VERSION 5.8 ;
BUSBITCHARS "[]" ;
DIVIDERCHAR "/" ;
UNITS
    DATABASE MICRONS 1000 ;
END UNITS

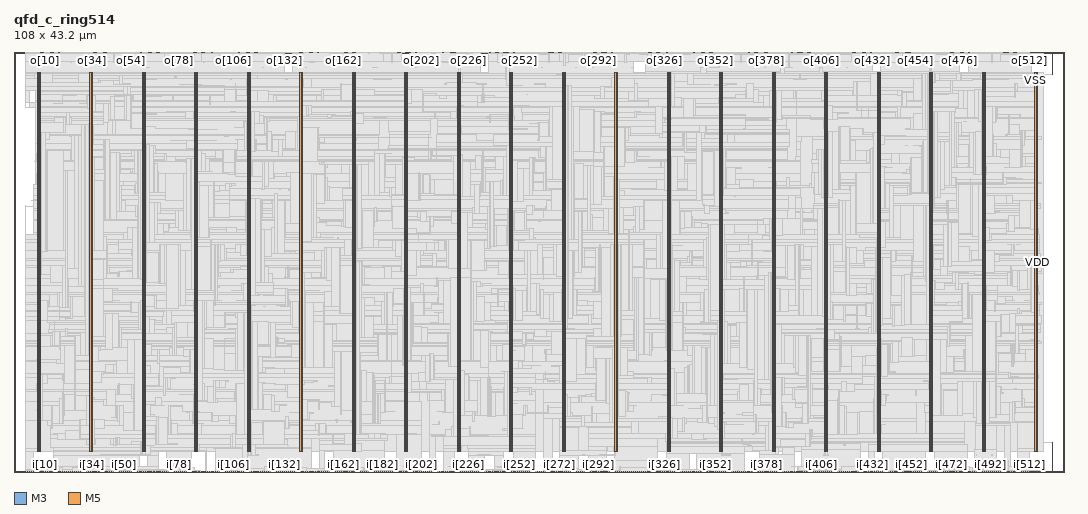
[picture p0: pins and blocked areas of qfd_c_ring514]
MACRO qfd_c_ring514
  FOREIGN qfd_c_ring514 0 0 ;
  CLASS BLOCK ;
  SIZE 108 BY 43.2 ;
  PIN ck_r
    DIRECTION INPUT ;
    USE SIGNAL ;
    PORT
      LAYER M3 ;
        RECT  105.984 43.162 106.002 43.2 ;
    END
    PORT
      LAYER M3 ;
        RECT  105.984 43.051 106.002 43.181 ;
    END
  END ck_r
  PIN ck_w
    DIRECTION INPUT ;
    USE SIGNAL ;
    PORT
      LAYER M3 ;
        RECT  105.984 0 106.002 0.038 ;
    END
    PORT
      LAYER M3 ;
        RECT  105.984 0.012 106.002 0.173 ;
    END
  END ck_w
  PIN i[0]
    DIRECTION INPUT ;
    USE SIGNAL ;
    PORT
      LAYER M3 ;
        RECT  1.188 0 1.206 0.038 ;
    END
  END i[0]
  PIN i[100]
    DIRECTION INPUT ;
    USE SIGNAL ;
    PORT
      LAYER M3 ;
        RECT  21.348 0 21.366 0.038 ;
    END
  END i[100]
  PIN i[101]
    DIRECTION INPUT ;
    USE SIGNAL ;
    PORT
      LAYER M5 ;
        RECT  21.552 0 21.576 0.084 ;
    END
  END i[101]
  PIN i[102]
    DIRECTION INPUT ;
    USE SIGNAL ;
    PORT
      LAYER M3 ;
        RECT  21.744 0 21.762 0.038 ;
    END
  END i[102]
  PIN i[103]
    DIRECTION INPUT ;
    USE SIGNAL ;
    PORT
      LAYER M5 ;
        RECT  21.936 0 21.96 0.084 ;
    END
  END i[103]
  PIN i[104]
    DIRECTION INPUT ;
    USE SIGNAL ;
    PORT
      LAYER M3 ;
        RECT  22.14 0 22.158 0.038 ;
    END
  END i[104]
  PIN i[105]
    DIRECTION INPUT ;
    USE SIGNAL ;
    PORT
      LAYER M5 ;
        RECT  22.368 0 22.392 0.084 ;
    END
  END i[105]
  PIN i[106]
    DIRECTION INPUT ;
    USE SIGNAL ;
    PORT
      LAYER M3 ;
        RECT  22.536 0 22.554 0.038 ;
    END
  END i[106]
  PIN i[107]
    DIRECTION INPUT ;
    USE SIGNAL ;
    PORT
      LAYER M5 ;
        RECT  22.752 0 22.776 0.084 ;
    END
  END i[107]
  PIN i[108]
    DIRECTION INPUT ;
    USE SIGNAL ;
    PORT
      LAYER M3 ;
        RECT  22.968 0 22.986 0.038 ;
    END
  END i[108]
  PIN i[109]
    DIRECTION INPUT ;
    USE SIGNAL ;
    PORT
      LAYER M5 ;
        RECT  23.136 0 23.16 0.084 ;
    END
  END i[109]
  PIN i[10]
    DIRECTION INPUT ;
    USE SIGNAL ;
    PORT
      LAYER M3 ;
        RECT  3.204 0 3.222 0.038 ;
    END
  END i[10]
  PIN i[110]
    DIRECTION INPUT ;
    USE SIGNAL ;
    PORT
      LAYER M3 ;
        RECT  23.364 0 23.382 0.038 ;
    END
  END i[110]
  PIN i[111]
    DIRECTION INPUT ;
    USE SIGNAL ;
    PORT
      LAYER M5 ;
        RECT  23.568 0 23.592 0.084 ;
    END
  END i[111]
  PIN i[112]
    DIRECTION INPUT ;
    USE SIGNAL ;
    PORT
      LAYER M3 ;
        RECT  23.76 0 23.778 0.038 ;
    END
  END i[112]
  PIN i[113]
    DIRECTION INPUT ;
    USE SIGNAL ;
    PORT
      LAYER M5 ;
        RECT  23.952 0 23.976 0.084 ;
    END
  END i[113]
  PIN i[114]
    DIRECTION INPUT ;
    USE SIGNAL ;
    PORT
      LAYER M3 ;
        RECT  24.156 0 24.174 0.038 ;
    END
  END i[114]
  PIN i[115]
    DIRECTION INPUT ;
    USE SIGNAL ;
    PORT
      LAYER M5 ;
        RECT  24.384 0 24.408 0.084 ;
    END
  END i[115]
  PIN i[116]
    DIRECTION INPUT ;
    USE SIGNAL ;
    PORT
      LAYER M3 ;
        RECT  24.588 0 24.606 0.038 ;
    END
  END i[116]
  PIN i[117]
    DIRECTION INPUT ;
    USE SIGNAL ;
    PORT
      LAYER M5 ;
        RECT  24.768 0 24.792 0.084 ;
    END
  END i[117]
  PIN i[118]
    DIRECTION INPUT ;
    USE SIGNAL ;
    PORT
      LAYER M3 ;
        RECT  24.984 0 25.002 0.038 ;
    END
  END i[118]
  PIN i[119]
    DIRECTION INPUT ;
    USE SIGNAL ;
    PORT
      LAYER M5 ;
        RECT  25.152 0 25.176 0.084 ;
    END
  END i[119]
  PIN i[11]
    DIRECTION INPUT ;
    USE SIGNAL ;
    PORT
      LAYER M5 ;
        RECT  3.408 0 3.432 0.084 ;
    END
  END i[11]
  PIN i[120]
    DIRECTION INPUT ;
    USE SIGNAL ;
    PORT
      LAYER M3 ;
        RECT  25.38 0 25.398 0.038 ;
    END
  END i[120]
  PIN i[121]
    DIRECTION INPUT ;
    USE SIGNAL ;
    PORT
      LAYER M5 ;
        RECT  25.584 0 25.608 0.084 ;
    END
  END i[121]
  PIN i[122]
    DIRECTION INPUT ;
    USE SIGNAL ;
    PORT
      LAYER M3 ;
        RECT  25.776 0 25.794 0.038 ;
    END
  END i[122]
  PIN i[123]
    DIRECTION INPUT ;
    USE SIGNAL ;
    PORT
      LAYER M5 ;
        RECT  25.968 0 25.992 0.084 ;
    END
  END i[123]
  PIN i[124]
    DIRECTION INPUT ;
    USE SIGNAL ;
    PORT
      LAYER M3 ;
        RECT  26.172 0 26.19 0.038 ;
    END
  END i[124]
  PIN i[125]
    DIRECTION INPUT ;
    USE SIGNAL ;
    PORT
      LAYER M5 ;
        RECT  26.4 0 26.424 0.084 ;
    END
  END i[125]
  PIN i[126]
    DIRECTION INPUT ;
    USE SIGNAL ;
    PORT
      LAYER M3 ;
        RECT  26.604 0 26.622 0.038 ;
    END
  END i[126]
  PIN i[127]
    DIRECTION INPUT ;
    USE SIGNAL ;
    PORT
      LAYER M5 ;
        RECT  26.784 0 26.808 0.084 ;
    END
  END i[127]
  PIN i[128]
    DIRECTION INPUT ;
    USE SIGNAL ;
    PORT
      LAYER M3 ;
        RECT  27 0 27.018 0.038 ;
    END
  END i[128]
  PIN i[129]
    DIRECTION INPUT ;
    USE SIGNAL ;
    PORT
      LAYER M5 ;
        RECT  27.168 0 27.192 0.084 ;
    END
  END i[129]
  PIN i[12]
    DIRECTION INPUT ;
    USE SIGNAL ;
    PORT
      LAYER M3 ;
        RECT  3.6 0 3.618 0.038 ;
    END
  END i[12]
  PIN i[130]
    DIRECTION INPUT ;
    USE SIGNAL ;
    PORT
      LAYER M3 ;
        RECT  27.396 0 27.414 0.038 ;
    END
  END i[130]
  PIN i[131]
    DIRECTION INPUT ;
    USE SIGNAL ;
    PORT
      LAYER M5 ;
        RECT  27.6 0 27.624 0.084 ;
    END
  END i[131]
  PIN i[132]
    DIRECTION INPUT ;
    USE SIGNAL ;
    PORT
      LAYER M3 ;
        RECT  27.792 0 27.81 0.038 ;
    END
  END i[132]
  PIN i[133]
    DIRECTION INPUT ;
    USE SIGNAL ;
    PORT
      LAYER M5 ;
        RECT  27.984 0 28.008 0.084 ;
    END
  END i[133]
  PIN i[134]
    DIRECTION INPUT ;
    USE SIGNAL ;
    PORT
      LAYER M3 ;
        RECT  28.188 0 28.206 0.038 ;
    END
  END i[134]
  PIN i[135]
    DIRECTION INPUT ;
    USE SIGNAL ;
    PORT
      LAYER M5 ;
        RECT  28.416 0 28.44 0.084 ;
    END
  END i[135]
  PIN i[136]
    DIRECTION INPUT ;
    USE SIGNAL ;
    PORT
      LAYER M3 ;
        RECT  28.62 0 28.638 0.038 ;
    END
  END i[136]
  PIN i[137]
    DIRECTION INPUT ;
    USE SIGNAL ;
    PORT
      LAYER M5 ;
        RECT  28.8 0 28.824 0.084 ;
    END
  END i[137]
  PIN i[138]
    DIRECTION INPUT ;
    USE SIGNAL ;
    PORT
      LAYER M3 ;
        RECT  29.016 0 29.034 0.038 ;
    END
  END i[138]
  PIN i[139]
    DIRECTION INPUT ;
    USE SIGNAL ;
    PORT
      LAYER M5 ;
        RECT  29.184 0 29.208 0.084 ;
    END
  END i[139]
  PIN i[13]
    DIRECTION INPUT ;
    USE SIGNAL ;
    PORT
      LAYER M5 ;
        RECT  3.792 0 3.816 0.084 ;
    END
  END i[13]
  PIN i[140]
    DIRECTION INPUT ;
    USE SIGNAL ;
    PORT
      LAYER M3 ;
        RECT  29.412 0 29.43 0.038 ;
    END
  END i[140]
  PIN i[141]
    DIRECTION INPUT ;
    USE SIGNAL ;
    PORT
      LAYER M5 ;
        RECT  29.616 0 29.64 0.084 ;
    END
  END i[141]
  PIN i[142]
    DIRECTION INPUT ;
    USE SIGNAL ;
    PORT
      LAYER M3 ;
        RECT  29.808 0 29.826 0.038 ;
    END
  END i[142]
  PIN i[143]
    DIRECTION INPUT ;
    USE SIGNAL ;
    PORT
      LAYER M5 ;
        RECT  30 0 30.024 0.084 ;
    END
  END i[143]
  PIN i[144]
    DIRECTION INPUT ;
    USE SIGNAL ;
    PORT
      LAYER M3 ;
        RECT  30.204 0 30.222 0.038 ;
    END
  END i[144]
  PIN i[145]
    DIRECTION INPUT ;
    USE SIGNAL ;
    PORT
      LAYER M5 ;
        RECT  30.432 0 30.456 0.084 ;
    END
  END i[145]
  PIN i[146]
    DIRECTION INPUT ;
    USE SIGNAL ;
    PORT
      LAYER M3 ;
        RECT  30.636 0 30.654 0.038 ;
    END
  END i[146]
  PIN i[147]
    DIRECTION INPUT ;
    USE SIGNAL ;
    PORT
      LAYER M5 ;
        RECT  30.816 0 30.84 0.084 ;
    END
  END i[147]
  PIN i[148]
    DIRECTION INPUT ;
    USE SIGNAL ;
    PORT
      LAYER M3 ;
        RECT  31.032 0 31.05 0.038 ;
    END
  END i[148]
  PIN i[149]
    DIRECTION INPUT ;
    USE SIGNAL ;
    PORT
      LAYER M5 ;
        RECT  31.248 0 31.272 0.084 ;
    END
  END i[149]
  PIN i[14]
    DIRECTION INPUT ;
    USE SIGNAL ;
    PORT
      LAYER M3 ;
        RECT  3.996 0 4.014 0.038 ;
    END
  END i[14]
  PIN i[150]
    DIRECTION INPUT ;
    USE SIGNAL ;
    PORT
      LAYER M3 ;
        RECT  31.428 0 31.446 0.038 ;
    END
  END i[150]
  PIN i[151]
    DIRECTION INPUT ;
    USE SIGNAL ;
    PORT
      LAYER M5 ;
        RECT  31.632 0 31.656 0.084 ;
    END
  END i[151]
  PIN i[152]
    DIRECTION INPUT ;
    USE SIGNAL ;
    PORT
      LAYER M3 ;
        RECT  31.824 0 31.842 0.038 ;
    END
  END i[152]
  PIN i[153]
    DIRECTION INPUT ;
    USE SIGNAL ;
    PORT
      LAYER M5 ;
        RECT  32.016 0 32.04 0.084 ;
    END
  END i[153]
  PIN i[154]
    DIRECTION INPUT ;
    USE SIGNAL ;
    PORT
      LAYER M3 ;
        RECT  32.22 0 32.238 0.038 ;
    END
  END i[154]
  PIN i[155]
    DIRECTION INPUT ;
    USE SIGNAL ;
    PORT
      LAYER M5 ;
        RECT  32.448 0 32.472 0.084 ;
    END
  END i[155]
  PIN i[156]
    DIRECTION INPUT ;
    USE SIGNAL ;
    PORT
      LAYER M3 ;
        RECT  32.652 0 32.67 0.038 ;
    END
  END i[156]
  PIN i[157]
    DIRECTION INPUT ;
    USE SIGNAL ;
    PORT
      LAYER M5 ;
        RECT  32.832 0 32.856 0.084 ;
    END
  END i[157]
  PIN i[158]
    DIRECTION INPUT ;
    USE SIGNAL ;
    PORT
      LAYER M3 ;
        RECT  33.048 0 33.066 0.038 ;
    END
  END i[158]
  PIN i[159]
    DIRECTION INPUT ;
    USE SIGNAL ;
    PORT
      LAYER M5 ;
        RECT  33.264 0 33.288 0.084 ;
    END
  END i[159]
  PIN i[15]
    DIRECTION INPUT ;
    USE SIGNAL ;
    PORT
      LAYER M5 ;
        RECT  4.176 0 4.2 0.084 ;
    END
  END i[15]
  PIN i[160]
    DIRECTION INPUT ;
    USE SIGNAL ;
    PORT
      LAYER M3 ;
        RECT  33.444 0 33.462 0.038 ;
    END
  END i[160]
  PIN i[161]
    DIRECTION INPUT ;
    USE SIGNAL ;
    PORT
      LAYER M5 ;
        RECT  33.648 0 33.672 0.084 ;
    END
  END i[161]
  PIN i[162]
    DIRECTION INPUT ;
    USE SIGNAL ;
    PORT
      LAYER M3 ;
        RECT  33.84 0 33.858 0.038 ;
    END
  END i[162]
  PIN i[163]
    DIRECTION INPUT ;
    USE SIGNAL ;
    PORT
      LAYER M5 ;
        RECT  34.032 0 34.056 0.084 ;
    END
  END i[163]
  PIN i[164]
    DIRECTION INPUT ;
    USE SIGNAL ;
    PORT
      LAYER M3 ;
        RECT  34.236 0 34.254 0.038 ;
    END
  END i[164]
  PIN i[165]
    DIRECTION INPUT ;
    USE SIGNAL ;
    PORT
      LAYER M5 ;
        RECT  34.464 0 34.488 0.084 ;
    END
  END i[165]
  PIN i[166]
    DIRECTION INPUT ;
    USE SIGNAL ;
    PORT
      LAYER M3 ;
        RECT  34.668 0 34.686 0.038 ;
    END
  END i[166]
  PIN i[167]
    DIRECTION INPUT ;
    USE SIGNAL ;
    PORT
      LAYER M5 ;
        RECT  34.848 0 34.872 0.084 ;
    END
  END i[167]
  PIN i[168]
    DIRECTION INPUT ;
    USE SIGNAL ;
    PORT
      LAYER M3 ;
        RECT  35.064 0 35.082 0.038 ;
    END
  END i[168]
  PIN i[169]
    DIRECTION INPUT ;
    USE SIGNAL ;
    PORT
      LAYER M5 ;
        RECT  35.28 0 35.304 0.084 ;
    END
  END i[169]
  PIN i[16]
    DIRECTION INPUT ;
    USE SIGNAL ;
    PORT
      LAYER M3 ;
        RECT  4.392 0 4.41 0.038 ;
    END
  END i[16]
  PIN i[170]
    DIRECTION INPUT ;
    USE SIGNAL ;
    PORT
      LAYER M3 ;
        RECT  35.46 0 35.478 0.038 ;
    END
  END i[170]
  PIN i[171]
    DIRECTION INPUT ;
    USE SIGNAL ;
    PORT
      LAYER M5 ;
        RECT  35.664 0 35.688 0.084 ;
    END
  END i[171]
  PIN i[172]
    DIRECTION INPUT ;
    USE SIGNAL ;
    PORT
      LAYER M3 ;
        RECT  35.856 0 35.874 0.038 ;
    END
  END i[172]
  PIN i[173]
    DIRECTION INPUT ;
    USE SIGNAL ;
    PORT
      LAYER M5 ;
        RECT  36.048 0 36.072 0.084 ;
    END
  END i[173]
  PIN i[174]
    DIRECTION INPUT ;
    USE SIGNAL ;
    PORT
      LAYER M3 ;
        RECT  36.288 0 36.306 0.038 ;
    END
  END i[174]
  PIN i[175]
    DIRECTION INPUT ;
    USE SIGNAL ;
    PORT
      LAYER M5 ;
        RECT  36.48 0 36.504 0.084 ;
    END
  END i[175]
  PIN i[176]
    DIRECTION INPUT ;
    USE SIGNAL ;
    PORT
      LAYER M3 ;
        RECT  36.684 0 36.702 0.038 ;
    END
  END i[176]
  PIN i[177]
    DIRECTION INPUT ;
    USE SIGNAL ;
    PORT
      LAYER M5 ;
        RECT  36.864 0 36.888 0.084 ;
    END
  END i[177]
  PIN i[178]
    DIRECTION INPUT ;
    USE SIGNAL ;
    PORT
      LAYER M3 ;
        RECT  37.08 0 37.098 0.038 ;
    END
  END i[178]
  PIN i[179]
    DIRECTION INPUT ;
    USE SIGNAL ;
    PORT
      LAYER M5 ;
        RECT  37.296 0 37.32 0.084 ;
    END
  END i[179]
  PIN i[17]
    DIRECTION INPUT ;
    USE SIGNAL ;
    PORT
      LAYER M5 ;
        RECT  4.608 0 4.632 0.084 ;
    END
  END i[17]
  PIN i[180]
    DIRECTION INPUT ;
    USE SIGNAL ;
    PORT
      LAYER M3 ;
        RECT  37.476 0 37.494 0.038 ;
    END
  END i[180]
  PIN i[181]
    DIRECTION INPUT ;
    USE SIGNAL ;
    PORT
      LAYER M5 ;
        RECT  37.68 0 37.704 0.084 ;
    END
  END i[181]
  PIN i[182]
    DIRECTION INPUT ;
    USE SIGNAL ;
    PORT
      LAYER M3 ;
        RECT  37.872 0 37.89 0.038 ;
    END
  END i[182]
  PIN i[183]
    DIRECTION INPUT ;
    USE SIGNAL ;
    PORT
      LAYER M5 ;
        RECT  38.064 0 38.088 0.084 ;
    END
  END i[183]
  PIN i[184]
    DIRECTION INPUT ;
    USE SIGNAL ;
    PORT
      LAYER M3 ;
        RECT  38.304 0 38.322 0.038 ;
    END
  END i[184]
  PIN i[185]
    DIRECTION INPUT ;
    USE SIGNAL ;
    PORT
      LAYER M5 ;
        RECT  38.496 0 38.52 0.084 ;
    END
  END i[185]
  PIN i[186]
    DIRECTION INPUT ;
    USE SIGNAL ;
    PORT
      LAYER M3 ;
        RECT  38.7 0 38.718 0.038 ;
    END
  END i[186]
  PIN i[187]
    DIRECTION INPUT ;
    USE SIGNAL ;
    PORT
      LAYER M5 ;
        RECT  38.88 0 38.904 0.084 ;
    END
  END i[187]
  PIN i[188]
    DIRECTION INPUT ;
    USE SIGNAL ;
    PORT
      LAYER M3 ;
        RECT  39.096 0 39.114 0.038 ;
    END
  END i[188]
  PIN i[189]
    DIRECTION INPUT ;
    USE SIGNAL ;
    PORT
      LAYER M5 ;
        RECT  39.312 0 39.336 0.084 ;
    END
  END i[189]
  PIN i[18]
    DIRECTION INPUT ;
    USE SIGNAL ;
    PORT
      LAYER M3 ;
        RECT  4.788 0 4.806 0.038 ;
    END
  END i[18]
  PIN i[190]
    DIRECTION INPUT ;
    USE SIGNAL ;
    PORT
      LAYER M3 ;
        RECT  39.492 0 39.51 0.038 ;
    END
  END i[190]
  PIN i[191]
    DIRECTION INPUT ;
    USE SIGNAL ;
    PORT
      LAYER M5 ;
        RECT  39.696 0 39.72 0.084 ;
    END
  END i[191]
  PIN i[192]
    DIRECTION INPUT ;
    USE SIGNAL ;
    PORT
      LAYER M3 ;
        RECT  39.888 0 39.906 0.038 ;
    END
  END i[192]
  PIN i[193]
    DIRECTION INPUT ;
    USE SIGNAL ;
    PORT
      LAYER M5 ;
        RECT  40.08 0 40.104 0.084 ;
    END
  END i[193]
  PIN i[194]
    DIRECTION INPUT ;
    USE SIGNAL ;
    PORT
      LAYER M3 ;
        RECT  40.32 0 40.338 0.038 ;
    END
  END i[194]
  PIN i[195]
    DIRECTION INPUT ;
    USE SIGNAL ;
    PORT
      LAYER M5 ;
        RECT  40.512 0 40.536 0.084 ;
    END
  END i[195]
  PIN i[196]
    DIRECTION INPUT ;
    USE SIGNAL ;
    PORT
      LAYER M3 ;
        RECT  40.716 0 40.734 0.038 ;
    END
  END i[196]
  PIN i[197]
    DIRECTION INPUT ;
    USE SIGNAL ;
    PORT
      LAYER M5 ;
        RECT  40.896 0 40.92 0.084 ;
    END
  END i[197]
  PIN i[198]
    DIRECTION INPUT ;
    USE SIGNAL ;
    PORT
      LAYER M3 ;
        RECT  41.112 0 41.13 0.038 ;
    END
  END i[198]
  PIN i[199]
    DIRECTION INPUT ;
    USE SIGNAL ;
    PORT
      LAYER M5 ;
        RECT  41.328 0 41.352 0.084 ;
    END
  END i[199]
  PIN i[19]
    DIRECTION INPUT ;
    USE SIGNAL ;
    PORT
      LAYER M5 ;
        RECT  4.992 0 5.016 0.084 ;
    END
  END i[19]
  PIN i[1]
    DIRECTION INPUT ;
    USE SIGNAL ;
    PORT
      LAYER M5 ;
        RECT  1.392 0 1.416 0.084 ;
    END
  END i[1]
  PIN i[200]
    DIRECTION INPUT ;
    USE SIGNAL ;
    PORT
      LAYER M3 ;
        RECT  41.508 0 41.526 0.038 ;
    END
  END i[200]
  PIN i[201]
    DIRECTION INPUT ;
    USE SIGNAL ;
    PORT
      LAYER M5 ;
        RECT  41.712 0 41.736 0.084 ;
    END
  END i[201]
  PIN i[202]
    DIRECTION INPUT ;
    USE SIGNAL ;
    PORT
      LAYER M3 ;
        RECT  41.904 0 41.922 0.038 ;
    END
  END i[202]
  PIN i[203]
    DIRECTION INPUT ;
    USE SIGNAL ;
    PORT
      LAYER M5 ;
        RECT  42.096 0 42.12 0.084 ;
    END
  END i[203]
  PIN i[204]
    DIRECTION INPUT ;
    USE SIGNAL ;
    PORT
      LAYER M3 ;
        RECT  42.336 0 42.354 0.038 ;
    END
  END i[204]
  PIN i[205]
    DIRECTION INPUT ;
    USE SIGNAL ;
    PORT
      LAYER M5 ;
        RECT  42.528 0 42.552 0.084 ;
    END
  END i[205]
  PIN i[206]
    DIRECTION INPUT ;
    USE SIGNAL ;
    PORT
      LAYER M3 ;
        RECT  42.732 0 42.75 0.038 ;
    END
  END i[206]
  PIN i[207]
    DIRECTION INPUT ;
    USE SIGNAL ;
    PORT
      LAYER M5 ;
        RECT  42.912 0 42.936 0.084 ;
    END
  END i[207]
  PIN i[208]
    DIRECTION INPUT ;
    USE SIGNAL ;
    PORT
      LAYER M3 ;
        RECT  43.128 0 43.146 0.038 ;
    END
  END i[208]
  PIN i[209]
    DIRECTION INPUT ;
    USE SIGNAL ;
    PORT
      LAYER M5 ;
        RECT  43.344 0 43.368 0.084 ;
    END
  END i[209]
  PIN i[20]
    DIRECTION INPUT ;
    USE SIGNAL ;
    PORT
      LAYER M3 ;
        RECT  5.22 0 5.238 0.038 ;
    END
  END i[20]
  PIN i[210]
    DIRECTION INPUT ;
    USE SIGNAL ;
    PORT
      LAYER M3 ;
        RECT  43.524 0 43.542 0.038 ;
    END
  END i[210]
  PIN i[211]
    DIRECTION INPUT ;
    USE SIGNAL ;
    PORT
      LAYER M5 ;
        RECT  43.728 0 43.752 0.084 ;
    END
  END i[211]
  PIN i[212]
    DIRECTION INPUT ;
    USE SIGNAL ;
    PORT
      LAYER M3 ;
        RECT  43.92 0 43.938 0.038 ;
    END
  END i[212]
  PIN i[213]
    DIRECTION INPUT ;
    USE SIGNAL ;
    PORT
      LAYER M5 ;
        RECT  44.112 0 44.136 0.084 ;
    END
  END i[213]
  PIN i[214]
    DIRECTION INPUT ;
    USE SIGNAL ;
    PORT
      LAYER M3 ;
        RECT  44.352 0 44.37 0.038 ;
    END
  END i[214]
  PIN i[215]
    DIRECTION INPUT ;
    USE SIGNAL ;
    PORT
      LAYER M5 ;
        RECT  44.544 0 44.568 0.084 ;
    END
  END i[215]
  PIN i[216]
    DIRECTION INPUT ;
    USE SIGNAL ;
    PORT
      LAYER M3 ;
        RECT  44.748 0 44.766 0.038 ;
    END
  END i[216]
  PIN i[217]
    DIRECTION INPUT ;
    USE SIGNAL ;
    PORT
      LAYER M5 ;
        RECT  44.928 0 44.952 0.084 ;
    END
  END i[217]
  PIN i[218]
    DIRECTION INPUT ;
    USE SIGNAL ;
    PORT
      LAYER M3 ;
        RECT  45.144 0 45.162 0.038 ;
    END
  END i[218]
  PIN i[219]
    DIRECTION INPUT ;
    USE SIGNAL ;
    PORT
      LAYER M5 ;
        RECT  45.36 0 45.384 0.084 ;
    END
  END i[219]
  PIN i[21]
    DIRECTION INPUT ;
    USE SIGNAL ;
    PORT
      LAYER M5 ;
        RECT  5.424 0 5.448 0.084 ;
    END
  END i[21]
  PIN i[220]
    DIRECTION INPUT ;
    USE SIGNAL ;
    PORT
      LAYER M3 ;
        RECT  45.54 0 45.558 0.038 ;
    END
  END i[220]
  PIN i[221]
    DIRECTION INPUT ;
    USE SIGNAL ;
    PORT
      LAYER M5 ;
        RECT  45.744 0 45.768 0.084 ;
    END
  END i[221]
  PIN i[222]
    DIRECTION INPUT ;
    USE SIGNAL ;
    PORT
      LAYER M3 ;
        RECT  45.936 0 45.954 0.038 ;
    END
  END i[222]
  PIN i[223]
    DIRECTION INPUT ;
    USE SIGNAL ;
    PORT
      LAYER M5 ;
        RECT  46.128 0 46.152 0.084 ;
    END
  END i[223]
  PIN i[224]
    DIRECTION INPUT ;
    USE SIGNAL ;
    PORT
      LAYER M3 ;
        RECT  46.368 0 46.386 0.038 ;
    END
  END i[224]
  PIN i[225]
    DIRECTION INPUT ;
    USE SIGNAL ;
    PORT
      LAYER M5 ;
        RECT  46.56 0 46.584 0.084 ;
    END
  END i[225]
  PIN i[226]
    DIRECTION INPUT ;
    USE SIGNAL ;
    PORT
      LAYER M3 ;
        RECT  46.764 0 46.782 0.038 ;
    END
  END i[226]
  PIN i[227]
    DIRECTION INPUT ;
    USE SIGNAL ;
    PORT
      LAYER M5 ;
        RECT  46.944 0 46.968 0.084 ;
    END
  END i[227]
  PIN i[228]
    DIRECTION INPUT ;
    USE SIGNAL ;
    PORT
      LAYER M3 ;
        RECT  47.16 0 47.178 0.038 ;
    END
  END i[228]
  PIN i[229]
    DIRECTION INPUT ;
    USE SIGNAL ;
    PORT
      LAYER M5 ;
        RECT  47.376 0 47.4 0.084 ;
    END
  END i[229]
  PIN i[22]
    DIRECTION INPUT ;
    USE SIGNAL ;
    PORT
      LAYER M3 ;
        RECT  5.616 0 5.634 0.038 ;
    END
  END i[22]
  PIN i[230]
    DIRECTION INPUT ;
    USE SIGNAL ;
    PORT
      LAYER M3 ;
        RECT  47.556 0 47.574 0.038 ;
    END
  END i[230]
  PIN i[231]
    DIRECTION INPUT ;
    USE SIGNAL ;
    PORT
      LAYER M5 ;
        RECT  47.76 0 47.784 0.084 ;
    END
  END i[231]
  PIN i[232]
    DIRECTION INPUT ;
    USE SIGNAL ;
    PORT
      LAYER M3 ;
        RECT  47.952 0 47.97 0.038 ;
    END
  END i[232]
  PIN i[233]
    DIRECTION INPUT ;
    USE SIGNAL ;
    PORT
      LAYER M5 ;
        RECT  48.192 0 48.216 0.084 ;
    END
  END i[233]
  PIN i[234]
    DIRECTION INPUT ;
    USE SIGNAL ;
    PORT
      LAYER M3 ;
        RECT  48.384 0 48.402 0.038 ;
    END
  END i[234]
  PIN i[235]
    DIRECTION INPUT ;
    USE SIGNAL ;
    PORT
      LAYER M5 ;
        RECT  48.576 0 48.6 0.084 ;
    END
  END i[235]
  PIN i[236]
    DIRECTION INPUT ;
    USE SIGNAL ;
    PORT
      LAYER M3 ;
        RECT  48.78 0 48.798 0.038 ;
    END
  END i[236]
  PIN i[237]
    DIRECTION INPUT ;
    USE SIGNAL ;
    PORT
      LAYER M5 ;
        RECT  48.96 0 48.984 0.084 ;
    END
  END i[237]
  PIN i[238]
    DIRECTION INPUT ;
    USE SIGNAL ;
    PORT
      LAYER M3 ;
        RECT  49.176 0 49.194 0.038 ;
    END
  END i[238]
  PIN i[239]
    DIRECTION INPUT ;
    USE SIGNAL ;
    PORT
      LAYER M5 ;
        RECT  49.392 0 49.416 0.084 ;
    END
  END i[239]
  PIN i[23]
    DIRECTION INPUT ;
    USE SIGNAL ;
    PORT
      LAYER M5 ;
        RECT  5.808 0 5.832 0.084 ;
    END
  END i[23]
  PIN i[240]
    DIRECTION INPUT ;
    USE SIGNAL ;
    PORT
      LAYER M3 ;
        RECT  49.572 0 49.59 0.038 ;
    END
  END i[240]
  PIN i[241]
    DIRECTION INPUT ;
    USE SIGNAL ;
    PORT
      LAYER M5 ;
        RECT  49.776 0 49.8 0.084 ;
    END
  END i[241]
  PIN i[242]
    DIRECTION INPUT ;
    USE SIGNAL ;
    PORT
      LAYER M3 ;
        RECT  50.004 0 50.022 0.038 ;
    END
  END i[242]
  PIN i[243]
    DIRECTION INPUT ;
    USE SIGNAL ;
    PORT
      LAYER M5 ;
        RECT  50.208 0 50.232 0.084 ;
    END
  END i[243]
  PIN i[244]
    DIRECTION INPUT ;
    USE SIGNAL ;
    PORT
      LAYER M3 ;
        RECT  50.4 0 50.418 0.038 ;
    END
  END i[244]
  PIN i[245]
    DIRECTION INPUT ;
    USE SIGNAL ;
    PORT
      LAYER M5 ;
        RECT  50.592 0 50.616 0.084 ;
    END
  END i[245]
  PIN i[246]
    DIRECTION INPUT ;
    USE SIGNAL ;
    PORT
      LAYER M3 ;
        RECT  50.796 0 50.814 0.038 ;
    END
  END i[246]
  PIN i[247]
    DIRECTION INPUT ;
    USE SIGNAL ;
    PORT
      LAYER M5 ;
        RECT  50.976 0 51 0.084 ;
    END
  END i[247]
  PIN i[248]
    DIRECTION INPUT ;
    USE SIGNAL ;
    PORT
      LAYER M3 ;
        RECT  51.192 0 51.21 0.038 ;
    END
  END i[248]
  PIN i[249]
    DIRECTION INPUT ;
    USE SIGNAL ;
    PORT
      LAYER M5 ;
        RECT  51.408 0 51.432 0.084 ;
    END
  END i[249]
  PIN i[24]
    DIRECTION INPUT ;
    USE SIGNAL ;
    PORT
      LAYER M3 ;
        RECT  6.012 0 6.03 0.038 ;
    END
  END i[24]
  PIN i[250]
    DIRECTION INPUT ;
    USE SIGNAL ;
    PORT
      LAYER M3 ;
        RECT  51.588 0 51.606 0.038 ;
    END
  END i[250]
  PIN i[251]
    DIRECTION INPUT ;
    USE SIGNAL ;
    PORT
      LAYER M5 ;
        RECT  51.792 0 51.816 0.084 ;
    END
  END i[251]
  PIN i[252]
    DIRECTION INPUT ;
    USE SIGNAL ;
    PORT
      LAYER M3 ;
        RECT  52.02 0 52.038 0.038 ;
    END
  END i[252]
  PIN i[253]
    DIRECTION INPUT ;
    USE SIGNAL ;
    PORT
      LAYER M5 ;
        RECT  52.224 0 52.248 0.084 ;
    END
  END i[253]
  PIN i[254]
    DIRECTION INPUT ;
    USE SIGNAL ;
    PORT
      LAYER M3 ;
        RECT  52.416 0 52.434 0.038 ;
    END
  END i[254]
  PIN i[255]
    DIRECTION INPUT ;
    USE SIGNAL ;
    PORT
      LAYER M5 ;
        RECT  52.608 0 52.632 0.084 ;
    END
  END i[255]
  PIN i[256]
    DIRECTION INPUT ;
    USE SIGNAL ;
    PORT
      LAYER M3 ;
        RECT  52.812 0 52.83 0.038 ;
    END
  END i[256]
  PIN i[257]
    DIRECTION INPUT ;
    USE SIGNAL ;
    PORT
      LAYER M5 ;
        RECT  52.992 0 53.016 0.084 ;
    END
  END i[257]
  PIN i[258]
    DIRECTION INPUT ;
    USE SIGNAL ;
    PORT
      LAYER M3 ;
        RECT  53.208 0 53.226 0.038 ;
    END
  END i[258]
  PIN i[259]
    DIRECTION INPUT ;
    USE SIGNAL ;
    PORT
      LAYER M5 ;
        RECT  53.424 0 53.448 0.084 ;
    END
  END i[259]
  PIN i[25]
    DIRECTION INPUT ;
    USE SIGNAL ;
    PORT
      LAYER M5 ;
        RECT  6.192 0 6.216 0.084 ;
    END
  END i[25]
  PIN i[260]
    DIRECTION INPUT ;
    USE SIGNAL ;
    PORT
      LAYER M3 ;
        RECT  53.604 0 53.622 0.038 ;
    END
  END i[260]
  PIN i[261]
    DIRECTION INPUT ;
    USE SIGNAL ;
    PORT
      LAYER M5 ;
        RECT  53.808 0 53.832 0.084 ;
    END
  END i[261]
  PIN i[262]
    DIRECTION INPUT ;
    USE SIGNAL ;
    PORT
      LAYER M3 ;
        RECT  54.036 0 54.054 0.038 ;
    END
  END i[262]
  PIN i[263]
    DIRECTION INPUT ;
    USE SIGNAL ;
    PORT
      LAYER M5 ;
        RECT  54.24 0 54.264 0.084 ;
    END
  END i[263]
  PIN i[264]
    DIRECTION INPUT ;
    USE SIGNAL ;
    PORT
      LAYER M3 ;
        RECT  54.432 0 54.45 0.038 ;
    END
  END i[264]
  PIN i[265]
    DIRECTION INPUT ;
    USE SIGNAL ;
    PORT
      LAYER M5 ;
        RECT  54.624 0 54.648 0.084 ;
    END
  END i[265]
  PIN i[266]
    DIRECTION INPUT ;
    USE SIGNAL ;
    PORT
      LAYER M3 ;
        RECT  54.828 0 54.846 0.038 ;
    END
  END i[266]
  PIN i[267]
    DIRECTION INPUT ;
    USE SIGNAL ;
    PORT
      LAYER M5 ;
        RECT  55.008 0 55.032 0.084 ;
    END
  END i[267]
  PIN i[268]
    DIRECTION INPUT ;
    USE SIGNAL ;
    PORT
      LAYER M3 ;
        RECT  55.224 0 55.242 0.038 ;
    END
  END i[268]
  PIN i[269]
    DIRECTION INPUT ;
    USE SIGNAL ;
    PORT
      LAYER M5 ;
        RECT  55.44 0 55.464 0.084 ;
    END
  END i[269]
  PIN i[26]
    DIRECTION INPUT ;
    USE SIGNAL ;
    PORT
      LAYER M3 ;
        RECT  6.408 0 6.426 0.038 ;
    END
  END i[26]
  PIN i[270]
    DIRECTION INPUT ;
    USE SIGNAL ;
    PORT
      LAYER M3 ;
        RECT  55.62 0 55.638 0.038 ;
    END
  END i[270]
  PIN i[271]
    DIRECTION INPUT ;
    USE SIGNAL ;
    PORT
      LAYER M5 ;
        RECT  55.824 0 55.848 0.084 ;
    END
  END i[271]
  PIN i[272]
    DIRECTION INPUT ;
    USE SIGNAL ;
    PORT
      LAYER M3 ;
        RECT  56.052 0 56.07 0.038 ;
    END
  END i[272]
  PIN i[273]
    DIRECTION INPUT ;
    USE SIGNAL ;
    PORT
      LAYER M5 ;
        RECT  56.256 0 56.28 0.084 ;
    END
  END i[273]
  PIN i[274]
    DIRECTION INPUT ;
    USE SIGNAL ;
    PORT
      LAYER M3 ;
        RECT  56.448 0 56.466 0.038 ;
    END
  END i[274]
  PIN i[275]
    DIRECTION INPUT ;
    USE SIGNAL ;
    PORT
      LAYER M5 ;
        RECT  56.64 0 56.664 0.084 ;
    END
  END i[275]
  PIN i[276]
    DIRECTION INPUT ;
    USE SIGNAL ;
    PORT
      LAYER M3 ;
        RECT  56.844 0 56.862 0.038 ;
    END
  END i[276]
  PIN i[277]
    DIRECTION INPUT ;
    USE SIGNAL ;
    PORT
      LAYER M5 ;
        RECT  57.024 0 57.048 0.084 ;
    END
  END i[277]
  PIN i[278]
    DIRECTION INPUT ;
    USE SIGNAL ;
    PORT
      LAYER M3 ;
        RECT  57.24 0 57.258 0.038 ;
    END
  END i[278]
  PIN i[279]
    DIRECTION INPUT ;
    USE SIGNAL ;
    PORT
      LAYER M5 ;
        RECT  57.456 0 57.48 0.084 ;
    END
  END i[279]
  PIN i[27]
    DIRECTION INPUT ;
    USE SIGNAL ;
    PORT
      LAYER M5 ;
        RECT  6.624 0 6.648 0.084 ;
    END
  END i[27]
  PIN i[280]
    DIRECTION INPUT ;
    USE SIGNAL ;
    PORT
      LAYER M3 ;
        RECT  57.636 0 57.654 0.038 ;
    END
  END i[280]
  PIN i[281]
    DIRECTION INPUT ;
    USE SIGNAL ;
    PORT
      LAYER M5 ;
        RECT  57.84 0 57.864 0.084 ;
    END
  END i[281]
  PIN i[282]
    DIRECTION INPUT ;
    USE SIGNAL ;
    PORT
      LAYER M3 ;
        RECT  58.068 0 58.086 0.038 ;
    END
  END i[282]
  PIN i[283]
    DIRECTION INPUT ;
    USE SIGNAL ;
    PORT
      LAYER M5 ;
        RECT  58.272 0 58.296 0.084 ;
    END
  END i[283]
  PIN i[284]
    DIRECTION INPUT ;
    USE SIGNAL ;
    PORT
      LAYER M3 ;
        RECT  58.464 0 58.482 0.038 ;
    END
  END i[284]
  PIN i[285]
    DIRECTION INPUT ;
    USE SIGNAL ;
    PORT
      LAYER M5 ;
        RECT  58.656 0 58.68 0.084 ;
    END
  END i[285]
  PIN i[286]
    DIRECTION INPUT ;
    USE SIGNAL ;
    PORT
      LAYER M3 ;
        RECT  58.86 0 58.878 0.038 ;
    END
  END i[286]
  PIN i[287]
    DIRECTION INPUT ;
    USE SIGNAL ;
    PORT
      LAYER M5 ;
        RECT  59.04 0 59.064 0.084 ;
    END
  END i[287]
  PIN i[288]
    DIRECTION INPUT ;
    USE SIGNAL ;
    PORT
      LAYER M3 ;
        RECT  59.256 0 59.274 0.038 ;
    END
  END i[288]
  PIN i[289]
    DIRECTION INPUT ;
    USE SIGNAL ;
    PORT
      LAYER M5 ;
        RECT  59.472 0 59.496 0.084 ;
    END
  END i[289]
  PIN i[28]
    DIRECTION INPUT ;
    USE SIGNAL ;
    PORT
      LAYER M3 ;
        RECT  6.804 0 6.822 0.038 ;
    END
  END i[28]
  PIN i[290]
    DIRECTION INPUT ;
    USE SIGNAL ;
    PORT
      LAYER M3 ;
        RECT  59.652 0 59.67 0.038 ;
    END
  END i[290]
  PIN i[291]
    DIRECTION INPUT ;
    USE SIGNAL ;
    PORT
      LAYER M5 ;
        RECT  59.856 0 59.88 0.084 ;
    END
  END i[291]
  PIN i[292]
    DIRECTION INPUT ;
    USE SIGNAL ;
    PORT
      LAYER M3 ;
        RECT  60.084 0 60.102 0.038 ;
    END
  END i[292]
  PIN i[293]
    DIRECTION INPUT ;
    USE SIGNAL ;
    PORT
      LAYER M5 ;
        RECT  60.288 0 60.312 0.084 ;
    END
  END i[293]
  PIN i[294]
    DIRECTION INPUT ;
    USE SIGNAL ;
    PORT
      LAYER M3 ;
        RECT  60.48 0 60.498 0.038 ;
    END
  END i[294]
  PIN i[295]
    DIRECTION INPUT ;
    USE SIGNAL ;
    PORT
      LAYER M5 ;
        RECT  60.672 0 60.696 0.084 ;
    END
  END i[295]
  PIN i[296]
    DIRECTION INPUT ;
    USE SIGNAL ;
    PORT
      LAYER M3 ;
        RECT  60.876 0 60.894 0.038 ;
    END
  END i[296]
  PIN i[297]
    DIRECTION INPUT ;
    USE SIGNAL ;
    PORT
      LAYER M5 ;
        RECT  61.056 0 61.08 0.084 ;
    END
  END i[297]
  PIN i[298]
    DIRECTION INPUT ;
    USE SIGNAL ;
    PORT
      LAYER M3 ;
        RECT  61.272 0 61.29 0.038 ;
    END
  END i[298]
  PIN i[299]
    DIRECTION INPUT ;
    USE SIGNAL ;
    PORT
      LAYER M5 ;
        RECT  61.488 0 61.512 0.084 ;
    END
  END i[299]
  PIN i[29]
    DIRECTION INPUT ;
    USE SIGNAL ;
    PORT
      LAYER M5 ;
        RECT  7.008 0 7.032 0.084 ;
    END
  END i[29]
  PIN i[2]
    DIRECTION INPUT ;
    USE SIGNAL ;
    PORT
      LAYER M3 ;
        RECT  1.584 0 1.602 0.038 ;
    END
  END i[2]
  PIN i[300]
    DIRECTION INPUT ;
    USE SIGNAL ;
    PORT
      LAYER M3 ;
        RECT  61.668 0 61.686 0.038 ;
    END
  END i[300]
  PIN i[301]
    DIRECTION INPUT ;
    USE SIGNAL ;
    PORT
      LAYER M5 ;
        RECT  61.872 0 61.896 0.084 ;
    END
  END i[301]
  PIN i[302]
    DIRECTION INPUT ;
    USE SIGNAL ;
    PORT
      LAYER M3 ;
        RECT  62.1 0 62.118 0.038 ;
    END
  END i[302]
  PIN i[303]
    DIRECTION INPUT ;
    USE SIGNAL ;
    PORT
      LAYER M5 ;
        RECT  62.304 0 62.328 0.084 ;
    END
  END i[303]
  PIN i[304]
    DIRECTION INPUT ;
    USE SIGNAL ;
    PORT
      LAYER M3 ;
        RECT  62.496 0 62.514 0.038 ;
    END
  END i[304]
  PIN i[305]
    DIRECTION INPUT ;
    USE SIGNAL ;
    PORT
      LAYER M5 ;
        RECT  62.688 0 62.712 0.084 ;
    END
  END i[305]
  PIN i[306]
    DIRECTION INPUT ;
    USE SIGNAL ;
    PORT
      LAYER M3 ;
        RECT  62.892 0 62.91 0.038 ;
    END
  END i[306]
  PIN i[307]
    DIRECTION INPUT ;
    USE SIGNAL ;
    PORT
      LAYER M5 ;
        RECT  63.072 0 63.096 0.084 ;
    END
  END i[307]
  PIN i[308]
    DIRECTION INPUT ;
    USE SIGNAL ;
    PORT
      LAYER M3 ;
        RECT  63.288 0 63.306 0.038 ;
    END
  END i[308]
  PIN i[309]
    DIRECTION INPUT ;
    USE SIGNAL ;
    PORT
      LAYER M5 ;
        RECT  63.504 0 63.528 0.084 ;
    END
  END i[309]
  PIN i[30]
    DIRECTION INPUT ;
    USE SIGNAL ;
    PORT
      LAYER M3 ;
        RECT  7.236 0 7.254 0.038 ;
    END
  END i[30]
  PIN i[310]
    DIRECTION INPUT ;
    USE SIGNAL ;
    PORT
      LAYER M3 ;
        RECT  63.72 0 63.738 0.038 ;
    END
  END i[310]
  PIN i[311]
    DIRECTION INPUT ;
    USE SIGNAL ;
    PORT
      LAYER M5 ;
        RECT  63.888 0 63.912 0.084 ;
    END
  END i[311]
  PIN i[312]
    DIRECTION INPUT ;
    USE SIGNAL ;
    PORT
      LAYER M3 ;
        RECT  64.116 0 64.134 0.038 ;
    END
  END i[312]
  PIN i[313]
    DIRECTION INPUT ;
    USE SIGNAL ;
    PORT
      LAYER M5 ;
        RECT  64.32 0 64.344 0.084 ;
    END
  END i[313]
  PIN i[314]
    DIRECTION INPUT ;
    USE SIGNAL ;
    PORT
      LAYER M3 ;
        RECT  64.512 0 64.53 0.038 ;
    END
  END i[314]
  PIN i[315]
    DIRECTION INPUT ;
    USE SIGNAL ;
    PORT
      LAYER M5 ;
        RECT  64.704 0 64.728 0.084 ;
    END
  END i[315]
  PIN i[316]
    DIRECTION INPUT ;
    USE SIGNAL ;
    PORT
      LAYER M3 ;
        RECT  64.908 0 64.926 0.038 ;
    END
  END i[316]
  PIN i[317]
    DIRECTION INPUT ;
    USE SIGNAL ;
    PORT
      LAYER M5 ;
        RECT  65.136 0 65.16 0.084 ;
    END
  END i[317]
  PIN i[318]
    DIRECTION INPUT ;
    USE SIGNAL ;
    PORT
      LAYER M3 ;
        RECT  65.304 0 65.322 0.038 ;
    END
  END i[318]
  PIN i[319]
    DIRECTION INPUT ;
    USE SIGNAL ;
    PORT
      LAYER M5 ;
        RECT  65.52 0 65.544 0.084 ;
    END
  END i[319]
  PIN i[31]
    DIRECTION INPUT ;
    USE SIGNAL ;
    PORT
      LAYER M5 ;
        RECT  7.44 0 7.464 0.084 ;
    END
  END i[31]
  PIN i[320]
    DIRECTION INPUT ;
    USE SIGNAL ;
    PORT
      LAYER M3 ;
        RECT  65.736 0 65.754 0.038 ;
    END
  END i[320]
  PIN i[321]
    DIRECTION INPUT ;
    USE SIGNAL ;
    PORT
      LAYER M5 ;
        RECT  65.904 0 65.928 0.084 ;
    END
  END i[321]
  PIN i[322]
    DIRECTION INPUT ;
    USE SIGNAL ;
    PORT
      LAYER M3 ;
        RECT  66.132 0 66.15 0.038 ;
    END
  END i[322]
  PIN i[323]
    DIRECTION INPUT ;
    USE SIGNAL ;
    PORT
      LAYER M5 ;
        RECT  66.336 0 66.36 0.084 ;
    END
  END i[323]
  PIN i[324]
    DIRECTION INPUT ;
    USE SIGNAL ;
    PORT
      LAYER M3 ;
        RECT  66.528 0 66.546 0.038 ;
    END
  END i[324]
  PIN i[325]
    DIRECTION INPUT ;
    USE SIGNAL ;
    PORT
      LAYER M5 ;
        RECT  66.72 0 66.744 0.084 ;
    END
  END i[325]
  PIN i[326]
    DIRECTION INPUT ;
    USE SIGNAL ;
    PORT
      LAYER M3 ;
        RECT  66.924 0 66.942 0.038 ;
    END
  END i[326]
  PIN i[327]
    DIRECTION INPUT ;
    USE SIGNAL ;
    PORT
      LAYER M5 ;
        RECT  67.152 0 67.176 0.084 ;
    END
  END i[327]
  PIN i[328]
    DIRECTION INPUT ;
    USE SIGNAL ;
    PORT
      LAYER M3 ;
        RECT  67.32 0 67.338 0.038 ;
    END
  END i[328]
  PIN i[329]
    DIRECTION INPUT ;
    USE SIGNAL ;
    PORT
      LAYER M5 ;
        RECT  67.536 0 67.56 0.084 ;
    END
  END i[329]
  PIN i[32]
    DIRECTION INPUT ;
    USE SIGNAL ;
    PORT
      LAYER M3 ;
        RECT  7.632 0 7.65 0.038 ;
    END
  END i[32]
  PIN i[330]
    DIRECTION INPUT ;
    USE SIGNAL ;
    PORT
      LAYER M3 ;
        RECT  67.752 0 67.77 0.038 ;
    END
  END i[330]
  PIN i[331]
    DIRECTION INPUT ;
    USE SIGNAL ;
    PORT
      LAYER M5 ;
        RECT  67.92 0 67.944 0.084 ;
    END
  END i[331]
  PIN i[332]
    DIRECTION INPUT ;
    USE SIGNAL ;
    PORT
      LAYER M3 ;
        RECT  68.148 0 68.166 0.038 ;
    END
  END i[332]
  PIN i[333]
    DIRECTION INPUT ;
    USE SIGNAL ;
    PORT
      LAYER M5 ;
        RECT  68.352 0 68.376 0.084 ;
    END
  END i[333]
  PIN i[334]
    DIRECTION INPUT ;
    USE SIGNAL ;
    PORT
      LAYER M3 ;
        RECT  68.544 0 68.562 0.038 ;
    END
  END i[334]
  PIN i[335]
    DIRECTION INPUT ;
    USE SIGNAL ;
    PORT
      LAYER M5 ;
        RECT  68.736 0 68.76 0.084 ;
    END
  END i[335]
  PIN i[336]
    DIRECTION INPUT ;
    USE SIGNAL ;
    PORT
      LAYER M3 ;
        RECT  68.94 0 68.958 0.038 ;
    END
  END i[336]
  PIN i[337]
    DIRECTION INPUT ;
    USE SIGNAL ;
    PORT
      LAYER M5 ;
        RECT  69.168 0 69.192 0.084 ;
    END
  END i[337]
  PIN i[338]
    DIRECTION INPUT ;
    USE SIGNAL ;
    PORT
      LAYER M3 ;
        RECT  69.336 0 69.354 0.038 ;
    END
  END i[338]
  PIN i[339]
    DIRECTION INPUT ;
    USE SIGNAL ;
    PORT
      LAYER M5 ;
        RECT  69.552 0 69.576 0.084 ;
    END
  END i[339]
  PIN i[33]
    DIRECTION INPUT ;
    USE SIGNAL ;
    PORT
      LAYER M5 ;
        RECT  7.824 0 7.848 0.084 ;
    END
  END i[33]
  PIN i[340]
    DIRECTION INPUT ;
    USE SIGNAL ;
    PORT
      LAYER M3 ;
        RECT  69.768 0 69.786 0.038 ;
    END
  END i[340]
  PIN i[341]
    DIRECTION INPUT ;
    USE SIGNAL ;
    PORT
      LAYER M5 ;
        RECT  69.936 0 69.96 0.084 ;
    END
  END i[341]
  PIN i[342]
    DIRECTION INPUT ;
    USE SIGNAL ;
    PORT
      LAYER M3 ;
        RECT  70.164 0 70.182 0.038 ;
    END
  END i[342]
  PIN i[343]
    DIRECTION INPUT ;
    USE SIGNAL ;
    PORT
      LAYER M5 ;
        RECT  70.368 0 70.392 0.084 ;
    END
  END i[343]
  PIN i[344]
    DIRECTION INPUT ;
    USE SIGNAL ;
    PORT
      LAYER M3 ;
        RECT  70.56 0 70.578 0.038 ;
    END
  END i[344]
  PIN i[345]
    DIRECTION INPUT ;
    USE SIGNAL ;
    PORT
      LAYER M5 ;
        RECT  70.752 0 70.776 0.084 ;
    END
  END i[345]
  PIN i[346]
    DIRECTION INPUT ;
    USE SIGNAL ;
    PORT
      LAYER M3 ;
        RECT  70.956 0 70.974 0.038 ;
    END
  END i[346]
  PIN i[347]
    DIRECTION INPUT ;
    USE SIGNAL ;
    PORT
      LAYER M5 ;
        RECT  71.184 0 71.208 0.084 ;
    END
  END i[347]
  PIN i[348]
    DIRECTION INPUT ;
    USE SIGNAL ;
    PORT
      LAYER M3 ;
        RECT  71.352 0 71.37 0.038 ;
    END
  END i[348]
  PIN i[349]
    DIRECTION INPUT ;
    USE SIGNAL ;
    PORT
      LAYER M5 ;
        RECT  71.568 0 71.592 0.084 ;
    END
  END i[349]
  PIN i[34]
    DIRECTION INPUT ;
    USE SIGNAL ;
    PORT
      LAYER M3 ;
        RECT  8.028 0 8.046 0.038 ;
    END
  END i[34]
  PIN i[350]
    DIRECTION INPUT ;
    USE SIGNAL ;
    PORT
      LAYER M3 ;
        RECT  71.784 0 71.802 0.038 ;
    END
  END i[350]
  PIN i[351]
    DIRECTION INPUT ;
    USE SIGNAL ;
    PORT
      LAYER M5 ;
        RECT  71.952 0 71.976 0.084 ;
    END
  END i[351]
  PIN i[352]
    DIRECTION INPUT ;
    USE SIGNAL ;
    PORT
      LAYER M3 ;
        RECT  72.18 0 72.198 0.038 ;
    END
  END i[352]
  PIN i[353]
    DIRECTION INPUT ;
    USE SIGNAL ;
    PORT
      LAYER M5 ;
        RECT  72.384 0 72.408 0.084 ;
    END
  END i[353]
  PIN i[354]
    DIRECTION INPUT ;
    USE SIGNAL ;
    PORT
      LAYER M3 ;
        RECT  72.576 0 72.594 0.038 ;
    END
  END i[354]
  PIN i[355]
    DIRECTION INPUT ;
    USE SIGNAL ;
    PORT
      LAYER M5 ;
        RECT  72.768 0 72.792 0.084 ;
    END
  END i[355]
  PIN i[356]
    DIRECTION INPUT ;
    USE SIGNAL ;
    PORT
      LAYER M3 ;
        RECT  72.972 0 72.99 0.038 ;
    END
  END i[356]
  PIN i[357]
    DIRECTION INPUT ;
    USE SIGNAL ;
    PORT
      LAYER M5 ;
        RECT  73.2 0 73.224 0.084 ;
    END
  END i[357]
  PIN i[358]
    DIRECTION INPUT ;
    USE SIGNAL ;
    PORT
      LAYER M3 ;
        RECT  73.368 0 73.386 0.038 ;
    END
  END i[358]
  PIN i[359]
    DIRECTION INPUT ;
    USE SIGNAL ;
    PORT
      LAYER M5 ;
        RECT  73.584 0 73.608 0.084 ;
    END
  END i[359]
  PIN i[35]
    DIRECTION INPUT ;
    USE SIGNAL ;
    PORT
      LAYER M5 ;
        RECT  8.208 0 8.232 0.084 ;
    END
  END i[35]
  PIN i[360]
    DIRECTION INPUT ;
    USE SIGNAL ;
    PORT
      LAYER M3 ;
        RECT  73.8 0 73.818 0.038 ;
    END
  END i[360]
  PIN i[361]
    DIRECTION INPUT ;
    USE SIGNAL ;
    PORT
      LAYER M5 ;
        RECT  73.968 0 73.992 0.084 ;
    END
  END i[361]
  PIN i[362]
    DIRECTION INPUT ;
    USE SIGNAL ;
    PORT
      LAYER M3 ;
        RECT  74.196 0 74.214 0.038 ;
    END
  END i[362]
  PIN i[363]
    DIRECTION INPUT ;
    USE SIGNAL ;
    PORT
      LAYER M5 ;
        RECT  74.4 0 74.424 0.084 ;
    END
  END i[363]
  PIN i[364]
    DIRECTION INPUT ;
    USE SIGNAL ;
    PORT
      LAYER M3 ;
        RECT  74.592 0 74.61 0.038 ;
    END
  END i[364]
  PIN i[365]
    DIRECTION INPUT ;
    USE SIGNAL ;
    PORT
      LAYER M5 ;
        RECT  74.784 0 74.808 0.084 ;
    END
  END i[365]
  PIN i[366]
    DIRECTION INPUT ;
    USE SIGNAL ;
    PORT
      LAYER M3 ;
        RECT  74.988 0 75.006 0.038 ;
    END
  END i[366]
  PIN i[367]
    DIRECTION INPUT ;
    USE SIGNAL ;
    PORT
      LAYER M5 ;
        RECT  75.216 0 75.24 0.084 ;
    END
  END i[367]
  PIN i[368]
    DIRECTION INPUT ;
    USE SIGNAL ;
    PORT
      LAYER M3 ;
        RECT  75.42 0 75.438 0.038 ;
    END
  END i[368]
  PIN i[369]
    DIRECTION INPUT ;
    USE SIGNAL ;
    PORT
      LAYER M5 ;
        RECT  75.6 0 75.624 0.084 ;
    END
  END i[369]
  PIN i[36]
    DIRECTION INPUT ;
    USE SIGNAL ;
    PORT
      LAYER M3 ;
        RECT  8.424 0 8.442 0.038 ;
    END
  END i[36]
  PIN i[370]
    DIRECTION INPUT ;
    USE SIGNAL ;
    PORT
      LAYER M3 ;
        RECT  75.816 0 75.834 0.038 ;
    END
  END i[370]
  PIN i[371]
    DIRECTION INPUT ;
    USE SIGNAL ;
    PORT
      LAYER M5 ;
        RECT  75.984 0 76.008 0.084 ;
    END
  END i[371]
  PIN i[372]
    DIRECTION INPUT ;
    USE SIGNAL ;
    PORT
      LAYER M3 ;
        RECT  76.212 0 76.23 0.038 ;
    END
  END i[372]
  PIN i[373]
    DIRECTION INPUT ;
    USE SIGNAL ;
    PORT
      LAYER M5 ;
        RECT  76.416 0 76.44 0.084 ;
    END
  END i[373]
  PIN i[374]
    DIRECTION INPUT ;
    USE SIGNAL ;
    PORT
      LAYER M3 ;
        RECT  76.608 0 76.626 0.038 ;
    END
  END i[374]
  PIN i[375]
    DIRECTION INPUT ;
    USE SIGNAL ;
    PORT
      LAYER M5 ;
        RECT  76.8 0 76.824 0.084 ;
    END
  END i[375]
  PIN i[376]
    DIRECTION INPUT ;
    USE SIGNAL ;
    PORT
      LAYER M3 ;
        RECT  77.004 0 77.022 0.038 ;
    END
  END i[376]
  PIN i[377]
    DIRECTION INPUT ;
    USE SIGNAL ;
    PORT
      LAYER M5 ;
        RECT  77.232 0 77.256 0.084 ;
    END
  END i[377]
  PIN i[378]
    DIRECTION INPUT ;
    USE SIGNAL ;
    PORT
      LAYER M3 ;
        RECT  77.436 0 77.454 0.038 ;
    END
  END i[378]
  PIN i[379]
    DIRECTION INPUT ;
    USE SIGNAL ;
    PORT
      LAYER M5 ;
        RECT  77.616 0 77.64 0.084 ;
    END
  END i[379]
  PIN i[37]
    DIRECTION INPUT ;
    USE SIGNAL ;
    PORT
      LAYER M5 ;
        RECT  8.64 0 8.664 0.084 ;
    END
  END i[37]
  PIN i[380]
    DIRECTION INPUT ;
    USE SIGNAL ;
    PORT
      LAYER M3 ;
        RECT  77.832 0 77.85 0.038 ;
    END
  END i[380]
  PIN i[381]
    DIRECTION INPUT ;
    USE SIGNAL ;
    PORT
      LAYER M5 ;
        RECT  78 0 78.024 0.084 ;
    END
  END i[381]
  PIN i[382]
    DIRECTION INPUT ;
    USE SIGNAL ;
    PORT
      LAYER M3 ;
        RECT  78.228 0 78.246 0.038 ;
    END
  END i[382]
  PIN i[383]
    DIRECTION INPUT ;
    USE SIGNAL ;
    PORT
      LAYER M5 ;
        RECT  78.432 0 78.456 0.084 ;
    END
  END i[383]
  PIN i[384]
    DIRECTION INPUT ;
    USE SIGNAL ;
    PORT
      LAYER M3 ;
        RECT  78.624 0 78.642 0.038 ;
    END
  END i[384]
  PIN i[385]
    DIRECTION INPUT ;
    USE SIGNAL ;
    PORT
      LAYER M5 ;
        RECT  78.816 0 78.84 0.084 ;
    END
  END i[385]
  PIN i[386]
    DIRECTION INPUT ;
    USE SIGNAL ;
    PORT
      LAYER M3 ;
        RECT  79.02 0 79.038 0.038 ;
    END
  END i[386]
  PIN i[387]
    DIRECTION INPUT ;
    USE SIGNAL ;
    PORT
      LAYER M5 ;
        RECT  79.248 0 79.272 0.084 ;
    END
  END i[387]
  PIN i[388]
    DIRECTION INPUT ;
    USE SIGNAL ;
    PORT
      LAYER M3 ;
        RECT  79.452 0 79.47 0.038 ;
    END
  END i[388]
  PIN i[389]
    DIRECTION INPUT ;
    USE SIGNAL ;
    PORT
      LAYER M5 ;
        RECT  79.632 0 79.656 0.084 ;
    END
  END i[389]
  PIN i[38]
    DIRECTION INPUT ;
    USE SIGNAL ;
    PORT
      LAYER M3 ;
        RECT  8.82 0 8.838 0.038 ;
    END
  END i[38]
  PIN i[390]
    DIRECTION INPUT ;
    USE SIGNAL ;
    PORT
      LAYER M3 ;
        RECT  79.848 0 79.866 0.038 ;
    END
  END i[390]
  PIN i[391]
    DIRECTION INPUT ;
    USE SIGNAL ;
    PORT
      LAYER M5 ;
        RECT  80.016 0 80.04 0.084 ;
    END
  END i[391]
  PIN i[392]
    DIRECTION INPUT ;
    USE SIGNAL ;
    PORT
      LAYER M3 ;
        RECT  80.244 0 80.262 0.038 ;
    END
  END i[392]
  PIN i[393]
    DIRECTION INPUT ;
    USE SIGNAL ;
    PORT
      LAYER M5 ;
        RECT  80.448 0 80.472 0.084 ;
    END
  END i[393]
  PIN i[394]
    DIRECTION INPUT ;
    USE SIGNAL ;
    PORT
      LAYER M3 ;
        RECT  80.64 0 80.658 0.038 ;
    END
  END i[394]
  PIN i[395]
    DIRECTION INPUT ;
    USE SIGNAL ;
    PORT
      LAYER M5 ;
        RECT  80.832 0 80.856 0.084 ;
    END
  END i[395]
  PIN i[396]
    DIRECTION INPUT ;
    USE SIGNAL ;
    PORT
      LAYER M3 ;
        RECT  81.036 0 81.054 0.038 ;
    END
  END i[396]
  PIN i[397]
    DIRECTION INPUT ;
    USE SIGNAL ;
    PORT
      LAYER M5 ;
        RECT  81.264 0 81.288 0.084 ;
    END
  END i[397]
  PIN i[398]
    DIRECTION INPUT ;
    USE SIGNAL ;
    PORT
      LAYER M3 ;
        RECT  81.468 0 81.486 0.038 ;
    END
  END i[398]
  PIN i[399]
    DIRECTION INPUT ;
    USE SIGNAL ;
    PORT
      LAYER M5 ;
        RECT  81.648 0 81.672 0.084 ;
    END
  END i[399]
  PIN i[39]
    DIRECTION INPUT ;
    USE SIGNAL ;
    PORT
      LAYER M5 ;
        RECT  9.024 0 9.048 0.084 ;
    END
  END i[39]
  PIN i[3]
    DIRECTION INPUT ;
    USE SIGNAL ;
    PORT
      LAYER M5 ;
        RECT  1.776 0 1.8 0.084 ;
    END
  END i[3]
  PIN i[400]
    DIRECTION INPUT ;
    USE SIGNAL ;
    PORT
      LAYER M3 ;
        RECT  81.864 0 81.882 0.038 ;
    END
  END i[400]
  PIN i[401]
    DIRECTION INPUT ;
    USE SIGNAL ;
    PORT
      LAYER M5 ;
        RECT  82.032 0 82.056 0.084 ;
    END
  END i[401]
  PIN i[402]
    DIRECTION INPUT ;
    USE SIGNAL ;
    PORT
      LAYER M3 ;
        RECT  82.26 0 82.278 0.038 ;
    END
  END i[402]
  PIN i[403]
    DIRECTION INPUT ;
    USE SIGNAL ;
    PORT
      LAYER M5 ;
        RECT  82.464 0 82.488 0.084 ;
    END
  END i[403]
  PIN i[404]
    DIRECTION INPUT ;
    USE SIGNAL ;
    PORT
      LAYER M3 ;
        RECT  82.656 0 82.674 0.038 ;
    END
  END i[404]
  PIN i[405]
    DIRECTION INPUT ;
    USE SIGNAL ;
    PORT
      LAYER M5 ;
        RECT  82.848 0 82.872 0.084 ;
    END
  END i[405]
  PIN i[406]
    DIRECTION INPUT ;
    USE SIGNAL ;
    PORT
      LAYER M3 ;
        RECT  83.052 0 83.07 0.038 ;
    END
  END i[406]
  PIN i[407]
    DIRECTION INPUT ;
    USE SIGNAL ;
    PORT
      LAYER M5 ;
        RECT  83.28 0 83.304 0.084 ;
    END
  END i[407]
  PIN i[408]
    DIRECTION INPUT ;
    USE SIGNAL ;
    PORT
      LAYER M3 ;
        RECT  83.484 0 83.502 0.038 ;
    END
  END i[408]
  PIN i[409]
    DIRECTION INPUT ;
    USE SIGNAL ;
    PORT
      LAYER M5 ;
        RECT  83.664 0 83.688 0.084 ;
    END
  END i[409]
  PIN i[40]
    DIRECTION INPUT ;
    USE SIGNAL ;
    PORT
      LAYER M3 ;
        RECT  9.252 0 9.27 0.038 ;
    END
  END i[40]
  PIN i[410]
    DIRECTION INPUT ;
    USE SIGNAL ;
    PORT
      LAYER M3 ;
        RECT  83.88 0 83.898 0.038 ;
    END
  END i[410]
  PIN i[411]
    DIRECTION INPUT ;
    USE SIGNAL ;
    PORT
      LAYER M5 ;
        RECT  84.096 0 84.12 0.084 ;
    END
  END i[411]
  PIN i[412]
    DIRECTION INPUT ;
    USE SIGNAL ;
    PORT
      LAYER M3 ;
        RECT  84.276 0 84.294 0.038 ;
    END
  END i[412]
  PIN i[413]
    DIRECTION INPUT ;
    USE SIGNAL ;
    PORT
      LAYER M5 ;
        RECT  84.48 0 84.504 0.084 ;
    END
  END i[413]
  PIN i[414]
    DIRECTION INPUT ;
    USE SIGNAL ;
    PORT
      LAYER M3 ;
        RECT  84.672 0 84.69 0.038 ;
    END
  END i[414]
  PIN i[415]
    DIRECTION INPUT ;
    USE SIGNAL ;
    PORT
      LAYER M5 ;
        RECT  84.864 0 84.888 0.084 ;
    END
  END i[415]
  PIN i[416]
    DIRECTION INPUT ;
    USE SIGNAL ;
    PORT
      LAYER M3 ;
        RECT  85.068 0 85.086 0.038 ;
    END
  END i[416]
  PIN i[417]
    DIRECTION INPUT ;
    USE SIGNAL ;
    PORT
      LAYER M5 ;
        RECT  85.296 0 85.32 0.084 ;
    END
  END i[417]
  PIN i[418]
    DIRECTION INPUT ;
    USE SIGNAL ;
    PORT
      LAYER M3 ;
        RECT  85.5 0 85.518 0.038 ;
    END
  END i[418]
  PIN i[419]
    DIRECTION INPUT ;
    USE SIGNAL ;
    PORT
      LAYER M5 ;
        RECT  85.68 0 85.704 0.084 ;
    END
  END i[419]
  PIN i[41]
    DIRECTION INPUT ;
    USE SIGNAL ;
    PORT
      LAYER M5 ;
        RECT  9.456 0 9.48 0.084 ;
    END
  END i[41]
  PIN i[420]
    DIRECTION INPUT ;
    USE SIGNAL ;
    PORT
      LAYER M3 ;
        RECT  85.896 0 85.914 0.038 ;
    END
  END i[420]
  PIN i[421]
    DIRECTION INPUT ;
    USE SIGNAL ;
    PORT
      LAYER M5 ;
        RECT  86.112 0 86.136 0.084 ;
    END
  END i[421]
  PIN i[422]
    DIRECTION INPUT ;
    USE SIGNAL ;
    PORT
      LAYER M3 ;
        RECT  86.292 0 86.31 0.038 ;
    END
  END i[422]
  PIN i[423]
    DIRECTION INPUT ;
    USE SIGNAL ;
    PORT
      LAYER M5 ;
        RECT  86.496 0 86.52 0.084 ;
    END
  END i[423]
  PIN i[424]
    DIRECTION INPUT ;
    USE SIGNAL ;
    PORT
      LAYER M3 ;
        RECT  86.688 0 86.706 0.038 ;
    END
  END i[424]
  PIN i[425]
    DIRECTION INPUT ;
    USE SIGNAL ;
    PORT
      LAYER M5 ;
        RECT  86.88 0 86.904 0.084 ;
    END
  END i[425]
  PIN i[426]
    DIRECTION INPUT ;
    USE SIGNAL ;
    PORT
      LAYER M3 ;
        RECT  87.084 0 87.102 0.038 ;
    END
  END i[426]
  PIN i[427]
    DIRECTION INPUT ;
    USE SIGNAL ;
    PORT
      LAYER M5 ;
        RECT  87.312 0 87.336 0.084 ;
    END
  END i[427]
  PIN i[428]
    DIRECTION INPUT ;
    USE SIGNAL ;
    PORT
      LAYER M3 ;
        RECT  87.516 0 87.534 0.038 ;
    END
  END i[428]
  PIN i[429]
    DIRECTION INPUT ;
    USE SIGNAL ;
    PORT
      LAYER M5 ;
        RECT  87.696 0 87.72 0.084 ;
    END
  END i[429]
  PIN i[42]
    DIRECTION INPUT ;
    USE SIGNAL ;
    PORT
      LAYER M3 ;
        RECT  9.648 0 9.666 0.038 ;
    END
  END i[42]
  PIN i[430]
    DIRECTION INPUT ;
    USE SIGNAL ;
    PORT
      LAYER M3 ;
        RECT  87.912 0 87.93 0.038 ;
    END
  END i[430]
  PIN i[431]
    DIRECTION INPUT ;
    USE SIGNAL ;
    PORT
      LAYER M5 ;
        RECT  88.128 0 88.152 0.084 ;
    END
  END i[431]
  PIN i[432]
    DIRECTION INPUT ;
    USE SIGNAL ;
    PORT
      LAYER M3 ;
        RECT  88.308 0 88.326 0.038 ;
    END
  END i[432]
  PIN i[433]
    DIRECTION INPUT ;
    USE SIGNAL ;
    PORT
      LAYER M5 ;
        RECT  88.512 0 88.536 0.084 ;
    END
  END i[433]
  PIN i[434]
    DIRECTION INPUT ;
    USE SIGNAL ;
    PORT
      LAYER M3 ;
        RECT  88.704 0 88.722 0.038 ;
    END
  END i[434]
  PIN i[435]
    DIRECTION INPUT ;
    USE SIGNAL ;
    PORT
      LAYER M5 ;
        RECT  88.896 0 88.92 0.084 ;
    END
  END i[435]
  PIN i[436]
    DIRECTION INPUT ;
    USE SIGNAL ;
    PORT
      LAYER M3 ;
        RECT  89.136 0 89.154 0.038 ;
    END
  END i[436]
  PIN i[437]
    DIRECTION INPUT ;
    USE SIGNAL ;
    PORT
      LAYER M5 ;
        RECT  89.328 0 89.352 0.084 ;
    END
  END i[437]
  PIN i[438]
    DIRECTION INPUT ;
    USE SIGNAL ;
    PORT
      LAYER M3 ;
        RECT  89.532 0 89.55 0.038 ;
    END
  END i[438]
  PIN i[439]
    DIRECTION INPUT ;
    USE SIGNAL ;
    PORT
      LAYER M5 ;
        RECT  89.712 0 89.736 0.084 ;
    END
  END i[439]
  PIN i[43]
    DIRECTION INPUT ;
    USE SIGNAL ;
    PORT
      LAYER M5 ;
        RECT  9.84 0 9.864 0.084 ;
    END
  END i[43]
  PIN i[440]
    DIRECTION INPUT ;
    USE SIGNAL ;
    PORT
      LAYER M3 ;
        RECT  89.928 0 89.946 0.038 ;
    END
  END i[440]
  PIN i[441]
    DIRECTION INPUT ;
    USE SIGNAL ;
    PORT
      LAYER M5 ;
        RECT  90.144 0 90.168 0.084 ;
    END
  END i[441]
  PIN i[442]
    DIRECTION INPUT ;
    USE SIGNAL ;
    PORT
      LAYER M3 ;
        RECT  90.324 0 90.342 0.038 ;
    END
  END i[442]
  PIN i[443]
    DIRECTION INPUT ;
    USE SIGNAL ;
    PORT
      LAYER M5 ;
        RECT  90.528 0 90.552 0.084 ;
    END
  END i[443]
  PIN i[444]
    DIRECTION INPUT ;
    USE SIGNAL ;
    PORT
      LAYER M3 ;
        RECT  90.72 0 90.738 0.038 ;
    END
  END i[444]
  PIN i[445]
    DIRECTION INPUT ;
    USE SIGNAL ;
    PORT
      LAYER M5 ;
        RECT  90.912 0 90.936 0.084 ;
    END
  END i[445]
  PIN i[446]
    DIRECTION INPUT ;
    USE SIGNAL ;
    PORT
      LAYER M3 ;
        RECT  91.152 0 91.17 0.038 ;
    END
  END i[446]
  PIN i[447]
    DIRECTION INPUT ;
    USE SIGNAL ;
    PORT
      LAYER M5 ;
        RECT  91.344 0 91.368 0.084 ;
    END
  END i[447]
  PIN i[448]
    DIRECTION INPUT ;
    USE SIGNAL ;
    PORT
      LAYER M3 ;
        RECT  91.548 0 91.566 0.038 ;
    END
  END i[448]
  PIN i[449]
    DIRECTION INPUT ;
    USE SIGNAL ;
    PORT
      LAYER M5 ;
        RECT  91.728 0 91.752 0.084 ;
    END
  END i[449]
  PIN i[44]
    DIRECTION INPUT ;
    USE SIGNAL ;
    PORT
      LAYER M3 ;
        RECT  10.044 0 10.062 0.038 ;
    END
  END i[44]
  PIN i[450]
    DIRECTION INPUT ;
    USE SIGNAL ;
    PORT
      LAYER M3 ;
        RECT  91.944 0 91.962 0.038 ;
    END
  END i[450]
  PIN i[451]
    DIRECTION INPUT ;
    USE SIGNAL ;
    PORT
      LAYER M5 ;
        RECT  92.16 0 92.184 0.084 ;
    END
  END i[451]
  PIN i[452]
    DIRECTION INPUT ;
    USE SIGNAL ;
    PORT
      LAYER M3 ;
        RECT  92.34 0 92.358 0.038 ;
    END
  END i[452]
  PIN i[453]
    DIRECTION INPUT ;
    USE SIGNAL ;
    PORT
      LAYER M5 ;
        RECT  92.544 0 92.568 0.084 ;
    END
  END i[453]
  PIN i[454]
    DIRECTION INPUT ;
    USE SIGNAL ;
    PORT
      LAYER M3 ;
        RECT  92.736 0 92.754 0.038 ;
    END
  END i[454]
  PIN i[455]
    DIRECTION INPUT ;
    USE SIGNAL ;
    PORT
      LAYER M5 ;
        RECT  92.928 0 92.952 0.084 ;
    END
  END i[455]
  PIN i[456]
    DIRECTION INPUT ;
    USE SIGNAL ;
    PORT
      LAYER M3 ;
        RECT  93.168 0 93.186 0.038 ;
    END
  END i[456]
  PIN i[457]
    DIRECTION INPUT ;
    USE SIGNAL ;
    PORT
      LAYER M5 ;
        RECT  93.36 0 93.384 0.084 ;
    END
  END i[457]
  PIN i[458]
    DIRECTION INPUT ;
    USE SIGNAL ;
    PORT
      LAYER M3 ;
        RECT  93.564 0 93.582 0.038 ;
    END
  END i[458]
  PIN i[459]
    DIRECTION INPUT ;
    USE SIGNAL ;
    PORT
      LAYER M5 ;
        RECT  93.744 0 93.768 0.084 ;
    END
  END i[459]
  PIN i[45]
    DIRECTION INPUT ;
    USE SIGNAL ;
    PORT
      LAYER M5 ;
        RECT  10.224 0 10.248 0.084 ;
    END
  END i[45]
  PIN i[460]
    DIRECTION INPUT ;
    USE SIGNAL ;
    PORT
      LAYER M3 ;
        RECT  93.96 0 93.978 0.038 ;
    END
  END i[460]
  PIN i[461]
    DIRECTION INPUT ;
    USE SIGNAL ;
    PORT
      LAYER M5 ;
        RECT  94.176 0 94.2 0.084 ;
    END
  END i[461]
  PIN i[462]
    DIRECTION INPUT ;
    USE SIGNAL ;
    PORT
      LAYER M3 ;
        RECT  94.356 0 94.374 0.038 ;
    END
  END i[462]
  PIN i[463]
    DIRECTION INPUT ;
    USE SIGNAL ;
    PORT
      LAYER M5 ;
        RECT  94.56 0 94.584 0.084 ;
    END
  END i[463]
  PIN i[464]
    DIRECTION INPUT ;
    USE SIGNAL ;
    PORT
      LAYER M3 ;
        RECT  94.752 0 94.77 0.038 ;
    END
  END i[464]
  PIN i[465]
    DIRECTION INPUT ;
    USE SIGNAL ;
    PORT
      LAYER M5 ;
        RECT  94.944 0 94.968 0.084 ;
    END
  END i[465]
  PIN i[466]
    DIRECTION INPUT ;
    USE SIGNAL ;
    PORT
      LAYER M3 ;
        RECT  95.184 0 95.202 0.038 ;
    END
  END i[466]
  PIN i[467]
    DIRECTION INPUT ;
    USE SIGNAL ;
    PORT
      LAYER M5 ;
        RECT  95.376 0 95.4 0.084 ;
    END
  END i[467]
  PIN i[468]
    DIRECTION INPUT ;
    USE SIGNAL ;
    PORT
      LAYER M3 ;
        RECT  95.58 0 95.598 0.038 ;
    END
  END i[468]
  PIN i[469]
    DIRECTION INPUT ;
    USE SIGNAL ;
    PORT
      LAYER M5 ;
        RECT  95.76 0 95.784 0.084 ;
    END
  END i[469]
  PIN i[46]
    DIRECTION INPUT ;
    USE SIGNAL ;
    PORT
      LAYER M3 ;
        RECT  10.44 0 10.458 0.038 ;
    END
  END i[46]
  PIN i[470]
    DIRECTION INPUT ;
    USE SIGNAL ;
    PORT
      LAYER M3 ;
        RECT  95.976 0 95.994 0.038 ;
    END
  END i[470]
  PIN i[471]
    DIRECTION INPUT ;
    USE SIGNAL ;
    PORT
      LAYER M5 ;
        RECT  96.192 0 96.216 0.084 ;
    END
  END i[471]
  PIN i[472]
    DIRECTION INPUT ;
    USE SIGNAL ;
    PORT
      LAYER M3 ;
        RECT  96.372 0 96.39 0.038 ;
    END
  END i[472]
  PIN i[473]
    DIRECTION INPUT ;
    USE SIGNAL ;
    PORT
      LAYER M5 ;
        RECT  96.576 0 96.6 0.084 ;
    END
  END i[473]
  PIN i[474]
    DIRECTION INPUT ;
    USE SIGNAL ;
    PORT
      LAYER M3 ;
        RECT  96.768 0 96.786 0.038 ;
    END
  END i[474]
  PIN i[475]
    DIRECTION INPUT ;
    USE SIGNAL ;
    PORT
      LAYER M5 ;
        RECT  96.96 0 96.984 0.084 ;
    END
  END i[475]
  PIN i[476]
    DIRECTION INPUT ;
    USE SIGNAL ;
    PORT
      LAYER M3 ;
        RECT  97.2 0 97.218 0.038 ;
    END
  END i[476]
  PIN i[477]
    DIRECTION INPUT ;
    USE SIGNAL ;
    PORT
      LAYER M5 ;
        RECT  97.392 0 97.416 0.084 ;
    END
  END i[477]
  PIN i[478]
    DIRECTION INPUT ;
    USE SIGNAL ;
    PORT
      LAYER M3 ;
        RECT  97.596 0 97.614 0.038 ;
    END
  END i[478]
  PIN i[479]
    DIRECTION INPUT ;
    USE SIGNAL ;
    PORT
      LAYER M5 ;
        RECT  97.776 0 97.8 0.084 ;
    END
  END i[479]
  PIN i[47]
    DIRECTION INPUT ;
    USE SIGNAL ;
    PORT
      LAYER M5 ;
        RECT  10.656 0 10.68 0.084 ;
    END
  END i[47]
  PIN i[480]
    DIRECTION INPUT ;
    USE SIGNAL ;
    PORT
      LAYER M3 ;
        RECT  97.992 0 98.01 0.038 ;
    END
  END i[480]
  PIN i[481]
    DIRECTION INPUT ;
    USE SIGNAL ;
    PORT
      LAYER M5 ;
        RECT  98.208 0 98.232 0.084 ;
    END
  END i[481]
  PIN i[482]
    DIRECTION INPUT ;
    USE SIGNAL ;
    PORT
      LAYER M3 ;
        RECT  98.388 0 98.406 0.038 ;
    END
  END i[482]
  PIN i[483]
    DIRECTION INPUT ;
    USE SIGNAL ;
    PORT
      LAYER M5 ;
        RECT  98.592 0 98.616 0.084 ;
    END
  END i[483]
  PIN i[484]
    DIRECTION INPUT ;
    USE SIGNAL ;
    PORT
      LAYER M3 ;
        RECT  98.784 0 98.802 0.038 ;
    END
  END i[484]
  PIN i[485]
    DIRECTION INPUT ;
    USE SIGNAL ;
    PORT
      LAYER M5 ;
        RECT  98.976 0 99 0.084 ;
    END
  END i[485]
  PIN i[486]
    DIRECTION INPUT ;
    USE SIGNAL ;
    PORT
      LAYER M3 ;
        RECT  99.216 0 99.234 0.038 ;
    END
  END i[486]
  PIN i[487]
    DIRECTION INPUT ;
    USE SIGNAL ;
    PORT
      LAYER M5 ;
        RECT  99.408 0 99.432 0.084 ;
    END
  END i[487]
  PIN i[488]
    DIRECTION INPUT ;
    USE SIGNAL ;
    PORT
      LAYER M3 ;
        RECT  99.612 0 99.63 0.038 ;
    END
  END i[488]
  PIN i[489]
    DIRECTION INPUT ;
    USE SIGNAL ;
    PORT
      LAYER M5 ;
        RECT  99.792 0 99.816 0.084 ;
    END
  END i[489]
  PIN i[48]
    DIRECTION INPUT ;
    USE SIGNAL ;
    PORT
      LAYER M3 ;
        RECT  10.872 0 10.89 0.038 ;
    END
  END i[48]
  PIN i[490]
    DIRECTION INPUT ;
    USE SIGNAL ;
    PORT
      LAYER M3 ;
        RECT  100.008 0 100.026 0.038 ;
    END
  END i[490]
  PIN i[491]
    DIRECTION INPUT ;
    USE SIGNAL ;
    PORT
      LAYER M5 ;
        RECT  100.224 0 100.248 0.084 ;
    END
  END i[491]
  PIN i[492]
    DIRECTION INPUT ;
    USE SIGNAL ;
    PORT
      LAYER M3 ;
        RECT  100.404 0 100.422 0.038 ;
    END
  END i[492]
  PIN i[493]
    DIRECTION INPUT ;
    USE SIGNAL ;
    PORT
      LAYER M5 ;
        RECT  100.608 0 100.632 0.084 ;
    END
  END i[493]
  PIN i[494]
    DIRECTION INPUT ;
    USE SIGNAL ;
    PORT
      LAYER M3 ;
        RECT  100.836 0 100.854 0.038 ;
    END
  END i[494]
  PIN i[495]
    DIRECTION INPUT ;
    USE SIGNAL ;
    PORT
      LAYER M5 ;
        RECT  101.04 0 101.064 0.084 ;
    END
  END i[495]
  PIN i[496]
    DIRECTION INPUT ;
    USE SIGNAL ;
    PORT
      LAYER M3 ;
        RECT  101.232 0 101.25 0.038 ;
    END
  END i[496]
  PIN i[497]
    DIRECTION INPUT ;
    USE SIGNAL ;
    PORT
      LAYER M5 ;
        RECT  101.424 0 101.448 0.084 ;
    END
  END i[497]
  PIN i[498]
    DIRECTION INPUT ;
    USE SIGNAL ;
    PORT
      LAYER M3 ;
        RECT  101.628 0 101.646 0.038 ;
    END
  END i[498]
  PIN i[499]
    DIRECTION INPUT ;
    USE SIGNAL ;
    PORT
      LAYER M5 ;
        RECT  101.808 0 101.832 0.084 ;
    END
  END i[499]
  PIN i[49]
    DIRECTION INPUT ;
    USE SIGNAL ;
    PORT
      LAYER M5 ;
        RECT  11.04 0 11.064 0.084 ;
    END
  END i[49]
  PIN i[4]
    DIRECTION INPUT ;
    USE SIGNAL ;
    PORT
      LAYER M3 ;
        RECT  1.98 0 1.998 0.038 ;
    END
  END i[4]
  PIN i[500]
    DIRECTION INPUT ;
    USE SIGNAL ;
    PORT
      LAYER M3 ;
        RECT  102.024 0 102.042 0.038 ;
    END
  END i[500]
  PIN i[501]
    DIRECTION INPUT ;
    USE SIGNAL ;
    PORT
      LAYER M5 ;
        RECT  102.24 0 102.264 0.084 ;
    END
  END i[501]
  PIN i[502]
    DIRECTION INPUT ;
    USE SIGNAL ;
    PORT
      LAYER M3 ;
        RECT  102.42 0 102.438 0.038 ;
    END
  END i[502]
  PIN i[503]
    DIRECTION INPUT ;
    USE SIGNAL ;
    PORT
      LAYER M5 ;
        RECT  102.624 0 102.648 0.084 ;
    END
  END i[503]
  PIN i[504]
    DIRECTION INPUT ;
    USE SIGNAL ;
    PORT
      LAYER M3 ;
        RECT  102.852 0 102.87 0.038 ;
    END
  END i[504]
  PIN i[505]
    DIRECTION INPUT ;
    USE SIGNAL ;
    PORT
      LAYER M5 ;
        RECT  103.056 0 103.08 0.084 ;
    END
  END i[505]
  PIN i[506]
    DIRECTION INPUT ;
    USE SIGNAL ;
    PORT
      LAYER M3 ;
        RECT  103.248 0 103.266 0.038 ;
    END
  END i[506]
  PIN i[507]
    DIRECTION INPUT ;
    USE SIGNAL ;
    PORT
      LAYER M5 ;
        RECT  103.44 0 103.464 0.084 ;
    END
  END i[507]
  PIN i[508]
    DIRECTION INPUT ;
    USE SIGNAL ;
    PORT
      LAYER M3 ;
        RECT  103.644 0 103.662 0.038 ;
    END
  END i[508]
  PIN i[509]
    DIRECTION INPUT ;
    USE SIGNAL ;
    PORT
      LAYER M5 ;
        RECT  103.824 0 103.848 0.084 ;
    END
  END i[509]
  PIN i[50]
    DIRECTION INPUT ;
    USE SIGNAL ;
    PORT
      LAYER M3 ;
        RECT  11.268 0 11.286 0.038 ;
    END
  END i[50]
  PIN i[510]
    DIRECTION INPUT ;
    USE SIGNAL ;
    PORT
      LAYER M3 ;
        RECT  104.04 0 104.058 0.038 ;
    END
  END i[510]
  PIN i[511]
    DIRECTION INPUT ;
    USE SIGNAL ;
    PORT
      LAYER M5 ;
        RECT  104.256 0 104.28 0.084 ;
    END
  END i[511]
  PIN i[512]
    DIRECTION INPUT ;
    USE SIGNAL ;
    PORT
      LAYER M3 ;
        RECT  104.436 0 104.454 0.038 ;
    END
  END i[512]
  PIN i[513]
    DIRECTION INPUT ;
    USE SIGNAL ;
    PORT
      LAYER M5 ;
        RECT  104.64 0 104.664 0.084 ;
    END
  END i[513]
  PIN i[51]
    DIRECTION INPUT ;
    USE SIGNAL ;
    PORT
      LAYER M5 ;
        RECT  11.472 0 11.496 0.084 ;
    END
  END i[51]
  PIN i[52]
    DIRECTION INPUT ;
    USE SIGNAL ;
    PORT
      LAYER M3 ;
        RECT  11.664 0 11.682 0.038 ;
    END
  END i[52]
  PIN i[53]
    DIRECTION INPUT ;
    USE SIGNAL ;
    PORT
      LAYER M5 ;
        RECT  11.856 0 11.88 0.084 ;
    END
  END i[53]
  PIN i[54]
    DIRECTION INPUT ;
    USE SIGNAL ;
    PORT
      LAYER M3 ;
        RECT  12.06 0 12.078 0.038 ;
    END
  END i[54]
  PIN i[55]
    DIRECTION INPUT ;
    USE SIGNAL ;
    PORT
      LAYER M5 ;
        RECT  12.24 0 12.264 0.084 ;
    END
  END i[55]
  PIN i[56]
    DIRECTION INPUT ;
    USE SIGNAL ;
    PORT
      LAYER M3 ;
        RECT  12.456 0 12.474 0.038 ;
    END
  END i[56]
  PIN i[57]
    DIRECTION INPUT ;
    USE SIGNAL ;
    PORT
      LAYER M5 ;
        RECT  12.672 0 12.696 0.084 ;
    END
  END i[57]
  PIN i[58]
    DIRECTION INPUT ;
    USE SIGNAL ;
    PORT
      LAYER M3 ;
        RECT  12.888 0 12.906 0.038 ;
    END
  END i[58]
  PIN i[59]
    DIRECTION INPUT ;
    USE SIGNAL ;
    PORT
      LAYER M5 ;
        RECT  13.056 0 13.08 0.084 ;
    END
  END i[59]
  PIN i[5]
    DIRECTION INPUT ;
    USE SIGNAL ;
    PORT
      LAYER M5 ;
        RECT  2.16 0 2.184 0.084 ;
    END
  END i[5]
  PIN i[60]
    DIRECTION INPUT ;
    USE SIGNAL ;
    PORT
      LAYER M3 ;
        RECT  13.284 0 13.302 0.038 ;
    END
  END i[60]
  PIN i[61]
    DIRECTION INPUT ;
    USE SIGNAL ;
    PORT
      LAYER M5 ;
        RECT  13.488 0 13.512 0.084 ;
    END
  END i[61]
  PIN i[62]
    DIRECTION INPUT ;
    USE SIGNAL ;
    PORT
      LAYER M3 ;
        RECT  13.68 0 13.698 0.038 ;
    END
  END i[62]
  PIN i[63]
    DIRECTION INPUT ;
    USE SIGNAL ;
    PORT
      LAYER M5 ;
        RECT  13.872 0 13.896 0.084 ;
    END
  END i[63]
  PIN i[64]
    DIRECTION INPUT ;
    USE SIGNAL ;
    PORT
      LAYER M3 ;
        RECT  14.076 0 14.094 0.038 ;
    END
  END i[64]
  PIN i[65]
    DIRECTION INPUT ;
    USE SIGNAL ;
    PORT
      LAYER M5 ;
        RECT  14.304 0 14.328 0.084 ;
    END
  END i[65]
  PIN i[66]
    DIRECTION INPUT ;
    USE SIGNAL ;
    PORT
      LAYER M3 ;
        RECT  14.472 0 14.49 0.038 ;
    END
  END i[66]
  PIN i[67]
    DIRECTION INPUT ;
    USE SIGNAL ;
    PORT
      LAYER M5 ;
        RECT  14.688 0 14.712 0.084 ;
    END
  END i[67]
  PIN i[68]
    DIRECTION INPUT ;
    USE SIGNAL ;
    PORT
      LAYER M3 ;
        RECT  14.904 0 14.922 0.038 ;
    END
  END i[68]
  PIN i[69]
    DIRECTION INPUT ;
    USE SIGNAL ;
    PORT
      LAYER M5 ;
        RECT  15.072 0 15.096 0.084 ;
    END
  END i[69]
  PIN i[6]
    DIRECTION INPUT ;
    USE SIGNAL ;
    PORT
      LAYER M3 ;
        RECT  2.376 0 2.394 0.038 ;
    END
  END i[6]
  PIN i[70]
    DIRECTION INPUT ;
    USE SIGNAL ;
    PORT
      LAYER M3 ;
        RECT  15.3 0 15.318 0.038 ;
    END
  END i[70]
  PIN i[71]
    DIRECTION INPUT ;
    USE SIGNAL ;
    PORT
      LAYER M5 ;
        RECT  15.504 0 15.528 0.084 ;
    END
  END i[71]
  PIN i[72]
    DIRECTION INPUT ;
    USE SIGNAL ;
    PORT
      LAYER M3 ;
        RECT  15.696 0 15.714 0.038 ;
    END
  END i[72]
  PIN i[73]
    DIRECTION INPUT ;
    USE SIGNAL ;
    PORT
      LAYER M5 ;
        RECT  15.888 0 15.912 0.084 ;
    END
  END i[73]
  PIN i[74]
    DIRECTION INPUT ;
    USE SIGNAL ;
    PORT
      LAYER M3 ;
        RECT  16.092 0 16.11 0.038 ;
    END
  END i[74]
  PIN i[75]
    DIRECTION INPUT ;
    USE SIGNAL ;
    PORT
      LAYER M5 ;
        RECT  16.32 0 16.344 0.084 ;
    END
  END i[75]
  PIN i[76]
    DIRECTION INPUT ;
    USE SIGNAL ;
    PORT
      LAYER M3 ;
        RECT  16.488 0 16.506 0.038 ;
    END
  END i[76]
  PIN i[77]
    DIRECTION INPUT ;
    USE SIGNAL ;
    PORT
      LAYER M5 ;
        RECT  16.704 0 16.728 0.084 ;
    END
  END i[77]
  PIN i[78]
    DIRECTION INPUT ;
    USE SIGNAL ;
    PORT
      LAYER M3 ;
        RECT  16.92 0 16.938 0.038 ;
    END
  END i[78]
  PIN i[79]
    DIRECTION INPUT ;
    USE SIGNAL ;
    PORT
      LAYER M5 ;
        RECT  17.088 0 17.112 0.084 ;
    END
  END i[79]
  PIN i[7]
    DIRECTION INPUT ;
    USE SIGNAL ;
    PORT
      LAYER M5 ;
        RECT  2.592 0 2.616 0.084 ;
    END
  END i[7]
  PIN i[80]
    DIRECTION INPUT ;
    USE SIGNAL ;
    PORT
      LAYER M3 ;
        RECT  17.316 0 17.334 0.038 ;
    END
  END i[80]
  PIN i[81]
    DIRECTION INPUT ;
    USE SIGNAL ;
    PORT
      LAYER M5 ;
        RECT  17.52 0 17.544 0.084 ;
    END
  END i[81]
  PIN i[82]
    DIRECTION INPUT ;
    USE SIGNAL ;
    PORT
      LAYER M3 ;
        RECT  17.712 0 17.73 0.038 ;
    END
  END i[82]
  PIN i[83]
    DIRECTION INPUT ;
    USE SIGNAL ;
    PORT
      LAYER M5 ;
        RECT  17.904 0 17.928 0.084 ;
    END
  END i[83]
  PIN i[84]
    DIRECTION INPUT ;
    USE SIGNAL ;
    PORT
      LAYER M3 ;
        RECT  18.108 0 18.126 0.038 ;
    END
  END i[84]
  PIN i[85]
    DIRECTION INPUT ;
    USE SIGNAL ;
    PORT
      LAYER M5 ;
        RECT  18.336 0 18.36 0.084 ;
    END
  END i[85]
  PIN i[86]
    DIRECTION INPUT ;
    USE SIGNAL ;
    PORT
      LAYER M3 ;
        RECT  18.504 0 18.522 0.038 ;
    END
  END i[86]
  PIN i[87]
    DIRECTION INPUT ;
    USE SIGNAL ;
    PORT
      LAYER M5 ;
        RECT  18.72 0 18.744 0.084 ;
    END
  END i[87]
  PIN i[88]
    DIRECTION INPUT ;
    USE SIGNAL ;
    PORT
      LAYER M3 ;
        RECT  18.936 0 18.954 0.038 ;
    END
  END i[88]
  PIN i[89]
    DIRECTION INPUT ;
    USE SIGNAL ;
    PORT
      LAYER M5 ;
        RECT  19.104 0 19.128 0.084 ;
    END
  END i[89]
  PIN i[8]
    DIRECTION INPUT ;
    USE SIGNAL ;
    PORT
      LAYER M3 ;
        RECT  2.772 0 2.79 0.038 ;
    END
  END i[8]
  PIN i[90]
    DIRECTION INPUT ;
    USE SIGNAL ;
    PORT
      LAYER M3 ;
        RECT  19.332 0 19.35 0.038 ;
    END
  END i[90]
  PIN i[91]
    DIRECTION INPUT ;
    USE SIGNAL ;
    PORT
      LAYER M5 ;
        RECT  19.536 0 19.56 0.084 ;
    END
  END i[91]
  PIN i[92]
    DIRECTION INPUT ;
    USE SIGNAL ;
    PORT
      LAYER M3 ;
        RECT  19.728 0 19.746 0.038 ;
    END
  END i[92]
  PIN i[93]
    DIRECTION INPUT ;
    USE SIGNAL ;
    PORT
      LAYER M5 ;
        RECT  19.92 0 19.944 0.084 ;
    END
  END i[93]
  PIN i[94]
    DIRECTION INPUT ;
    USE SIGNAL ;
    PORT
      LAYER M3 ;
        RECT  20.124 0 20.142 0.038 ;
    END
  END i[94]
  PIN i[95]
    DIRECTION INPUT ;
    USE SIGNAL ;
    PORT
      LAYER M5 ;
        RECT  20.352 0 20.376 0.084 ;
    END
  END i[95]
  PIN i[96]
    DIRECTION INPUT ;
    USE SIGNAL ;
    PORT
      LAYER M3 ;
        RECT  20.52 0 20.538 0.038 ;
    END
  END i[96]
  PIN i[97]
    DIRECTION INPUT ;
    USE SIGNAL ;
    PORT
      LAYER M5 ;
        RECT  20.736 0 20.76 0.084 ;
    END
  END i[97]
  PIN i[98]
    DIRECTION INPUT ;
    USE SIGNAL ;
    PORT
      LAYER M3 ;
        RECT  20.952 0 20.97 0.038 ;
    END
  END i[98]
  PIN i[99]
    DIRECTION INPUT ;
    USE SIGNAL ;
    PORT
      LAYER M5 ;
        RECT  21.12 0 21.144 0.084 ;
    END
  END i[99]
  PIN i[9]
    DIRECTION INPUT ;
    USE SIGNAL ;
    PORT
      LAYER M5 ;
        RECT  2.976 0 3 0.084 ;
    END
  END i[9]
  PIN o[0]
    DIRECTION OUTPUT ;
    USE SIGNAL ;
    PORT
      LAYER M3 ;
        RECT  1.188 43.162 1.206 43.2 ;
    END
  END o[0]
  PIN o[100]
    DIRECTION OUTPUT ;
    USE SIGNAL ;
    PORT
      LAYER M3 ;
        RECT  21.348 43.162 21.366 43.2 ;
    END
  END o[100]
  PIN o[101]
    DIRECTION OUTPUT ;
    USE SIGNAL ;
    PORT
      LAYER M5 ;
        RECT  21.552 43.116 21.576 43.2 ;
    END
  END o[101]
  PIN o[102]
    DIRECTION OUTPUT ;
    USE SIGNAL ;
    PORT
      LAYER M3 ;
        RECT  21.744 43.162 21.762 43.2 ;
    END
  END o[102]
  PIN o[103]
    DIRECTION OUTPUT ;
    USE SIGNAL ;
    PORT
      LAYER M5 ;
        RECT  21.936 43.116 21.96 43.2 ;
    END
  END o[103]
  PIN o[104]
    DIRECTION OUTPUT ;
    USE SIGNAL ;
    PORT
      LAYER M3 ;
        RECT  22.14 43.162 22.158 43.2 ;
    END
  END o[104]
  PIN o[105]
    DIRECTION OUTPUT ;
    USE SIGNAL ;
    PORT
      LAYER M5 ;
        RECT  22.368 43.116 22.392 43.2 ;
    END
  END o[105]
  PIN o[106]
    DIRECTION OUTPUT ;
    USE SIGNAL ;
    PORT
      LAYER M3 ;
        RECT  22.536 43.162 22.554 43.2 ;
    END
  END o[106]
  PIN o[107]
    DIRECTION OUTPUT ;
    USE SIGNAL ;
    PORT
      LAYER M5 ;
        RECT  22.752 43.116 22.776 43.2 ;
    END
  END o[107]
  PIN o[108]
    DIRECTION OUTPUT ;
    USE SIGNAL ;
    PORT
      LAYER M3 ;
        RECT  22.968 43.162 22.986 43.2 ;
    END
  END o[108]
  PIN o[109]
    DIRECTION OUTPUT ;
    USE SIGNAL ;
    PORT
      LAYER M5 ;
        RECT  23.136 43.116 23.16 43.2 ;
    END
  END o[109]
  PIN o[10]
    DIRECTION OUTPUT ;
    USE SIGNAL ;
    PORT
      LAYER M3 ;
        RECT  3.204 43.162 3.222 43.2 ;
    END
  END o[10]
  PIN o[110]
    DIRECTION OUTPUT ;
    USE SIGNAL ;
    PORT
      LAYER M3 ;
        RECT  23.364 43.162 23.382 43.2 ;
    END
  END o[110]
  PIN o[111]
    DIRECTION OUTPUT ;
    USE SIGNAL ;
    PORT
      LAYER M5 ;
        RECT  23.568 43.116 23.592 43.2 ;
    END
  END o[111]
  PIN o[112]
    DIRECTION OUTPUT ;
    USE SIGNAL ;
    PORT
      LAYER M3 ;
        RECT  23.76 43.162 23.778 43.2 ;
    END
  END o[112]
  PIN o[113]
    DIRECTION OUTPUT ;
    USE SIGNAL ;
    PORT
      LAYER M5 ;
        RECT  23.952 43.116 23.976 43.2 ;
    END
  END o[113]
  PIN o[114]
    DIRECTION OUTPUT ;
    USE SIGNAL ;
    PORT
      LAYER M3 ;
        RECT  24.156 43.162 24.174 43.2 ;
    END
  END o[114]
  PIN o[115]
    DIRECTION OUTPUT ;
    USE SIGNAL ;
    PORT
      LAYER M5 ;
        RECT  24.384 43.116 24.408 43.2 ;
    END
  END o[115]
  PIN o[116]
    DIRECTION OUTPUT ;
    USE SIGNAL ;
    PORT
      LAYER M3 ;
        RECT  24.588 43.162 24.606 43.2 ;
    END
  END o[116]
  PIN o[117]
    DIRECTION OUTPUT ;
    USE SIGNAL ;
    PORT
      LAYER M5 ;
        RECT  24.768 43.116 24.792 43.2 ;
    END
  END o[117]
  PIN o[118]
    DIRECTION OUTPUT ;
    USE SIGNAL ;
    PORT
      LAYER M3 ;
        RECT  24.984 43.162 25.002 43.2 ;
    END
  END o[118]
  PIN o[119]
    DIRECTION OUTPUT ;
    USE SIGNAL ;
    PORT
      LAYER M5 ;
        RECT  25.152 43.116 25.176 43.2 ;
    END
  END o[119]
  PIN o[11]
    DIRECTION OUTPUT ;
    USE SIGNAL ;
    PORT
      LAYER M5 ;
        RECT  3.408 43.116 3.432 43.2 ;
    END
  END o[11]
  PIN o[120]
    DIRECTION OUTPUT ;
    USE SIGNAL ;
    PORT
      LAYER M3 ;
        RECT  25.38 43.162 25.398 43.2 ;
    END
  END o[120]
  PIN o[121]
    DIRECTION OUTPUT ;
    USE SIGNAL ;
    PORT
      LAYER M5 ;
        RECT  25.584 43.116 25.608 43.2 ;
    END
  END o[121]
  PIN o[122]
    DIRECTION OUTPUT ;
    USE SIGNAL ;
    PORT
      LAYER M3 ;
        RECT  25.776 43.162 25.794 43.2 ;
    END
  END o[122]
  PIN o[123]
    DIRECTION OUTPUT ;
    USE SIGNAL ;
    PORT
      LAYER M5 ;
        RECT  25.968 43.116 25.992 43.2 ;
    END
  END o[123]
  PIN o[124]
    DIRECTION OUTPUT ;
    USE SIGNAL ;
    PORT
      LAYER M3 ;
        RECT  26.172 43.162 26.19 43.2 ;
    END
  END o[124]
  PIN o[125]
    DIRECTION OUTPUT ;
    USE SIGNAL ;
    PORT
      LAYER M5 ;
        RECT  26.4 43.116 26.424 43.2 ;
    END
  END o[125]
  PIN o[126]
    DIRECTION OUTPUT ;
    USE SIGNAL ;
    PORT
      LAYER M3 ;
        RECT  26.604 43.162 26.622 43.2 ;
    END
  END o[126]
  PIN o[127]
    DIRECTION OUTPUT ;
    USE SIGNAL ;
    PORT
      LAYER M5 ;
        RECT  26.784 43.116 26.808 43.2 ;
    END
  END o[127]
  PIN o[128]
    DIRECTION OUTPUT ;
    USE SIGNAL ;
    PORT
      LAYER M3 ;
        RECT  27 43.162 27.018 43.2 ;
    END
  END o[128]
  PIN o[129]
    DIRECTION OUTPUT ;
    USE SIGNAL ;
    PORT
      LAYER M5 ;
        RECT  27.168 43.116 27.192 43.2 ;
    END
  END o[129]
  PIN o[12]
    DIRECTION OUTPUT ;
    USE SIGNAL ;
    PORT
      LAYER M3 ;
        RECT  3.6 43.162 3.618 43.2 ;
    END
  END o[12]
  PIN o[130]
    DIRECTION OUTPUT ;
    USE SIGNAL ;
    PORT
      LAYER M3 ;
        RECT  27.396 43.162 27.414 43.2 ;
    END
  END o[130]
  PIN o[131]
    DIRECTION OUTPUT ;
    USE SIGNAL ;
    PORT
      LAYER M5 ;
        RECT  27.6 43.116 27.624 43.2 ;
    END
  END o[131]
  PIN o[132]
    DIRECTION OUTPUT ;
    USE SIGNAL ;
    PORT
      LAYER M3 ;
        RECT  27.792 43.162 27.81 43.2 ;
    END
  END o[132]
  PIN o[133]
    DIRECTION OUTPUT ;
    USE SIGNAL ;
    PORT
      LAYER M5 ;
        RECT  27.984 43.116 28.008 43.2 ;
    END
  END o[133]
  PIN o[134]
    DIRECTION OUTPUT ;
    USE SIGNAL ;
    PORT
      LAYER M3 ;
        RECT  28.188 43.162 28.206 43.2 ;
    END
  END o[134]
  PIN o[135]
    DIRECTION OUTPUT ;
    USE SIGNAL ;
    PORT
      LAYER M5 ;
        RECT  28.416 43.116 28.44 43.2 ;
    END
  END o[135]
  PIN o[136]
    DIRECTION OUTPUT ;
    USE SIGNAL ;
    PORT
      LAYER M3 ;
        RECT  28.62 43.162 28.638 43.2 ;
    END
  END o[136]
  PIN o[137]
    DIRECTION OUTPUT ;
    USE SIGNAL ;
    PORT
      LAYER M5 ;
        RECT  28.8 43.116 28.824 43.2 ;
    END
  END o[137]
  PIN o[138]
    DIRECTION OUTPUT ;
    USE SIGNAL ;
    PORT
      LAYER M3 ;
        RECT  29.016 43.162 29.034 43.2 ;
    END
  END o[138]
  PIN o[139]
    DIRECTION OUTPUT ;
    USE SIGNAL ;
    PORT
      LAYER M5 ;
        RECT  29.184 43.116 29.208 43.2 ;
    END
  END o[139]
  PIN o[13]
    DIRECTION OUTPUT ;
    USE SIGNAL ;
    PORT
      LAYER M5 ;
        RECT  3.792 43.116 3.816 43.2 ;
    END
  END o[13]
  PIN o[140]
    DIRECTION OUTPUT ;
    USE SIGNAL ;
    PORT
      LAYER M3 ;
        RECT  29.412 43.162 29.43 43.2 ;
    END
  END o[140]
  PIN o[141]
    DIRECTION OUTPUT ;
    USE SIGNAL ;
    PORT
      LAYER M5 ;
        RECT  29.616 43.116 29.64 43.2 ;
    END
  END o[141]
  PIN o[142]
    DIRECTION OUTPUT ;
    USE SIGNAL ;
    PORT
      LAYER M3 ;
        RECT  29.808 43.162 29.826 43.2 ;
    END
  END o[142]
  PIN o[143]
    DIRECTION OUTPUT ;
    USE SIGNAL ;
    PORT
      LAYER M5 ;
        RECT  30 43.116 30.024 43.2 ;
    END
  END o[143]
  PIN o[144]
    DIRECTION OUTPUT ;
    USE SIGNAL ;
    PORT
      LAYER M3 ;
        RECT  30.204 43.162 30.222 43.2 ;
    END
  END o[144]
  PIN o[145]
    DIRECTION OUTPUT ;
    USE SIGNAL ;
    PORT
      LAYER M5 ;
        RECT  30.432 43.116 30.456 43.2 ;
    END
  END o[145]
  PIN o[146]
    DIRECTION OUTPUT ;
    USE SIGNAL ;
    PORT
      LAYER M3 ;
        RECT  30.636 43.162 30.654 43.2 ;
    END
  END o[146]
  PIN o[147]
    DIRECTION OUTPUT ;
    USE SIGNAL ;
    PORT
      LAYER M5 ;
        RECT  30.816 43.116 30.84 43.2 ;
    END
  END o[147]
  PIN o[148]
    DIRECTION OUTPUT ;
    USE SIGNAL ;
    PORT
      LAYER M3 ;
        RECT  31.032 43.162 31.05 43.2 ;
    END
  END o[148]
  PIN o[149]
    DIRECTION OUTPUT ;
    USE SIGNAL ;
    PORT
      LAYER M5 ;
        RECT  31.248 43.116 31.272 43.2 ;
    END
  END o[149]
  PIN o[14]
    DIRECTION OUTPUT ;
    USE SIGNAL ;
    PORT
      LAYER M3 ;
        RECT  3.996 43.162 4.014 43.2 ;
    END
  END o[14]
  PIN o[150]
    DIRECTION OUTPUT ;
    USE SIGNAL ;
    PORT
      LAYER M3 ;
        RECT  31.428 43.162 31.446 43.2 ;
    END
  END o[150]
  PIN o[151]
    DIRECTION OUTPUT ;
    USE SIGNAL ;
    PORT
      LAYER M5 ;
        RECT  31.632 43.116 31.656 43.2 ;
    END
  END o[151]
  PIN o[152]
    DIRECTION OUTPUT ;
    USE SIGNAL ;
    PORT
      LAYER M3 ;
        RECT  31.824 43.162 31.842 43.2 ;
    END
  END o[152]
  PIN o[153]
    DIRECTION OUTPUT ;
    USE SIGNAL ;
    PORT
      LAYER M5 ;
        RECT  32.016 43.116 32.04 43.2 ;
    END
  END o[153]
  PIN o[154]
    DIRECTION OUTPUT ;
    USE SIGNAL ;
    PORT
      LAYER M3 ;
        RECT  32.22 43.162 32.238 43.2 ;
    END
  END o[154]
  PIN o[155]
    DIRECTION OUTPUT ;
    USE SIGNAL ;
    PORT
      LAYER M5 ;
        RECT  32.448 43.116 32.472 43.2 ;
    END
  END o[155]
  PIN o[156]
    DIRECTION OUTPUT ;
    USE SIGNAL ;
    PORT
      LAYER M3 ;
        RECT  32.652 43.162 32.67 43.2 ;
    END
  END o[156]
  PIN o[157]
    DIRECTION OUTPUT ;
    USE SIGNAL ;
    PORT
      LAYER M5 ;
        RECT  32.832 43.116 32.856 43.2 ;
    END
  END o[157]
  PIN o[158]
    DIRECTION OUTPUT ;
    USE SIGNAL ;
    PORT
      LAYER M3 ;
        RECT  33.048 43.162 33.066 43.2 ;
    END
  END o[158]
  PIN o[159]
    DIRECTION OUTPUT ;
    USE SIGNAL ;
    PORT
      LAYER M5 ;
        RECT  33.264 43.116 33.288 43.2 ;
    END
  END o[159]
  PIN o[15]
    DIRECTION OUTPUT ;
    USE SIGNAL ;
    PORT
      LAYER M5 ;
        RECT  4.176 43.116 4.2 43.2 ;
    END
  END o[15]
  PIN o[160]
    DIRECTION OUTPUT ;
    USE SIGNAL ;
    PORT
      LAYER M3 ;
        RECT  33.444 43.162 33.462 43.2 ;
    END
  END o[160]
  PIN o[161]
    DIRECTION OUTPUT ;
    USE SIGNAL ;
    PORT
      LAYER M5 ;
        RECT  33.648 43.116 33.672 43.2 ;
    END
  END o[161]
  PIN o[162]
    DIRECTION OUTPUT ;
    USE SIGNAL ;
    PORT
      LAYER M3 ;
        RECT  33.84 43.162 33.858 43.2 ;
    END
  END o[162]
  PIN o[163]
    DIRECTION OUTPUT ;
    USE SIGNAL ;
    PORT
      LAYER M5 ;
        RECT  34.032 43.116 34.056 43.2 ;
    END
  END o[163]
  PIN o[164]
    DIRECTION OUTPUT ;
    USE SIGNAL ;
    PORT
      LAYER M3 ;
        RECT  34.236 43.162 34.254 43.2 ;
    END
  END o[164]
  PIN o[165]
    DIRECTION OUTPUT ;
    USE SIGNAL ;
    PORT
      LAYER M5 ;
        RECT  34.464 43.116 34.488 43.2 ;
    END
  END o[165]
  PIN o[166]
    DIRECTION OUTPUT ;
    USE SIGNAL ;
    PORT
      LAYER M3 ;
        RECT  34.668 43.162 34.686 43.2 ;
    END
  END o[166]
  PIN o[167]
    DIRECTION OUTPUT ;
    USE SIGNAL ;
    PORT
      LAYER M5 ;
        RECT  34.848 43.116 34.872 43.2 ;
    END
  END o[167]
  PIN o[168]
    DIRECTION OUTPUT ;
    USE SIGNAL ;
    PORT
      LAYER M3 ;
        RECT  35.064 43.162 35.082 43.2 ;
    END
  END o[168]
  PIN o[169]
    DIRECTION OUTPUT ;
    USE SIGNAL ;
    PORT
      LAYER M5 ;
        RECT  35.28 43.116 35.304 43.2 ;
    END
  END o[169]
  PIN o[16]
    DIRECTION OUTPUT ;
    USE SIGNAL ;
    PORT
      LAYER M3 ;
        RECT  4.392 43.162 4.41 43.2 ;
    END
  END o[16]
  PIN o[170]
    DIRECTION OUTPUT ;
    USE SIGNAL ;
    PORT
      LAYER M3 ;
        RECT  35.46 43.162 35.478 43.2 ;
    END
  END o[170]
  PIN o[171]
    DIRECTION OUTPUT ;
    USE SIGNAL ;
    PORT
      LAYER M5 ;
        RECT  35.664 43.116 35.688 43.2 ;
    END
  END o[171]
  PIN o[172]
    DIRECTION OUTPUT ;
    USE SIGNAL ;
    PORT
      LAYER M3 ;
        RECT  35.856 43.162 35.874 43.2 ;
    END
  END o[172]
  PIN o[173]
    DIRECTION OUTPUT ;
    USE SIGNAL ;
    PORT
      LAYER M5 ;
        RECT  36.048 43.116 36.072 43.2 ;
    END
  END o[173]
  PIN o[174]
    DIRECTION OUTPUT ;
    USE SIGNAL ;
    PORT
      LAYER M3 ;
        RECT  36.288 43.162 36.306 43.2 ;
    END
  END o[174]
  PIN o[175]
    DIRECTION OUTPUT ;
    USE SIGNAL ;
    PORT
      LAYER M5 ;
        RECT  36.48 43.116 36.504 43.2 ;
    END
  END o[175]
  PIN o[176]
    DIRECTION OUTPUT ;
    USE SIGNAL ;
    PORT
      LAYER M3 ;
        RECT  36.684 43.162 36.702 43.2 ;
    END
  END o[176]
  PIN o[177]
    DIRECTION OUTPUT ;
    USE SIGNAL ;
    PORT
      LAYER M5 ;
        RECT  36.864 43.116 36.888 43.2 ;
    END
  END o[177]
  PIN o[178]
    DIRECTION OUTPUT ;
    USE SIGNAL ;
    PORT
      LAYER M3 ;
        RECT  37.08 43.162 37.098 43.2 ;
    END
  END o[178]
  PIN o[179]
    DIRECTION OUTPUT ;
    USE SIGNAL ;
    PORT
      LAYER M5 ;
        RECT  37.296 43.116 37.32 43.2 ;
    END
  END o[179]
  PIN o[17]
    DIRECTION OUTPUT ;
    USE SIGNAL ;
    PORT
      LAYER M5 ;
        RECT  4.608 43.116 4.632 43.2 ;
    END
  END o[17]
  PIN o[180]
    DIRECTION OUTPUT ;
    USE SIGNAL ;
    PORT
      LAYER M3 ;
        RECT  37.476 43.162 37.494 43.2 ;
    END
  END o[180]
  PIN o[181]
    DIRECTION OUTPUT ;
    USE SIGNAL ;
    PORT
      LAYER M5 ;
        RECT  37.68 43.116 37.704 43.2 ;
    END
  END o[181]
  PIN o[182]
    DIRECTION OUTPUT ;
    USE SIGNAL ;
    PORT
      LAYER M3 ;
        RECT  37.872 43.162 37.89 43.2 ;
    END
  END o[182]
  PIN o[183]
    DIRECTION OUTPUT ;
    USE SIGNAL ;
    PORT
      LAYER M5 ;
        RECT  38.064 43.116 38.088 43.2 ;
    END
  END o[183]
  PIN o[184]
    DIRECTION OUTPUT ;
    USE SIGNAL ;
    PORT
      LAYER M3 ;
        RECT  38.304 43.162 38.322 43.2 ;
    END
  END o[184]
  PIN o[185]
    DIRECTION OUTPUT ;
    USE SIGNAL ;
    PORT
      LAYER M5 ;
        RECT  38.496 43.116 38.52 43.2 ;
    END
  END o[185]
  PIN o[186]
    DIRECTION OUTPUT ;
    USE SIGNAL ;
    PORT
      LAYER M3 ;
        RECT  38.7 43.162 38.718 43.2 ;
    END
  END o[186]
  PIN o[187]
    DIRECTION OUTPUT ;
    USE SIGNAL ;
    PORT
      LAYER M5 ;
        RECT  38.88 43.116 38.904 43.2 ;
    END
  END o[187]
  PIN o[188]
    DIRECTION OUTPUT ;
    USE SIGNAL ;
    PORT
      LAYER M3 ;
        RECT  39.096 43.162 39.114 43.2 ;
    END
  END o[188]
  PIN o[189]
    DIRECTION OUTPUT ;
    USE SIGNAL ;
    PORT
      LAYER M5 ;
        RECT  39.312 43.116 39.336 43.2 ;
    END
  END o[189]
  PIN o[18]
    DIRECTION OUTPUT ;
    USE SIGNAL ;
    PORT
      LAYER M3 ;
        RECT  4.788 43.162 4.806 43.2 ;
    END
  END o[18]
  PIN o[190]
    DIRECTION OUTPUT ;
    USE SIGNAL ;
    PORT
      LAYER M3 ;
        RECT  39.492 43.162 39.51 43.2 ;
    END
  END o[190]
  PIN o[191]
    DIRECTION OUTPUT ;
    USE SIGNAL ;
    PORT
      LAYER M5 ;
        RECT  39.696 43.116 39.72 43.2 ;
    END
  END o[191]
  PIN o[192]
    DIRECTION OUTPUT ;
    USE SIGNAL ;
    PORT
      LAYER M3 ;
        RECT  39.888 43.162 39.906 43.2 ;
    END
  END o[192]
  PIN o[193]
    DIRECTION OUTPUT ;
    USE SIGNAL ;
    PORT
      LAYER M5 ;
        RECT  40.08 43.116 40.104 43.2 ;
    END
  END o[193]
  PIN o[194]
    DIRECTION OUTPUT ;
    USE SIGNAL ;
    PORT
      LAYER M3 ;
        RECT  40.32 43.162 40.338 43.2 ;
    END
  END o[194]
  PIN o[195]
    DIRECTION OUTPUT ;
    USE SIGNAL ;
    PORT
      LAYER M5 ;
        RECT  40.512 43.116 40.536 43.2 ;
    END
  END o[195]
  PIN o[196]
    DIRECTION OUTPUT ;
    USE SIGNAL ;
    PORT
      LAYER M3 ;
        RECT  40.716 43.162 40.734 43.2 ;
    END
  END o[196]
  PIN o[197]
    DIRECTION OUTPUT ;
    USE SIGNAL ;
    PORT
      LAYER M5 ;
        RECT  40.896 43.116 40.92 43.2 ;
    END
  END o[197]
  PIN o[198]
    DIRECTION OUTPUT ;
    USE SIGNAL ;
    PORT
      LAYER M3 ;
        RECT  41.112 43.162 41.13 43.2 ;
    END
  END o[198]
  PIN o[199]
    DIRECTION OUTPUT ;
    USE SIGNAL ;
    PORT
      LAYER M5 ;
        RECT  41.328 43.116 41.352 43.2 ;
    END
  END o[199]
  PIN o[19]
    DIRECTION OUTPUT ;
    USE SIGNAL ;
    PORT
      LAYER M5 ;
        RECT  4.992 43.116 5.016 43.2 ;
    END
  END o[19]
  PIN o[1]
    DIRECTION OUTPUT ;
    USE SIGNAL ;
    PORT
      LAYER M5 ;
        RECT  1.392 43.116 1.416 43.2 ;
    END
  END o[1]
  PIN o[200]
    DIRECTION OUTPUT ;
    USE SIGNAL ;
    PORT
      LAYER M3 ;
        RECT  41.508 43.162 41.526 43.2 ;
    END
  END o[200]
  PIN o[201]
    DIRECTION OUTPUT ;
    USE SIGNAL ;
    PORT
      LAYER M5 ;
        RECT  41.712 43.116 41.736 43.2 ;
    END
  END o[201]
  PIN o[202]
    DIRECTION OUTPUT ;
    USE SIGNAL ;
    PORT
      LAYER M3 ;
        RECT  41.904 43.162 41.922 43.2 ;
    END
  END o[202]
  PIN o[203]
    DIRECTION OUTPUT ;
    USE SIGNAL ;
    PORT
      LAYER M5 ;
        RECT  42.096 43.116 42.12 43.2 ;
    END
  END o[203]
  PIN o[204]
    DIRECTION OUTPUT ;
    USE SIGNAL ;
    PORT
      LAYER M3 ;
        RECT  42.336 43.162 42.354 43.2 ;
    END
  END o[204]
  PIN o[205]
    DIRECTION OUTPUT ;
    USE SIGNAL ;
    PORT
      LAYER M5 ;
        RECT  42.528 43.116 42.552 43.2 ;
    END
  END o[205]
  PIN o[206]
    DIRECTION OUTPUT ;
    USE SIGNAL ;
    PORT
      LAYER M3 ;
        RECT  42.732 43.162 42.75 43.2 ;
    END
  END o[206]
  PIN o[207]
    DIRECTION OUTPUT ;
    USE SIGNAL ;
    PORT
      LAYER M5 ;
        RECT  42.912 43.116 42.936 43.2 ;
    END
  END o[207]
  PIN o[208]
    DIRECTION OUTPUT ;
    USE SIGNAL ;
    PORT
      LAYER M3 ;
        RECT  43.128 43.162 43.146 43.2 ;
    END
  END o[208]
  PIN o[209]
    DIRECTION OUTPUT ;
    USE SIGNAL ;
    PORT
      LAYER M5 ;
        RECT  43.344 43.116 43.368 43.2 ;
    END
  END o[209]
  PIN o[20]
    DIRECTION OUTPUT ;
    USE SIGNAL ;
    PORT
      LAYER M3 ;
        RECT  5.22 43.162 5.238 43.2 ;
    END
  END o[20]
  PIN o[210]
    DIRECTION OUTPUT ;
    USE SIGNAL ;
    PORT
      LAYER M3 ;
        RECT  43.524 43.162 43.542 43.2 ;
    END
  END o[210]
  PIN o[211]
    DIRECTION OUTPUT ;
    USE SIGNAL ;
    PORT
      LAYER M5 ;
        RECT  43.728 43.116 43.752 43.2 ;
    END
  END o[211]
  PIN o[212]
    DIRECTION OUTPUT ;
    USE SIGNAL ;
    PORT
      LAYER M3 ;
        RECT  43.92 43.162 43.938 43.2 ;
    END
  END o[212]
  PIN o[213]
    DIRECTION OUTPUT ;
    USE SIGNAL ;
    PORT
      LAYER M5 ;
        RECT  44.112 43.116 44.136 43.2 ;
    END
  END o[213]
  PIN o[214]
    DIRECTION OUTPUT ;
    USE SIGNAL ;
    PORT
      LAYER M3 ;
        RECT  44.352 43.162 44.37 43.2 ;
    END
  END o[214]
  PIN o[215]
    DIRECTION OUTPUT ;
    USE SIGNAL ;
    PORT
      LAYER M5 ;
        RECT  44.544 43.116 44.568 43.2 ;
    END
  END o[215]
  PIN o[216]
    DIRECTION OUTPUT ;
    USE SIGNAL ;
    PORT
      LAYER M3 ;
        RECT  44.748 43.162 44.766 43.2 ;
    END
  END o[216]
  PIN o[217]
    DIRECTION OUTPUT ;
    USE SIGNAL ;
    PORT
      LAYER M5 ;
        RECT  44.928 43.116 44.952 43.2 ;
    END
  END o[217]
  PIN o[218]
    DIRECTION OUTPUT ;
    USE SIGNAL ;
    PORT
      LAYER M3 ;
        RECT  45.144 43.162 45.162 43.2 ;
    END
  END o[218]
  PIN o[219]
    DIRECTION OUTPUT ;
    USE SIGNAL ;
    PORT
      LAYER M5 ;
        RECT  45.36 43.116 45.384 43.2 ;
    END
  END o[219]
  PIN o[21]
    DIRECTION OUTPUT ;
    USE SIGNAL ;
    PORT
      LAYER M5 ;
        RECT  5.424 43.116 5.448 43.2 ;
    END
  END o[21]
  PIN o[220]
    DIRECTION OUTPUT ;
    USE SIGNAL ;
    PORT
      LAYER M3 ;
        RECT  45.54 43.162 45.558 43.2 ;
    END
  END o[220]
  PIN o[221]
    DIRECTION OUTPUT ;
    USE SIGNAL ;
    PORT
      LAYER M5 ;
        RECT  45.744 43.116 45.768 43.2 ;
    END
  END o[221]
  PIN o[222]
    DIRECTION OUTPUT ;
    USE SIGNAL ;
    PORT
      LAYER M3 ;
        RECT  45.936 43.162 45.954 43.2 ;
    END
  END o[222]
  PIN o[223]
    DIRECTION OUTPUT ;
    USE SIGNAL ;
    PORT
      LAYER M5 ;
        RECT  46.128 43.116 46.152 43.2 ;
    END
  END o[223]
  PIN o[224]
    DIRECTION OUTPUT ;
    USE SIGNAL ;
    PORT
      LAYER M3 ;
        RECT  46.368 43.162 46.386 43.2 ;
    END
  END o[224]
  PIN o[225]
    DIRECTION OUTPUT ;
    USE SIGNAL ;
    PORT
      LAYER M5 ;
        RECT  46.56 43.116 46.584 43.2 ;
    END
  END o[225]
  PIN o[226]
    DIRECTION OUTPUT ;
    USE SIGNAL ;
    PORT
      LAYER M3 ;
        RECT  46.764 43.162 46.782 43.2 ;
    END
  END o[226]
  PIN o[227]
    DIRECTION OUTPUT ;
    USE SIGNAL ;
    PORT
      LAYER M5 ;
        RECT  46.944 43.116 46.968 43.2 ;
    END
  END o[227]
  PIN o[228]
    DIRECTION OUTPUT ;
    USE SIGNAL ;
    PORT
      LAYER M3 ;
        RECT  47.16 43.162 47.178 43.2 ;
    END
  END o[228]
  PIN o[229]
    DIRECTION OUTPUT ;
    USE SIGNAL ;
    PORT
      LAYER M5 ;
        RECT  47.376 43.116 47.4 43.2 ;
    END
  END o[229]
  PIN o[22]
    DIRECTION OUTPUT ;
    USE SIGNAL ;
    PORT
      LAYER M3 ;
        RECT  5.616 43.162 5.634 43.2 ;
    END
  END o[22]
  PIN o[230]
    DIRECTION OUTPUT ;
    USE SIGNAL ;
    PORT
      LAYER M3 ;
        RECT  47.556 43.162 47.574 43.2 ;
    END
  END o[230]
  PIN o[231]
    DIRECTION OUTPUT ;
    USE SIGNAL ;
    PORT
      LAYER M5 ;
        RECT  47.76 43.116 47.784 43.2 ;
    END
  END o[231]
  PIN o[232]
    DIRECTION OUTPUT ;
    USE SIGNAL ;
    PORT
      LAYER M3 ;
        RECT  47.952 43.162 47.97 43.2 ;
    END
  END o[232]
  PIN o[233]
    DIRECTION OUTPUT ;
    USE SIGNAL ;
    PORT
      LAYER M5 ;
        RECT  48.192 43.116 48.216 43.2 ;
    END
  END o[233]
  PIN o[234]
    DIRECTION OUTPUT ;
    USE SIGNAL ;
    PORT
      LAYER M3 ;
        RECT  48.384 43.162 48.402 43.2 ;
    END
  END o[234]
  PIN o[235]
    DIRECTION OUTPUT ;
    USE SIGNAL ;
    PORT
      LAYER M5 ;
        RECT  48.576 43.116 48.6 43.2 ;
    END
  END o[235]
  PIN o[236]
    DIRECTION OUTPUT ;
    USE SIGNAL ;
    PORT
      LAYER M3 ;
        RECT  48.78 43.162 48.798 43.2 ;
    END
  END o[236]
  PIN o[237]
    DIRECTION OUTPUT ;
    USE SIGNAL ;
    PORT
      LAYER M5 ;
        RECT  48.96 43.116 48.984 43.2 ;
    END
  END o[237]
  PIN o[238]
    DIRECTION OUTPUT ;
    USE SIGNAL ;
    PORT
      LAYER M3 ;
        RECT  49.176 43.162 49.194 43.2 ;
    END
  END o[238]
  PIN o[239]
    DIRECTION OUTPUT ;
    USE SIGNAL ;
    PORT
      LAYER M5 ;
        RECT  49.392 43.116 49.416 43.2 ;
    END
  END o[239]
  PIN o[23]
    DIRECTION OUTPUT ;
    USE SIGNAL ;
    PORT
      LAYER M5 ;
        RECT  5.808 43.116 5.832 43.2 ;
    END
  END o[23]
  PIN o[240]
    DIRECTION OUTPUT ;
    USE SIGNAL ;
    PORT
      LAYER M3 ;
        RECT  49.572 43.162 49.59 43.2 ;
    END
  END o[240]
  PIN o[241]
    DIRECTION OUTPUT ;
    USE SIGNAL ;
    PORT
      LAYER M5 ;
        RECT  49.776 43.116 49.8 43.2 ;
    END
  END o[241]
  PIN o[242]
    DIRECTION OUTPUT ;
    USE SIGNAL ;
    PORT
      LAYER M3 ;
        RECT  50.004 43.162 50.022 43.2 ;
    END
  END o[242]
  PIN o[243]
    DIRECTION OUTPUT ;
    USE SIGNAL ;
    PORT
      LAYER M5 ;
        RECT  50.208 43.116 50.232 43.2 ;
    END
  END o[243]
  PIN o[244]
    DIRECTION OUTPUT ;
    USE SIGNAL ;
    PORT
      LAYER M3 ;
        RECT  50.4 43.162 50.418 43.2 ;
    END
  END o[244]
  PIN o[245]
    DIRECTION OUTPUT ;
    USE SIGNAL ;
    PORT
      LAYER M5 ;
        RECT  50.592 43.116 50.616 43.2 ;
    END
  END o[245]
  PIN o[246]
    DIRECTION OUTPUT ;
    USE SIGNAL ;
    PORT
      LAYER M3 ;
        RECT  50.796 43.162 50.814 43.2 ;
    END
  END o[246]
  PIN o[247]
    DIRECTION OUTPUT ;
    USE SIGNAL ;
    PORT
      LAYER M5 ;
        RECT  50.976 43.116 51 43.2 ;
    END
  END o[247]
  PIN o[248]
    DIRECTION OUTPUT ;
    USE SIGNAL ;
    PORT
      LAYER M3 ;
        RECT  51.192 43.162 51.21 43.2 ;
    END
  END o[248]
  PIN o[249]
    DIRECTION OUTPUT ;
    USE SIGNAL ;
    PORT
      LAYER M5 ;
        RECT  51.408 43.116 51.432 43.2 ;
    END
  END o[249]
  PIN o[24]
    DIRECTION OUTPUT ;
    USE SIGNAL ;
    PORT
      LAYER M3 ;
        RECT  6.012 43.162 6.03 43.2 ;
    END
  END o[24]
  PIN o[250]
    DIRECTION OUTPUT ;
    USE SIGNAL ;
    PORT
      LAYER M3 ;
        RECT  51.588 43.162 51.606 43.2 ;
    END
  END o[250]
  PIN o[251]
    DIRECTION OUTPUT ;
    USE SIGNAL ;
    PORT
      LAYER M5 ;
        RECT  51.792 43.116 51.816 43.2 ;
    END
  END o[251]
  PIN o[252]
    DIRECTION OUTPUT ;
    USE SIGNAL ;
    PORT
      LAYER M3 ;
        RECT  52.02 43.162 52.038 43.2 ;
    END
  END o[252]
  PIN o[253]
    DIRECTION OUTPUT ;
    USE SIGNAL ;
    PORT
      LAYER M5 ;
        RECT  52.224 43.116 52.248 43.2 ;
    END
  END o[253]
  PIN o[254]
    DIRECTION OUTPUT ;
    USE SIGNAL ;
    PORT
      LAYER M3 ;
        RECT  52.416 43.162 52.434 43.2 ;
    END
  END o[254]
  PIN o[255]
    DIRECTION OUTPUT ;
    USE SIGNAL ;
    PORT
      LAYER M5 ;
        RECT  52.608 43.116 52.632 43.2 ;
    END
  END o[255]
  PIN o[256]
    DIRECTION OUTPUT ;
    USE SIGNAL ;
    PORT
      LAYER M3 ;
        RECT  52.812 43.162 52.83 43.2 ;
    END
  END o[256]
  PIN o[257]
    DIRECTION OUTPUT ;
    USE SIGNAL ;
    PORT
      LAYER M5 ;
        RECT  52.992 43.116 53.016 43.2 ;
    END
  END o[257]
  PIN o[258]
    DIRECTION OUTPUT ;
    USE SIGNAL ;
    PORT
      LAYER M3 ;
        RECT  53.208 43.162 53.226 43.2 ;
    END
  END o[258]
  PIN o[259]
    DIRECTION OUTPUT ;
    USE SIGNAL ;
    PORT
      LAYER M5 ;
        RECT  53.424 43.116 53.448 43.2 ;
    END
  END o[259]
  PIN o[25]
    DIRECTION OUTPUT ;
    USE SIGNAL ;
    PORT
      LAYER M5 ;
        RECT  6.192 43.116 6.216 43.2 ;
    END
  END o[25]
  PIN o[260]
    DIRECTION OUTPUT ;
    USE SIGNAL ;
    PORT
      LAYER M3 ;
        RECT  53.604 43.162 53.622 43.2 ;
    END
  END o[260]
  PIN o[261]
    DIRECTION OUTPUT ;
    USE SIGNAL ;
    PORT
      LAYER M5 ;
        RECT  53.808 43.116 53.832 43.2 ;
    END
  END o[261]
  PIN o[262]
    DIRECTION OUTPUT ;
    USE SIGNAL ;
    PORT
      LAYER M3 ;
        RECT  54.036 43.162 54.054 43.2 ;
    END
  END o[262]
  PIN o[263]
    DIRECTION OUTPUT ;
    USE SIGNAL ;
    PORT
      LAYER M5 ;
        RECT  54.24 43.116 54.264 43.2 ;
    END
  END o[263]
  PIN o[264]
    DIRECTION OUTPUT ;
    USE SIGNAL ;
    PORT
      LAYER M3 ;
        RECT  54.432 43.162 54.45 43.2 ;
    END
  END o[264]
  PIN o[265]
    DIRECTION OUTPUT ;
    USE SIGNAL ;
    PORT
      LAYER M5 ;
        RECT  54.624 43.116 54.648 43.2 ;
    END
  END o[265]
  PIN o[266]
    DIRECTION OUTPUT ;
    USE SIGNAL ;
    PORT
      LAYER M3 ;
        RECT  54.828 43.162 54.846 43.2 ;
    END
  END o[266]
  PIN o[267]
    DIRECTION OUTPUT ;
    USE SIGNAL ;
    PORT
      LAYER M5 ;
        RECT  55.008 43.116 55.032 43.2 ;
    END
  END o[267]
  PIN o[268]
    DIRECTION OUTPUT ;
    USE SIGNAL ;
    PORT
      LAYER M3 ;
        RECT  55.224 43.162 55.242 43.2 ;
    END
  END o[268]
  PIN o[269]
    DIRECTION OUTPUT ;
    USE SIGNAL ;
    PORT
      LAYER M5 ;
        RECT  55.44 43.116 55.464 43.2 ;
    END
  END o[269]
  PIN o[26]
    DIRECTION OUTPUT ;
    USE SIGNAL ;
    PORT
      LAYER M3 ;
        RECT  6.408 43.162 6.426 43.2 ;
    END
  END o[26]
  PIN o[270]
    DIRECTION OUTPUT ;
    USE SIGNAL ;
    PORT
      LAYER M3 ;
        RECT  55.62 43.162 55.638 43.2 ;
    END
  END o[270]
  PIN o[271]
    DIRECTION OUTPUT ;
    USE SIGNAL ;
    PORT
      LAYER M5 ;
        RECT  55.824 43.116 55.848 43.2 ;
    END
  END o[271]
  PIN o[272]
    DIRECTION OUTPUT ;
    USE SIGNAL ;
    PORT
      LAYER M3 ;
        RECT  56.052 43.162 56.07 43.2 ;
    END
  END o[272]
  PIN o[273]
    DIRECTION OUTPUT ;
    USE SIGNAL ;
    PORT
      LAYER M5 ;
        RECT  56.256 43.116 56.28 43.2 ;
    END
  END o[273]
  PIN o[274]
    DIRECTION OUTPUT ;
    USE SIGNAL ;
    PORT
      LAYER M3 ;
        RECT  56.448 43.162 56.466 43.2 ;
    END
  END o[274]
  PIN o[275]
    DIRECTION OUTPUT ;
    USE SIGNAL ;
    PORT
      LAYER M5 ;
        RECT  56.64 43.116 56.664 43.2 ;
    END
  END o[275]
  PIN o[276]
    DIRECTION OUTPUT ;
    USE SIGNAL ;
    PORT
      LAYER M3 ;
        RECT  56.844 43.162 56.862 43.2 ;
    END
  END o[276]
  PIN o[277]
    DIRECTION OUTPUT ;
    USE SIGNAL ;
    PORT
      LAYER M5 ;
        RECT  57.024 43.116 57.048 43.2 ;
    END
  END o[277]
  PIN o[278]
    DIRECTION OUTPUT ;
    USE SIGNAL ;
    PORT
      LAYER M3 ;
        RECT  57.24 43.162 57.258 43.2 ;
    END
  END o[278]
  PIN o[279]
    DIRECTION OUTPUT ;
    USE SIGNAL ;
    PORT
      LAYER M5 ;
        RECT  57.456 43.116 57.48 43.2 ;
    END
  END o[279]
  PIN o[27]
    DIRECTION OUTPUT ;
    USE SIGNAL ;
    PORT
      LAYER M5 ;
        RECT  6.624 43.116 6.648 43.2 ;
    END
  END o[27]
  PIN o[280]
    DIRECTION OUTPUT ;
    USE SIGNAL ;
    PORT
      LAYER M3 ;
        RECT  57.636 43.162 57.654 43.2 ;
    END
  END o[280]
  PIN o[281]
    DIRECTION OUTPUT ;
    USE SIGNAL ;
    PORT
      LAYER M5 ;
        RECT  57.84 43.116 57.864 43.2 ;
    END
  END o[281]
  PIN o[282]
    DIRECTION OUTPUT ;
    USE SIGNAL ;
    PORT
      LAYER M3 ;
        RECT  58.068 43.162 58.086 43.2 ;
    END
  END o[282]
  PIN o[283]
    DIRECTION OUTPUT ;
    USE SIGNAL ;
    PORT
      LAYER M5 ;
        RECT  58.272 43.116 58.296 43.2 ;
    END
  END o[283]
  PIN o[284]
    DIRECTION OUTPUT ;
    USE SIGNAL ;
    PORT
      LAYER M3 ;
        RECT  58.464 43.162 58.482 43.2 ;
    END
  END o[284]
  PIN o[285]
    DIRECTION OUTPUT ;
    USE SIGNAL ;
    PORT
      LAYER M5 ;
        RECT  58.656 43.116 58.68 43.2 ;
    END
  END o[285]
  PIN o[286]
    DIRECTION OUTPUT ;
    USE SIGNAL ;
    PORT
      LAYER M3 ;
        RECT  58.86 43.162 58.878 43.2 ;
    END
  END o[286]
  PIN o[287]
    DIRECTION OUTPUT ;
    USE SIGNAL ;
    PORT
      LAYER M5 ;
        RECT  59.04 43.116 59.064 43.2 ;
    END
  END o[287]
  PIN o[288]
    DIRECTION OUTPUT ;
    USE SIGNAL ;
    PORT
      LAYER M3 ;
        RECT  59.256 43.162 59.274 43.2 ;
    END
  END o[288]
  PIN o[289]
    DIRECTION OUTPUT ;
    USE SIGNAL ;
    PORT
      LAYER M5 ;
        RECT  59.472 43.116 59.496 43.2 ;
    END
  END o[289]
  PIN o[28]
    DIRECTION OUTPUT ;
    USE SIGNAL ;
    PORT
      LAYER M3 ;
        RECT  6.804 43.162 6.822 43.2 ;
    END
  END o[28]
  PIN o[290]
    DIRECTION OUTPUT ;
    USE SIGNAL ;
    PORT
      LAYER M3 ;
        RECT  59.652 43.162 59.67 43.2 ;
    END
  END o[290]
  PIN o[291]
    DIRECTION OUTPUT ;
    USE SIGNAL ;
    PORT
      LAYER M5 ;
        RECT  59.856 43.116 59.88 43.2 ;
    END
  END o[291]
  PIN o[292]
    DIRECTION OUTPUT ;
    USE SIGNAL ;
    PORT
      LAYER M3 ;
        RECT  60.084 43.162 60.102 43.2 ;
    END
  END o[292]
  PIN o[293]
    DIRECTION OUTPUT ;
    USE SIGNAL ;
    PORT
      LAYER M5 ;
        RECT  60.288 43.116 60.312 43.2 ;
    END
  END o[293]
  PIN o[294]
    DIRECTION OUTPUT ;
    USE SIGNAL ;
    PORT
      LAYER M3 ;
        RECT  60.48 43.162 60.498 43.2 ;
    END
  END o[294]
  PIN o[295]
    DIRECTION OUTPUT ;
    USE SIGNAL ;
    PORT
      LAYER M5 ;
        RECT  60.672 43.116 60.696 43.2 ;
    END
  END o[295]
  PIN o[296]
    DIRECTION OUTPUT ;
    USE SIGNAL ;
    PORT
      LAYER M3 ;
        RECT  60.876 43.162 60.894 43.2 ;
    END
  END o[296]
  PIN o[297]
    DIRECTION OUTPUT ;
    USE SIGNAL ;
    PORT
      LAYER M5 ;
        RECT  61.056 43.116 61.08 43.2 ;
    END
  END o[297]
  PIN o[298]
    DIRECTION OUTPUT ;
    USE SIGNAL ;
    PORT
      LAYER M3 ;
        RECT  61.272 43.162 61.29 43.2 ;
    END
  END o[298]
  PIN o[299]
    DIRECTION OUTPUT ;
    USE SIGNAL ;
    PORT
      LAYER M5 ;
        RECT  61.488 43.116 61.512 43.2 ;
    END
  END o[299]
  PIN o[29]
    DIRECTION OUTPUT ;
    USE SIGNAL ;
    PORT
      LAYER M5 ;
        RECT  7.008 43.116 7.032 43.2 ;
    END
  END o[29]
  PIN o[2]
    DIRECTION OUTPUT ;
    USE SIGNAL ;
    PORT
      LAYER M3 ;
        RECT  1.584 43.162 1.602 43.2 ;
    END
  END o[2]
  PIN o[300]
    DIRECTION OUTPUT ;
    USE SIGNAL ;
    PORT
      LAYER M3 ;
        RECT  61.668 43.162 61.686 43.2 ;
    END
  END o[300]
  PIN o[301]
    DIRECTION OUTPUT ;
    USE SIGNAL ;
    PORT
      LAYER M5 ;
        RECT  61.872 43.116 61.896 43.2 ;
    END
  END o[301]
  PIN o[302]
    DIRECTION OUTPUT ;
    USE SIGNAL ;
    PORT
      LAYER M3 ;
        RECT  62.1 43.162 62.118 43.2 ;
    END
  END o[302]
  PIN o[303]
    DIRECTION OUTPUT ;
    USE SIGNAL ;
    PORT
      LAYER M5 ;
        RECT  62.304 43.116 62.328 43.2 ;
    END
  END o[303]
  PIN o[304]
    DIRECTION OUTPUT ;
    USE SIGNAL ;
    PORT
      LAYER M3 ;
        RECT  62.496 43.162 62.514 43.2 ;
    END
  END o[304]
  PIN o[305]
    DIRECTION OUTPUT ;
    USE SIGNAL ;
    PORT
      LAYER M5 ;
        RECT  62.688 43.116 62.712 43.2 ;
    END
  END o[305]
  PIN o[306]
    DIRECTION OUTPUT ;
    USE SIGNAL ;
    PORT
      LAYER M3 ;
        RECT  62.892 43.162 62.91 43.2 ;
    END
  END o[306]
  PIN o[307]
    DIRECTION OUTPUT ;
    USE SIGNAL ;
    PORT
      LAYER M5 ;
        RECT  63.072 43.116 63.096 43.2 ;
    END
  END o[307]
  PIN o[308]
    DIRECTION OUTPUT ;
    USE SIGNAL ;
    PORT
      LAYER M3 ;
        RECT  63.288 43.162 63.306 43.2 ;
    END
  END o[308]
  PIN o[309]
    DIRECTION OUTPUT ;
    USE SIGNAL ;
    PORT
      LAYER M5 ;
        RECT  63.504 43.116 63.528 43.2 ;
    END
  END o[309]
  PIN o[30]
    DIRECTION OUTPUT ;
    USE SIGNAL ;
    PORT
      LAYER M3 ;
        RECT  7.236 43.162 7.254 43.2 ;
    END
  END o[30]
  PIN o[310]
    DIRECTION OUTPUT ;
    USE SIGNAL ;
    PORT
      LAYER M3 ;
        RECT  63.72 43.162 63.738 43.2 ;
    END
  END o[310]
  PIN o[311]
    DIRECTION OUTPUT ;
    USE SIGNAL ;
    PORT
      LAYER M5 ;
        RECT  63.888 43.116 63.912 43.2 ;
    END
  END o[311]
  PIN o[312]
    DIRECTION OUTPUT ;
    USE SIGNAL ;
    PORT
      LAYER M3 ;
        RECT  64.116 43.162 64.134 43.2 ;
    END
  END o[312]
  PIN o[313]
    DIRECTION OUTPUT ;
    USE SIGNAL ;
    PORT
      LAYER M5 ;
        RECT  64.32 43.116 64.344 43.2 ;
    END
  END o[313]
  PIN o[314]
    DIRECTION OUTPUT ;
    USE SIGNAL ;
    PORT
      LAYER M3 ;
        RECT  64.512 43.162 64.53 43.2 ;
    END
  END o[314]
  PIN o[315]
    DIRECTION OUTPUT ;
    USE SIGNAL ;
    PORT
      LAYER M5 ;
        RECT  64.704 43.116 64.728 43.2 ;
    END
  END o[315]
  PIN o[316]
    DIRECTION OUTPUT ;
    USE SIGNAL ;
    PORT
      LAYER M3 ;
        RECT  64.908 43.162 64.926 43.2 ;
    END
  END o[316]
  PIN o[317]
    DIRECTION OUTPUT ;
    USE SIGNAL ;
    PORT
      LAYER M5 ;
        RECT  65.136 43.116 65.16 43.2 ;
    END
  END o[317]
  PIN o[318]
    DIRECTION OUTPUT ;
    USE SIGNAL ;
    PORT
      LAYER M3 ;
        RECT  65.304 43.162 65.322 43.2 ;
    END
  END o[318]
  PIN o[319]
    DIRECTION OUTPUT ;
    USE SIGNAL ;
    PORT
      LAYER M5 ;
        RECT  65.52 43.116 65.544 43.2 ;
    END
  END o[319]
  PIN o[31]
    DIRECTION OUTPUT ;
    USE SIGNAL ;
    PORT
      LAYER M5 ;
        RECT  7.44 43.116 7.464 43.2 ;
    END
  END o[31]
  PIN o[320]
    DIRECTION OUTPUT ;
    USE SIGNAL ;
    PORT
      LAYER M3 ;
        RECT  65.736 43.162 65.754 43.2 ;
    END
  END o[320]
  PIN o[321]
    DIRECTION OUTPUT ;
    USE SIGNAL ;
    PORT
      LAYER M5 ;
        RECT  65.904 43.116 65.928 43.2 ;
    END
  END o[321]
  PIN o[322]
    DIRECTION OUTPUT ;
    USE SIGNAL ;
    PORT
      LAYER M3 ;
        RECT  66.132 43.162 66.15 43.2 ;
    END
  END o[322]
  PIN o[323]
    DIRECTION OUTPUT ;
    USE SIGNAL ;
    PORT
      LAYER M5 ;
        RECT  66.336 43.116 66.36 43.2 ;
    END
  END o[323]
  PIN o[324]
    DIRECTION OUTPUT ;
    USE SIGNAL ;
    PORT
      LAYER M3 ;
        RECT  66.528 43.162 66.546 43.2 ;
    END
  END o[324]
  PIN o[325]
    DIRECTION OUTPUT ;
    USE SIGNAL ;
    PORT
      LAYER M5 ;
        RECT  66.72 43.116 66.744 43.2 ;
    END
  END o[325]
  PIN o[326]
    DIRECTION OUTPUT ;
    USE SIGNAL ;
    PORT
      LAYER M3 ;
        RECT  66.924 43.162 66.942 43.2 ;
    END
  END o[326]
  PIN o[327]
    DIRECTION OUTPUT ;
    USE SIGNAL ;
    PORT
      LAYER M5 ;
        RECT  67.152 43.116 67.176 43.2 ;
    END
  END o[327]
  PIN o[328]
    DIRECTION OUTPUT ;
    USE SIGNAL ;
    PORT
      LAYER M3 ;
        RECT  67.32 43.162 67.338 43.2 ;
    END
  END o[328]
  PIN o[329]
    DIRECTION OUTPUT ;
    USE SIGNAL ;
    PORT
      LAYER M5 ;
        RECT  67.536 43.116 67.56 43.2 ;
    END
  END o[329]
  PIN o[32]
    DIRECTION OUTPUT ;
    USE SIGNAL ;
    PORT
      LAYER M3 ;
        RECT  7.632 43.162 7.65 43.2 ;
    END
  END o[32]
  PIN o[330]
    DIRECTION OUTPUT ;
    USE SIGNAL ;
    PORT
      LAYER M3 ;
        RECT  67.752 43.162 67.77 43.2 ;
    END
  END o[330]
  PIN o[331]
    DIRECTION OUTPUT ;
    USE SIGNAL ;
    PORT
      LAYER M5 ;
        RECT  67.92 43.116 67.944 43.2 ;
    END
  END o[331]
  PIN o[332]
    DIRECTION OUTPUT ;
    USE SIGNAL ;
    PORT
      LAYER M3 ;
        RECT  68.148 43.162 68.166 43.2 ;
    END
  END o[332]
  PIN o[333]
    DIRECTION OUTPUT ;
    USE SIGNAL ;
    PORT
      LAYER M5 ;
        RECT  68.352 43.116 68.376 43.2 ;
    END
  END o[333]
  PIN o[334]
    DIRECTION OUTPUT ;
    USE SIGNAL ;
    PORT
      LAYER M3 ;
        RECT  68.544 43.162 68.562 43.2 ;
    END
  END o[334]
  PIN o[335]
    DIRECTION OUTPUT ;
    USE SIGNAL ;
    PORT
      LAYER M5 ;
        RECT  68.736 43.116 68.76 43.2 ;
    END
  END o[335]
  PIN o[336]
    DIRECTION OUTPUT ;
    USE SIGNAL ;
    PORT
      LAYER M3 ;
        RECT  68.94 43.162 68.958 43.2 ;
    END
  END o[336]
  PIN o[337]
    DIRECTION OUTPUT ;
    USE SIGNAL ;
    PORT
      LAYER M5 ;
        RECT  69.168 43.116 69.192 43.2 ;
    END
  END o[337]
  PIN o[338]
    DIRECTION OUTPUT ;
    USE SIGNAL ;
    PORT
      LAYER M3 ;
        RECT  69.336 43.162 69.354 43.2 ;
    END
  END o[338]
  PIN o[339]
    DIRECTION OUTPUT ;
    USE SIGNAL ;
    PORT
      LAYER M5 ;
        RECT  69.552 43.116 69.576 43.2 ;
    END
  END o[339]
  PIN o[33]
    DIRECTION OUTPUT ;
    USE SIGNAL ;
    PORT
      LAYER M5 ;
        RECT  7.824 43.116 7.848 43.2 ;
    END
  END o[33]
  PIN o[340]
    DIRECTION OUTPUT ;
    USE SIGNAL ;
    PORT
      LAYER M3 ;
        RECT  69.768 43.162 69.786 43.2 ;
    END
  END o[340]
  PIN o[341]
    DIRECTION OUTPUT ;
    USE SIGNAL ;
    PORT
      LAYER M5 ;
        RECT  69.936 43.116 69.96 43.2 ;
    END
  END o[341]
  PIN o[342]
    DIRECTION OUTPUT ;
    USE SIGNAL ;
    PORT
      LAYER M3 ;
        RECT  70.164 43.162 70.182 43.2 ;
    END
  END o[342]
  PIN o[343]
    DIRECTION OUTPUT ;
    USE SIGNAL ;
    PORT
      LAYER M5 ;
        RECT  70.368 43.116 70.392 43.2 ;
    END
  END o[343]
  PIN o[344]
    DIRECTION OUTPUT ;
    USE SIGNAL ;
    PORT
      LAYER M3 ;
        RECT  70.56 43.162 70.578 43.2 ;
    END
  END o[344]
  PIN o[345]
    DIRECTION OUTPUT ;
    USE SIGNAL ;
    PORT
      LAYER M5 ;
        RECT  70.752 43.116 70.776 43.2 ;
    END
  END o[345]
  PIN o[346]
    DIRECTION OUTPUT ;
    USE SIGNAL ;
    PORT
      LAYER M3 ;
        RECT  70.956 43.162 70.974 43.2 ;
    END
  END o[346]
  PIN o[347]
    DIRECTION OUTPUT ;
    USE SIGNAL ;
    PORT
      LAYER M5 ;
        RECT  71.184 43.116 71.208 43.2 ;
    END
  END o[347]
  PIN o[348]
    DIRECTION OUTPUT ;
    USE SIGNAL ;
    PORT
      LAYER M3 ;
        RECT  71.352 43.162 71.37 43.2 ;
    END
  END o[348]
  PIN o[349]
    DIRECTION OUTPUT ;
    USE SIGNAL ;
    PORT
      LAYER M5 ;
        RECT  71.568 43.116 71.592 43.2 ;
    END
  END o[349]
  PIN o[34]
    DIRECTION OUTPUT ;
    USE SIGNAL ;
    PORT
      LAYER M3 ;
        RECT  8.028 43.162 8.046 43.2 ;
    END
  END o[34]
  PIN o[350]
    DIRECTION OUTPUT ;
    USE SIGNAL ;
    PORT
      LAYER M3 ;
        RECT  71.784 43.162 71.802 43.2 ;
    END
  END o[350]
  PIN o[351]
    DIRECTION OUTPUT ;
    USE SIGNAL ;
    PORT
      LAYER M5 ;
        RECT  71.952 43.116 71.976 43.2 ;
    END
  END o[351]
  PIN o[352]
    DIRECTION OUTPUT ;
    USE SIGNAL ;
    PORT
      LAYER M3 ;
        RECT  72.18 43.162 72.198 43.2 ;
    END
  END o[352]
  PIN o[353]
    DIRECTION OUTPUT ;
    USE SIGNAL ;
    PORT
      LAYER M5 ;
        RECT  72.384 43.116 72.408 43.2 ;
    END
  END o[353]
  PIN o[354]
    DIRECTION OUTPUT ;
    USE SIGNAL ;
    PORT
      LAYER M3 ;
        RECT  72.576 43.162 72.594 43.2 ;
    END
  END o[354]
  PIN o[355]
    DIRECTION OUTPUT ;
    USE SIGNAL ;
    PORT
      LAYER M5 ;
        RECT  72.768 43.116 72.792 43.2 ;
    END
  END o[355]
  PIN o[356]
    DIRECTION OUTPUT ;
    USE SIGNAL ;
    PORT
      LAYER M3 ;
        RECT  72.972 43.162 72.99 43.2 ;
    END
  END o[356]
  PIN o[357]
    DIRECTION OUTPUT ;
    USE SIGNAL ;
    PORT
      LAYER M5 ;
        RECT  73.2 43.116 73.224 43.2 ;
    END
  END o[357]
  PIN o[358]
    DIRECTION OUTPUT ;
    USE SIGNAL ;
    PORT
      LAYER M3 ;
        RECT  73.368 43.162 73.386 43.2 ;
    END
  END o[358]
  PIN o[359]
    DIRECTION OUTPUT ;
    USE SIGNAL ;
    PORT
      LAYER M5 ;
        RECT  73.584 43.116 73.608 43.2 ;
    END
  END o[359]
  PIN o[35]
    DIRECTION OUTPUT ;
    USE SIGNAL ;
    PORT
      LAYER M5 ;
        RECT  8.208 43.116 8.232 43.2 ;
    END
  END o[35]
  PIN o[360]
    DIRECTION OUTPUT ;
    USE SIGNAL ;
    PORT
      LAYER M3 ;
        RECT  73.8 43.162 73.818 43.2 ;
    END
  END o[360]
  PIN o[361]
    DIRECTION OUTPUT ;
    USE SIGNAL ;
    PORT
      LAYER M5 ;
        RECT  73.968 43.116 73.992 43.2 ;
    END
  END o[361]
  PIN o[362]
    DIRECTION OUTPUT ;
    USE SIGNAL ;
    PORT
      LAYER M3 ;
        RECT  74.196 43.162 74.214 43.2 ;
    END
  END o[362]
  PIN o[363]
    DIRECTION OUTPUT ;
    USE SIGNAL ;
    PORT
      LAYER M5 ;
        RECT  74.4 43.116 74.424 43.2 ;
    END
  END o[363]
  PIN o[364]
    DIRECTION OUTPUT ;
    USE SIGNAL ;
    PORT
      LAYER M3 ;
        RECT  74.592 43.162 74.61 43.2 ;
    END
  END o[364]
  PIN o[365]
    DIRECTION OUTPUT ;
    USE SIGNAL ;
    PORT
      LAYER M5 ;
        RECT  74.784 43.116 74.808 43.2 ;
    END
  END o[365]
  PIN o[366]
    DIRECTION OUTPUT ;
    USE SIGNAL ;
    PORT
      LAYER M3 ;
        RECT  74.988 43.162 75.006 43.2 ;
    END
  END o[366]
  PIN o[367]
    DIRECTION OUTPUT ;
    USE SIGNAL ;
    PORT
      LAYER M5 ;
        RECT  75.216 43.116 75.24 43.2 ;
    END
  END o[367]
  PIN o[368]
    DIRECTION OUTPUT ;
    USE SIGNAL ;
    PORT
      LAYER M3 ;
        RECT  75.42 43.162 75.438 43.2 ;
    END
  END o[368]
  PIN o[369]
    DIRECTION OUTPUT ;
    USE SIGNAL ;
    PORT
      LAYER M5 ;
        RECT  75.6 43.116 75.624 43.2 ;
    END
  END o[369]
  PIN o[36]
    DIRECTION OUTPUT ;
    USE SIGNAL ;
    PORT
      LAYER M3 ;
        RECT  8.424 43.162 8.442 43.2 ;
    END
  END o[36]
  PIN o[370]
    DIRECTION OUTPUT ;
    USE SIGNAL ;
    PORT
      LAYER M3 ;
        RECT  75.816 43.162 75.834 43.2 ;
    END
  END o[370]
  PIN o[371]
    DIRECTION OUTPUT ;
    USE SIGNAL ;
    PORT
      LAYER M5 ;
        RECT  75.984 43.116 76.008 43.2 ;
    END
  END o[371]
  PIN o[372]
    DIRECTION OUTPUT ;
    USE SIGNAL ;
    PORT
      LAYER M3 ;
        RECT  76.212 43.162 76.23 43.2 ;
    END
  END o[372]
  PIN o[373]
    DIRECTION OUTPUT ;
    USE SIGNAL ;
    PORT
      LAYER M5 ;
        RECT  76.416 43.116 76.44 43.2 ;
    END
  END o[373]
  PIN o[374]
    DIRECTION OUTPUT ;
    USE SIGNAL ;
    PORT
      LAYER M3 ;
        RECT  76.608 43.162 76.626 43.2 ;
    END
  END o[374]
  PIN o[375]
    DIRECTION OUTPUT ;
    USE SIGNAL ;
    PORT
      LAYER M5 ;
        RECT  76.8 43.116 76.824 43.2 ;
    END
  END o[375]
  PIN o[376]
    DIRECTION OUTPUT ;
    USE SIGNAL ;
    PORT
      LAYER M3 ;
        RECT  77.004 43.162 77.022 43.2 ;
    END
  END o[376]
  PIN o[377]
    DIRECTION OUTPUT ;
    USE SIGNAL ;
    PORT
      LAYER M5 ;
        RECT  77.232 43.116 77.256 43.2 ;
    END
  END o[377]
  PIN o[378]
    DIRECTION OUTPUT ;
    USE SIGNAL ;
    PORT
      LAYER M3 ;
        RECT  77.436 43.162 77.454 43.2 ;
    END
  END o[378]
  PIN o[379]
    DIRECTION OUTPUT ;
    USE SIGNAL ;
    PORT
      LAYER M5 ;
        RECT  77.616 43.116 77.64 43.2 ;
    END
  END o[379]
  PIN o[37]
    DIRECTION OUTPUT ;
    USE SIGNAL ;
    PORT
      LAYER M5 ;
        RECT  8.64 43.116 8.664 43.2 ;
    END
  END o[37]
  PIN o[380]
    DIRECTION OUTPUT ;
    USE SIGNAL ;
    PORT
      LAYER M3 ;
        RECT  77.832 43.162 77.85 43.2 ;
    END
  END o[380]
  PIN o[381]
    DIRECTION OUTPUT ;
    USE SIGNAL ;
    PORT
      LAYER M5 ;
        RECT  78 43.116 78.024 43.2 ;
    END
  END o[381]
  PIN o[382]
    DIRECTION OUTPUT ;
    USE SIGNAL ;
    PORT
      LAYER M3 ;
        RECT  78.228 43.162 78.246 43.2 ;
    END
  END o[382]
  PIN o[383]
    DIRECTION OUTPUT ;
    USE SIGNAL ;
    PORT
      LAYER M5 ;
        RECT  78.432 43.116 78.456 43.2 ;
    END
  END o[383]
  PIN o[384]
    DIRECTION OUTPUT ;
    USE SIGNAL ;
    PORT
      LAYER M3 ;
        RECT  78.624 43.162 78.642 43.2 ;
    END
  END o[384]
  PIN o[385]
    DIRECTION OUTPUT ;
    USE SIGNAL ;
    PORT
      LAYER M5 ;
        RECT  78.816 43.116 78.84 43.2 ;
    END
  END o[385]
  PIN o[386]
    DIRECTION OUTPUT ;
    USE SIGNAL ;
    PORT
      LAYER M3 ;
        RECT  79.02 43.162 79.038 43.2 ;
    END
  END o[386]
  PIN o[387]
    DIRECTION OUTPUT ;
    USE SIGNAL ;
    PORT
      LAYER M5 ;
        RECT  79.248 43.116 79.272 43.2 ;
    END
  END o[387]
  PIN o[388]
    DIRECTION OUTPUT ;
    USE SIGNAL ;
    PORT
      LAYER M3 ;
        RECT  79.452 43.162 79.47 43.2 ;
    END
  END o[388]
  PIN o[389]
    DIRECTION OUTPUT ;
    USE SIGNAL ;
    PORT
      LAYER M5 ;
        RECT  79.632 43.116 79.656 43.2 ;
    END
  END o[389]
  PIN o[38]
    DIRECTION OUTPUT ;
    USE SIGNAL ;
    PORT
      LAYER M3 ;
        RECT  8.82 43.162 8.838 43.2 ;
    END
  END o[38]
  PIN o[390]
    DIRECTION OUTPUT ;
    USE SIGNAL ;
    PORT
      LAYER M3 ;
        RECT  79.848 43.162 79.866 43.2 ;
    END
  END o[390]
  PIN o[391]
    DIRECTION OUTPUT ;
    USE SIGNAL ;
    PORT
      LAYER M5 ;
        RECT  80.016 43.116 80.04 43.2 ;
    END
  END o[391]
  PIN o[392]
    DIRECTION OUTPUT ;
    USE SIGNAL ;
    PORT
      LAYER M3 ;
        RECT  80.244 43.162 80.262 43.2 ;
    END
  END o[392]
  PIN o[393]
    DIRECTION OUTPUT ;
    USE SIGNAL ;
    PORT
      LAYER M5 ;
        RECT  80.448 43.116 80.472 43.2 ;
    END
  END o[393]
  PIN o[394]
    DIRECTION OUTPUT ;
    USE SIGNAL ;
    PORT
      LAYER M3 ;
        RECT  80.64 43.162 80.658 43.2 ;
    END
  END o[394]
  PIN o[395]
    DIRECTION OUTPUT ;
    USE SIGNAL ;
    PORT
      LAYER M5 ;
        RECT  80.832 43.116 80.856 43.2 ;
    END
  END o[395]
  PIN o[396]
    DIRECTION OUTPUT ;
    USE SIGNAL ;
    PORT
      LAYER M3 ;
        RECT  81.036 43.162 81.054 43.2 ;
    END
  END o[396]
  PIN o[397]
    DIRECTION OUTPUT ;
    USE SIGNAL ;
    PORT
      LAYER M5 ;
        RECT  81.264 43.116 81.288 43.2 ;
    END
  END o[397]
  PIN o[398]
    DIRECTION OUTPUT ;
    USE SIGNAL ;
    PORT
      LAYER M3 ;
        RECT  81.468 43.162 81.486 43.2 ;
    END
  END o[398]
  PIN o[399]
    DIRECTION OUTPUT ;
    USE SIGNAL ;
    PORT
      LAYER M5 ;
        RECT  81.648 43.116 81.672 43.2 ;
    END
  END o[399]
  PIN o[39]
    DIRECTION OUTPUT ;
    USE SIGNAL ;
    PORT
      LAYER M5 ;
        RECT  9.024 43.116 9.048 43.2 ;
    END
  END o[39]
  PIN o[3]
    DIRECTION OUTPUT ;
    USE SIGNAL ;
    PORT
      LAYER M5 ;
        RECT  1.776 43.116 1.8 43.2 ;
    END
  END o[3]
  PIN o[400]
    DIRECTION OUTPUT ;
    USE SIGNAL ;
    PORT
      LAYER M3 ;
        RECT  81.864 43.162 81.882 43.2 ;
    END
  END o[400]
  PIN o[401]
    DIRECTION OUTPUT ;
    USE SIGNAL ;
    PORT
      LAYER M5 ;
        RECT  82.032 43.116 82.056 43.2 ;
    END
  END o[401]
  PIN o[402]
    DIRECTION OUTPUT ;
    USE SIGNAL ;
    PORT
      LAYER M3 ;
        RECT  82.26 43.162 82.278 43.2 ;
    END
  END o[402]
  PIN o[403]
    DIRECTION OUTPUT ;
    USE SIGNAL ;
    PORT
      LAYER M5 ;
        RECT  82.464 43.116 82.488 43.2 ;
    END
  END o[403]
  PIN o[404]
    DIRECTION OUTPUT ;
    USE SIGNAL ;
    PORT
      LAYER M3 ;
        RECT  82.656 43.162 82.674 43.2 ;
    END
  END o[404]
  PIN o[405]
    DIRECTION OUTPUT ;
    USE SIGNAL ;
    PORT
      LAYER M5 ;
        RECT  82.848 43.116 82.872 43.2 ;
    END
  END o[405]
  PIN o[406]
    DIRECTION OUTPUT ;
    USE SIGNAL ;
    PORT
      LAYER M3 ;
        RECT  83.052 43.162 83.07 43.2 ;
    END
  END o[406]
  PIN o[407]
    DIRECTION OUTPUT ;
    USE SIGNAL ;
    PORT
      LAYER M5 ;
        RECT  83.28 43.116 83.304 43.2 ;
    END
  END o[407]
  PIN o[408]
    DIRECTION OUTPUT ;
    USE SIGNAL ;
    PORT
      LAYER M3 ;
        RECT  83.484 43.162 83.502 43.2 ;
    END
  END o[408]
  PIN o[409]
    DIRECTION OUTPUT ;
    USE SIGNAL ;
    PORT
      LAYER M5 ;
        RECT  83.664 43.116 83.688 43.2 ;
    END
  END o[409]
  PIN o[40]
    DIRECTION OUTPUT ;
    USE SIGNAL ;
    PORT
      LAYER M3 ;
        RECT  9.252 43.162 9.27 43.2 ;
    END
  END o[40]
  PIN o[410]
    DIRECTION OUTPUT ;
    USE SIGNAL ;
    PORT
      LAYER M3 ;
        RECT  83.88 43.162 83.898 43.2 ;
    END
  END o[410]
  PIN o[411]
    DIRECTION OUTPUT ;
    USE SIGNAL ;
    PORT
      LAYER M5 ;
        RECT  84.096 43.116 84.12 43.2 ;
    END
  END o[411]
  PIN o[412]
    DIRECTION OUTPUT ;
    USE SIGNAL ;
    PORT
      LAYER M3 ;
        RECT  84.276 43.162 84.294 43.2 ;
    END
  END o[412]
  PIN o[413]
    DIRECTION OUTPUT ;
    USE SIGNAL ;
    PORT
      LAYER M5 ;
        RECT  84.48 43.116 84.504 43.2 ;
    END
  END o[413]
  PIN o[414]
    DIRECTION OUTPUT ;
    USE SIGNAL ;
    PORT
      LAYER M3 ;
        RECT  84.672 43.162 84.69 43.2 ;
    END
  END o[414]
  PIN o[415]
    DIRECTION OUTPUT ;
    USE SIGNAL ;
    PORT
      LAYER M5 ;
        RECT  84.864 43.116 84.888 43.2 ;
    END
  END o[415]
  PIN o[416]
    DIRECTION OUTPUT ;
    USE SIGNAL ;
    PORT
      LAYER M3 ;
        RECT  85.068 43.162 85.086 43.2 ;
    END
  END o[416]
  PIN o[417]
    DIRECTION OUTPUT ;
    USE SIGNAL ;
    PORT
      LAYER M5 ;
        RECT  85.296 43.116 85.32 43.2 ;
    END
  END o[417]
  PIN o[418]
    DIRECTION OUTPUT ;
    USE SIGNAL ;
    PORT
      LAYER M3 ;
        RECT  85.5 43.162 85.518 43.2 ;
    END
  END o[418]
  PIN o[419]
    DIRECTION OUTPUT ;
    USE SIGNAL ;
    PORT
      LAYER M5 ;
        RECT  85.68 43.116 85.704 43.2 ;
    END
  END o[419]
  PIN o[41]
    DIRECTION OUTPUT ;
    USE SIGNAL ;
    PORT
      LAYER M5 ;
        RECT  9.456 43.116 9.48 43.2 ;
    END
  END o[41]
  PIN o[420]
    DIRECTION OUTPUT ;
    USE SIGNAL ;
    PORT
      LAYER M3 ;
        RECT  85.896 43.162 85.914 43.2 ;
    END
  END o[420]
  PIN o[421]
    DIRECTION OUTPUT ;
    USE SIGNAL ;
    PORT
      LAYER M5 ;
        RECT  86.112 43.116 86.136 43.2 ;
    END
  END o[421]
  PIN o[422]
    DIRECTION OUTPUT ;
    USE SIGNAL ;
    PORT
      LAYER M3 ;
        RECT  86.292 43.162 86.31 43.2 ;
    END
  END o[422]
  PIN o[423]
    DIRECTION OUTPUT ;
    USE SIGNAL ;
    PORT
      LAYER M5 ;
        RECT  86.496 43.116 86.52 43.2 ;
    END
  END o[423]
  PIN o[424]
    DIRECTION OUTPUT ;
    USE SIGNAL ;
    PORT
      LAYER M3 ;
        RECT  86.688 43.162 86.706 43.2 ;
    END
  END o[424]
  PIN o[425]
    DIRECTION OUTPUT ;
    USE SIGNAL ;
    PORT
      LAYER M5 ;
        RECT  86.88 43.116 86.904 43.2 ;
    END
  END o[425]
  PIN o[426]
    DIRECTION OUTPUT ;
    USE SIGNAL ;
    PORT
      LAYER M3 ;
        RECT  87.084 43.162 87.102 43.2 ;
    END
  END o[426]
  PIN o[427]
    DIRECTION OUTPUT ;
    USE SIGNAL ;
    PORT
      LAYER M5 ;
        RECT  87.312 43.116 87.336 43.2 ;
    END
  END o[427]
  PIN o[428]
    DIRECTION OUTPUT ;
    USE SIGNAL ;
    PORT
      LAYER M3 ;
        RECT  87.516 43.162 87.534 43.2 ;
    END
  END o[428]
  PIN o[429]
    DIRECTION OUTPUT ;
    USE SIGNAL ;
    PORT
      LAYER M5 ;
        RECT  87.696 43.116 87.72 43.2 ;
    END
  END o[429]
  PIN o[42]
    DIRECTION OUTPUT ;
    USE SIGNAL ;
    PORT
      LAYER M3 ;
        RECT  9.648 43.162 9.666 43.2 ;
    END
  END o[42]
  PIN o[430]
    DIRECTION OUTPUT ;
    USE SIGNAL ;
    PORT
      LAYER M3 ;
        RECT  87.912 43.162 87.93 43.2 ;
    END
  END o[430]
  PIN o[431]
    DIRECTION OUTPUT ;
    USE SIGNAL ;
    PORT
      LAYER M5 ;
        RECT  88.128 43.116 88.152 43.2 ;
    END
  END o[431]
  PIN o[432]
    DIRECTION OUTPUT ;
    USE SIGNAL ;
    PORT
      LAYER M3 ;
        RECT  88.308 43.162 88.326 43.2 ;
    END
  END o[432]
  PIN o[433]
    DIRECTION OUTPUT ;
    USE SIGNAL ;
    PORT
      LAYER M5 ;
        RECT  88.512 43.116 88.536 43.2 ;
    END
  END o[433]
  PIN o[434]
    DIRECTION OUTPUT ;
    USE SIGNAL ;
    PORT
      LAYER M3 ;
        RECT  88.704 43.162 88.722 43.2 ;
    END
  END o[434]
  PIN o[435]
    DIRECTION OUTPUT ;
    USE SIGNAL ;
    PORT
      LAYER M5 ;
        RECT  88.896 43.116 88.92 43.2 ;
    END
  END o[435]
  PIN o[436]
    DIRECTION OUTPUT ;
    USE SIGNAL ;
    PORT
      LAYER M3 ;
        RECT  89.136 43.162 89.154 43.2 ;
    END
  END o[436]
  PIN o[437]
    DIRECTION OUTPUT ;
    USE SIGNAL ;
    PORT
      LAYER M5 ;
        RECT  89.328 43.116 89.352 43.2 ;
    END
  END o[437]
  PIN o[438]
    DIRECTION OUTPUT ;
    USE SIGNAL ;
    PORT
      LAYER M3 ;
        RECT  89.532 43.162 89.55 43.2 ;
    END
  END o[438]
  PIN o[439]
    DIRECTION OUTPUT ;
    USE SIGNAL ;
    PORT
      LAYER M5 ;
        RECT  89.712 43.116 89.736 43.2 ;
    END
  END o[439]
  PIN o[43]
    DIRECTION OUTPUT ;
    USE SIGNAL ;
    PORT
      LAYER M5 ;
        RECT  9.84 43.116 9.864 43.2 ;
    END
  END o[43]
  PIN o[440]
    DIRECTION OUTPUT ;
    USE SIGNAL ;
    PORT
      LAYER M3 ;
        RECT  89.928 43.162 89.946 43.2 ;
    END
  END o[440]
  PIN o[441]
    DIRECTION OUTPUT ;
    USE SIGNAL ;
    PORT
      LAYER M5 ;
        RECT  90.144 43.116 90.168 43.2 ;
    END
  END o[441]
  PIN o[442]
    DIRECTION OUTPUT ;
    USE SIGNAL ;
    PORT
      LAYER M3 ;
        RECT  90.324 43.162 90.342 43.2 ;
    END
  END o[442]
  PIN o[443]
    DIRECTION OUTPUT ;
    USE SIGNAL ;
    PORT
      LAYER M5 ;
        RECT  90.528 43.116 90.552 43.2 ;
    END
  END o[443]
  PIN o[444]
    DIRECTION OUTPUT ;
    USE SIGNAL ;
    PORT
      LAYER M3 ;
        RECT  90.72 43.162 90.738 43.2 ;
    END
  END o[444]
  PIN o[445]
    DIRECTION OUTPUT ;
    USE SIGNAL ;
    PORT
      LAYER M5 ;
        RECT  90.912 43.116 90.936 43.2 ;
    END
  END o[445]
  PIN o[446]
    DIRECTION OUTPUT ;
    USE SIGNAL ;
    PORT
      LAYER M3 ;
        RECT  91.152 43.162 91.17 43.2 ;
    END
  END o[446]
  PIN o[447]
    DIRECTION OUTPUT ;
    USE SIGNAL ;
    PORT
      LAYER M5 ;
        RECT  91.344 43.116 91.368 43.2 ;
    END
  END o[447]
  PIN o[448]
    DIRECTION OUTPUT ;
    USE SIGNAL ;
    PORT
      LAYER M3 ;
        RECT  91.548 43.162 91.566 43.2 ;
    END
  END o[448]
  PIN o[449]
    DIRECTION OUTPUT ;
    USE SIGNAL ;
    PORT
      LAYER M5 ;
        RECT  91.728 43.116 91.752 43.2 ;
    END
  END o[449]
  PIN o[44]
    DIRECTION OUTPUT ;
    USE SIGNAL ;
    PORT
      LAYER M3 ;
        RECT  10.044 43.162 10.062 43.2 ;
    END
  END o[44]
  PIN o[450]
    DIRECTION OUTPUT ;
    USE SIGNAL ;
    PORT
      LAYER M3 ;
        RECT  91.944 43.162 91.962 43.2 ;
    END
  END o[450]
  PIN o[451]
    DIRECTION OUTPUT ;
    USE SIGNAL ;
    PORT
      LAYER M5 ;
        RECT  92.16 43.116 92.184 43.2 ;
    END
  END o[451]
  PIN o[452]
    DIRECTION OUTPUT ;
    USE SIGNAL ;
    PORT
      LAYER M3 ;
        RECT  92.34 43.162 92.358 43.2 ;
    END
  END o[452]
  PIN o[453]
    DIRECTION OUTPUT ;
    USE SIGNAL ;
    PORT
      LAYER M5 ;
        RECT  92.544 43.116 92.568 43.2 ;
    END
  END o[453]
  PIN o[454]
    DIRECTION OUTPUT ;
    USE SIGNAL ;
    PORT
      LAYER M3 ;
        RECT  92.736 43.162 92.754 43.2 ;
    END
  END o[454]
  PIN o[455]
    DIRECTION OUTPUT ;
    USE SIGNAL ;
    PORT
      LAYER M5 ;
        RECT  92.928 43.116 92.952 43.2 ;
    END
  END o[455]
  PIN o[456]
    DIRECTION OUTPUT ;
    USE SIGNAL ;
    PORT
      LAYER M3 ;
        RECT  93.168 43.162 93.186 43.2 ;
    END
  END o[456]
  PIN o[457]
    DIRECTION OUTPUT ;
    USE SIGNAL ;
    PORT
      LAYER M5 ;
        RECT  93.36 43.116 93.384 43.2 ;
    END
  END o[457]
  PIN o[458]
    DIRECTION OUTPUT ;
    USE SIGNAL ;
    PORT
      LAYER M3 ;
        RECT  93.564 43.162 93.582 43.2 ;
    END
  END o[458]
  PIN o[459]
    DIRECTION OUTPUT ;
    USE SIGNAL ;
    PORT
      LAYER M5 ;
        RECT  93.744 43.116 93.768 43.2 ;
    END
  END o[459]
  PIN o[45]
    DIRECTION OUTPUT ;
    USE SIGNAL ;
    PORT
      LAYER M5 ;
        RECT  10.224 43.116 10.248 43.2 ;
    END
  END o[45]
  PIN o[460]
    DIRECTION OUTPUT ;
    USE SIGNAL ;
    PORT
      LAYER M3 ;
        RECT  93.96 43.162 93.978 43.2 ;
    END
  END o[460]
  PIN o[461]
    DIRECTION OUTPUT ;
    USE SIGNAL ;
    PORT
      LAYER M5 ;
        RECT  94.176 43.116 94.2 43.2 ;
    END
  END o[461]
  PIN o[462]
    DIRECTION OUTPUT ;
    USE SIGNAL ;
    PORT
      LAYER M3 ;
        RECT  94.356 43.162 94.374 43.2 ;
    END
  END o[462]
  PIN o[463]
    DIRECTION OUTPUT ;
    USE SIGNAL ;
    PORT
      LAYER M5 ;
        RECT  94.56 43.116 94.584 43.2 ;
    END
  END o[463]
  PIN o[464]
    DIRECTION OUTPUT ;
    USE SIGNAL ;
    PORT
      LAYER M3 ;
        RECT  94.752 43.162 94.77 43.2 ;
    END
  END o[464]
  PIN o[465]
    DIRECTION OUTPUT ;
    USE SIGNAL ;
    PORT
      LAYER M5 ;
        RECT  94.944 43.116 94.968 43.2 ;
    END
  END o[465]
  PIN o[466]
    DIRECTION OUTPUT ;
    USE SIGNAL ;
    PORT
      LAYER M3 ;
        RECT  95.184 43.162 95.202 43.2 ;
    END
  END o[466]
  PIN o[467]
    DIRECTION OUTPUT ;
    USE SIGNAL ;
    PORT
      LAYER M5 ;
        RECT  95.376 43.116 95.4 43.2 ;
    END
  END o[467]
  PIN o[468]
    DIRECTION OUTPUT ;
    USE SIGNAL ;
    PORT
      LAYER M3 ;
        RECT  95.58 43.162 95.598 43.2 ;
    END
  END o[468]
  PIN o[469]
    DIRECTION OUTPUT ;
    USE SIGNAL ;
    PORT
      LAYER M5 ;
        RECT  95.76 43.116 95.784 43.2 ;
    END
  END o[469]
  PIN o[46]
    DIRECTION OUTPUT ;
    USE SIGNAL ;
    PORT
      LAYER M3 ;
        RECT  10.44 43.162 10.458 43.2 ;
    END
  END o[46]
  PIN o[470]
    DIRECTION OUTPUT ;
    USE SIGNAL ;
    PORT
      LAYER M3 ;
        RECT  95.976 43.162 95.994 43.2 ;
    END
  END o[470]
  PIN o[471]
    DIRECTION OUTPUT ;
    USE SIGNAL ;
    PORT
      LAYER M5 ;
        RECT  96.192 43.116 96.216 43.2 ;
    END
  END o[471]
  PIN o[472]
    DIRECTION OUTPUT ;
    USE SIGNAL ;
    PORT
      LAYER M3 ;
        RECT  96.372 43.162 96.39 43.2 ;
    END
  END o[472]
  PIN o[473]
    DIRECTION OUTPUT ;
    USE SIGNAL ;
    PORT
      LAYER M5 ;
        RECT  96.576 43.116 96.6 43.2 ;
    END
  END o[473]
  PIN o[474]
    DIRECTION OUTPUT ;
    USE SIGNAL ;
    PORT
      LAYER M3 ;
        RECT  96.768 43.162 96.786 43.2 ;
    END
  END o[474]
  PIN o[475]
    DIRECTION OUTPUT ;
    USE SIGNAL ;
    PORT
      LAYER M5 ;
        RECT  96.96 43.116 96.984 43.2 ;
    END
  END o[475]
  PIN o[476]
    DIRECTION OUTPUT ;
    USE SIGNAL ;
    PORT
      LAYER M3 ;
        RECT  97.2 43.162 97.218 43.2 ;
    END
  END o[476]
  PIN o[477]
    DIRECTION OUTPUT ;
    USE SIGNAL ;
    PORT
      LAYER M5 ;
        RECT  97.392 43.116 97.416 43.2 ;
    END
  END o[477]
  PIN o[478]
    DIRECTION OUTPUT ;
    USE SIGNAL ;
    PORT
      LAYER M3 ;
        RECT  97.596 43.162 97.614 43.2 ;
    END
  END o[478]
  PIN o[479]
    DIRECTION OUTPUT ;
    USE SIGNAL ;
    PORT
      LAYER M5 ;
        RECT  97.776 43.116 97.8 43.2 ;
    END
  END o[479]
  PIN o[47]
    DIRECTION OUTPUT ;
    USE SIGNAL ;
    PORT
      LAYER M5 ;
        RECT  10.656 43.116 10.68 43.2 ;
    END
  END o[47]
  PIN o[480]
    DIRECTION OUTPUT ;
    USE SIGNAL ;
    PORT
      LAYER M3 ;
        RECT  97.992 43.162 98.01 43.2 ;
    END
  END o[480]
  PIN o[481]
    DIRECTION OUTPUT ;
    USE SIGNAL ;
    PORT
      LAYER M5 ;
        RECT  98.208 43.116 98.232 43.2 ;
    END
  END o[481]
  PIN o[482]
    DIRECTION OUTPUT ;
    USE SIGNAL ;
    PORT
      LAYER M3 ;
        RECT  98.388 43.162 98.406 43.2 ;
    END
  END o[482]
  PIN o[483]
    DIRECTION OUTPUT ;
    USE SIGNAL ;
    PORT
      LAYER M5 ;
        RECT  98.592 43.116 98.616 43.2 ;
    END
  END o[483]
  PIN o[484]
    DIRECTION OUTPUT ;
    USE SIGNAL ;
    PORT
      LAYER M3 ;
        RECT  98.784 43.162 98.802 43.2 ;
    END
  END o[484]
  PIN o[485]
    DIRECTION OUTPUT ;
    USE SIGNAL ;
    PORT
      LAYER M5 ;
        RECT  98.976 43.116 99 43.2 ;
    END
  END o[485]
  PIN o[486]
    DIRECTION OUTPUT ;
    USE SIGNAL ;
    PORT
      LAYER M3 ;
        RECT  99.216 43.162 99.234 43.2 ;
    END
  END o[486]
  PIN o[487]
    DIRECTION OUTPUT ;
    USE SIGNAL ;
    PORT
      LAYER M5 ;
        RECT  99.408 43.116 99.432 43.2 ;
    END
  END o[487]
  PIN o[488]
    DIRECTION OUTPUT ;
    USE SIGNAL ;
    PORT
      LAYER M3 ;
        RECT  99.612 43.162 99.63 43.2 ;
    END
  END o[488]
  PIN o[489]
    DIRECTION OUTPUT ;
    USE SIGNAL ;
    PORT
      LAYER M5 ;
        RECT  99.792 43.116 99.816 43.2 ;
    END
  END o[489]
  PIN o[48]
    DIRECTION OUTPUT ;
    USE SIGNAL ;
    PORT
      LAYER M3 ;
        RECT  10.872 43.162 10.89 43.2 ;
    END
  END o[48]
  PIN o[490]
    DIRECTION OUTPUT ;
    USE SIGNAL ;
    PORT
      LAYER M3 ;
        RECT  100.008 43.162 100.026 43.2 ;
    END
  END o[490]
  PIN o[491]
    DIRECTION OUTPUT ;
    USE SIGNAL ;
    PORT
      LAYER M5 ;
        RECT  100.224 43.116 100.248 43.2 ;
    END
  END o[491]
  PIN o[492]
    DIRECTION OUTPUT ;
    USE SIGNAL ;
    PORT
      LAYER M3 ;
        RECT  100.404 43.162 100.422 43.2 ;
    END
  END o[492]
  PIN o[493]
    DIRECTION OUTPUT ;
    USE SIGNAL ;
    PORT
      LAYER M5 ;
        RECT  100.608 43.116 100.632 43.2 ;
    END
  END o[493]
  PIN o[494]
    DIRECTION OUTPUT ;
    USE SIGNAL ;
    PORT
      LAYER M3 ;
        RECT  100.836 43.162 100.854 43.2 ;
    END
  END o[494]
  PIN o[495]
    DIRECTION OUTPUT ;
    USE SIGNAL ;
    PORT
      LAYER M5 ;
        RECT  101.04 43.116 101.064 43.2 ;
    END
  END o[495]
  PIN o[496]
    DIRECTION OUTPUT ;
    USE SIGNAL ;
    PORT
      LAYER M3 ;
        RECT  101.232 43.162 101.25 43.2 ;
    END
  END o[496]
  PIN o[497]
    DIRECTION OUTPUT ;
    USE SIGNAL ;
    PORT
      LAYER M5 ;
        RECT  101.424 43.116 101.448 43.2 ;
    END
  END o[497]
  PIN o[498]
    DIRECTION OUTPUT ;
    USE SIGNAL ;
    PORT
      LAYER M3 ;
        RECT  101.628 43.162 101.646 43.2 ;
    END
  END o[498]
  PIN o[499]
    DIRECTION OUTPUT ;
    USE SIGNAL ;
    PORT
      LAYER M5 ;
        RECT  101.808 43.116 101.832 43.2 ;
    END
  END o[499]
  PIN o[49]
    DIRECTION OUTPUT ;
    USE SIGNAL ;
    PORT
      LAYER M5 ;
        RECT  11.04 43.116 11.064 43.2 ;
    END
  END o[49]
  PIN o[4]
    DIRECTION OUTPUT ;
    USE SIGNAL ;
    PORT
      LAYER M3 ;
        RECT  1.98 43.162 1.998 43.2 ;
    END
  END o[4]
  PIN o[500]
    DIRECTION OUTPUT ;
    USE SIGNAL ;
    PORT
      LAYER M3 ;
        RECT  102.024 43.162 102.042 43.2 ;
    END
  END o[500]
  PIN o[501]
    DIRECTION OUTPUT ;
    USE SIGNAL ;
    PORT
      LAYER M5 ;
        RECT  102.24 43.116 102.264 43.2 ;
    END
  END o[501]
  PIN o[502]
    DIRECTION OUTPUT ;
    USE SIGNAL ;
    PORT
      LAYER M3 ;
        RECT  102.42 43.162 102.438 43.2 ;
    END
  END o[502]
  PIN o[503]
    DIRECTION OUTPUT ;
    USE SIGNAL ;
    PORT
      LAYER M5 ;
        RECT  102.624 43.116 102.648 43.2 ;
    END
  END o[503]
  PIN o[504]
    DIRECTION OUTPUT ;
    USE SIGNAL ;
    PORT
      LAYER M3 ;
        RECT  102.852 43.162 102.87 43.2 ;
    END
  END o[504]
  PIN o[505]
    DIRECTION OUTPUT ;
    USE SIGNAL ;
    PORT
      LAYER M5 ;
        RECT  103.056 43.116 103.08 43.2 ;
    END
  END o[505]
  PIN o[506]
    DIRECTION OUTPUT ;
    USE SIGNAL ;
    PORT
      LAYER M3 ;
        RECT  103.248 43.162 103.266 43.2 ;
    END
  END o[506]
  PIN o[507]
    DIRECTION OUTPUT ;
    USE SIGNAL ;
    PORT
      LAYER M5 ;
        RECT  103.44 43.116 103.464 43.2 ;
    END
  END o[507]
  PIN o[508]
    DIRECTION OUTPUT ;
    USE SIGNAL ;
    PORT
      LAYER M3 ;
        RECT  103.644 43.162 103.662 43.2 ;
    END
  END o[508]
  PIN o[509]
    DIRECTION OUTPUT ;
    USE SIGNAL ;
    PORT
      LAYER M5 ;
        RECT  103.824 43.116 103.848 43.2 ;
    END
  END o[509]
  PIN o[50]
    DIRECTION OUTPUT ;
    USE SIGNAL ;
    PORT
      LAYER M3 ;
        RECT  11.268 43.162 11.286 43.2 ;
    END
  END o[50]
  PIN o[510]
    DIRECTION OUTPUT ;
    USE SIGNAL ;
    PORT
      LAYER M3 ;
        RECT  104.04 43.162 104.058 43.2 ;
    END
  END o[510]
  PIN o[511]
    DIRECTION OUTPUT ;
    USE SIGNAL ;
    PORT
      LAYER M5 ;
        RECT  104.256 43.116 104.28 43.2 ;
    END
  END o[511]
  PIN o[512]
    DIRECTION OUTPUT ;
    USE SIGNAL ;
    PORT
      LAYER M3 ;
        RECT  104.436 43.162 104.454 43.2 ;
    END
  END o[512]
  PIN o[513]
    DIRECTION OUTPUT ;
    USE SIGNAL ;
    PORT
      LAYER M5 ;
        RECT  104.64 43.116 104.664 43.2 ;
    END
  END o[513]
  PIN o[51]
    DIRECTION OUTPUT ;
    USE SIGNAL ;
    PORT
      LAYER M5 ;
        RECT  11.472 43.116 11.496 43.2 ;
    END
  END o[51]
  PIN o[52]
    DIRECTION OUTPUT ;
    USE SIGNAL ;
    PORT
      LAYER M3 ;
        RECT  11.664 43.162 11.682 43.2 ;
    END
  END o[52]
  PIN o[53]
    DIRECTION OUTPUT ;
    USE SIGNAL ;
    PORT
      LAYER M5 ;
        RECT  11.856 43.116 11.88 43.2 ;
    END
  END o[53]
  PIN o[54]
    DIRECTION OUTPUT ;
    USE SIGNAL ;
    PORT
      LAYER M3 ;
        RECT  12.06 43.162 12.078 43.2 ;
    END
  END o[54]
  PIN o[55]
    DIRECTION OUTPUT ;
    USE SIGNAL ;
    PORT
      LAYER M5 ;
        RECT  12.24 43.116 12.264 43.2 ;
    END
  END o[55]
  PIN o[56]
    DIRECTION OUTPUT ;
    USE SIGNAL ;
    PORT
      LAYER M3 ;
        RECT  12.456 43.162 12.474 43.2 ;
    END
  END o[56]
  PIN o[57]
    DIRECTION OUTPUT ;
    USE SIGNAL ;
    PORT
      LAYER M5 ;
        RECT  12.672 43.116 12.696 43.2 ;
    END
  END o[57]
  PIN o[58]
    DIRECTION OUTPUT ;
    USE SIGNAL ;
    PORT
      LAYER M3 ;
        RECT  12.888 43.162 12.906 43.2 ;
    END
  END o[58]
  PIN o[59]
    DIRECTION OUTPUT ;
    USE SIGNAL ;
    PORT
      LAYER M5 ;
        RECT  13.056 43.116 13.08 43.2 ;
    END
  END o[59]
  PIN o[5]
    DIRECTION OUTPUT ;
    USE SIGNAL ;
    PORT
      LAYER M5 ;
        RECT  2.16 43.116 2.184 43.2 ;
    END
  END o[5]
  PIN o[60]
    DIRECTION OUTPUT ;
    USE SIGNAL ;
    PORT
      LAYER M3 ;
        RECT  13.284 43.162 13.302 43.2 ;
    END
  END o[60]
  PIN o[61]
    DIRECTION OUTPUT ;
    USE SIGNAL ;
    PORT
      LAYER M5 ;
        RECT  13.488 43.116 13.512 43.2 ;
    END
  END o[61]
  PIN o[62]
    DIRECTION OUTPUT ;
    USE SIGNAL ;
    PORT
      LAYER M3 ;
        RECT  13.68 43.162 13.698 43.2 ;
    END
  END o[62]
  PIN o[63]
    DIRECTION OUTPUT ;
    USE SIGNAL ;
    PORT
      LAYER M5 ;
        RECT  13.872 43.116 13.896 43.2 ;
    END
  END o[63]
  PIN o[64]
    DIRECTION OUTPUT ;
    USE SIGNAL ;
    PORT
      LAYER M3 ;
        RECT  14.076 43.162 14.094 43.2 ;
    END
  END o[64]
  PIN o[65]
    DIRECTION OUTPUT ;
    USE SIGNAL ;
    PORT
      LAYER M5 ;
        RECT  14.304 43.116 14.328 43.2 ;
    END
  END o[65]
  PIN o[66]
    DIRECTION OUTPUT ;
    USE SIGNAL ;
    PORT
      LAYER M3 ;
        RECT  14.472 43.162 14.49 43.2 ;
    END
  END o[66]
  PIN o[67]
    DIRECTION OUTPUT ;
    USE SIGNAL ;
    PORT
      LAYER M5 ;
        RECT  14.688 43.116 14.712 43.2 ;
    END
  END o[67]
  PIN o[68]
    DIRECTION OUTPUT ;
    USE SIGNAL ;
    PORT
      LAYER M3 ;
        RECT  14.904 43.162 14.922 43.2 ;
    END
  END o[68]
  PIN o[69]
    DIRECTION OUTPUT ;
    USE SIGNAL ;
    PORT
      LAYER M5 ;
        RECT  15.072 43.116 15.096 43.2 ;
    END
  END o[69]
  PIN o[6]
    DIRECTION OUTPUT ;
    USE SIGNAL ;
    PORT
      LAYER M3 ;
        RECT  2.376 43.162 2.394 43.2 ;
    END
  END o[6]
  PIN o[70]
    DIRECTION OUTPUT ;
    USE SIGNAL ;
    PORT
      LAYER M3 ;
        RECT  15.3 43.162 15.318 43.2 ;
    END
  END o[70]
  PIN o[71]
    DIRECTION OUTPUT ;
    USE SIGNAL ;
    PORT
      LAYER M5 ;
        RECT  15.504 43.116 15.528 43.2 ;
    END
  END o[71]
  PIN o[72]
    DIRECTION OUTPUT ;
    USE SIGNAL ;
    PORT
      LAYER M3 ;
        RECT  15.696 43.162 15.714 43.2 ;
    END
  END o[72]
  PIN o[73]
    DIRECTION OUTPUT ;
    USE SIGNAL ;
    PORT
      LAYER M5 ;
        RECT  15.888 43.116 15.912 43.2 ;
    END
  END o[73]
  PIN o[74]
    DIRECTION OUTPUT ;
    USE SIGNAL ;
    PORT
      LAYER M3 ;
        RECT  16.092 43.162 16.11 43.2 ;
    END
  END o[74]
  PIN o[75]
    DIRECTION OUTPUT ;
    USE SIGNAL ;
    PORT
      LAYER M5 ;
        RECT  16.32 43.116 16.344 43.2 ;
    END
  END o[75]
  PIN o[76]
    DIRECTION OUTPUT ;
    USE SIGNAL ;
    PORT
      LAYER M3 ;
        RECT  16.488 43.162 16.506 43.2 ;
    END
  END o[76]
  PIN o[77]
    DIRECTION OUTPUT ;
    USE SIGNAL ;
    PORT
      LAYER M5 ;
        RECT  16.704 43.116 16.728 43.2 ;
    END
  END o[77]
  PIN o[78]
    DIRECTION OUTPUT ;
    USE SIGNAL ;
    PORT
      LAYER M3 ;
        RECT  16.92 43.162 16.938 43.2 ;
    END
  END o[78]
  PIN o[79]
    DIRECTION OUTPUT ;
    USE SIGNAL ;
    PORT
      LAYER M5 ;
        RECT  17.088 43.116 17.112 43.2 ;
    END
  END o[79]
  PIN o[7]
    DIRECTION OUTPUT ;
    USE SIGNAL ;
    PORT
      LAYER M5 ;
        RECT  2.592 43.116 2.616 43.2 ;
    END
  END o[7]
  PIN o[80]
    DIRECTION OUTPUT ;
    USE SIGNAL ;
    PORT
      LAYER M3 ;
        RECT  17.316 43.162 17.334 43.2 ;
    END
  END o[80]
  PIN o[81]
    DIRECTION OUTPUT ;
    USE SIGNAL ;
    PORT
      LAYER M5 ;
        RECT  17.52 43.116 17.544 43.2 ;
    END
  END o[81]
  PIN o[82]
    DIRECTION OUTPUT ;
    USE SIGNAL ;
    PORT
      LAYER M3 ;
        RECT  17.712 43.162 17.73 43.2 ;
    END
  END o[82]
  PIN o[83]
    DIRECTION OUTPUT ;
    USE SIGNAL ;
    PORT
      LAYER M5 ;
        RECT  17.904 43.116 17.928 43.2 ;
    END
  END o[83]
  PIN o[84]
    DIRECTION OUTPUT ;
    USE SIGNAL ;
    PORT
      LAYER M3 ;
        RECT  18.108 43.162 18.126 43.2 ;
    END
  END o[84]
  PIN o[85]
    DIRECTION OUTPUT ;
    USE SIGNAL ;
    PORT
      LAYER M5 ;
        RECT  18.336 43.116 18.36 43.2 ;
    END
  END o[85]
  PIN o[86]
    DIRECTION OUTPUT ;
    USE SIGNAL ;
    PORT
      LAYER M3 ;
        RECT  18.504 43.162 18.522 43.2 ;
    END
  END o[86]
  PIN o[87]
    DIRECTION OUTPUT ;
    USE SIGNAL ;
    PORT
      LAYER M5 ;
        RECT  18.72 43.116 18.744 43.2 ;
    END
  END o[87]
  PIN o[88]
    DIRECTION OUTPUT ;
    USE SIGNAL ;
    PORT
      LAYER M3 ;
        RECT  18.936 43.162 18.954 43.2 ;
    END
  END o[88]
  PIN o[89]
    DIRECTION OUTPUT ;
    USE SIGNAL ;
    PORT
      LAYER M5 ;
        RECT  19.104 43.116 19.128 43.2 ;
    END
  END o[89]
  PIN o[8]
    DIRECTION OUTPUT ;
    USE SIGNAL ;
    PORT
      LAYER M3 ;
        RECT  2.772 43.162 2.79 43.2 ;
    END
  END o[8]
  PIN o[90]
    DIRECTION OUTPUT ;
    USE SIGNAL ;
    PORT
      LAYER M3 ;
        RECT  19.332 43.162 19.35 43.2 ;
    END
  END o[90]
  PIN o[91]
    DIRECTION OUTPUT ;
    USE SIGNAL ;
    PORT
      LAYER M5 ;
        RECT  19.536 43.116 19.56 43.2 ;
    END
  END o[91]
  PIN o[92]
    DIRECTION OUTPUT ;
    USE SIGNAL ;
    PORT
      LAYER M3 ;
        RECT  19.728 43.162 19.746 43.2 ;
    END
  END o[92]
  PIN o[93]
    DIRECTION OUTPUT ;
    USE SIGNAL ;
    PORT
      LAYER M5 ;
        RECT  19.92 43.116 19.944 43.2 ;
    END
  END o[93]
  PIN o[94]
    DIRECTION OUTPUT ;
    USE SIGNAL ;
    PORT
      LAYER M3 ;
        RECT  20.124 43.162 20.142 43.2 ;
    END
  END o[94]
  PIN o[95]
    DIRECTION OUTPUT ;
    USE SIGNAL ;
    PORT
      LAYER M5 ;
        RECT  20.352 43.116 20.376 43.2 ;
    END
  END o[95]
  PIN o[96]
    DIRECTION OUTPUT ;
    USE SIGNAL ;
    PORT
      LAYER M3 ;
        RECT  20.52 43.162 20.538 43.2 ;
    END
  END o[96]
  PIN o[97]
    DIRECTION OUTPUT ;
    USE SIGNAL ;
    PORT
      LAYER M5 ;
        RECT  20.736 43.116 20.76 43.2 ;
    END
  END o[97]
  PIN o[98]
    DIRECTION OUTPUT ;
    USE SIGNAL ;
    PORT
      LAYER M3 ;
        RECT  20.952 43.162 20.97 43.2 ;
    END
  END o[98]
  PIN o[99]
    DIRECTION OUTPUT ;
    USE SIGNAL ;
    PORT
      LAYER M5 ;
        RECT  21.12 43.116 21.144 43.2 ;
    END
  END o[99]
  PIN o[9]
    DIRECTION OUTPUT ;
    USE SIGNAL ;
    PORT
      LAYER M5 ;
        RECT  2.976 43.116 3 43.2 ;
    END
  END o[9]
  PIN rsi_r
    DIRECTION INPUT ;
    USE SIGNAL ;
    PORT
      LAYER M3 ;
        RECT  106.812 43.162 106.83 43.2 ;
    END
    PORT
      LAYER M3 ;
        RECT  106.812 40.837 106.83 43.181 ;
    END
  END rsi_r
  PIN rsi_w
    DIRECTION INPUT ;
    USE SIGNAL ;
    PORT
      LAYER M3 ;
        RECT  106.812 0 106.83 0.038 ;
    END
    PORT
      LAYER M3 ;
        RECT  106.812 0.012 106.83 3.065 ;
    END
  END rsi_w
  PIN VSS
    DIRECTION INOUT ;
    USE GROUND ;
    PORT
      LAYER M5 ;
        RECT  105 2.137 105.12 41.063 ;
        RECT  99.6 2.137 99.72 41.063 ;
        RECT  94.2 2.137 94.32 41.063 ;
        RECT  88.8 2.137 88.92 41.063 ;
        RECT  83.4 2.137 83.52 41.063 ;
        RECT  78 2.137 78.12 41.063 ;
        RECT  72.6 2.137 72.72 41.063 ;
        RECT  67.2 2.137 67.32 41.063 ;
        RECT  61.8 2.137 61.92 41.063 ;
        RECT  56.4 2.137 56.52 41.063 ;
        RECT  51 2.137 51.12 41.063 ;
        RECT  45.6 2.137 45.72 41.063 ;
        RECT  40.2 2.137 40.32 41.063 ;
        RECT  34.8 2.137 34.92 41.063 ;
        RECT  29.4 2.137 29.52 41.063 ;
        RECT  24 2.137 24.12 41.063 ;
        RECT  18.6 2.137 18.72 41.063 ;
        RECT  13.2 2.137 13.32 41.063 ;
        RECT  7.8 2.137 7.92 41.063 ;
        RECT  2.4 2.137 2.52 41.063 ;
    END
  END VSS
  PIN VDD
    DIRECTION INOUT ;
    USE POWER ;
    PORT
      LAYER M5 ;
        RECT  105.192 2.151 105.312 41.049 ;
        RECT  99.792 2.151 99.912 41.049 ;
        RECT  94.392 2.151 94.512 41.049 ;
        RECT  88.992 2.151 89.112 41.049 ;
        RECT  83.592 2.151 83.712 41.049 ;
        RECT  78.192 2.151 78.312 41.049 ;
        RECT  72.792 2.151 72.912 41.049 ;
        RECT  67.392 2.151 67.512 41.049 ;
        RECT  61.992 2.151 62.112 41.049 ;
        RECT  56.592 2.151 56.712 41.049 ;
        RECT  51.192 2.151 51.312 41.049 ;
        RECT  45.792 2.151 45.912 41.049 ;
        RECT  40.392 2.151 40.512 41.049 ;
        RECT  34.992 2.151 35.112 41.049 ;
        RECT  29.592 2.151 29.712 41.049 ;
        RECT  24.192 2.151 24.312 41.049 ;
        RECT  18.792 2.151 18.912 41.049 ;
        RECT  13.392 2.151 13.512 41.049 ;
        RECT  7.992 2.151 8.112 41.049 ;
        RECT  2.592 2.151 2.712 41.049 ;
    END
  END VDD
  # OT_OBS_CLOSED layer=M5 d_um=1.536 added=534
  OBS
    LAYER RVTN ;
     RECT  2.16 2.16 105.84 2.295 ;
     RECT  2.16 2.565 105.84 2.835 ;
     RECT  2.16 3.105 105.84 3.375 ;
     RECT  2.16 3.645 105.84 3.915 ;
     RECT  2.16 4.185 105.84 4.455 ;
     RECT  2.16 4.725 105.84 4.995 ;
     RECT  2.16 5.265 105.84 5.535 ;
     RECT  2.16 5.805 105.84 6.075 ;
     RECT  2.16 6.345 105.84 6.615 ;
     RECT  2.16 6.885 105.84 7.155 ;
     RECT  2.16 7.425 105.84 7.695 ;
     RECT  2.16 7.965 105.84 8.235 ;
     RECT  2.16 8.505 105.84 8.775 ;
     RECT  2.16 9.045 105.84 9.315 ;
     RECT  2.16 9.585 105.84 9.855 ;
     RECT  2.16 10.125 105.84 10.395 ;
     RECT  2.16 10.665 105.84 10.935 ;
     RECT  2.16 11.205 105.84 11.475 ;
     RECT  2.16 11.745 105.84 12.015 ;
     RECT  2.16 12.285 105.84 12.555 ;
     RECT  2.16 12.825 105.84 13.095 ;
     RECT  2.16 13.365 105.84 13.635 ;
     RECT  2.16 13.905 105.84 14.175 ;
     RECT  2.16 14.445 105.84 14.715 ;
     RECT  2.16 14.985 105.84 15.255 ;
     RECT  2.16 15.525 105.84 15.795 ;
     RECT  2.16 16.065 105.84 16.335 ;
     RECT  2.16 16.605 105.84 16.875 ;
     RECT  2.16 17.145 105.84 17.415 ;
     RECT  2.16 17.685 105.84 17.955 ;
     RECT  2.16 18.225 105.84 18.495 ;
     RECT  2.16 18.765 105.84 19.035 ;
     RECT  2.16 19.305 105.84 19.575 ;
     RECT  2.16 19.845 105.84 20.115 ;
     RECT  2.16 20.385 105.84 20.655 ;
     RECT  2.16 20.925 105.84 21.195 ;
     RECT  2.16 21.465 105.84 21.735 ;
     RECT  2.16 22.005 105.84 22.275 ;
     RECT  2.16 22.545 105.84 22.815 ;
     RECT  2.16 23.085 105.84 23.355 ;
     RECT  2.16 23.625 105.84 23.895 ;
     RECT  2.16 24.165 105.84 24.435 ;
     RECT  2.16 24.705 105.84 24.975 ;
     RECT  2.16 25.245 105.84 25.515 ;
     RECT  2.16 25.785 105.84 26.055 ;
     RECT  2.16 26.325 105.84 26.595 ;
     RECT  2.16 26.865 105.84 27.135 ;
     RECT  2.16 27.405 105.84 27.675 ;
     RECT  2.16 27.945 105.84 28.215 ;
     RECT  2.16 28.485 105.84 28.755 ;
     RECT  2.16 29.025 105.84 29.295 ;
     RECT  2.16 29.565 105.84 29.835 ;
     RECT  2.16 30.105 105.84 30.375 ;
     RECT  2.16 30.645 105.84 30.915 ;
     RECT  2.16 31.185 105.84 31.455 ;
     RECT  2.16 31.725 105.84 31.995 ;
     RECT  2.16 32.265 105.84 32.535 ;
     RECT  2.16 32.805 105.84 33.075 ;
     RECT  2.16 33.345 105.84 33.615 ;
     RECT  2.16 33.885 105.84 34.155 ;
     RECT  2.16 34.425 105.84 34.695 ;
     RECT  2.16 34.965 105.84 35.235 ;
     RECT  2.16 35.505 105.84 35.775 ;
     RECT  2.16 36.045 105.84 36.315 ;
     RECT  2.16 36.585 105.84 36.855 ;
     RECT  2.16 37.125 105.84 37.395 ;
     RECT  2.16 37.665 105.84 37.935 ;
     RECT  2.16 38.205 105.84 38.475 ;
     RECT  2.16 38.745 105.84 39.015 ;
     RECT  2.16 39.285 105.84 39.555 ;
     RECT  2.16 39.825 105.84 40.095 ;
     RECT  2.16 40.365 105.84 40.635 ;
     RECT  2.16 40.905 105.84 41.04 ;
    LAYER RVTP ;
     RECT  2.16 2.295 105.84 2.565 ;
     RECT  2.16 2.835 105.84 3.105 ;
     RECT  2.16 3.375 105.84 3.645 ;
     RECT  2.16 3.915 105.84 4.185 ;
     RECT  2.16 4.455 105.84 4.725 ;
     RECT  2.16 4.995 105.84 5.265 ;
     RECT  2.16 5.535 105.84 5.805 ;
     RECT  2.16 6.075 105.84 6.345 ;
     RECT  2.16 6.615 105.84 6.885 ;
     RECT  2.16 7.155 105.84 7.425 ;
     RECT  2.16 7.695 105.84 7.965 ;
     RECT  2.16 8.235 105.84 8.505 ;
     RECT  2.16 8.775 105.84 9.045 ;
     RECT  2.16 9.315 105.84 9.585 ;
     RECT  2.16 9.855 105.84 10.125 ;
     RECT  2.16 10.395 105.84 10.665 ;
     RECT  2.16 10.935 105.84 11.205 ;
     RECT  2.16 11.475 105.84 11.745 ;
     RECT  2.16 12.015 105.84 12.285 ;
     RECT  2.16 12.555 105.84 12.825 ;
     RECT  2.16 13.095 105.84 13.365 ;
     RECT  2.16 13.635 105.84 13.905 ;
     RECT  2.16 14.175 105.84 14.445 ;
     RECT  2.16 14.715 105.84 14.985 ;
     RECT  2.16 15.255 105.84 15.525 ;
     RECT  2.16 15.795 105.84 16.065 ;
     RECT  2.16 16.335 105.84 16.605 ;
     RECT  2.16 16.875 105.84 17.145 ;
     RECT  2.16 17.415 105.84 17.685 ;
     RECT  2.16 17.955 105.84 18.225 ;
     RECT  2.16 18.495 105.84 18.765 ;
     RECT  2.16 19.035 105.84 19.305 ;
     RECT  2.16 19.575 105.84 19.845 ;
     RECT  2.16 20.115 105.84 20.385 ;
     RECT  2.16 20.655 105.84 20.925 ;
     RECT  2.16 21.195 105.84 21.465 ;
     RECT  2.16 21.735 105.84 22.005 ;
     RECT  2.16 22.275 105.84 22.545 ;
     RECT  2.16 22.815 105.84 23.085 ;
     RECT  2.16 23.355 105.84 23.625 ;
     RECT  2.16 23.895 105.84 24.165 ;
     RECT  2.16 24.435 105.84 24.705 ;
     RECT  2.16 24.975 105.84 25.245 ;
     RECT  2.16 25.515 105.84 25.785 ;
     RECT  2.16 26.055 105.84 26.325 ;
     RECT  2.16 26.595 105.84 26.865 ;
     RECT  2.16 27.135 105.84 27.405 ;
     RECT  2.16 27.675 105.84 27.945 ;
     RECT  2.16 28.215 105.84 28.485 ;
     RECT  2.16 28.755 105.84 29.025 ;
     RECT  2.16 29.295 105.84 29.565 ;
     RECT  2.16 29.835 105.84 30.105 ;
     RECT  2.16 30.375 105.84 30.645 ;
     RECT  2.16 30.915 105.84 31.185 ;
     RECT  2.16 31.455 105.84 31.725 ;
     RECT  2.16 31.995 105.84 32.265 ;
     RECT  2.16 32.535 105.84 32.805 ;
     RECT  2.16 33.075 105.84 33.345 ;
     RECT  2.16 33.615 105.84 33.885 ;
     RECT  2.16 34.155 105.84 34.425 ;
     RECT  2.16 34.695 105.84 34.965 ;
     RECT  2.16 35.235 105.84 35.505 ;
     RECT  2.16 35.775 105.84 36.045 ;
     RECT  2.16 36.315 105.84 36.585 ;
     RECT  2.16 36.855 105.84 37.125 ;
     RECT  2.16 37.395 105.84 37.665 ;
     RECT  2.16 37.935 105.84 38.205 ;
     RECT  2.16 38.475 105.84 38.745 ;
     RECT  2.16 39.015 105.84 39.285 ;
     RECT  2.16 39.555 105.84 39.825 ;
     RECT  2.16 40.095 105.84 40.365 ;
     RECT  2.16 40.635 105.84 40.905 ;
    LAYER M1 ;
     RECT  2.16 2.151 105.84 41.049 ;
    LAYER M2 ;
     RECT  1.183 37.476 1.579 37.494 ;
     RECT  1.579 24.372 1.975 24.39 ;
     RECT  1.975 24.372 2.16 24.66 ;
     RECT  1.183 27.342 2.16 27.36 ;
     RECT  2.011 29.502 2.16 29.52 ;
     RECT  1.579 37.476 2.16 38.034 ;
     RECT  1.975 39.258 2.16 39.276 ;
     RECT  2.371 0.261 2.767 0.279 ;
     RECT  2.767 0.144 3.199 0.279 ;
     RECT  2.695 42.192 3.515 42.21 ;
     RECT  3.199 0.072 3.595 0.279 ;
     RECT  2.695 43.146 3.595 43.164 ;
     RECT  3.595 0.036 3.991 0.279 ;
     RECT  3.595 43.074 4.055 43.164 ;
     RECT  4.387 42.192 5.783 42.21 ;
     RECT  3.991 0.036 6.107 0.594 ;
     RECT  4.055 43.074 6.287 43.092 ;
     RECT  6.107 0.072 6.611 0.594 ;
     RECT  2.16 2.151 7.051 41.049 ;
     RECT  6.611 0.072 7.303 0.234 ;
     RECT  7.303 0.036 7.655 0.234 ;
     RECT  7.051 2.034 8.627 41.049 ;
     RECT  7.655 0.108 8.843 0.234 ;
     RECT  8.843 0.108 9.563 0.126 ;
     RECT  9.571 0.036 9.671 0.054 ;
     RECT  9.643 42.192 9.779 42.21 ;
     RECT  6.403 43.146 10.067 43.164 ;
     RECT  8.627 2.106 10.175 41.049 ;
     RECT  10.175 2.151 11.659 41.049 ;
     RECT  11.263 0.036 12.083 0.054 ;
     RECT  11.659 2.106 12.883 41.049 ;
     RECT  12.883 2.034 13.135 41.049 ;
     RECT  13.135 2.034 13.307 41.13 ;
     RECT  13.279 0.576 13.675 0.594 ;
     RECT  13.675 0.036 13.811 0.594 ;
     RECT  13.811 0.036 13.847 0.054 ;
     RECT  13.307 2.034 14.675 41.049 ;
     RECT  14.791 0.036 15.223 0.054 ;
     RECT  14.675 2.106 15.691 41.049 ;
     RECT  15.223 0.036 16.943 0.234 ;
     RECT  15.691 1.728 17.303 41.049 ;
     RECT  16.943 0.036 17.663 0.126 ;
     RECT  17.707 43.146 18.203 43.164 ;
     RECT  17.303 2.151 20.767 41.049 ;
     RECT  20.767 2.034 20.803 41.049 ;
     RECT  20.803 1.998 22.063 41.049 ;
     RECT  17.663 0.036 22.163 0.054 ;
     RECT  22.135 42.192 22.451 42.21 ;
     RECT  22.063 1.926 23.503 41.049 ;
     RECT  23.503 1.728 23.783 41.049 ;
     RECT  23.783 2.151 24.583 41.049 ;
     RECT  25.195 0.036 25.403 0.054 ;
     RECT  25.699 43.146 25.799 43.164 ;
     RECT  24.583 2.106 26.015 41.049 ;
     RECT  26.599 42.192 26.987 42.21 ;
     RECT  27.103 0.18 27.391 0.198 ;
     RECT  27.391 0.036 27.607 0.198 ;
     RECT  28.183 43.146 29.435 43.164 ;
     RECT  27.607 0.036 30.587 0.396 ;
     RECT  30.587 0.306 30.659 0.396 ;
     RECT  30.659 0.378 31.055 0.396 ;
     RECT  31.747 0.108 31.963 0.126 ;
     RECT  31.963 0.036 33.071 0.126 ;
     RECT  33.071 0.036 33.467 0.054 ;
     RECT  33.295 1.152 33.935 1.17 ;
     RECT  34.231 43.146 34.331 43.164 ;
     RECT  26.015 2.151 34.375 41.049 ;
     RECT  34.375 2.106 35.203 41.049 ;
     RECT  34.303 42.192 35.519 42.21 ;
     RECT  35.203 2.034 36.139 41.049 ;
     RECT  36.139 2.034 36.311 41.094 ;
     RECT  36.967 0.108 37.255 0.126 ;
     RECT  37.255 0.036 37.687 0.126 ;
     RECT  37.255 1.152 37.687 1.17 ;
     RECT  37.687 1.152 37.787 1.242 ;
     RECT  37.687 0.036 37.895 0.198 ;
     RECT  37.787 1.152 37.895 1.17 ;
     RECT  37.895 0.108 38.327 0.198 ;
     RECT  38.327 0.18 38.723 0.198 ;
     RECT  39.091 0.036 39.523 0.054 ;
     RECT  39.523 0.036 39.911 0.126 ;
     RECT  39.091 42.192 40.127 42.21 ;
     RECT  40.063 1.152 40.163 1.17 ;
     RECT  39.911 0.036 40.343 0.054 ;
     RECT  40.315 43.146 41.711 43.164 ;
     RECT  41.683 0.036 42.359 0.054 ;
     RECT  42.727 42.192 42.791 42.21 ;
     RECT  43.519 42.192 43.907 42.21 ;
     RECT  44.743 43.146 45.563 43.164 ;
     RECT  36.311 2.151 45.931 41.049 ;
     RECT  45.931 2.151 46.067 41.67 ;
     RECT  43.915 0.036 46.363 0.054 ;
     RECT  46.363 0.036 47.327 0.09 ;
     RECT  46.363 42.192 47.471 42.21 ;
     RECT  47.983 0.18 48.775 0.279 ;
     RECT  48.379 43.146 49.271 43.164 ;
     RECT  48.775 0.036 50.423 0.279 ;
     RECT  50.395 43.146 50.495 43.164 ;
     RECT  46.067 2.151 50.647 41.049 ;
     RECT  50.423 0.036 50.819 0.162 ;
     RECT  50.647 2.151 50.819 41.094 ;
     RECT  50.819 0.108 51.215 0.162 ;
     RECT  51.215 0.108 51.359 0.126 ;
     RECT  51.583 0.036 52.087 0.054 ;
     RECT  52.087 0.036 52.187 0.126 ;
     RECT  52.187 0.108 52.439 0.126 ;
     RECT  52.015 43.146 53.699 43.164 ;
     RECT  54.823 43.146 55.895 43.164 ;
     RECT  50.819 2.151 56.443 41.049 ;
     RECT  56.443 2.151 56.759 41.13 ;
     RECT  53.203 0.036 56.795 0.054 ;
     RECT  57.235 42.192 57.659 42.21 ;
     RECT  57.307 0.18 57.811 0.198 ;
     RECT  56.759 2.151 57.847 41.049 ;
     RECT  57.811 0.108 58.027 0.198 ;
     RECT  57.631 43.146 58.307 43.164 ;
     RECT  58.027 0.036 59.099 0.198 ;
     RECT  59.099 0.108 59.279 0.198 ;
     RECT  57.847 2.106 59.279 41.049 ;
     RECT  59.279 0.108 60.475 0.126 ;
     RECT  60.475 0.036 60.835 0.126 ;
     RECT  60.835 0.036 60.907 0.198 ;
     RECT  59.279 2.151 61.015 41.049 ;
     RECT  61.015 2.151 61.691 41.634 ;
     RECT  60.907 0.036 61.799 0.279 ;
     RECT  61.799 0.18 62.519 0.279 ;
     RECT  62.519 0.18 62.635 0.198 ;
     RECT  64.111 42.192 64.507 42.21 ;
     RECT  62.635 0.036 64.723 0.198 ;
     RECT  64.723 0.036 64.823 0.279 ;
     RECT  64.507 42.192 65.039 42.282 ;
     RECT  65.039 42.264 65.183 42.282 ;
     RECT  64.823 0.18 65.327 0.279 ;
     RECT  65.327 0.18 65.731 0.198 ;
     RECT  65.731 0.036 65.795 0.198 ;
     RECT  65.795 0.108 66.155 0.198 ;
     RECT  66.127 1.152 66.227 1.17 ;
     RECT  66.127 43.146 66.587 43.164 ;
     RECT  66.155 0.18 67.315 0.198 ;
     RECT  67.315 43.146 67.415 43.164 ;
     RECT  67.603 1.152 67.739 1.17 ;
     RECT  61.691 2.151 67.747 41.049 ;
     RECT  67.747 1.728 67.955 41.049 ;
     RECT  68.143 43.074 68.539 43.092 ;
     RECT  68.539 43.074 68.567 43.164 ;
     RECT  68.827 1.152 68.927 1.17 ;
     RECT  67.955 1.998 68.971 41.049 ;
     RECT  68.567 43.146 69.863 43.164 ;
     RECT  68.971 1.881 70.259 41.049 ;
     RECT  67.315 0.036 70.403 0.198 ;
     RECT  70.555 42.192 70.943 42.21 ;
     RECT  70.259 1.926 71.095 41.049 ;
     RECT  70.403 0.18 71.375 0.198 ;
     RECT  71.275 43.146 71.375 43.164 ;
     RECT  71.095 1.881 71.599 41.049 ;
     RECT  71.599 1.152 71.735 41.049 ;
     RECT  71.735 1.881 72.995 41.049 ;
     RECT  73.651 0.036 74.263 0.054 ;
     RECT  74.263 0.036 75.011 0.126 ;
     RECT  75.011 0.036 75.443 0.054 ;
     RECT  76.207 42.192 76.451 42.21 ;
     RECT  76.207 0.036 76.603 0.054 ;
     RECT  76.603 0.036 76.703 0.09 ;
     RECT  76.703 0.036 76.955 0.054 ;
     RECT  72.995 2.151 77.359 41.049 ;
     RECT  77.359 1.728 77.459 41.049 ;
     RECT  77.459 2.151 78.187 41.049 ;
     RECT  78.187 1.728 78.647 41.049 ;
     RECT  78.223 43.146 79.151 43.164 ;
     RECT  79.627 0.036 79.871 0.054 ;
     RECT  80.635 42.192 81.203 42.21 ;
     RECT  81.463 0.036 81.787 0.054 ;
     RECT  81.787 0.036 81.887 0.09 ;
     RECT  78.647 2.151 82.651 41.049 ;
     RECT  81.887 0.036 82.787 0.054 ;
     RECT  82.651 2.151 82.787 41.094 ;
     RECT  82.787 2.151 83.479 41.049 ;
     RECT  81.859 43.146 83.479 43.164 ;
     RECT  83.479 43.074 83.579 43.164 ;
     RECT  83.579 43.074 83.615 43.092 ;
     RECT  83.479 1.728 84.371 41.049 ;
     RECT  84.271 0.036 84.991 0.054 ;
     RECT  84.667 43.146 85.127 43.164 ;
     RECT  84.991 0.036 85.459 0.162 ;
     RECT  84.371 2.106 86.071 41.049 ;
     RECT  85.459 0.036 86.179 0.234 ;
     RECT  86.071 2.034 86.603 41.049 ;
     RECT  86.179 0.036 87.107 0.279 ;
     RECT  87.107 0.036 87.539 0.054 ;
     RECT  88.699 42.192 89.159 42.21 ;
     RECT  89.131 43.146 89.231 43.164 ;
     RECT  88.447 0.036 90.419 0.054 ;
     RECT  91.903 0.108 91.939 0.126 ;
     RECT  86.603 2.151 92.335 41.049 ;
     RECT  92.335 2.151 92.435 41.094 ;
     RECT  91.939 0.036 92.795 0.126 ;
     RECT  92.795 0.108 93.191 0.126 ;
     RECT  92.731 42.192 93.551 42.21 ;
     RECT  93.559 0.036 94.351 0.09 ;
     RECT  94.351 43.146 94.451 43.164 ;
     RECT  94.351 0.036 95.143 0.126 ;
     RECT  92.435 2.151 95.179 41.049 ;
     RECT  95.179 2.151 95.279 41.094 ;
     RECT  95.143 0.036 95.603 0.162 ;
     RECT  95.971 43.146 96.071 43.164 ;
     RECT  95.603 0.036 96.511 0.126 ;
     RECT  97.987 42.192 98.195 42.21 ;
     RECT  97.591 43.146 99.535 43.164 ;
     RECT  99.535 43.11 99.635 43.164 ;
     RECT  99.635 43.146 100.831 43.164 ;
     RECT  100.831 43.074 101.507 43.164 ;
     RECT  96.511 0.036 101.651 0.279 ;
     RECT  101.651 0.036 102.479 0.054 ;
     RECT  101.507 43.074 102.479 43.092 ;
     RECT  103.567 0.036 103.667 0.054 ;
     RECT  103.675 0.108 104.063 0.126 ;
     RECT  95.279 2.151 105.84 41.049 ;
     RECT  105.84 3.042 106.835 3.06 ;
     RECT  105.84 40.842 106.835 40.86 ;
    LAYER M3 ;
     RECT  1.206 0.012 1.584 0.038 ;
     RECT  1.602 0.012 1.98 0.038 ;
     RECT  1.998 0.012 2.376 0.038 ;
     RECT  2.394 0.012 2.772 0.038 ;
     RECT  2.79 0.012 3.204 0.038 ;
     RECT  3.222 0.012 3.6 0.038 ;
     RECT  3.618 0.012 3.996 0.038 ;
     RECT  4.014 0.012 4.392 0.038 ;
     RECT  4.41 0.012 4.788 0.038 ;
     RECT  4.806 0.012 5.22 0.038 ;
     RECT  5.238 0.012 5.616 0.038 ;
     RECT  5.634 0.012 6.012 0.038 ;
     RECT  6.03 0.012 6.408 0.038 ;
     RECT  6.426 0.012 6.804 0.038 ;
     RECT  6.822 0.012 7.236 0.038 ;
     RECT  7.254 0.012 7.632 0.038 ;
     RECT  7.65 0.012 8.028 0.038 ;
     RECT  8.046 0.012 8.424 0.038 ;
     RECT  8.442 0.012 8.82 0.038 ;
     RECT  8.838 0.012 9.252 0.038 ;
     RECT  9.27 0.012 9.648 0.038 ;
     RECT  9.666 0.012 10.044 0.038 ;
     RECT  10.062 0.012 10.44 0.038 ;
     RECT  10.458 0.012 10.872 0.038 ;
     RECT  10.89 0.012 11.268 0.038 ;
     RECT  11.286 0.012 11.664 0.038 ;
     RECT  11.682 0.012 12.06 0.038 ;
     RECT  12.078 0.012 12.456 0.038 ;
     RECT  12.474 0.012 12.888 0.038 ;
     RECT  12.906 0.012 13.284 0.038 ;
     RECT  13.302 0.012 13.68 0.038 ;
     RECT  13.698 0.012 14.076 0.038 ;
     RECT  14.094 0.012 14.472 0.038 ;
     RECT  14.49 0.012 14.904 0.038 ;
     RECT  14.922 0.012 15.3 0.038 ;
     RECT  15.318 0.012 15.696 0.038 ;
     RECT  15.714 0.012 16.092 0.038 ;
     RECT  16.11 0.012 16.488 0.038 ;
     RECT  16.506 0.012 16.92 0.038 ;
     RECT  16.938 0.012 17.316 0.038 ;
     RECT  17.334 0.012 17.712 0.038 ;
     RECT  17.73 0.012 18.108 0.038 ;
     RECT  18.126 0.012 18.504 0.038 ;
     RECT  18.522 0.012 18.936 0.038 ;
     RECT  18.954 0.012 19.332 0.038 ;
     RECT  19.35 0.012 19.728 0.038 ;
     RECT  19.746 0.012 20.124 0.038 ;
     RECT  20.142 0.012 20.52 0.038 ;
     RECT  20.538 0.012 20.952 0.038 ;
     RECT  20.97 0.012 21.348 0.038 ;
     RECT  21.366 0.012 21.744 0.038 ;
     RECT  21.762 0.012 22.14 0.038 ;
     RECT  22.158 0.012 22.536 0.038 ;
     RECT  22.554 0.012 22.968 0.038 ;
     RECT  22.986 0.012 23.364 0.038 ;
     RECT  23.382 0.012 23.76 0.038 ;
     RECT  23.778 0.012 24.156 0.038 ;
     RECT  24.174 0.012 24.588 0.038 ;
     RECT  24.606 0.012 24.984 0.038 ;
     RECT  25.002 0.012 25.38 0.038 ;
     RECT  25.398 0.012 25.776 0.038 ;
     RECT  25.794 0.012 26.172 0.038 ;
     RECT  26.19 0.012 26.604 0.038 ;
     RECT  26.622 0.012 27 0.038 ;
     RECT  27.018 0.012 27.396 0.038 ;
     RECT  27.414 0.012 27.792 0.038 ;
     RECT  27.81 0.012 28.188 0.038 ;
     RECT  28.206 0.012 28.62 0.038 ;
     RECT  28.638 0.012 29.016 0.038 ;
     RECT  29.034 0.012 29.412 0.038 ;
     RECT  29.43 0.012 29.808 0.038 ;
     RECT  29.826 0.012 30.204 0.038 ;
     RECT  30.222 0.012 30.636 0.038 ;
     RECT  30.654 0.012 31.032 0.038 ;
     RECT  31.05 0.012 31.428 0.038 ;
     RECT  31.446 0.012 31.824 0.038 ;
     RECT  31.842 0.012 32.22 0.038 ;
     RECT  32.238 0.012 32.652 0.038 ;
     RECT  32.67 0.012 33.048 0.038 ;
     RECT  33.066 0.012 33.444 0.038 ;
     RECT  33.462 0.012 33.84 0.038 ;
     RECT  33.858 0.012 34.236 0.038 ;
     RECT  34.254 0.012 34.668 0.038 ;
     RECT  34.686 0.012 35.064 0.038 ;
     RECT  35.082 0.012 35.46 0.038 ;
     RECT  35.478 0.012 35.856 0.038 ;
     RECT  35.874 0.012 36.288 0.038 ;
     RECT  36.306 0.012 36.684 0.038 ;
     RECT  36.702 0.012 37.08 0.038 ;
     RECT  37.098 0.012 37.476 0.038 ;
     RECT  37.494 0.012 37.872 0.038 ;
     RECT  37.89 0.012 38.304 0.038 ;
     RECT  38.322 0.012 38.7 0.038 ;
     RECT  38.718 0.012 39.096 0.038 ;
     RECT  39.114 0.012 39.492 0.038 ;
     RECT  39.51 0.012 39.888 0.038 ;
     RECT  39.906 0.012 40.32 0.038 ;
     RECT  40.338 0.012 40.716 0.038 ;
     RECT  40.734 0.012 41.112 0.038 ;
     RECT  41.13 0.012 41.508 0.038 ;
     RECT  41.526 0.012 41.904 0.038 ;
     RECT  41.922 0.012 42.336 0.038 ;
     RECT  42.354 0.012 42.732 0.038 ;
     RECT  42.75 0.012 43.128 0.038 ;
     RECT  43.146 0.012 43.524 0.038 ;
     RECT  43.542 0.012 43.92 0.038 ;
     RECT  43.938 0.012 44.352 0.038 ;
     RECT  44.37 0.012 44.748 0.038 ;
     RECT  44.766 0.012 45.144 0.038 ;
     RECT  45.162 0.012 45.54 0.038 ;
     RECT  45.558 0.012 45.936 0.038 ;
     RECT  45.954 0.012 46.368 0.038 ;
     RECT  46.386 0.012 46.764 0.038 ;
     RECT  46.782 0.012 47.16 0.038 ;
     RECT  47.178 0.012 47.556 0.038 ;
     RECT  47.574 0.012 47.952 0.038 ;
     RECT  47.97 0.012 48.384 0.038 ;
     RECT  48.402 0.012 48.78 0.038 ;
     RECT  48.798 0.012 49.176 0.038 ;
     RECT  49.194 0.012 49.572 0.038 ;
     RECT  49.59 0.012 50.004 0.038 ;
     RECT  50.022 0.012 50.4 0.038 ;
     RECT  50.418 0.012 50.796 0.038 ;
     RECT  50.814 0.012 51.192 0.038 ;
     RECT  51.21 0.012 51.588 0.038 ;
     RECT  51.606 0.012 52.02 0.038 ;
     RECT  52.038 0.012 52.416 0.038 ;
     RECT  52.434 0.012 52.812 0.038 ;
     RECT  52.83 0.012 53.208 0.038 ;
     RECT  53.226 0.012 53.604 0.038 ;
     RECT  53.622 0.012 54.036 0.038 ;
     RECT  54.054 0.012 54.432 0.038 ;
     RECT  54.45 0.012 54.828 0.038 ;
     RECT  54.846 0.012 55.224 0.038 ;
     RECT  55.242 0.012 55.62 0.038 ;
     RECT  55.638 0.012 56.052 0.038 ;
     RECT  56.07 0.012 56.448 0.038 ;
     RECT  56.466 0.012 56.844 0.038 ;
     RECT  56.862 0.012 57.24 0.038 ;
     RECT  57.258 0.012 57.636 0.038 ;
     RECT  57.654 0.012 58.068 0.038 ;
     RECT  58.086 0.012 58.464 0.038 ;
     RECT  58.482 0.012 58.86 0.038 ;
     RECT  58.878 0.012 59.256 0.038 ;
     RECT  59.274 0.012 59.652 0.038 ;
     RECT  59.67 0.012 60.084 0.038 ;
     RECT  60.102 0.012 60.48 0.038 ;
     RECT  60.498 0.012 60.876 0.038 ;
     RECT  60.894 0.012 61.272 0.038 ;
     RECT  61.29 0.012 61.668 0.038 ;
     RECT  61.686 0.012 62.1 0.038 ;
     RECT  62.118 0.012 62.496 0.038 ;
     RECT  62.514 0.012 62.892 0.038 ;
     RECT  62.91 0.012 63.288 0.038 ;
     RECT  63.306 0.012 63.72 0.038 ;
     RECT  63.738 0.012 64.116 0.038 ;
     RECT  64.134 0.012 64.512 0.038 ;
     RECT  64.53 0.012 64.908 0.038 ;
     RECT  64.926 0.012 65.304 0.038 ;
     RECT  65.322 0.012 65.736 0.038 ;
     RECT  65.754 0.012 66.132 0.038 ;
     RECT  66.15 0.012 66.528 0.038 ;
     RECT  66.546 0.012 66.924 0.038 ;
     RECT  66.942 0.012 67.32 0.038 ;
     RECT  67.338 0.012 67.752 0.038 ;
     RECT  67.77 0.012 68.148 0.038 ;
     RECT  68.166 0.012 68.544 0.038 ;
     RECT  68.562 0.012 68.94 0.038 ;
     RECT  68.958 0.012 69.336 0.038 ;
     RECT  69.354 0.012 69.768 0.038 ;
     RECT  69.786 0.012 70.164 0.038 ;
     RECT  70.182 0.012 70.56 0.038 ;
     RECT  70.578 0.012 70.956 0.038 ;
     RECT  70.974 0.012 71.352 0.038 ;
     RECT  71.37 0.012 71.784 0.038 ;
     RECT  71.802 0.012 72.18 0.038 ;
     RECT  72.198 0.012 72.576 0.038 ;
     RECT  72.594 0.012 72.972 0.038 ;
     RECT  72.99 0.012 73.368 0.038 ;
     RECT  73.386 0.012 73.8 0.038 ;
     RECT  73.818 0.012 74.196 0.038 ;
     RECT  74.214 0.012 74.592 0.038 ;
     RECT  74.61 0.012 74.988 0.038 ;
     RECT  75.006 0.012 75.42 0.038 ;
     RECT  75.438 0.012 75.816 0.038 ;
     RECT  75.834 0.012 76.212 0.038 ;
     RECT  76.23 0.012 76.608 0.038 ;
     RECT  76.626 0.012 77.004 0.038 ;
     RECT  77.022 0.012 77.436 0.038 ;
     RECT  77.454 0.012 77.832 0.038 ;
     RECT  77.85 0.012 78.228 0.038 ;
     RECT  78.246 0.012 78.624 0.038 ;
     RECT  78.642 0.012 79.02 0.038 ;
     RECT  79.038 0.012 79.452 0.038 ;
     RECT  79.47 0.012 79.848 0.038 ;
     RECT  79.866 0.012 80.244 0.038 ;
     RECT  80.262 0.012 80.64 0.038 ;
     RECT  80.658 0.012 81.036 0.038 ;
     RECT  81.054 0.012 81.468 0.038 ;
     RECT  81.486 0.012 81.864 0.038 ;
     RECT  81.882 0.012 82.26 0.038 ;
     RECT  82.278 0.012 82.656 0.038 ;
     RECT  82.674 0.012 83.052 0.038 ;
     RECT  83.07 0.012 83.484 0.038 ;
     RECT  83.502 0.012 83.88 0.038 ;
     RECT  83.898 0.012 84.276 0.038 ;
     RECT  84.294 0.012 84.672 0.038 ;
     RECT  84.69 0.012 85.068 0.038 ;
     RECT  85.086 0.012 85.5 0.038 ;
     RECT  85.518 0.012 85.896 0.038 ;
     RECT  85.914 0.012 86.292 0.038 ;
     RECT  86.31 0.012 86.688 0.038 ;
     RECT  86.706 0.012 87.084 0.038 ;
     RECT  87.102 0.012 87.516 0.038 ;
     RECT  87.534 0.012 87.912 0.038 ;
     RECT  87.93 0.012 88.308 0.038 ;
     RECT  88.326 0.012 88.704 0.038 ;
     RECT  88.722 0.012 89.136 0.038 ;
     RECT  89.154 0.012 89.532 0.038 ;
     RECT  89.55 0.012 89.928 0.038 ;
     RECT  89.946 0.012 90.324 0.038 ;
     RECT  90.342 0.012 90.72 0.038 ;
     RECT  90.738 0.012 91.152 0.038 ;
     RECT  91.17 0.012 91.548 0.038 ;
     RECT  91.566 0.012 91.944 0.038 ;
     RECT  91.962 0.012 92.34 0.038 ;
     RECT  92.358 0.012 92.736 0.038 ;
     RECT  92.754 0.012 93.168 0.038 ;
     RECT  93.186 0.012 93.564 0.038 ;
     RECT  93.582 0.012 93.96 0.038 ;
     RECT  93.978 0.012 94.356 0.038 ;
     RECT  94.374 0.012 94.752 0.038 ;
     RECT  94.77 0.012 95.184 0.038 ;
     RECT  95.202 0.012 95.58 0.038 ;
     RECT  95.598 0.012 95.976 0.038 ;
     RECT  95.994 0.012 96.372 0.038 ;
     RECT  96.39 0.012 96.768 0.038 ;
     RECT  96.786 0.012 97.2 0.038 ;
     RECT  97.218 0.012 97.596 0.038 ;
     RECT  97.614 0.012 97.992 0.038 ;
     RECT  98.01 0.012 98.388 0.038 ;
     RECT  98.406 0.012 98.784 0.038 ;
     RECT  98.802 0.012 99.216 0.038 ;
     RECT  99.234 0.012 99.612 0.038 ;
     RECT  99.63 0.012 100.008 0.038 ;
     RECT  100.026 0.012 100.404 0.038 ;
     RECT  100.422 0.012 100.836 0.038 ;
     RECT  100.854 0.012 101.232 0.038 ;
     RECT  101.25 0.012 101.628 0.038 ;
     RECT  101.646 0.012 102.024 0.038 ;
     RECT  102.042 0.012 102.42 0.038 ;
     RECT  102.438 0.012 102.852 0.038 ;
     RECT  102.87 0.012 103.248 0.038 ;
     RECT  103.266 0.012 103.644 0.038 ;
     RECT  103.662 0.012 104.04 0.038 ;
     RECT  104.058 0.012 104.436 0.038 ;
     RECT  1.188 0.038 104.454 0.059 ;
     RECT  42.732 0.059 45.27 0.077 ;
     RECT  61.668 0.059 75.834 0.077 ;
     RECT  76.608 0.059 87.102 0.077 ;
     RECT  89.316 0.059 104.454 0.077 ;
     RECT  1.188 0.059 3.222 0.095 ;
     RECT  46.368 0.059 48.402 0.095 ;
     RECT  61.668 0.077 75.15 0.095 ;
     RECT  76.608 0.077 80.262 0.095 ;
     RECT  49.176 0.059 50.418 0.131 ;
     RECT  58.86 0.059 60.93 0.131 ;
     RECT  61.668 0.095 69.462 0.131 ;
     RECT  89.316 0.077 102.474 0.131 ;
     RECT  1.188 0.095 2.79 0.167 ;
     RECT  51.192 0.059 53.658 0.167 ;
     RECT  3.996 0.059 18.954 0.173 ;
     RECT  32.832 0.059 41.922 0.203 ;
     RECT  61.776 0.131 69.462 0.203 ;
     RECT  3.996 0.173 18.522 0.239 ;
     RECT  1.188 0.167 2.394 0.284 ;
     RECT  49.464 0.131 50.418 0.284 ;
     RECT  81.036 0.077 87.102 0.284 ;
     RECT  94.644 0.131 102.474 0.284 ;
     RECT  94.644 0.284 101.07 0.317 ;
     RECT  20.736 0.059 31.986 0.401 ;
     RECT  15.696 0.239 18.522 0.509 ;
     RECT  3.996 0.239 14.814 0.599 ;
     RECT  61.776 0.203 66.15 1.147 ;
     RECT  4.104 0.599 12.906 1.723 ;
     RECT  13.716 0.599 14.814 1.723 ;
     RECT  46.764 0.095 48.402 1.723 ;
     RECT  49.464 0.284 50.346 1.723 ;
     RECT  56.16 0.059 58.05 1.723 ;
     RECT  59.076 0.131 60.93 1.723 ;
     RECT  76.68 0.095 80.262 1.751 ;
     RECT  67.104 0.203 69.462 1.921 ;
     RECT  70.2 0.095 75.15 1.921 ;
     RECT  4.104 1.723 14.814 2.101 ;
     RECT  15.696 0.509 18.27 2.101 ;
     RECT  1.188 0.284 2.034 2.143 ;
     RECT  4.104 2.101 18.27 2.143 ;
     RECT  44.172 0.077 45.27 2.143 ;
     RECT  46.764 1.723 50.346 2.143 ;
     RECT  51.336 0.167 53.658 2.143 ;
     RECT  87.912 0.059 88.47 2.143 ;
     RECT  89.316 0.131 93.762 2.143 ;
     RECT  94.644 0.317 98.046 2.143 ;
     RECT  103.248 0.077 104.454 2.143 ;
     RECT  4.104 2.143 18.705 2.191 ;
     RECT  19.728 0.059 19.782 2.191 ;
     RECT  31.428 0.401 31.986 2.191 ;
     RECT  32.832 0.203 38.142 2.191 ;
     RECT  76.68 1.751 78.297 2.191 ;
     RECT  76.464 2.191 78.297 2.251 ;
     RECT  56.16 1.723 60.93 2.255 ;
     RECT  81.036 0.284 87.03 2.263 ;
     RECT  98.784 0.317 101.07 2.291 ;
     RECT  20.736 0.401 30.582 2.371 ;
     RECT  46.764 2.143 53.658 2.371 ;
     RECT  1.188 2.143 2.505 2.413 ;
     RECT  44.172 2.143 45.705 2.413 ;
     RECT  103.248 2.143 105.105 2.413 ;
     RECT  4.104 2.191 19.782 2.533 ;
     RECT  3.78 2.533 19.782 2.569 ;
     RECT  20.556 2.371 30.582 2.569 ;
     RECT  75.996 2.251 78.297 2.569 ;
     RECT  79.02 1.751 80.262 2.569 ;
     RECT  67.104 1.921 75.15 2.635 ;
     RECT  75.996 2.569 80.262 2.635 ;
     RECT  59.076 2.255 60.93 2.641 ;
     RECT  61.776 1.147 66.222 2.641 ;
     RECT  44.172 2.413 45.897 2.731 ;
     RECT  46.656 2.371 53.658 2.731 ;
     RECT  87.912 2.143 98.046 2.795 ;
     RECT  67.104 2.635 80.262 2.911 ;
     RECT  81 2.263 87.03 2.911 ;
     RECT  67.104 2.911 87.03 3.001 ;
     RECT  87.912 2.795 97.758 3.001 ;
     RECT  67.104 3.001 97.758 3.145 ;
     RECT  31.428 2.191 38.142 3.271 ;
     RECT  59.076 2.641 66.222 3.415 ;
     RECT  66.996 3.145 97.758 3.415 ;
     RECT  3.78 2.569 30.582 3.451 ;
     RECT  31.428 3.271 38.394 3.451 ;
     RECT  44.172 2.731 53.658 3.691 ;
     RECT  3.78 3.451 38.394 3.811 ;
     RECT  39.312 0.203 41.922 3.811 ;
     RECT  42.732 0.077 43.326 3.811 ;
     RECT  42.732 3.811 43.362 3.847 ;
     RECT  44.1 3.691 53.658 3.847 ;
     RECT  59.076 3.415 97.758 3.965 ;
     RECT  56.16 2.255 58.05 4.531 ;
     RECT  59.076 3.965 63.522 4.621 ;
     RECT  56.16 4.531 58.158 4.693 ;
     RECT  58.932 4.621 63.522 4.693 ;
     RECT  98.928 2.291 101.07 4.765 ;
     RECT  101.844 0.284 102.474 4.765 ;
     RECT  3.78 3.811 41.922 4.801 ;
     RECT  98.928 4.765 102.474 4.999 ;
     RECT  98.892 4.999 102.474 5.071 ;
     RECT  103.248 2.413 105.297 5.071 ;
     RECT  56.16 4.693 63.522 5.161 ;
     RECT  64.26 3.965 92.79 5.161 ;
     RECT  93.744 3.965 97.758 5.197 ;
     RECT  98.892 5.071 105.297 5.197 ;
     RECT  1.188 2.413 2.697 5.323 ;
     RECT  3.492 4.801 41.922 5.323 ;
     RECT  54.432 0.059 55.422 5.467 ;
     RECT  56.16 5.161 92.79 5.467 ;
     RECT  93.744 5.197 105.297 6.151 ;
     RECT  93.672 6.151 105.297 7.159 ;
     RECT  54.432 5.467 92.79 7.195 ;
     RECT  93.528 7.159 105.297 7.195 ;
     RECT  1.188 5.323 41.922 7.259 ;
     RECT  42.732 3.847 53.658 7.357 ;
     RECT  1.188 7.259 41.706 8.311 ;
     RECT  42.516 7.357 53.658 8.311 ;
     RECT  1.188 8.311 53.658 8.465 ;
     RECT  42.48 8.465 53.658 8.473 ;
     RECT  54.432 7.195 105.297 8.473 ;
     RECT  42.48 8.473 105.297 9.113 ;
     RECT  54.432 9.113 105.297 9.589 ;
     RECT  1.188 8.465 41.706 9.751 ;
     RECT  42.48 9.113 53.658 9.751 ;
     RECT  54.432 9.589 105.354 10.049 ;
     RECT  1.188 9.751 53.658 10.165 ;
     RECT  54.432 10.049 105.297 10.165 ;
     RECT  1.188 10.165 105.297 11.399 ;
     RECT  1.188 11.399 52.542 11.435 ;
     RECT  1.188 11.435 52.47 12.901 ;
     RECT  1.188 12.901 52.578 12.991 ;
     RECT  53.316 11.399 105.297 12.991 ;
     RECT  1.188 12.991 105.297 13.171 ;
     RECT  1.188 13.171 105.714 13.433 ;
     RECT  1.188 13.433 105.462 13.559 ;
     RECT  1.188 13.559 105.297 14.243 ;
     RECT  3.528 14.243 105.297 14.377 ;
     RECT  3.528 14.377 105.57 14.675 ;
     RECT  3.636 14.675 105.57 15.215 ;
     RECT  16.236 15.215 105.57 15.295 ;
     RECT  3.636 15.215 15.246 15.421 ;
     RECT  1.188 14.243 2.697 15.565 ;
     RECT  3.42 15.421 15.246 15.565 ;
     RECT  1.188 15.565 15.246 16.033 ;
     RECT  16.236 15.295 105.714 16.061 ;
     RECT  1.188 16.033 15.426 16.501 ;
     RECT  1.188 16.501 15.462 16.573 ;
     RECT  1.188 16.573 15.498 16.645 ;
     RECT  16.236 16.061 105.498 16.645 ;
     RECT  1.188 16.645 105.498 17.221 ;
     RECT  1.188 17.221 105.642 17.483 ;
     RECT  1.188 17.483 105.297 18.301 ;
     RECT  1.188 18.301 105.462 18.455 ;
     RECT  1.188 18.455 105.354 19.229 ;
     RECT  1.188 19.229 105.297 19.949 ;
     RECT  81.9 19.949 105.297 20.183 ;
     RECT  96.048 20.183 105.297 20.425 ;
     RECT  96.048 20.425 105.714 20.579 ;
     RECT  1.188 19.949 81.162 21.001 ;
     RECT  81.9 20.183 95.274 21.001 ;
     RECT  1.188 21.001 95.274 21.271 ;
     RECT  96.048 20.579 105.642 21.271 ;
     RECT  1.188 21.271 105.642 21.731 ;
     RECT  1.188 21.731 105.534 21.929 ;
     RECT  82.008 21.929 105.534 22.469 ;
     RECT  1.188 21.929 81.198 22.739 ;
     RECT  43.272 22.739 81.198 22.741 ;
     RECT  82.008 22.469 105.462 22.741 ;
     RECT  1.188 22.739 42.462 23.593 ;
     RECT  43.272 22.741 105.462 23.593 ;
     RECT  1.188 23.593 105.462 23.899 ;
     RECT  1.188 23.899 105.498 24.395 ;
     RECT  1.98 24.395 105.354 24.431 ;
     RECT  1.98 24.431 76.482 24.665 ;
     RECT  77.256 24.431 89.298 24.665 ;
     RECT  90.072 24.431 105.354 25.079 ;
     RECT  77.256 24.665 89.262 25.789 ;
     RECT  90.072 25.079 105.297 25.789 ;
     RECT  2.016 24.665 76.482 25.861 ;
     RECT  77.256 25.789 105.297 25.861 ;
     RECT  2.016 25.861 105.297 26.015 ;
     RECT  80.388 26.015 105.297 26.699 ;
     RECT  80.388 26.699 81.342 26.789 ;
     RECT  82.08 26.699 105.297 26.933 ;
     RECT  2.016 26.015 79.578 26.941 ;
     RECT  2.016 26.941 79.614 27.095 ;
     RECT  82.224 26.933 105.297 27.139 ;
     RECT  1.188 24.395 1.206 27.365 ;
     RECT  82.224 27.139 105.606 27.365 ;
     RECT  82.26 27.365 105.606 27.599 ;
     RECT  82.26 27.599 105.297 27.635 ;
     RECT  2.016 27.095 10.494 28.021 ;
     RECT  11.268 27.095 79.614 28.021 ;
     RECT  80.388 26.789 80.982 28.211 ;
     RECT  2.016 28.021 79.614 28.453 ;
     RECT  80.388 28.211 80.91 28.453 ;
     RECT  82.296 27.635 105.297 28.687 ;
     RECT  2.016 28.453 80.91 29.117 ;
     RECT  82.224 28.687 105.297 29.227 ;
     RECT  2.016 29.117 10.494 29.525 ;
     RECT  81.792 29.227 105.297 29.641 ;
     RECT  81.792 29.641 105.714 29.645 ;
     RECT  82.296 29.645 105.714 29.759 ;
     RECT  2.34 29.525 10.494 29.875 ;
     RECT  11.268 29.117 80.91 29.875 ;
     RECT  82.296 29.759 105.297 30.065 ;
     RECT  2.34 29.875 80.91 30.713 ;
     RECT  82.332 30.065 105.297 30.811 ;
     RECT  82.116 30.811 105.297 31.685 ;
     RECT  82.116 31.685 90.306 31.765 ;
     RECT  2.376 30.713 80.91 31.915 ;
     RECT  2.34 31.915 80.91 32.063 ;
     RECT  2.34 32.063 79.578 32.189 ;
     RECT  82.08 31.765 90.306 32.189 ;
     RECT  2.34 32.189 42.606 32.443 ;
     RECT  2.304 32.443 42.606 32.495 ;
     RECT  80.388 32.063 80.91 32.495 ;
     RECT  82.116 32.189 90.306 32.773 ;
     RECT  91.044 31.685 105.297 32.773 ;
     RECT  2.415 32.495 42.606 33.067 ;
     RECT  43.452 32.189 79.578 33.067 ;
     RECT  2.415 33.067 79.578 33.143 ;
     RECT  80.496 32.495 80.91 33.151 ;
     RECT  38.376 33.143 79.578 33.269 ;
     RECT  38.376 33.269 42.606 33.305 ;
     RECT  43.452 33.269 79.578 33.511 ;
     RECT  38.52 33.305 42.606 33.575 ;
     RECT  2.415 33.143 37.494 33.787 ;
     RECT  43.452 33.511 79.722 33.845 ;
     RECT  80.496 33.151 80.946 33.961 ;
     RECT  82.116 32.773 105.297 34.231 ;
     RECT  82.116 34.231 105.714 34.493 ;
     RECT  80.496 33.961 81.018 34.501 ;
     RECT  82.116 34.493 105.297 34.501 ;
     RECT  2.376 33.787 37.494 34.655 ;
     RECT  2.415 34.655 37.494 34.691 ;
     RECT  43.452 33.845 73.386 34.691 ;
     RECT  10.368 34.691 37.494 34.735 ;
     RECT  38.628 33.575 42.606 34.735 ;
     RECT  43.596 34.691 73.386 34.735 ;
     RECT  74.124 33.845 79.722 34.735 ;
     RECT  10.368 34.735 37.566 34.763 ;
     RECT  43.596 34.735 79.722 34.781 ;
     RECT  66.708 34.781 79.722 34.925 ;
     RECT  66.708 34.925 70.47 34.997 ;
     RECT  38.628 34.735 42.858 35.041 ;
     RECT  71.208 34.925 79.722 35.195 ;
     RECT  43.596 34.781 65.934 35.581 ;
     RECT  66.744 34.997 70.47 35.671 ;
     RECT  71.208 35.195 79.47 35.671 ;
     RECT  2.415 34.691 9.63 36.121 ;
     RECT  10.404 34.763 37.566 36.121 ;
     RECT  38.484 35.041 42.858 36.121 ;
     RECT  43.596 35.581 66.006 36.149 ;
     RECT  2.415 36.121 42.858 36.391 ;
     RECT  43.596 36.149 51.462 36.391 ;
     RECT  66.744 35.671 79.47 36.391 ;
     RECT  80.496 34.501 105.297 36.391 ;
     RECT  66.744 36.391 105.297 36.461 ;
     RECT  2.415 36.391 51.462 36.545 ;
     RECT  52.344 36.149 66.006 36.815 ;
     RECT  2.415 36.545 51.39 36.931 ;
     RECT  52.344 36.815 65.934 36.931 ;
     RECT  2.376 36.931 51.39 37.471 ;
     RECT  52.164 36.931 65.934 37.471 ;
     RECT  66.744 36.461 87.138 37.471 ;
     RECT  87.876 36.461 105.297 37.471 ;
     RECT  2.376 37.471 65.934 37.579 ;
     RECT  66.744 37.471 105.297 37.579 ;
     RECT  1.188 37.471 1.206 38.011 ;
     RECT  2.376 37.579 105.297 38.129 ;
     RECT  2.376 38.129 40.95 38.189 ;
     RECT  2.415 38.189 40.95 38.813 ;
     RECT  2.415 38.813 11.25 39.091 ;
     RECT  11.988 38.813 40.95 39.181 ;
     RECT  41.688 38.129 105.297 39.181 ;
     RECT  1.188 38.011 1.602 39.253 ;
     RECT  2.376 39.091 11.25 39.253 ;
     RECT  11.988 39.181 105.297 39.515 ;
     RECT  1.188 39.253 11.25 39.631 ;
     RECT  11.988 39.515 29.826 39.631 ;
     RECT  1.188 39.631 29.826 40.441 ;
     RECT  30.636 39.515 105.297 40.441 ;
     RECT  1.188 40.441 105.297 40.787 ;
     RECT  1.188 40.787 105.174 40.973 ;
     RECT  98.136 40.973 105.174 41.009 ;
     RECT  1.188 40.973 97.326 41.021 ;
     RECT  98.136 41.009 105.105 41.057 ;
     RECT  1.188 41.021 47.97 41.069 ;
     RECT  64.908 41.021 97.218 41.213 ;
     RECT  98.136 41.057 104.67 42.173 ;
     RECT  48.78 41.021 63.738 42.187 ;
     RECT  64.908 41.213 88.326 42.187 ;
     RECT  89.136 41.213 97.218 42.187 ;
     RECT  98.136 42.173 104.454 42.187 ;
     RECT  1.188 41.069 27.81 42.215 ;
     RECT  28.62 41.069 47.97 42.215 ;
     RECT  64.908 42.187 97.218 42.221 ;
     RECT  48.78 42.187 64.134 42.259 ;
     RECT  64.908 42.221 67.77 42.259 ;
     RECT  1.188 42.215 3.222 43.069 ;
     RECT  3.996 42.215 27.81 43.069 ;
     RECT  48.78 42.259 67.77 43.069 ;
     RECT  68.544 42.221 97.218 43.069 ;
     RECT  1.188 43.069 27.81 43.141 ;
     RECT  28.62 42.215 39.906 43.141 ;
     RECT  40.716 42.215 47.97 43.141 ;
     RECT  48.78 43.069 97.218 43.141 ;
     RECT  97.992 42.187 104.454 43.141 ;
     RECT  1.188 43.141 104.454 43.162 ;
     RECT  1.206 43.162 1.584 43.181 ;
     RECT  1.602 43.162 1.98 43.181 ;
     RECT  1.998 43.162 2.376 43.181 ;
     RECT  2.394 43.162 2.772 43.181 ;
     RECT  2.79 43.162 3.204 43.181 ;
     RECT  3.222 43.162 3.6 43.181 ;
     RECT  3.618 43.162 3.996 43.181 ;
     RECT  4.014 43.162 4.392 43.181 ;
     RECT  4.41 43.162 4.788 43.181 ;
     RECT  4.806 43.162 5.22 43.181 ;
     RECT  5.238 43.162 5.616 43.181 ;
     RECT  5.634 43.162 6.012 43.181 ;
     RECT  6.03 43.162 6.408 43.181 ;
     RECT  6.426 43.162 6.804 43.181 ;
     RECT  6.822 43.162 7.236 43.181 ;
     RECT  7.254 43.162 7.632 43.181 ;
     RECT  7.65 43.162 8.028 43.181 ;
     RECT  8.046 43.162 8.424 43.181 ;
     RECT  8.442 43.162 8.82 43.181 ;
     RECT  8.838 43.162 9.252 43.181 ;
     RECT  9.27 43.162 9.648 43.181 ;
     RECT  9.666 43.162 10.044 43.181 ;
     RECT  10.062 43.162 10.44 43.181 ;
     RECT  10.458 43.162 10.872 43.181 ;
     RECT  10.89 43.162 11.268 43.181 ;
     RECT  11.286 43.162 11.664 43.181 ;
     RECT  11.682 43.162 12.06 43.181 ;
     RECT  12.078 43.162 12.456 43.181 ;
     RECT  12.474 43.162 12.888 43.181 ;
     RECT  12.906 43.162 13.284 43.181 ;
     RECT  13.302 43.162 13.68 43.181 ;
     RECT  13.698 43.162 14.076 43.181 ;
     RECT  14.094 43.162 14.472 43.181 ;
     RECT  14.49 43.162 14.904 43.181 ;
     RECT  14.922 43.162 15.3 43.181 ;
     RECT  15.318 43.162 15.696 43.181 ;
     RECT  15.714 43.162 16.092 43.181 ;
     RECT  16.11 43.162 16.488 43.181 ;
     RECT  16.506 43.162 16.92 43.181 ;
     RECT  16.938 43.162 17.316 43.181 ;
     RECT  17.334 43.162 17.712 43.181 ;
     RECT  17.73 43.162 18.108 43.181 ;
     RECT  18.126 43.162 18.504 43.181 ;
     RECT  18.522 43.162 18.936 43.181 ;
     RECT  18.954 43.162 19.332 43.181 ;
     RECT  19.35 43.162 19.728 43.181 ;
     RECT  19.746 43.162 20.124 43.181 ;
     RECT  20.142 43.162 20.52 43.181 ;
     RECT  20.538 43.162 20.952 43.181 ;
     RECT  20.97 43.162 21.348 43.181 ;
     RECT  21.366 43.162 21.744 43.181 ;
     RECT  21.762 43.162 22.14 43.181 ;
     RECT  22.158 43.162 22.536 43.181 ;
     RECT  22.554 43.162 22.968 43.181 ;
     RECT  22.986 43.162 23.364 43.181 ;
     RECT  23.382 43.162 23.76 43.181 ;
     RECT  23.778 43.162 24.156 43.181 ;
     RECT  24.174 43.162 24.588 43.181 ;
     RECT  24.606 43.162 24.984 43.181 ;
     RECT  25.002 43.162 25.38 43.181 ;
     RECT  25.398 43.162 25.776 43.181 ;
     RECT  25.794 43.162 26.172 43.181 ;
     RECT  26.19 43.162 26.604 43.181 ;
     RECT  26.622 43.162 27 43.181 ;
     RECT  27.018 43.162 27.396 43.181 ;
     RECT  27.414 43.162 27.792 43.181 ;
     RECT  27.81 43.162 28.188 43.181 ;
     RECT  28.206 43.162 28.62 43.181 ;
     RECT  28.638 43.162 29.016 43.181 ;
     RECT  29.034 43.162 29.412 43.181 ;
     RECT  29.43 43.162 29.808 43.181 ;
     RECT  29.826 43.162 30.204 43.181 ;
     RECT  30.222 43.162 30.636 43.181 ;
     RECT  30.654 43.162 31.032 43.181 ;
     RECT  31.05 43.162 31.428 43.181 ;
     RECT  31.446 43.162 31.824 43.181 ;
     RECT  31.842 43.162 32.22 43.181 ;
     RECT  32.238 43.162 32.652 43.181 ;
     RECT  32.67 43.162 33.048 43.181 ;
     RECT  33.066 43.162 33.444 43.181 ;
     RECT  33.462 43.162 33.84 43.181 ;
     RECT  33.858 43.162 34.236 43.181 ;
     RECT  34.254 43.162 34.668 43.181 ;
     RECT  34.686 43.162 35.064 43.181 ;
     RECT  35.082 43.162 35.46 43.181 ;
     RECT  35.478 43.162 35.856 43.181 ;
     RECT  35.874 43.162 36.288 43.181 ;
     RECT  36.306 43.162 36.684 43.181 ;
     RECT  36.702 43.162 37.08 43.181 ;
     RECT  37.098 43.162 37.476 43.181 ;
     RECT  37.494 43.162 37.872 43.181 ;
     RECT  37.89 43.162 38.304 43.181 ;
     RECT  38.322 43.162 38.7 43.181 ;
     RECT  38.718 43.162 39.096 43.181 ;
     RECT  39.114 43.162 39.492 43.181 ;
     RECT  39.51 43.162 39.888 43.181 ;
     RECT  39.906 43.162 40.32 43.181 ;
     RECT  40.338 43.162 40.716 43.181 ;
     RECT  40.734 43.162 41.112 43.181 ;
     RECT  41.13 43.162 41.508 43.181 ;
     RECT  41.526 43.162 41.904 43.181 ;
     RECT  41.922 43.162 42.336 43.181 ;
     RECT  42.354 43.162 42.732 43.181 ;
     RECT  42.75 43.162 43.128 43.181 ;
     RECT  43.146 43.162 43.524 43.181 ;
     RECT  43.542 43.162 43.92 43.181 ;
     RECT  43.938 43.162 44.352 43.181 ;
     RECT  44.37 43.162 44.748 43.181 ;
     RECT  44.766 43.162 45.144 43.181 ;
     RECT  45.162 43.162 45.54 43.181 ;
     RECT  45.558 43.162 45.936 43.181 ;
     RECT  45.954 43.162 46.368 43.181 ;
     RECT  46.386 43.162 46.764 43.181 ;
     RECT  46.782 43.162 47.16 43.181 ;
     RECT  47.178 43.162 47.556 43.181 ;
     RECT  47.574 43.162 47.952 43.181 ;
     RECT  47.97 43.162 48.384 43.181 ;
     RECT  48.402 43.162 48.78 43.181 ;
     RECT  48.798 43.162 49.176 43.181 ;
     RECT  49.194 43.162 49.572 43.181 ;
     RECT  49.59 43.162 50.004 43.181 ;
     RECT  50.022 43.162 50.4 43.181 ;
     RECT  50.418 43.162 50.796 43.181 ;
     RECT  50.814 43.162 51.192 43.181 ;
     RECT  51.21 43.162 51.588 43.181 ;
     RECT  51.606 43.162 52.02 43.181 ;
     RECT  52.038 43.162 52.416 43.181 ;
     RECT  52.434 43.162 52.812 43.181 ;
     RECT  52.83 43.162 53.208 43.181 ;
     RECT  53.226 43.162 53.604 43.181 ;
     RECT  53.622 43.162 54.036 43.181 ;
     RECT  54.054 43.162 54.432 43.181 ;
     RECT  54.45 43.162 54.828 43.181 ;
     RECT  54.846 43.162 55.224 43.181 ;
     RECT  55.242 43.162 55.62 43.181 ;
     RECT  55.638 43.162 56.052 43.181 ;
     RECT  56.07 43.162 56.448 43.181 ;
     RECT  56.466 43.162 56.844 43.181 ;
     RECT  56.862 43.162 57.24 43.181 ;
     RECT  57.258 43.162 57.636 43.181 ;
     RECT  57.654 43.162 58.068 43.181 ;
     RECT  58.086 43.162 58.464 43.181 ;
     RECT  58.482 43.162 58.86 43.181 ;
     RECT  58.878 43.162 59.256 43.181 ;
     RECT  59.274 43.162 59.652 43.181 ;
     RECT  59.67 43.162 60.084 43.181 ;
     RECT  60.102 43.162 60.48 43.181 ;
     RECT  60.498 43.162 60.876 43.181 ;
     RECT  60.894 43.162 61.272 43.181 ;
     RECT  61.29 43.162 61.668 43.181 ;
     RECT  61.686 43.162 62.1 43.181 ;
     RECT  62.118 43.162 62.496 43.181 ;
     RECT  62.514 43.162 62.892 43.181 ;
     RECT  62.91 43.162 63.288 43.181 ;
     RECT  63.306 43.162 63.72 43.181 ;
     RECT  63.738 43.162 64.116 43.181 ;
     RECT  64.134 43.162 64.512 43.181 ;
     RECT  64.53 43.162 64.908 43.181 ;
     RECT  64.926 43.162 65.304 43.181 ;
     RECT  65.322 43.162 65.736 43.181 ;
     RECT  65.754 43.162 66.132 43.181 ;
     RECT  66.15 43.162 66.528 43.181 ;
     RECT  66.546 43.162 66.924 43.181 ;
     RECT  66.942 43.162 67.32 43.181 ;
     RECT  67.338 43.162 67.752 43.181 ;
     RECT  67.77 43.162 68.148 43.181 ;
     RECT  68.166 43.162 68.544 43.181 ;
     RECT  68.562 43.162 68.94 43.181 ;
     RECT  68.958 43.162 69.336 43.181 ;
     RECT  69.354 43.162 69.768 43.181 ;
     RECT  69.786 43.162 70.164 43.181 ;
     RECT  70.182 43.162 70.56 43.181 ;
     RECT  70.578 43.162 70.956 43.181 ;
     RECT  70.974 43.162 71.352 43.181 ;
     RECT  71.37 43.162 71.784 43.181 ;
     RECT  71.802 43.162 72.18 43.181 ;
     RECT  72.198 43.162 72.576 43.181 ;
     RECT  72.594 43.162 72.972 43.181 ;
     RECT  72.99 43.162 73.368 43.181 ;
     RECT  73.386 43.162 73.8 43.181 ;
     RECT  73.818 43.162 74.196 43.181 ;
     RECT  74.214 43.162 74.592 43.181 ;
     RECT  74.61 43.162 74.988 43.181 ;
     RECT  75.006 43.162 75.42 43.181 ;
     RECT  75.438 43.162 75.816 43.181 ;
     RECT  75.834 43.162 76.212 43.181 ;
     RECT  76.23 43.162 76.608 43.181 ;
     RECT  76.626 43.162 77.004 43.181 ;
     RECT  77.022 43.162 77.436 43.181 ;
     RECT  77.454 43.162 77.832 43.181 ;
     RECT  77.85 43.162 78.228 43.181 ;
     RECT  78.246 43.162 78.624 43.181 ;
     RECT  78.642 43.162 79.02 43.181 ;
     RECT  79.038 43.162 79.452 43.181 ;
     RECT  79.47 43.162 79.848 43.181 ;
     RECT  79.866 43.162 80.244 43.181 ;
     RECT  80.262 43.162 80.64 43.181 ;
     RECT  80.658 43.162 81.036 43.181 ;
     RECT  81.054 43.162 81.468 43.181 ;
     RECT  81.486 43.162 81.864 43.181 ;
     RECT  81.882 43.162 82.26 43.181 ;
     RECT  82.278 43.162 82.656 43.181 ;
     RECT  82.674 43.162 83.052 43.181 ;
     RECT  83.07 43.162 83.484 43.181 ;
     RECT  83.502 43.162 83.88 43.181 ;
     RECT  83.898 43.162 84.276 43.181 ;
     RECT  84.294 43.162 84.672 43.181 ;
     RECT  84.69 43.162 85.068 43.181 ;
     RECT  85.086 43.162 85.5 43.181 ;
     RECT  85.518 43.162 85.896 43.181 ;
     RECT  85.914 43.162 86.292 43.181 ;
     RECT  86.31 43.162 86.688 43.181 ;
     RECT  86.706 43.162 87.084 43.181 ;
     RECT  87.102 43.162 87.516 43.181 ;
     RECT  87.534 43.162 87.912 43.181 ;
     RECT  87.93 43.162 88.308 43.181 ;
     RECT  88.326 43.162 88.704 43.181 ;
     RECT  88.722 43.162 89.136 43.181 ;
     RECT  89.154 43.162 89.532 43.181 ;
     RECT  89.55 43.162 89.928 43.181 ;
     RECT  89.946 43.162 90.324 43.181 ;
     RECT  90.342 43.162 90.72 43.181 ;
     RECT  90.738 43.162 91.152 43.181 ;
     RECT  91.17 43.162 91.548 43.181 ;
     RECT  91.566 43.162 91.944 43.181 ;
     RECT  91.962 43.162 92.34 43.181 ;
     RECT  92.358 43.162 92.736 43.181 ;
     RECT  92.754 43.162 93.168 43.181 ;
     RECT  93.186 43.162 93.564 43.181 ;
     RECT  93.582 43.162 93.96 43.181 ;
     RECT  93.978 43.162 94.356 43.181 ;
     RECT  94.374 43.162 94.752 43.181 ;
     RECT  94.77 43.162 95.184 43.181 ;
     RECT  95.202 43.162 95.58 43.181 ;
     RECT  95.598 43.162 95.976 43.181 ;
     RECT  95.994 43.162 96.372 43.181 ;
     RECT  96.39 43.162 96.768 43.181 ;
     RECT  96.786 43.162 97.2 43.181 ;
     RECT  97.218 43.162 97.596 43.181 ;
     RECT  97.614 43.162 97.992 43.181 ;
     RECT  98.01 43.162 98.388 43.181 ;
     RECT  98.406 43.162 98.784 43.181 ;
     RECT  98.802 43.162 99.216 43.181 ;
     RECT  99.234 43.162 99.612 43.181 ;
     RECT  99.63 43.162 100.008 43.181 ;
     RECT  100.026 43.162 100.404 43.181 ;
     RECT  100.422 43.162 100.836 43.181 ;
     RECT  100.854 43.162 101.232 43.181 ;
     RECT  101.25 43.162 101.628 43.181 ;
     RECT  101.646 43.162 102.024 43.181 ;
     RECT  102.042 43.162 102.42 43.181 ;
     RECT  102.438 43.162 102.852 43.181 ;
     RECT  102.87 43.162 103.248 43.181 ;
     RECT  103.266 43.162 103.644 43.181 ;
     RECT  103.662 43.162 104.04 43.181 ;
     RECT  104.058 43.162 104.436 43.181 ;
    LAYER M4 ;
     RECT  1.381 43.008 1.477 43.032 ;
     RECT  1.477 43.008 1.523 43.128 ;
     RECT  1.765 40.464 2.141 40.488 ;
     RECT  2.149 31.92 2.252 31.944 ;
     RECT  2.252 31.92 2.293 32.472 ;
     RECT  2.365 6.336 2.408 6.36 ;
     RECT  2.365 8.256 2.408 9.096 ;
     RECT  2.365 11.52 2.408 11.544 ;
     RECT  1.765 27.936 2.408 27.96 ;
     RECT  2.365 29.568 2.408 29.592 ;
     RECT  2.293 31.92 2.408 32.76 ;
     RECT  2.293 33.792 2.408 33.816 ;
     RECT  2.365 38.16 2.408 38.184 ;
     RECT  2.141 40.464 2.408 41.016 ;
     RECT  2.408 2.148 2.512 41.052 ;
     RECT  1.523 43.104 2.581 43.128 ;
     RECT  2.512 2.418 2.704 41.016 ;
     RECT  2.704 20.352 2.819 34.92 ;
     RECT  2.704 5.328 2.915 10.056 ;
     RECT  2.915 5.328 2.953 7.416 ;
     RECT  1.381 0.096 2.965 0.12 ;
     RECT  2.581 43.056 2.965 43.128 ;
     RECT  2.704 38.16 2.981 38.184 ;
     RECT  2.965 42.96 3.233 43.128 ;
     RECT  2.819 22.704 3.251 34.92 ;
     RECT  3.251 22.704 3.377 33.192 ;
     RECT  2.704 15.6 3.443 17.592 ;
     RECT  2.915 9.072 3.449 10.056 ;
     RECT  3.377 22.704 3.449 33.144 ;
     RECT  3.443 16.896 3.521 17.592 ;
     RECT  3.521 17.04 3.697 17.592 ;
     RECT  3.251 34.176 3.701 34.92 ;
     RECT  2.704 12.912 3.731 13.992 ;
     RECT  2.819 20.352 3.769 21.288 ;
     RECT  2.953 5.328 3.884 6.84 ;
     RECT  3.731 13.056 3.949 13.992 ;
     RECT  3.884 4.512 3.971 6.84 ;
     RECT  2.704 40.032 3.989 41.016 ;
     RECT  2.965 0.096 4.093 0.216 ;
     RECT  3.233 43.056 4.097 43.128 ;
     RECT  3.949 13.056 4.129 14.424 ;
     RECT  3.443 15.6 4.129 15.624 ;
     RECT  2.704 35.904 4.201 35.928 ;
     RECT  4.129 13.056 4.213 15.624 ;
     RECT  2.704 11.28 4.417 11.544 ;
     RECT  4.021 3.984 4.501 4.008 ;
     RECT  3.697 17.04 4.525 18.264 ;
     RECT  3.971 4.992 4.633 6.84 ;
     RECT  4.213 15.6 4.633 15.624 ;
     RECT  4.525 17.04 4.633 18.504 ;
     RECT  4.093 0.096 4.643 0.552 ;
     RECT  4.097 43.056 4.681 43.08 ;
     RECT  4.633 4.992 4.705 6.936 ;
     RECT  4.213 13.056 4.705 14.472 ;
     RECT  4.633 15.6 4.717 18.504 ;
     RECT  4.417 11.184 4.777 11.544 ;
     RECT  4.705 12.624 4.777 14.472 ;
     RECT  4.777 11.184 4.781 14.472 ;
     RECT  4.717 16.896 4.981 18.504 ;
     RECT  3.769 19.536 4.981 21.288 ;
     RECT  3.449 9.648 4.993 10.056 ;
     RECT  4.021 37.872 4.993 37.896 ;
     RECT  4.993 37.872 4.997 38.76 ;
     RECT  4.643 0.096 5.027 0.456 ;
     RECT  4.849 42.192 5.027 42.216 ;
     RECT  4.705 4.992 5.029 7.56 ;
     RECT  3.701 34.896 5.065 34.92 ;
     RECT  4.201 35.904 5.065 36.504 ;
     RECT  5.029 4.992 5.069 8.328 ;
     RECT  5.069 5.856 5.077 8.328 ;
     RECT  4.993 9.456 5.077 10.056 ;
     RECT  5.077 5.856 5.123 10.056 ;
     RECT  3.449 22.752 5.141 33.096 ;
     RECT  5.123 9.072 5.173 10.056 ;
     RECT  4.781 11.184 5.173 12.984 ;
     RECT  5.123 5.856 5.177 7.992 ;
     RECT  4.717 15.6 5.249 15.864 ;
     RECT  5.065 34.896 5.285 36.504 ;
     RECT  4.501 3.312 5.317 4.008 ;
     RECT  4.781 13.968 5.317 14.472 ;
     RECT  4.981 16.896 5.317 21.288 ;
     RECT  5.141 22.752 5.317 30.984 ;
     RECT  5.285 35.76 5.413 36.504 ;
     RECT  5.317 13.968 5.501 14.712 ;
     RECT  5.317 16.896 5.507 30.984 ;
     RECT  5.507 16.896 5.573 19.896 ;
     RECT  5.413 35.76 5.753 36.984 ;
     RECT  5.249 15.84 5.821 15.864 ;
     RECT  5.573 16.896 5.821 18.024 ;
     RECT  5.141 32.016 5.852 33.096 ;
     RECT  5.785 42.144 5.869 42.168 ;
     RECT  5.852 32.016 5.885 33.192 ;
     RECT  5.749 34.56 5.885 34.584 ;
     RECT  5.753 35.76 5.933 36.504 ;
     RECT  5.821 15.84 5.969 18.024 ;
     RECT  5.027 0.096 6.037 0.216 ;
     RECT  5.507 20.928 6.181 30.984 ;
     RECT  5.885 32.016 6.181 34.584 ;
     RECT  5.173 9.072 6.229 12.984 ;
     RECT  5.501 13.968 6.229 13.992 ;
     RECT  5.177 6.336 6.245 7.992 ;
     RECT  6.229 9.072 6.245 13.992 ;
     RECT  6.245 6.336 6.275 13.992 ;
     RECT  6.275 6.336 6.323 10.584 ;
     RECT  6.323 6.336 6.329 10.536 ;
     RECT  4.997 38.736 6.401 38.76 ;
     RECT  3.989 40.032 6.613 40.056 ;
     RECT  5.573 19.104 6.661 19.896 ;
     RECT  6.181 20.928 6.661 34.584 ;
     RECT  5.317 3.312 6.721 4.296 ;
     RECT  6.275 11.952 6.793 13.992 ;
     RECT  6.721 3.312 6.803 5.352 ;
     RECT  6.661 19.104 6.901 34.584 ;
     RECT  5.933 35.76 6.901 35.784 ;
     RECT  5.969 15.984 7.297 18.024 ;
     RECT  6.901 19.104 7.297 35.784 ;
     RECT  6.793 11.952 7.381 14.376 ;
     RECT  7.297 15.984 7.381 35.784 ;
     RECT  6.037 0.096 7.388 0.504 ;
     RECT  6.803 4.8 7.436 5.352 ;
     RECT  6.329 6.336 7.436 7.896 ;
     RECT  6.757 37.92 7.441 37.944 ;
     RECT  6.803 3.312 7.477 3.336 ;
     RECT  7.441 37.92 7.549 38.76 ;
     RECT  7.381 11.952 7.669 35.784 ;
     RECT  6.181 43.056 7.693 43.08 ;
     RECT  7.477 2.784 7.808 3.336 ;
     RECT  7.436 4.8 7.808 7.896 ;
     RECT  6.329 9.072 7.808 10.536 ;
     RECT  7.669 11.952 7.808 35.88 ;
     RECT  7.549 37.44 7.808 38.76 ;
     RECT  6.613 40.032 7.808 40.968 ;
     RECT  7.693 42.192 7.859 43.08 ;
     RECT  7.808 2.148 7.912 41.052 ;
     RECT  7.912 2.418 8.021 40.968 ;
     RECT  8.021 2.418 8.104 40.782 ;
     RECT  8.104 33.648 8.201 35.784 ;
     RECT  8.104 22.8 8.243 32.328 ;
     RECT  8.104 2.784 8.291 5.448 ;
     RECT  8.104 7.44 8.309 7.656 ;
     RECT  8.104 37.056 8.345 38.712 ;
     RECT  8.291 2.784 8.381 3.432 ;
     RECT  8.104 11.376 8.669 12.888 ;
     RECT  8.104 40.032 8.741 40.44 ;
     RECT  8.669 12.528 8.885 12.888 ;
     RECT  8.741 40.032 8.885 40.296 ;
     RECT  7.388 0.096 9.029 0.552 ;
     RECT  8.104 9.216 9.029 10.344 ;
     RECT  8.104 13.968 9.157 18.84 ;
     RECT  8.104 19.824 9.157 21.816 ;
     RECT  8.243 31.104 9.157 32.328 ;
     RECT  8.201 33.648 9.157 34.2 ;
     RECT  9.157 13.968 9.203 21.816 ;
     RECT  8.309 7.44 9.205 7.464 ;
     RECT  8.201 35.76 9.205 35.784 ;
     RECT  8.345 37.056 9.205 37.944 ;
     RECT  9.029 9.984 9.209 10.344 ;
     RECT  8.669 11.376 9.209 11.4 ;
     RECT  9.203 17.568 9.244 21.816 ;
     RECT  8.243 22.8 9.245 30.024 ;
     RECT  9.205 35.76 9.245 37.944 ;
     RECT  8.291 4.512 9.317 5.448 ;
     RECT  9.245 25.872 9.349 30.024 ;
     RECT  9.157 31.104 9.349 34.2 ;
     RECT  9.317 4.512 9.353 4.536 ;
     RECT  9.209 10.272 9.385 10.344 ;
     RECT  8.885 12.576 9.445 12.888 ;
     RECT  9.203 13.968 9.445 16.344 ;
     RECT  9.349 25.872 9.461 34.2 ;
     RECT  9.029 0.528 9.491 0.552 ;
     RECT  9.244 19.92 9.493 21.816 ;
     RECT  9.245 22.8 9.493 24.216 ;
     RECT  9.493 19.92 9.532 24.216 ;
     RECT  9.532 20.448 9.561 24.216 ;
     RECT  9.205 6.816 9.565 7.464 ;
     RECT  9.313 8.448 9.565 8.472 ;
     RECT  9.561 20.448 9.641 23.4 ;
     RECT  9.245 35.904 9.731 37.944 ;
     RECT  9.641 20.448 9.785 21.288 ;
     RECT  9.461 26.016 9.821 34.2 ;
     RECT  9.836 34.608 9.923 34.632 ;
     RECT  9.821 26.016 9.929 33.048 ;
     RECT  8.381 3.408 9.961 3.432 ;
     RECT  9.731 36.24 9.961 37.944 ;
     RECT  9.445 12.576 10.109 16.344 ;
     RECT  9.244 17.568 10.109 18.84 ;
     RECT  9.961 2.832 10.213 3.432 ;
     RECT  7.859 43.056 10.213 43.08 ;
     RECT  9.925 0.576 10.259 0.6 ;
     RECT  9.385 10.272 10.285 11.016 ;
     RECT  8.885 40.272 10.285 40.296 ;
     RECT  10.213 42.144 10.297 43.08 ;
     RECT  9.961 36.24 10.309 38.664 ;
     RECT  10.309 36.24 10.355 38.712 ;
     RECT  10.213 2.736 10.393 3.432 ;
     RECT  9.565 6.816 10.433 8.472 ;
     RECT  10.069 5.616 10.46 5.64 ;
     RECT  10.433 6.816 10.46 6.888 ;
     RECT  9.929 26.016 10.505 32.904 ;
     RECT  10.46 5.616 10.537 6.888 ;
     RECT  10.285 10.128 10.573 11.016 ;
     RECT  10.393 2.736 10.577 3.528 ;
     RECT  10.433 7.968 10.609 8.472 ;
     RECT  9.785 20.448 10.645 20.568 ;
     RECT  10.577 2.784 10.649 3.528 ;
     RECT  10.537 5.52 10.681 6.888 ;
     RECT  10.109 18.672 10.685 18.84 ;
     RECT  10.109 12.768 10.721 16.344 ;
     RECT  10.645 20.064 10.753 20.568 ;
     RECT  9.641 22.464 10.753 23.4 ;
     RECT  10.609 7.968 10.789 8.856 ;
     RECT  10.753 22.464 10.793 23.928 ;
     RECT  10.681 5.232 10.825 6.888 ;
     RECT  10.109 17.616 10.835 17.64 ;
     RECT  10.285 39.888 10.837 40.296 ;
     RECT  10.649 2.832 10.865 3.528 ;
     RECT  10.753 20.064 10.865 20.616 ;
     RECT  10.505 26.832 10.865 32.904 ;
     RECT  10.789 7.968 10.873 9.144 ;
     RECT  10.721 12.768 10.883 15.432 ;
     RECT  10.865 30.672 10.909 32.808 ;
     RECT  10.909 31.152 10.979 32.808 ;
     RECT  10.865 26.832 11.009 29.496 ;
     RECT  10.883 12.768 11.081 14.904 ;
     RECT  10.837 39.888 11.153 40.824 ;
     RECT  10.793 23.904 11.221 23.928 ;
     RECT  10.825 4.752 11.257 6.888 ;
     RECT  11.257 4.272 11.297 6.888 ;
     RECT  10.355 36.24 11.365 37.608 ;
     RECT  10.355 38.64 11.365 38.712 ;
     RECT  11.009 26.832 11.477 27.912 ;
     RECT  11.293 0.096 11.507 0.12 ;
     RECT  11.365 36.24 11.545 38.712 ;
     RECT  10.865 20.592 11.581 20.616 ;
     RECT  10.573 10.128 11.653 11.448 ;
     RECT  11.081 12.768 11.653 13.656 ;
     RECT  11.221 23.904 11.725 24.648 ;
     RECT  11.941 17.184 11.969 17.208 ;
     RECT  10.865 2.832 11.977 2.856 ;
     RECT  10.979 31.152 11.977 31.176 ;
     RECT  11.153 39.888 11.981 39.912 ;
     RECT  11.969 16.416 11.989 17.208 ;
     RECT  11.545 36.192 12.013 38.712 ;
     RECT  10.297 43.056 12.017 43.08 ;
     RECT  11.989 16.416 12.076 17.496 ;
     RECT  10.793 22.464 12.085 22.872 ;
     RECT  12.013 35.328 12.089 38.712 ;
     RECT  11.977 2.784 12.121 2.856 ;
     RECT  10.873 7.968 12.121 9 ;
     RECT  10.979 32.496 12.121 32.808 ;
     RECT  11.581 20.592 12.157 20.76 ;
     RECT  12.085 22.272 12.157 22.872 ;
     RECT  11.725 23.904 12.157 25.128 ;
     RECT  11.977 30.816 12.157 31.176 ;
     RECT  12.157 19.92 12.181 20.76 ;
     RECT  12.157 22.272 12.181 25.128 ;
     RECT  12.089 38.112 12.233 38.712 ;
     RECT  11.297 4.272 12.301 6.12 ;
     RECT  12.121 7.536 12.301 9 ;
     RECT  12.233 38.208 12.337 38.712 ;
     RECT  12.301 4.272 12.445 9 ;
     RECT  11.653 10.128 12.445 13.656 ;
     RECT  11.009 29.088 12.445 29.496 ;
     RECT  12.157 30.72 12.445 31.176 ;
     RECT  12.121 32.496 12.445 33.048 ;
     RECT  11.477 26.832 12.481 27.432 ;
     RECT  12.445 28.656 12.524 29.496 ;
     RECT  8.917 1.728 12.661 1.752 ;
     RECT  12.524 28.656 12.661 29.64 ;
     RECT  12.445 30.72 12.661 33.048 ;
     RECT  12.181 19.92 12.697 25.128 ;
     RECT  12.481 26.256 12.697 27.432 ;
     RECT  12.697 19.92 12.769 27.432 ;
     RECT  12.661 28.656 12.769 33.048 ;
     RECT  11.081 14.688 12.841 14.904 ;
     RECT  12.076 16.416 12.841 17.448 ;
     RECT  12.769 19.92 12.985 33.048 ;
     RECT  12.661 1.728 13.004 1.8 ;
     RECT  12.121 2.784 13.004 3.144 ;
     RECT  12.157 42.192 13.013 42.216 ;
     RECT  12.841 14.688 13.057 17.448 ;
     RECT  13.013 42.144 13.097 42.216 ;
     RECT  13.004 1.728 13.133 3.144 ;
     RECT  13.133 1.776 13.208 3.144 ;
     RECT  12.445 4.272 13.208 13.656 ;
     RECT  13.057 14.688 13.208 17.64 ;
     RECT  10.685 18.672 13.208 18.696 ;
     RECT  12.985 19.776 13.208 33.048 ;
     RECT  12.089 35.328 13.208 36.84 ;
     RECT  12.337 38.208 13.208 38.808 ;
     RECT  13.208 1.776 13.504 41.052 ;
     RECT  13.504 19.488 13.673 33.672 ;
     RECT  13.477 43.056 13.673 43.08 ;
     RECT  13.477 0.096 13.745 0.12 ;
     RECT  13.673 23.616 13.889 33.672 ;
     RECT  13.889 23.616 13.907 33.624 ;
     RECT  13.597 41.616 13.907 41.64 ;
     RECT  13.504 14.256 13.961 15.96 ;
     RECT  13.504 10.128 13.997 10.968 ;
     RECT  13.504 1.776 14.033 2.76 ;
     RECT  13.504 5.712 14.069 6.936 ;
     RECT  13.504 11.952 14.105 13.08 ;
     RECT  13.907 28.8 14.321 33.624 ;
     RECT  14.033 2.736 14.465 2.76 ;
     RECT  13.961 14.256 14.465 15.72 ;
     RECT  14.321 28.8 14.465 31.8 ;
     RECT  13.504 16.992 14.497 18.168 ;
     RECT  14.069 5.712 14.501 5.88 ;
     RECT  13.907 23.616 14.501 27.72 ;
     RECT  13.504 3.888 14.533 3.912 ;
     RECT  13.504 35.52 14.533 35.544 ;
     RECT  14.465 15.696 14.537 15.72 ;
     RECT  14.533 2.832 14.569 3.912 ;
     RECT  14.069 6.864 14.569 6.936 ;
     RECT  14.533 35.328 14.579 35.544 ;
     RECT  14.321 32.784 14.581 33.624 ;
     RECT  14.497 16.8 14.609 18.168 ;
     RECT  13.504 40.416 14.609 40.44 ;
     RECT  13.504 36.816 14.645 36.84 ;
     RECT  14.569 2.832 14.677 4.68 ;
     RECT  14.501 5.712 14.677 5.736 ;
     RECT  14.465 28.8 14.717 31.704 ;
     RECT  14.105 11.952 14.749 12.6 ;
     RECT  14.501 24.48 14.753 27.72 ;
     RECT  14.717 28.8 14.825 30.888 ;
     RECT  13.504 8.832 14.857 8.856 ;
     RECT  13.997 10.128 14.857 10.152 ;
     RECT  14.857 8.784 14.893 8.856 ;
     RECT  14.857 9.84 14.893 10.152 ;
     RECT  13.673 19.488 14.893 22.584 ;
     RECT  14.677 2.832 14.897 5.736 ;
     RECT  14.893 19.44 14.917 22.584 ;
     RECT  14.876 0.048 14.963 0.072 ;
     RECT  14.893 8.784 15.001 10.152 ;
     RECT  14.749 11.184 15.001 12.6 ;
     RECT  15.001 8.784 15.005 12.6 ;
     RECT  14.917 19.44 15.077 23.4 ;
     RECT  14.753 26.592 15.113 27.72 ;
     RECT  13.504 38.64 15.149 38.712 ;
     RECT  14.569 6.864 15.185 7.704 ;
     RECT  15.149 38.688 15.253 38.712 ;
     RECT  15.005 8.784 15.365 10.824 ;
     RECT  14.753 24.48 15.365 25.56 ;
     RECT  15.365 8.784 15.397 9.768 ;
     RECT  14.581 32.784 15.433 32.808 ;
     RECT  15.185 6.864 15.443 6.888 ;
     RECT  15.397 42.144 15.493 42.168 ;
     RECT  15.077 19.44 15.505 23.352 ;
     RECT  15.397 7.92 15.545 9.768 ;
     RECT  14.825 28.8 15.577 30.744 ;
     RECT  15.545 8.496 15.617 9.768 ;
     RECT  15.505 19.344 15.644 23.352 ;
     RECT  14.609 16.8 15.649 17.64 ;
     RECT  15.644 19.296 15.649 23.352 ;
     RECT  14.465 14.256 15.721 14.664 ;
     RECT  15.433 31.92 15.725 32.808 ;
     RECT  14.897 2.832 15.761 5.592 ;
     RECT  15.617 8.496 15.761 9.672 ;
     RECT  15.493 0.096 15.781 0.12 ;
     RECT  15.761 3.888 15.901 5.592 ;
     RECT  15.365 24.72 15.905 25.56 ;
     RECT  15.905 24.816 15.941 25.56 ;
     RECT  14.677 40.992 15.941 41.016 ;
     RECT  15.941 25.008 15.977 25.56 ;
     RECT  15.005 11.952 16.009 12.6 ;
     RECT  15.901 3.888 16.049 6.792 ;
     RECT  15.761 8.592 16.049 9.672 ;
     RECT  16.049 8.592 16.085 8.616 ;
     RECT  15.761 2.832 16.157 2.904 ;
     RECT  16.049 3.888 16.229 5.448 ;
     RECT  16.009 11.952 16.261 12.792 ;
     RECT  15.253 38.688 16.289 38.808 ;
     RECT  16.261 11.952 16.333 13.128 ;
     RECT  15.721 14.256 16.333 14.856 ;
     RECT  16.289 38.16 16.373 38.808 ;
     RECT  16.333 11.952 16.477 14.856 ;
     RECT  15.725 31.92 16.589 32.472 ;
     RECT  15.365 10.8 16.621 10.824 ;
     RECT  15.977 25.104 16.621 25.56 ;
     RECT  15.113 26.592 16.621 26.856 ;
     RECT  16.049 9.648 16.661 9.672 ;
     RECT  16.477 11.952 16.684 15.384 ;
     RECT  16.513 40.608 16.739 40.632 ;
     RECT  16.373 38.688 16.769 38.808 ;
     RECT  16.229 3.888 16.78 4.968 ;
     RECT  16.157 2.88 16.835 2.904 ;
     RECT  16.78 4.944 16.835 4.968 ;
     RECT  15.649 16.8 16.913 23.352 ;
     RECT  16.621 25.104 16.945 26.856 ;
     RECT  15.781 0.096 17.036 0.504 ;
     RECT  16.621 10.8 17.077 10.872 ;
     RECT  16.913 17.088 17.093 23.352 ;
     RECT  17.036 0.096 17.123 0.552 ;
     RECT  16.78 3.888 17.197 3.96 ;
     RECT  16.049 6.768 17.305 6.792 ;
     RECT  17.305 6.24 17.345 6.792 ;
     RECT  16.684 11.952 17.413 12.792 ;
     RECT  17.413 11.904 17.453 12.792 ;
     RECT  16.945 24.864 17.485 26.856 ;
     RECT  15.577 27.888 17.485 30.744 ;
     RECT  15.493 42.144 17.555 43.08 ;
     RECT  17.093 17.088 17.597 22.776 ;
     RECT  15.685 37.008 17.605 37.032 ;
     RECT  17.123 0.096 17.66 0.504 ;
     RECT  16.589 31.92 17.665 31.944 ;
     RECT  17.485 24.864 17.701 30.744 ;
     RECT  17.665 31.872 17.701 31.944 ;
     RECT  17.345 6.24 17.737 6.264 ;
     RECT  17.66 0.048 17.747 0.504 ;
     RECT  17.701 24.864 17.749 31.944 ;
     RECT  16.117 34.08 17.749 34.104 ;
     RECT  16.684 13.872 17.809 15.384 ;
     RECT  14.579 35.328 17.989 35.352 ;
     RECT  17.737 6.096 18.025 6.264 ;
     RECT  17.077 10.224 18.061 10.872 ;
     RECT  17.453 11.904 18.061 12.6 ;
     RECT  18.061 10.224 18.133 12.6 ;
     RECT  17.749 24.864 18.205 32.232 ;
     RECT  17.597 18.816 18.236 22.776 ;
     RECT  18.205 24.144 18.236 32.232 ;
     RECT  17.555 43.008 18.281 43.08 ;
     RECT  18.025 5.28 18.313 6.264 ;
     RECT  17.597 17.088 18.421 17.592 ;
     RECT  17.605 36.384 18.457 37.032 ;
     RECT  18.313 4.944 18.469 6.264 ;
     RECT  17.017 7.968 18.469 7.992 ;
     RECT  17.197 3.84 18.529 3.96 ;
     RECT  18.469 4.944 18.529 7.992 ;
     RECT  18.281 43.008 18.529 43.032 ;
     RECT  17.747 0.096 18.533 0.504 ;
     RECT  18.529 3.84 18.565 7.992 ;
     RECT  18.457 9.024 18.565 9.048 ;
     RECT  18.565 3.84 18.608 9.048 ;
     RECT  18.133 10.128 18.608 12.6 ;
     RECT  17.809 13.824 18.608 15.384 ;
     RECT  18.421 16.56 18.608 17.592 ;
     RECT  18.236 18.816 18.608 32.232 ;
     RECT  17.749 33.264 18.608 34.104 ;
     RECT  17.989 35.232 18.608 35.352 ;
     RECT  18.457 36.336 18.608 37.032 ;
     RECT  16.769 38.688 18.608 38.712 ;
     RECT  17.053 39.84 18.608 39.864 ;
     RECT  18.608 2.148 18.712 41.052 ;
     RECT  18.533 0.096 18.755 0.168 ;
     RECT  18.712 2.256 18.904 41.016 ;
     RECT  18.904 2.256 19.043 2.808 ;
     RECT  18.904 6.096 19.073 6.264 ;
     RECT  18.904 24.144 19.073 29.784 ;
     RECT  18.755 0.144 19.187 0.168 ;
     RECT  18.904 39.744 19.253 39.864 ;
     RECT  18.529 42.192 19.253 43.032 ;
     RECT  18.904 30.96 19.283 33.096 ;
     RECT  18.904 3.84 19.289 4.968 ;
     RECT  18.904 7.344 19.433 17.64 ;
     RECT  19.289 4.944 19.505 4.968 ;
     RECT  19.433 7.344 19.571 9.144 ;
     RECT  19.493 42.144 19.577 42.168 ;
     RECT  18.904 38.688 19.613 38.76 ;
     RECT  19.433 10.608 19.619 17.64 ;
     RECT  19.283 30.96 19.708 32.712 ;
     RECT  19.619 14.784 19.793 17.64 ;
     RECT  19.571 7.344 19.897 8.76 ;
     RECT  19.073 24.144 20.003 29.496 ;
     RECT  20.003 24.144 20.081 25.176 ;
     RECT  19.613 38.688 20.101 38.712 ;
     RECT  19.708 30.96 20.117 32.232 ;
     RECT  18.904 18.72 20.185 23.16 ;
     RECT  20.101 37.824 20.188 38.712 ;
     RECT  19.073 6.096 20.293 6.12 ;
     RECT  20.185 18.72 20.339 23.784 ;
     RECT  20.149 30.912 20.405 30.936 ;
     RECT  20.293 5.184 20.441 6.12 ;
     RECT  19.619 10.608 20.477 13.704 ;
     RECT  18.904 40.992 20.513 41.016 ;
     RECT  20.003 26.208 20.533 29.496 ;
     RECT  19.793 14.832 20.541 17.64 ;
     RECT  19.897 7.2 20.545 8.76 ;
     RECT  20.477 10.608 20.545 12.936 ;
     RECT  20.533 26.208 20.579 29.784 ;
     RECT  20.339 18.72 20.581 23.4 ;
     RECT  20.579 28.848 20.62 29.784 ;
     RECT  20.541 17.136 20.629 17.64 ;
     RECT  20.581 18.624 20.629 23.4 ;
     RECT  20.545 7.2 20.729 9.384 ;
     RECT  20.117 32.208 20.761 32.232 ;
     RECT  20.629 17.136 20.765 23.4 ;
     RECT  18.904 34.08 20.801 34.104 ;
     RECT  20.729 7.2 20.909 7.608 ;
     RECT  20.765 17.616 20.909 23.4 ;
     RECT  18.904 35.232 20.945 35.256 ;
     RECT  20.909 17.616 20.981 19.032 ;
     RECT  20.441 5.184 21.053 5.784 ;
     RECT  20.909 20.112 21.053 23.4 ;
     RECT  20.62 28.848 21.107 29.496 ;
     RECT  20.725 43.056 21.109 43.08 ;
     RECT  20.729 8.688 21.125 9.384 ;
     RECT  20.981 19.008 21.125 19.032 ;
     RECT  21.109 42.192 21.161 43.08 ;
     RECT  21.053 20.112 21.197 20.568 ;
     RECT  21.161 42.192 21.233 42.216 ;
     RECT  21.053 21.648 21.269 23.4 ;
     RECT  20.981 17.616 21.305 17.64 ;
     RECT  20.761 32.208 21.445 33.048 ;
     RECT  21.409 30.768 21.481 30.792 ;
     RECT  21.445 32.208 21.481 33.144 ;
     RECT  21.109 0.192 21.541 0.216 ;
     RECT  21.481 30.768 21.593 33.144 ;
     RECT  18.904 36.336 21.593 36.36 ;
     RECT  21.509 40.992 21.593 41.016 ;
     RECT  20.545 10.56 21.625 12.936 ;
     RECT  20.541 14.832 21.625 16.104 ;
     RECT  21.541 0.144 21.637 0.216 ;
     RECT  21.625 10.416 21.661 12.936 ;
     RECT  20.188 38.16 21.661 38.712 ;
     RECT  19.253 39.744 21.661 39.768 ;
     RECT  21.661 10.416 21.665 13.752 ;
     RECT  21.269 21.792 21.683 23.4 ;
     RECT  21.661 38.16 21.701 39.768 ;
     RECT  21.625 14.832 21.731 16.44 ;
     RECT  21.107 28.944 21.733 29.496 ;
     RECT  21.125 8.736 21.737 9.384 ;
     RECT  21.731 16.08 21.737 16.44 ;
     RECT  20.081 24.96 21.841 25.176 ;
     RECT  21.683 21.792 21.881 23.016 ;
     RECT  21.593 30.768 21.949 30.792 ;
     RECT  21.949 30.672 22.021 30.792 ;
     RECT  21.737 9.36 22.097 9.384 ;
     RECT  21.697 34.464 22.097 34.488 ;
     RECT  20.579 26.208 22.124 27.624 ;
     RECT  21.733 28.944 22.124 29.64 ;
     RECT  21.053 5.28 22.201 5.784 ;
     RECT  22.124 26.208 22.211 29.64 ;
     RECT  19.043 2.784 22.229 2.808 ;
     RECT  19.289 3.84 22.229 3.864 ;
     RECT  22.229 2.784 22.261 3.864 ;
     RECT  21.197 20.544 22.273 20.568 ;
     RECT  21.925 36.96 22.309 36.984 ;
     RECT  21.637 0.048 22.316 0.216 ;
     RECT  22.309 40.416 22.403 40.44 ;
     RECT  22.316 0.048 22.421 0.552 ;
     RECT  22.211 29.328 22.421 29.64 ;
     RECT  22.261 2.544 22.453 3.864 ;
     RECT  22.273 20.544 22.529 20.856 ;
     RECT  20.909 7.248 22.669 7.608 ;
     RECT  22.021 30.624 22.693 30.792 ;
     RECT  21.593 31.872 22.693 33.144 ;
     RECT  22.421 29.472 22.739 29.64 ;
     RECT  22.693 30.624 22.741 33.144 ;
     RECT  21.701 38.16 22.741 39.384 ;
     RECT  22.453 2.544 22.777 4.008 ;
     RECT  22.201 5.04 22.777 5.784 ;
     RECT  22.741 30.432 22.781 33.144 ;
     RECT  22.309 36.96 22.781 37.032 ;
     RECT  22.561 41.04 22.787 41.064 ;
     RECT  21.881 22.56 22.789 23.016 ;
     RECT  22.669 7.248 22.813 8.232 ;
     RECT  21.665 10.416 22.813 12.216 ;
     RECT  21.665 13.536 22.813 13.752 ;
     RECT  22.021 14.784 22.813 14.808 ;
     RECT  21.737 16.224 22.813 16.44 ;
     RECT  22.777 2.544 22.817 5.784 ;
     RECT  22.781 31.872 22.825 33.144 ;
     RECT  22.741 38.16 22.828 40.008 ;
     RECT  21.841 24.672 22.835 25.176 ;
     RECT  22.817 3.84 22.849 5.784 ;
     RECT  22.813 7.248 22.849 9.096 ;
     RECT  22.825 31.92 22.853 33.144 ;
     RECT  22.828 38.16 22.889 39.384 ;
     RECT  22.781 36.96 22.925 36.984 ;
     RECT  22.853 33.072 22.957 33.144 ;
     RECT  22.813 10.416 23.029 14.808 ;
     RECT  22.813 15.888 23.029 16.44 ;
     RECT  22.957 33.072 23.029 33.24 ;
     RECT  22.741 34.224 23.029 34.248 ;
     RECT  22.421 0.048 23.033 0.12 ;
     RECT  22.529 20.832 23.281 20.856 ;
     RECT  22.789 22.56 23.317 23.352 ;
     RECT  22.381 18.672 23.365 18.696 ;
     RECT  22.7 1.104 23.525 1.128 ;
     RECT  22.817 2.544 23.525 2.808 ;
     RECT  23.093 43.056 23.557 43.08 ;
     RECT  22.837 17.664 23.569 17.688 ;
     RECT  23.365 18.672 23.569 19.368 ;
     RECT  22.705 35.424 23.569 35.448 ;
     RECT  23.029 10.416 23.605 16.44 ;
     RECT  23.557 42.144 23.645 43.08 ;
     RECT  23.029 33.072 23.677 34.248 ;
     RECT  23.569 35.424 23.677 36.024 ;
     RECT  22.849 3.84 23.708 9.096 ;
     RECT  23.605 10.32 23.708 16.44 ;
     RECT  22.835 24.672 23.821 24.984 ;
     RECT  22.211 26.256 23.821 27.912 ;
     RECT  22.889 38.688 23.893 39.384 ;
     RECT  23.317 22.224 23.965 23.352 ;
     RECT  23.821 24.672 23.965 27.912 ;
     RECT  23.677 33.072 23.965 36.024 ;
     RECT  23.525 1.104 23.987 2.808 ;
     RECT  23.987 1.728 24.001 2.808 ;
     RECT  23.708 3.84 24.001 16.44 ;
     RECT  24.001 1.728 24.008 16.44 ;
     RECT  23.569 17.664 24.008 19.368 ;
     RECT  23.281 20.832 24.008 21.144 ;
     RECT  23.965 22.224 24.008 27.912 ;
     RECT  22.781 30.432 24.008 30.696 ;
     RECT  22.853 31.92 24.008 31.944 ;
     RECT  23.965 33.072 24.008 36.072 ;
     RECT  23.893 38.688 24.008 40.344 ;
     RECT  24.008 1.728 24.112 41.052 ;
     RECT  24.112 1.728 24.304 40.782 ;
     RECT  24.304 6.384 24.419 17.112 ;
     RECT  24.304 1.728 24.473 5.064 ;
     RECT  24.304 30.384 24.473 37.08 ;
     RECT  24.473 30.384 24.545 31.992 ;
     RECT  24.419 6.384 24.581 15.48 ;
     RECT  23.645 43.056 24.653 43.08 ;
     RECT  24.473 32.976 24.689 37.08 ;
     RECT  24.304 18.192 24.797 28.152 ;
     RECT  24.689 32.976 24.797 34.152 ;
     RECT  24.473 1.728 24.803 2.808 ;
     RECT  24.419 17.088 24.833 17.112 ;
     RECT  24.797 33.072 24.941 34.152 ;
     RECT  24.581 6.48 24.995 15.48 ;
     RECT  24.797 18.192 25.013 18.504 ;
     RECT  24.304 38.16 25.013 39.288 ;
     RECT  24.304 40.464 25.049 40.782 ;
     RECT  24.995 6.48 25.139 11.832 ;
     RECT  24.803 1.728 25.193 1.752 ;
     RECT  25.109 40.992 25.193 41.016 ;
     RECT  25.013 18.192 25.229 18.216 ;
     RECT  24.689 35.856 25.229 37.08 ;
     RECT  24.797 19.488 25.331 28.152 ;
     RECT  25.331 19.488 25.481 27.912 ;
     RECT  25.477 29.04 25.513 29.064 ;
     RECT  24.545 30.384 25.513 31.944 ;
     RECT  23.033 0.048 25.516 0.072 ;
     RECT  25.516 0.048 25.517 0.12 ;
     RECT  25.139 10.272 25.517 11.832 ;
     RECT  25.481 26.208 25.517 27.912 ;
     RECT  25.139 6.48 25.553 9.192 ;
     RECT  24.473 3.888 25.585 5.064 ;
     RECT  24.803 2.784 25.621 2.808 ;
     RECT  25.585 3.888 25.621 5.16 ;
     RECT  25.553 6.48 25.625 7.992 ;
     RECT  25.573 41.568 25.661 41.592 ;
     RECT  25.229 35.856 25.697 36.696 ;
     RECT  25.517 0.096 25.717 0.12 ;
     RECT  25.697 35.856 25.729 36.504 ;
     RECT  25.481 19.488 25.733 24.936 ;
     RECT  25.513 29.04 25.763 31.944 ;
     RECT  25.693 17.04 25.841 17.064 ;
     RECT  25.553 9.072 25.913 9.192 ;
     RECT  25.517 10.272 25.913 10.776 ;
     RECT  24.941 33.072 25.945 33.672 ;
     RECT  25.729 34.8 25.945 36.504 ;
     RECT  25.945 33.072 26.093 36.504 ;
     RECT  24.995 13.104 26.165 15.48 ;
     RECT  25.733 19.488 26.165 21.096 ;
     RECT  25.763 29.376 26.195 31.944 ;
     RECT  25.013 38.16 26.201 39.192 ;
     RECT  25.517 11.808 26.233 11.832 ;
     RECT  26.093 36.096 26.243 36.504 ;
     RECT  26.233 11.808 26.341 11.928 ;
     RECT  26.165 13.104 26.341 15.336 ;
     RECT  25.625 6.48 26.449 7.944 ;
     RECT  26.093 33.072 26.453 35.064 ;
     RECT  25.733 22.176 26.485 24.936 ;
     RECT  26.453 33.072 26.485 34.872 ;
     RECT  26.449 6.24 26.489 7.944 ;
     RECT  25.517 27.6 26.521 27.912 ;
     RECT  26.485 22.176 26.525 25.128 ;
     RECT  26.485 32.928 26.525 34.872 ;
     RECT  26.165 19.488 26.561 20.376 ;
     RECT  25.717 0.096 26.588 0.552 ;
     RECT  25.517 26.208 26.593 26.616 ;
     RECT  26.521 27.6 26.593 27.96 ;
     RECT  26.525 32.928 26.597 34.632 ;
     RECT  26.201 38.16 26.675 38.808 ;
     RECT  25.693 18.144 26.701 18.168 ;
     RECT  26.561 19.488 26.701 19.512 ;
     RECT  26.701 18.144 26.741 19.512 ;
     RECT  26.195 30.192 26.741 31.944 ;
     RECT  25.913 9.072 26.773 9.144 ;
     RECT  26.525 22.512 26.773 25.128 ;
     RECT  26.593 26.208 26.773 27.96 ;
     RECT  25.913 10.608 26.813 10.776 ;
     RECT  26.741 30.192 26.813 30.744 ;
     RECT  26.741 31.92 26.813 31.944 ;
     RECT  26.489 6.24 26.819 7.896 ;
     RECT  26.341 11.808 26.885 15.336 ;
     RECT  26.773 8.976 26.921 9.144 ;
     RECT  26.885 12.864 26.921 15.336 ;
     RECT  26.921 12.864 26.957 13.944 ;
     RECT  26.675 38.16 26.957 38.712 ;
     RECT  26.243 36.48 27.025 36.504 ;
     RECT  26.957 13.104 27.065 13.848 ;
     RECT  26.773 22.512 27.065 28.632 ;
     RECT  27.065 13.296 27.173 13.848 ;
     RECT  26.597 32.928 27.205 34.152 ;
     RECT  26.885 11.808 27.313 11.832 ;
     RECT  26.819 6.24 27.353 6.936 ;
     RECT  27.025 17.088 27.457 17.112 ;
     RECT  27.349 29.088 27.461 29.112 ;
     RECT  27.205 32.448 27.641 34.152 ;
     RECT  25.957 43.056 27.749 43.08 ;
     RECT  26.813 10.608 27.781 10.632 ;
     RECT  27.173 13.296 27.821 13.704 ;
     RECT  27.781 20.064 27.853 20.088 ;
     RECT  25.621 2.784 27.857 5.16 ;
     RECT  27.065 22.512 27.857 27.96 ;
     RECT  26.921 8.976 27.889 9 ;
     RECT  27.457 17.04 27.889 17.112 ;
     RECT  26.741 18.144 27.889 18.84 ;
     RECT  27.853 20.016 27.889 20.088 ;
     RECT  27.641 33.312 27.889 34.152 ;
     RECT  27.857 4.512 27.925 5.16 ;
     RECT  27.857 24.144 27.929 27.96 ;
     RECT  26.665 40.464 27.973 40.488 ;
     RECT  27.353 6.864 28.037 6.936 ;
     RECT  26.813 30.384 28.069 30.744 ;
     RECT  27.157 37.584 28.073 37.608 ;
     RECT  27.973 40.416 28.109 40.488 ;
     RECT  27.889 20.016 28.141 20.904 ;
     RECT  27.857 2.784 28.145 3.384 ;
     RECT  27.889 17.04 28.145 18.84 ;
     RECT  27.889 8.256 28.177 9 ;
     RECT  27.925 4.512 28.217 5.736 ;
     RECT  28.145 17.04 28.253 18.744 ;
     RECT  28.141 20.016 28.253 21.096 ;
     RECT  28.172 2.688 28.259 2.712 ;
     RECT  28.217 4.512 28.289 5.112 ;
     RECT  28.253 20.016 28.289 20.904 ;
     RECT  28.253 17.04 28.361 17.736 ;
     RECT  27.857 22.512 28.393 22.728 ;
     RECT  26.588 0.048 28.451 0.552 ;
     RECT  28.364 41.04 28.451 41.064 ;
     RECT  26.921 15.216 28.46 15.336 ;
     RECT  28.361 17.04 28.46 17.496 ;
     RECT  27.929 25.584 28.465 27.96 ;
     RECT  28.285 28.992 28.465 29.016 ;
     RECT  28.069 30.384 28.465 30.84 ;
     RECT  27.313 11.76 28.501 11.832 ;
     RECT  28.177 13.056 28.501 13.08 ;
     RECT  26.957 38.688 28.501 38.712 ;
     RECT  28.46 15.216 28.609 17.496 ;
     RECT  28.393 22.464 28.933 22.728 ;
     RECT  27.889 33.312 28.969 35.064 ;
     RECT  28.781 43.056 29.041 43.08 ;
     RECT  28.451 0.048 29.123 0.504 ;
     RECT  28.969 33.072 29.132 35.064 ;
     RECT  27.025 36.48 29.132 36.552 ;
     RECT  29.041 42.192 29.219 43.08 ;
     RECT  28.609 14.832 29.269 17.496 ;
     RECT  28.289 4.896 29.408 5.112 ;
     RECT  28.321 6.096 29.408 6.12 ;
     RECT  28.177 7.632 29.408 9 ;
     RECT  27.781 10.176 29.408 10.632 ;
     RECT  28.501 11.76 29.408 13.08 ;
     RECT  29.269 14.208 29.408 17.496 ;
     RECT  28.253 18.72 29.408 18.744 ;
     RECT  28.573 19.872 29.408 19.896 ;
     RECT  28.289 20.88 29.408 20.904 ;
     RECT  28.933 22.464 29.408 22.776 ;
     RECT  27.929 24.144 29.408 24.168 ;
     RECT  28.465 25.584 29.408 30.84 ;
     RECT  29.132 33.072 29.408 36.552 ;
     RECT  28.501 38.688 29.408 38.76 ;
     RECT  28.451 41.04 29.408 41.052 ;
     RECT  29.408 2.148 29.512 41.052 ;
     RECT  29.512 2.418 29.704 41.052 ;
     RECT  29.219 43.056 29.801 43.08 ;
     RECT  29.704 8.976 29.837 9.384 ;
     RECT  29.704 10.752 29.881 20.568 ;
     RECT  29.881 10.752 30.025 18.696 ;
     RECT  29.123 0.096 30.035 0.504 ;
     RECT  30.035 0.096 30.053 0.12 ;
     RECT  29.977 41.568 30.061 41.592 ;
     RECT  29.704 36.528 30.089 37.656 ;
     RECT  29.704 5.424 30.197 7.464 ;
     RECT  30.089 36.672 30.275 37.656 ;
     RECT  30.197 5.424 30.413 6.072 ;
     RECT  29.704 23.712 30.556 30.744 ;
     RECT  29.881 19.872 30.557 20.568 ;
     RECT  30.275 36.768 30.629 37.656 ;
     RECT  30.413 6 30.773 6.072 ;
     RECT  30.025 10.752 30.809 17.4 ;
     RECT  30.773 6.048 30.845 6.072 ;
     RECT  29.837 9.216 30.845 9.384 ;
     RECT  30.556 24.096 30.845 30.744 ;
     RECT  30.401 42.144 30.881 42.168 ;
     RECT  29.704 21.744 30.913 22.584 ;
     RECT  29.704 4.272 31.021 4.296 ;
     RECT  29.704 38.688 31.093 38.76 ;
     RECT  30.845 24.096 31.133 30.648 ;
     RECT  31.133 24.096 31.139 26.232 ;
     RECT  29.704 31.92 31.169 35.448 ;
     RECT  30.845 9.36 31.205 9.384 ;
     RECT  31.021 4.272 31.285 4.968 ;
     RECT  31.237 40.992 31.321 41.016 ;
     RECT  31.169 33.024 31.331 35.448 ;
     RECT  30.197 7.344 31.333 7.464 ;
     RECT  31.285 3.744 31.372 4.968 ;
     RECT  31.139 25.632 31.385 26.136 ;
     RECT  31.333 6.432 31.42 7.464 ;
     RECT  31.331 33.024 31.421 34.392 ;
     RECT  31.331 35.424 31.421 35.448 ;
     RECT  31.42 7.2 31.44 7.464 ;
     RECT  30.025 18.672 31.457 18.696 ;
     RECT  30.557 20.016 31.561 20.568 ;
     RECT  31.139 24.096 31.565 24.6 ;
     RECT  31.093 38.208 31.605 38.76 ;
     RECT  31.453 31.68 31.645 31.896 ;
     RECT  31.561 19.968 31.669 20.568 ;
     RECT  30.913 21.744 31.669 22.776 ;
     RECT  31.605 38.208 31.817 39.336 ;
     RECT  30.809 10.752 31.877 15.48 ;
     RECT  30.809 16.512 31.877 17.4 ;
     RECT  31.645 31.68 31.889 31.8 ;
     RECT  31.421 33.888 31.889 34.392 ;
     RECT  31.133 27.6 31.909 30.648 ;
     RECT  31.877 10.752 31.921 17.4 ;
     RECT  31.909 27.6 31.955 31.608 ;
     RECT  31.669 19.968 31.957 22.776 ;
     RECT  31.921 10.752 31.961 18.552 ;
     RECT  31.58 42.192 32.005 42.216 ;
     RECT  31.372 3.984 32.033 4.968 ;
     RECT  31.955 27.888 32.041 31.608 ;
     RECT  31.957 19.968 32.101 23.064 ;
     RECT  32.033 3.984 32.105 4.776 ;
     RECT  31.385 25.632 32.149 25.752 ;
     RECT  30.629 36.768 32.197 36.792 ;
     RECT  32.041 27.888 32.221 30.312 ;
     RECT  32.221 27.888 32.243 30.216 ;
     RECT  32.041 31.344 32.249 31.608 ;
     RECT  32.005 42.144 32.285 42.216 ;
     RECT  32.243 27.888 32.483 29.4 ;
     RECT  31.44 7.2 32.641 7.224 ;
     RECT  32.101 19.68 32.641 23.064 ;
     RECT  31.961 17.04 32.677 18.552 ;
     RECT  32.641 19.584 32.677 23.064 ;
     RECT  32.197 36.48 32.681 36.792 ;
     RECT  32.105 3.984 32.773 4.008 ;
     RECT  31.561 2.784 32.785 2.808 ;
     RECT  32.773 3.936 32.785 4.008 ;
     RECT  31.961 10.752 32.789 15.192 ;
     RECT  31.565 24.096 32.825 24.12 ;
     RECT  32.785 2.784 32.869 4.008 ;
     RECT  32.389 8.832 32.929 8.856 ;
     RECT  32.789 10.752 32.929 12.36 ;
     RECT  32.869 2.784 32.933 2.904 ;
     RECT  32.641 6.768 32.965 7.224 ;
     RECT  32.929 8.832 32.965 12.36 ;
     RECT  32.681 36.624 33.113 36.792 ;
     RECT  33.073 5.376 33.145 5.4 ;
     RECT  32.789 13.536 33.181 15.192 ;
     RECT  32.437 43.056 33.253 43.08 ;
     RECT  33.145 5.088 33.257 5.4 ;
     RECT  33.26 24.048 33.347 24.072 ;
     RECT  32.677 17.04 33.469 23.064 ;
     RECT  33.469 16.272 33.545 23.064 ;
     RECT  32.965 6.768 33.596 12.36 ;
     RECT  31.817 38.688 33.596 39.336 ;
     RECT  33.596 38.688 33.613 40.008 ;
     RECT  31.237 0.096 33.637 0.12 ;
     RECT  32.149 25.344 33.649 25.752 ;
     RECT  33.637 0.096 33.653 0.168 ;
     RECT  33.596 5.904 33.683 12.36 ;
     RECT  33.613 38.208 33.683 40.008 ;
     RECT  32.249 31.584 33.685 31.608 ;
     RECT  33.653 0.144 33.721 0.168 ;
     RECT  33.721 0.144 33.725 0.552 ;
     RECT  32.483 27.888 33.779 29.304 ;
     RECT  33.649 25.248 33.901 25.752 ;
     RECT  33.779 27.888 33.901 27.96 ;
     RECT  32.933 2.88 34.001 2.904 ;
     RECT  32.869 3.936 34.001 4.008 ;
     RECT  33.545 22.224 34.045 23.064 ;
     RECT  33.901 25.248 34.117 27.96 ;
     RECT  33.253 42.768 34.153 43.08 ;
     RECT  33.779 29.28 34.477 29.304 ;
     RECT  33.685 30.672 34.477 31.608 ;
     RECT  33.725 0.432 34.499 0.552 ;
     RECT  33.113 36.624 34.621 36.648 ;
     RECT  34.045 22.224 34.693 23.88 ;
     RECT  34.001 2.88 34.808 4.008 ;
     RECT  34.621 5.136 34.808 5.16 ;
     RECT  33.683 6.288 34.808 12.36 ;
     RECT  33.181 13.536 34.808 15.24 ;
     RECT  33.545 16.272 34.808 21.24 ;
     RECT  34.693 22.224 34.808 23.928 ;
     RECT  34.117 25.104 34.808 27.96 ;
     RECT  34.477 29.28 34.808 31.608 ;
     RECT  31.889 34.368 34.808 34.392 ;
     RECT  34.621 36.624 34.808 37.08 ;
     RECT  33.683 38.208 34.808 39.864 ;
     RECT  34.001 40.992 34.808 41.016 ;
     RECT  34.499 0.432 34.883 0.504 ;
     RECT  34.153 42.192 34.883 43.08 ;
     RECT  34.808 2.148 34.912 41.052 ;
     RECT  34.912 2.16 35.104 40.782 ;
     RECT  35.104 34.128 35.219 34.392 ;
     RECT  35.104 3.888 35.267 31.656 ;
     RECT  34.883 42.192 35.315 42.216 ;
     RECT  35.267 22.752 35.381 31.656 ;
     RECT  35.267 3.888 35.569 21.672 ;
     RECT  35.569 3.888 35.669 12.312 ;
     RECT  35.104 2.16 35.699 2.904 ;
     RECT  35.669 3.888 35.705 10.392 ;
     RECT  35.699 2.256 35.74 2.28 ;
     RECT  35.705 5.04 35.741 10.392 ;
     RECT  35.569 13.872 35.777 21.672 ;
     RECT  35.381 23.04 35.777 31.656 ;
     RECT  35.777 23.04 35.813 26.856 ;
     RECT  35.777 19.248 35.857 21.672 ;
     RECT  35.104 35.856 35.921 36.84 ;
     RECT  35.921 35.856 35.957 36.552 ;
     RECT  34.883 0.432 35.989 0.456 ;
     RECT  35.957 36.432 35.993 36.552 ;
     RECT  35.857 19.248 36.029 21.144 ;
     RECT  35.777 13.872 36.065 17.928 ;
     RECT  36.029 19.248 36.065 20.136 ;
     RECT  35.989 0.096 36.083 0.456 ;
     RECT  35.741 7.248 36.245 10.392 ;
     RECT  36.083 0.432 36.277 0.456 ;
     RECT  36.037 40.992 36.317 41.016 ;
     RECT  35.705 3.888 36.421 3.96 ;
     RECT  36.277 0.432 36.428 0.504 ;
     RECT  35.777 28.464 36.469 31.656 ;
     RECT  36.428 0.432 36.515 0.552 ;
     RECT  36.457 43.056 36.541 43.08 ;
     RECT  36.065 19.248 36.569 19.272 ;
     RECT  36.029 21.12 36.677 21.144 ;
     RECT  35.741 5.04 36.853 5.928 ;
     RECT  36.245 7.248 36.853 10.248 ;
     RECT  35.993 36.528 36.961 36.552 ;
     RECT  36.853 5.04 37.001 10.248 ;
     RECT  36.065 13.872 37.001 15.96 ;
     RECT  35.813 23.088 37.001 26.856 ;
     RECT  37.001 25.296 37.033 26.856 ;
     RECT  36.421 3.408 37.037 3.96 ;
     RECT  36.469 28.464 37.045 31.896 ;
     RECT  37.033 25.296 37.069 27.048 ;
     RECT  37.045 28.416 37.069 31.896 ;
     RECT  35.104 33.072 37.069 33.096 ;
     RECT  36.065 17.088 37.073 17.928 ;
     RECT  37.069 28.416 37.073 33.096 ;
     RECT  37.069 25.296 37.091 27.24 ;
     RECT  35.104 38.688 37.091 39.336 ;
     RECT  37.001 5.04 37.109 9.912 ;
     RECT  37.109 5.04 37.181 9.384 ;
     RECT  37.091 25.728 37.289 27.24 ;
     RECT  35.669 11.952 37.357 12.312 ;
     RECT  37.001 13.872 37.357 14.136 ;
     RECT  36.853 41.568 37.369 41.592 ;
     RECT  37.289 25.728 37.433 26.808 ;
     RECT  37.181 5.04 37.436 8.04 ;
     RECT  37.357 11.952 37.465 14.136 ;
     RECT  37.001 23.088 37.505 23.88 ;
     RECT  37.436 4.992 37.523 8.04 ;
     RECT  37.073 28.416 37.577 32.76 ;
     RECT  37.037 3.408 37.649 3.912 ;
     RECT  37.523 5.04 37.685 8.04 ;
     RECT  37.685 5.328 37.721 8.04 ;
     RECT  36.515 0.432 37.789 0.504 ;
     RECT  37.001 15.168 37.789 15.96 ;
     RECT  37.073 17.088 37.789 17.496 ;
     RECT  37.897 21.072 38.005 21.096 ;
     RECT  37.637 43.056 38.005 43.08 ;
     RECT  37.789 0.432 38.053 0.552 ;
     RECT  38.005 21.024 38.077 21.096 ;
     RECT  37.649 3.84 38.101 3.912 ;
     RECT  37.577 28.752 38.147 32.76 ;
     RECT  37.721 6.144 38.149 8.04 ;
     RECT  37.181 9.072 38.149 9.384 ;
     RECT  37.789 15.168 38.149 17.496 ;
     RECT  37.789 19.92 38.149 19.944 ;
     RECT  38.077 21.024 38.149 21.144 ;
     RECT  38.053 0.096 38.153 0.552 ;
     RECT  38.101 3.84 38.188 3.96 ;
     RECT  38.149 6.144 38.189 9.384 ;
     RECT  38.189 6.24 38.195 9.384 ;
     RECT  38.188 3.84 38.225 3.912 ;
     RECT  38.195 8.688 38.236 9.384 ;
     RECT  38.236 9.072 38.257 9.384 ;
     RECT  38.195 6.24 38.261 7.368 ;
     RECT  38.147 30.288 38.261 32.76 ;
     RECT  37.465 11.424 38.293 14.136 ;
     RECT  38.149 15.168 38.293 18.456 ;
     RECT  36.961 36.48 38.297 36.552 ;
     RECT  38.293 11.424 38.38 18.456 ;
     RECT  38.153 0.528 38.531 0.552 ;
     RECT  38.147 28.752 38.617 29.304 ;
     RECT  38.257 9.072 38.653 9.672 ;
     RECT  38.653 9.072 38.78 9.816 ;
     RECT  38.38 11.424 38.78 14.136 ;
     RECT  38.149 19.92 38.801 21.144 ;
     RECT  38.801 20.544 38.819 21.144 ;
     RECT  37.433 25.872 38.833 26.808 ;
     RECT  38.617 28.32 38.833 29.304 ;
     RECT  38.78 9.072 38.867 14.136 ;
     RECT  38.005 42.192 38.869 43.08 ;
     RECT  38.833 25.872 38.873 29.304 ;
     RECT  38.261 32.736 38.873 32.76 ;
     RECT  37.007 40.416 38.873 40.44 ;
     RECT  38.225 3.84 38.909 3.864 ;
     RECT  38.38 15.168 38.909 18.456 ;
     RECT  38.873 25.872 38.917 27.384 ;
     RECT  37.505 23.088 38.941 23.784 ;
     RECT  38.917 25.872 38.941 27.336 ;
     RECT  38.869 42.144 38.953 43.08 ;
     RECT  38.909 17.04 39.049 18.456 ;
     RECT  39.049 17.04 39.053 18.84 ;
     RECT  38.261 6.24 39.161 6.264 ;
     RECT  38.941 22.8 39.205 23.784 ;
     RECT  38.873 28.512 39.265 29.304 ;
     RECT  38.261 30.288 39.265 31.656 ;
     RECT  38.867 11.472 39.445 14.136 ;
     RECT  38.909 15.168 39.445 16.056 ;
     RECT  38.953 43.056 39.665 43.08 ;
     RECT  38.819 20.592 39.805 21.144 ;
     RECT  39.805 20.592 39.877 21.192 ;
     RECT  39.205 22.176 39.877 23.784 ;
     RECT  39.445 11.472 39.98 16.056 ;
     RECT  39.265 28.512 39.985 31.656 ;
     RECT  39.98 10.992 40.093 16.056 ;
     RECT  39.053 17.376 40.093 18.84 ;
     RECT  38.261 7.344 40.208 7.368 ;
     RECT  38.867 9.072 40.208 9.816 ;
     RECT  40.093 10.992 40.208 18.84 ;
     RECT  39.877 20.592 40.208 23.784 ;
     RECT  38.941 25.056 40.208 27.336 ;
     RECT  39.985 28.512 40.208 32.328 ;
     RECT  35.219 34.368 40.208 34.392 ;
     RECT  38.297 36.528 40.208 36.552 ;
     RECT  37.091 38.688 40.208 38.712 ;
     RECT  39.653 40.992 40.208 41.016 ;
     RECT  40.208 2.148 40.312 41.052 ;
     RECT  40.069 0.576 40.501 0.6 ;
     RECT  40.312 2.418 40.504 41.052 ;
     RECT  40.501 0.096 40.739 0.6 ;
     RECT  40.504 11.424 40.817 18.936 ;
     RECT  40.504 37.872 40.853 39.384 ;
     RECT  40.504 8.16 40.925 10.152 ;
     RECT  40.817 11.424 40.925 17.4 ;
     RECT  40.925 13.056 40.961 17.4 ;
     RECT  40.069 42.144 40.969 42.168 ;
     RECT  40.961 13.296 41.141 17.4 ;
     RECT  40.504 32.064 41.213 32.328 ;
     RECT  40.504 3.936 41.357 3.96 ;
     RECT  40.504 24.528 41.357 25.08 ;
     RECT  40.993 41.616 41.363 41.64 ;
     RECT  40.739 0.096 41.401 0.12 ;
     RECT  40.504 20.208 41.411 22.824 ;
     RECT  40.504 26.256 41.497 26.76 ;
     RECT  41.357 24.528 41.564 24.552 ;
     RECT  40.504 27.888 41.569 30.696 ;
     RECT  40.925 9.264 41.641 10.152 ;
     RECT  41.564 23.856 41.651 24.552 ;
     RECT  41.569 27.888 41.681 30.792 ;
     RECT  41.669 43.056 41.753 43.08 ;
     RECT  40.504 36.528 41.789 36.552 ;
     RECT  41.497 26.208 41.821 26.76 ;
     RECT  40.817 18.432 41.857 18.936 ;
     RECT  41.411 21.12 41.861 22.824 ;
     RECT  41.681 27.888 41.861 30.744 ;
     RECT  41.141 13.296 41.897 15 ;
     RECT  40.925 11.424 41.929 11.976 ;
     RECT  41.861 28.608 41.969 30.744 ;
     RECT  40.853 38.16 41.969 39.384 ;
     RECT  41.969 38.16 41.989 38.952 ;
     RECT  41.989 38.016 42.037 38.952 ;
     RECT  42.037 37.056 42.076 38.952 ;
     RECT  41.861 22.224 42.077 22.824 ;
     RECT  41.141 16.128 42.109 17.4 ;
     RECT  41.857 18.432 42.109 19.416 ;
     RECT  42.109 16.128 42.131 19.416 ;
     RECT  41.969 28.608 42.149 30.696 ;
     RECT  42.131 16.128 42.193 18.456 ;
     RECT  42.193 16.128 42.221 17.4 ;
     RECT  42.193 18.432 42.221 18.456 ;
     RECT  41.641 9.264 42.325 10.2 ;
     RECT  41.929 11.328 42.325 11.976 ;
     RECT  42.325 9.264 42.332 11.976 ;
     RECT  41.821 25.728 42.473 26.76 ;
     RECT  42.085 42.192 42.505 42.216 ;
     RECT  41.897 13.296 42.509 14.904 ;
     RECT  42.505 42.144 42.589 42.216 ;
     RECT  40.925 8.16 42.757 8.184 ;
     RECT  42.332 9.264 42.757 12.024 ;
     RECT  41.651 24.528 42.757 24.552 ;
     RECT  42.473 25.728 42.757 26.232 ;
     RECT  42.149 28.608 42.761 30.648 ;
     RECT  42.757 24.528 42.803 26.232 ;
     RECT  41.213 32.064 42.853 32.088 ;
     RECT  42.757 9.264 42.869 12.216 ;
     RECT  42.761 28.608 42.869 30.504 ;
     RECT  42.853 32.064 42.899 33.192 ;
     RECT  40.504 34.368 42.899 34.392 ;
     RECT  42.221 16.848 42.905 17.4 ;
     RECT  42.899 32.496 42.941 33.192 ;
     RECT  41.861 21.12 43.009 21.144 ;
     RECT  42.077 22.224 43.009 22.488 ;
     RECT  42.941 32.496 43.021 33.096 ;
     RECT  42.901 0.096 43.045 0.12 ;
     RECT  42.869 9.504 43.121 12.216 ;
     RECT  42.803 25.248 43.157 26.232 ;
     RECT  42.869 28.608 43.225 30.072 ;
     RECT  43.121 9.504 43.235 12.024 ;
     RECT  42.076 37.056 43.285 37.08 ;
     RECT  43.235 9.504 43.301 10.584 ;
     RECT  43.301 10.56 43.372 10.584 ;
     RECT  43.285 36.432 43.372 37.08 ;
     RECT  43.045 0.096 43.379 0.552 ;
     RECT  42.901 43.056 43.379 43.08 ;
     RECT  43.009 21.12 43.409 22.488 ;
     RECT  43.297 19.056 43.441 19.08 ;
     RECT  42.076 38.688 43.481 38.952 ;
     RECT  43.484 0.048 43.571 0.072 ;
     RECT  43.441 19.056 43.571 19.992 ;
     RECT  42.905 17.376 43.585 17.4 ;
     RECT  43.081 4.896 43.621 4.92 ;
     RECT  43.189 23.808 43.621 23.832 ;
     RECT  43.585 17.376 43.657 17.976 ;
     RECT  43.571 19.056 43.657 19.656 ;
     RECT  42.865 15.312 43.693 15.336 ;
     RECT  43.297 16.368 43.693 16.392 ;
     RECT  43.621 4.896 43.715 5.16 ;
     RECT  43.481 38.688 43.729 38.712 ;
     RECT  43.685 40.992 43.769 41.016 ;
     RECT  42.757 7.344 43.981 8.184 ;
     RECT  43.58 6.24 44.089 6.264 ;
     RECT  43.693 15.312 44.197 16.392 ;
     RECT  43.657 17.376 44.197 19.656 ;
     RECT  44.089 6.096 44.233 6.264 ;
     RECT  43.981 7.344 44.233 8.52 ;
     RECT  43.621 22.752 44.305 23.832 ;
     RECT  42.973 3.696 44.341 3.72 ;
     RECT  44.305 22.752 44.377 23.88 ;
     RECT  44.233 6.096 44.413 8.52 ;
     RECT  43.301 9.504 44.413 9.528 ;
     RECT  43.409 21.12 44.485 21.672 ;
     RECT  44.377 22.752 44.485 23.928 ;
     RECT  44.305 39.888 44.485 39.912 ;
     RECT  43.729 38.4 44.489 38.712 ;
     RECT  44.485 39.888 44.525 40.056 ;
     RECT  43.235 12 44.593 12.024 ;
     RECT  42.509 13.296 44.593 14.232 ;
     RECT  44.593 11.328 44.657 14.232 ;
     RECT  44.081 42.144 44.705 42.168 ;
     RECT  44.485 21.12 44.737 23.928 ;
     RECT  43.372 37.056 44.869 37.08 ;
     RECT  44.657 10.848 44.881 14.232 ;
     RECT  44.197 15.312 44.881 19.656 ;
     RECT  44.881 10.848 44.909 19.656 ;
     RECT  43.157 26.208 45.013 26.232 ;
     RECT  44.341 3.696 45.02 4.344 ;
     RECT  43.021 32.496 45.025 32.52 ;
     RECT  43.225 28.512 45.164 30.072 ;
     RECT  45.025 31.92 45.164 32.52 ;
     RECT  45.02 3.696 45.241 4.68 ;
     RECT  44.413 6.096 45.241 9.528 ;
     RECT  44.869 36.336 45.565 37.08 ;
     RECT  45.241 3.696 45.608 9.528 ;
     RECT  44.909 10.848 45.608 19.992 ;
     RECT  44.737 20.976 45.608 23.928 ;
     RECT  45.013 25.584 45.608 26.808 ;
     RECT  45.164 28.512 45.608 32.52 ;
     RECT  44.449 34.752 45.608 34.776 ;
     RECT  45.565 36.336 45.608 37.608 ;
     RECT  44.489 38.688 45.608 38.712 ;
     RECT  44.525 40.032 45.608 40.056 ;
     RECT  45.608 2.148 45.712 41.052 ;
     RECT  44.665 0.528 45.733 0.552 ;
     RECT  45.712 2.418 45.733 41.052 ;
     RECT  45.733 2.418 45.904 41.592 ;
     RECT  45.904 34.752 45.965 36.36 ;
     RECT  45.904 40.032 45.965 41.592 ;
     RECT  45.965 34.752 46.019 35.688 ;
     RECT  45.904 28.32 46.145 32.616 ;
     RECT  45.965 40.032 46.181 41.016 ;
     RECT  45.904 37.584 46.259 37.656 ;
     RECT  45.904 5.808 46.289 10.392 ;
     RECT  46.289 7.344 46.325 10.392 ;
     RECT  44.917 43.056 46.501 43.08 ;
     RECT  45.904 20.976 46.691 26.664 ;
     RECT  46.325 7.344 46.739 10.056 ;
     RECT  46.739 7.344 46.865 9.864 ;
     RECT  45.904 3.696 46.885 4.44 ;
     RECT  45.733 0.096 46.933 0.552 ;
     RECT  46.885 3.696 46.972 4.68 ;
     RECT  46.145 28.32 46.973 31.944 ;
     RECT  45.904 11.424 47.005 19.992 ;
     RECT  46.691 20.976 47.005 23.832 ;
     RECT  46.933 0.096 47.017 0.6 ;
     RECT  47.005 11.424 47.027 23.832 ;
     RECT  47.017 0.096 47.117 0.552 ;
     RECT  46.501 42.192 47.117 43.08 ;
     RECT  46.691 25.104 47.153 26.664 ;
     RECT  47.153 26.64 47.18 26.664 ;
     RECT  46.289 5.808 47.185 6.264 ;
     RECT  47.027 11.424 47.261 19.608 ;
     RECT  47.18 26.64 47.329 27.24 ;
     RECT  46.973 28.32 47.329 29.592 ;
     RECT  47.185 5.184 47.405 6.264 ;
     RECT  47.117 0.528 47.411 0.552 ;
     RECT  46.973 31.104 47.437 31.944 ;
     RECT  47.117 42.192 47.452 42.216 ;
     RECT  47.437 31.104 47.473 32.328 ;
     RECT  47.405 5.808 47.477 6.264 ;
     RECT  46.181 40.032 47.545 40.056 ;
     RECT  47.261 15.504 47.549 19.608 ;
     RECT  46.019 34.752 47.581 34.776 ;
     RECT  47.545 39.888 47.585 40.056 ;
     RECT  47.477 5.856 47.653 6.264 ;
     RECT  46.865 7.344 47.653 9.384 ;
     RECT  46.259 37.584 47.653 37.608 ;
     RECT  45.904 38.688 47.653 38.712 ;
     RECT  47.653 37.584 47.693 38.712 ;
     RECT  47.717 42.144 47.801 42.168 ;
     RECT  47.329 26.64 47.909 29.592 ;
     RECT  47.549 19.104 47.937 19.608 ;
     RECT  47.909 28.368 47.939 29.592 ;
     RECT  47.653 5.856 47.941 9.384 ;
     RECT  47.261 11.424 47.989 14.52 ;
     RECT  47.989 11.232 48.013 14.52 ;
     RECT  47.939 28.752 48.013 29.592 ;
     RECT  47.693 38.016 48.085 38.712 ;
     RECT  48.013 28.752 48.121 29.832 ;
     RECT  47.473 31.104 48.121 32.52 ;
     RECT  48.085 38.016 48.181 38.808 ;
     RECT  47.585 39.888 48.181 39.912 ;
     RECT  47.937 19.104 48.197 19.416 ;
     RECT  48.121 28.752 48.229 32.52 ;
     RECT  48.149 40.992 48.233 41.016 ;
     RECT  48.181 38.016 48.268 39.912 ;
     RECT  48.229 28.752 48.341 33 ;
     RECT  48.341 32.304 48.377 32.472 ;
     RECT  47.549 15.504 48.419 18.072 ;
     RECT  47.027 20.736 48.419 23.832 ;
     RECT  48.268 38.016 48.419 38.808 ;
     RECT  47.153 25.104 48.481 25.608 ;
     RECT  48.341 28.752 48.521 31.32 ;
     RECT  48.419 20.736 48.593 21.672 ;
     RECT  48.268 39.888 48.593 39.912 ;
     RECT  48.419 22.992 48.697 23.832 ;
     RECT  48.481 24.96 48.697 25.608 ;
     RECT  47.941 5.856 48.733 9.672 ;
     RECT  48.697 22.992 48.733 25.608 ;
     RECT  47.909 26.64 48.733 27.336 ;
     RECT  46.972 3.696 48.773 3.72 ;
     RECT  48.013 10.8 48.773 14.52 ;
     RECT  48.733 5.664 48.805 9.672 ;
     RECT  48.773 10.8 48.805 14.424 ;
     RECT  48.805 5.664 48.809 14.424 ;
     RECT  48.565 36.432 48.908 36.456 ;
     RECT  48.733 22.992 48.913 27.336 ;
     RECT  48.521 28.752 48.913 29.832 ;
     RECT  48.908 35.904 48.913 36.456 ;
     RECT  48.809 5.664 48.917 9.864 ;
     RECT  48.809 11.376 48.995 14.424 ;
     RECT  48.913 35.904 48.995 36.792 ;
     RECT  47.653 1.728 49.025 1.752 ;
     RECT  48.917 5.664 49.025 9.672 ;
     RECT  48.419 15.552 49.025 17.4 ;
     RECT  49.025 5.664 49.061 9.528 ;
     RECT  48.913 22.992 49.061 29.832 ;
     RECT  48.995 36.432 49.061 36.792 ;
     RECT  49.061 5.664 49.133 8.808 ;
     RECT  48.197 19.344 49.133 19.416 ;
     RECT  48.995 14.4 49.187 14.424 ;
     RECT  49.025 15.552 49.187 15.72 ;
     RECT  47.581 34.08 49.273 34.776 ;
     RECT  49.273 33.552 49.313 34.776 ;
     RECT  49.061 23.184 49.349 29.832 ;
     RECT  48.377 32.448 49.417 32.472 ;
     RECT  48.419 38.544 49.421 38.712 ;
     RECT  49.349 23.184 49.457 27.144 ;
     RECT  49.313 34.752 49.457 34.776 ;
     RECT  49.187 15.552 49.525 15.576 ;
     RECT  48.521 31.104 49.525 31.32 ;
     RECT  49.417 32.4 49.525 32.472 ;
     RECT  49.133 5.664 49.571 8.184 ;
     RECT  49.525 31.104 49.571 32.472 ;
     RECT  48.995 11.376 49.609 13.032 ;
     RECT  49.457 23.184 49.637 25.368 ;
     RECT  49.025 16.992 49.724 17.4 ;
     RECT  49.165 18.384 49.724 18.84 ;
     RECT  48.949 43.056 49.733 43.08 ;
     RECT  49.453 0.528 49.777 0.552 ;
     RECT  49.724 16.992 49.811 18.84 ;
     RECT  49.765 20.304 49.849 20.328 ;
     RECT  48.593 21.648 49.849 21.672 ;
     RECT  49.777 0.48 49.885 0.552 ;
     RECT  49.349 28.416 50.065 29.832 ;
     RECT  49.733 42.144 50.213 43.08 ;
     RECT  49.885 0.432 50.243 0.552 ;
     RECT  49.609 11.424 50.245 13.032 ;
     RECT  50.213 42.144 50.249 42.168 ;
     RECT  50.245 4.416 50.281 4.44 ;
     RECT  50.065 28.416 50.281 30.024 ;
     RECT  50.281 28.416 50.317 30.12 ;
     RECT  49.571 31.104 50.317 32.424 ;
     RECT  49.571 5.856 50.389 8.184 ;
     RECT  50.389 5.856 50.425 8.712 ;
     RECT  50.137 10.32 50.425 10.344 ;
     RECT  49.811 16.992 50.485 17.496 ;
     RECT  50.281 4.32 50.497 4.44 ;
     RECT  49.381 40.992 50.569 41.016 ;
     RECT  50.569 40.416 50.605 41.016 ;
     RECT  50.243 0.432 50.627 0.504 ;
     RECT  49.637 23.328 50.677 25.368 ;
     RECT  50.317 28.416 50.677 32.424 ;
     RECT  49.313 33.552 50.677 33.576 ;
     RECT  50.605 40.416 50.677 41.64 ;
     RECT  50.497 4.32 50.713 4.488 ;
     RECT  50.425 5.856 50.713 10.344 ;
     RECT  50.605 14.4 50.773 14.424 ;
     RECT  49.525 15.408 50.773 15.576 ;
     RECT  50.713 4.224 50.785 10.344 ;
     RECT  50.677 23.28 50.785 25.368 ;
     RECT  49.457 26.496 50.785 27.144 ;
     RECT  50.785 23.28 50.821 27.144 ;
     RECT  49.061 36.768 50.869 36.792 ;
     RECT  50.485 16.608 50.893 17.496 ;
     RECT  49.849 20.304 50.893 21.672 ;
     RECT  50.773 14.4 50.965 15.576 ;
     RECT  50.893 16.56 50.965 17.496 ;
     RECT  50.785 3.648 51.001 10.344 ;
     RECT  50.245 11.424 51.001 13.128 ;
     RECT  51.001 3.648 51.008 13.128 ;
     RECT  50.965 14.4 51.008 17.496 ;
     RECT  49.811 18.816 51.008 18.84 ;
     RECT  50.893 19.872 51.008 21.672 ;
     RECT  50.821 22.8 51.008 27.144 ;
     RECT  50.677 28.416 51.008 33.576 ;
     RECT  50.869 35.28 51.008 36.792 ;
     RECT  49.421 38.544 51.008 38.568 ;
     RECT  50.677 39.744 51.008 41.64 ;
     RECT  51.008 2.148 51.011 41.64 ;
     RECT  51.011 2.148 51.112 41.052 ;
     RECT  51.112 2.418 51.304 41.016 ;
     RECT  50.627 0.432 51.397 0.456 ;
     RECT  51.304 15.552 51.401 19.08 ;
     RECT  51.304 22.752 51.401 26.808 ;
     RECT  51.397 42.144 51.481 42.168 ;
     RECT  51.401 24.864 51.509 26.808 ;
     RECT  51.304 12.48 51.581 12.504 ;
     RECT  51.401 15.552 51.581 18.84 ;
     RECT  51.397 0.096 51.793 0.456 ;
     RECT  51.304 7.056 51.797 7.08 ;
     RECT  51.304 27.792 51.797 32.04 ;
     RECT  51.304 8.16 51.82 8.712 ;
     RECT  51.793 0.096 51.827 0.504 ;
     RECT  51.82 8.496 51.869 8.712 ;
     RECT  51.304 10.608 51.869 11.496 ;
     RECT  51.827 0.48 51.901 0.504 ;
     RECT  51.401 22.752 51.923 23.832 ;
     RECT  51.304 4.464 52.252 5.928 ;
     RECT  51.304 13.584 52.265 14.424 ;
     RECT  51.581 15.552 52.265 18.696 ;
     RECT  51.304 39.744 52.265 39.768 ;
     RECT  52.265 13.584 52.297 14.28 ;
     RECT  51.304 40.944 52.301 41.016 ;
     RECT  51.869 10.608 52.337 11.352 ;
     RECT  52.252 5.856 52.369 5.928 ;
     RECT  51.797 27.792 52.373 31.176 ;
     RECT  52.369 5.856 52.405 6.024 ;
     RECT  52.252 4.464 52.445 4.488 ;
     RECT  51.304 20.304 52.477 21.672 ;
     RECT  51.923 22.752 52.477 22.824 ;
     RECT  51.509 24.864 52.477 26.664 ;
     RECT  51.923 23.808 52.553 23.832 ;
     RECT  52.297 13.104 52.589 14.28 ;
     RECT  52.405 5.856 52.625 6.888 ;
     RECT  51.901 0.48 52.643 0.552 ;
     RECT  52.549 42.144 52.643 42.168 ;
     RECT  52.477 24.864 52.693 26.808 ;
     RECT  52.589 13.152 52.697 14.28 ;
     RECT  52.265 16.512 52.729 18.696 ;
     RECT  52.693 24.864 52.739 27.384 ;
     RECT  52.625 6.048 52.769 6.888 ;
     RECT  51.304 33.024 52.769 33.048 ;
     RECT  52.729 16.512 52.801 18.936 ;
     RECT  52.477 20.304 52.801 22.824 ;
     RECT  51.304 35.28 52.805 35.304 ;
     RECT  52.765 38.784 52.849 38.808 ;
     RECT  52.739 24.864 52.981 25.08 ;
     RECT  52.373 28.464 53.025 31.176 ;
     RECT  51.869 8.496 53.029 8.664 ;
     RECT  51.304 37.632 53.057 37.656 ;
     RECT  52.301 40.992 53.129 41.016 ;
     RECT  52.801 16.512 53.164 22.824 ;
     RECT  53.029 7.968 53.237 8.664 ;
     RECT  52.337 10.608 53.237 10.968 ;
     RECT  53.237 7.968 53.309 7.992 ;
     RECT  52.739 26.496 53.309 27.384 ;
     RECT  53.025 28.464 53.309 32.328 ;
     RECT  52.697 13.584 53.417 14.28 ;
     RECT  53.309 28.992 53.417 32.328 ;
     RECT  52.643 0.528 53.459 0.552 ;
     RECT  52.981 23.904 53.459 25.08 ;
     RECT  53.309 26.928 53.489 27.384 ;
     RECT  53.417 30.816 53.489 32.328 ;
     RECT  53.417 13.92 53.557 14.28 ;
     RECT  53.459 23.904 53.633 24.168 ;
     RECT  53.489 31.92 53.669 32.328 ;
     RECT  53.164 16.512 53.773 19.368 ;
     RECT  52.981 35.856 53.809 35.88 ;
     RECT  53.053 42.192 53.843 42.216 ;
     RECT  53.164 20.352 53.845 22.824 ;
     RECT  53.809 34.128 53.989 34.152 ;
     RECT  53.809 35.856 53.989 35.928 ;
     RECT  53.989 34.128 54.035 35.928 ;
     RECT  53.773 16.224 54.065 19.368 ;
     RECT  53.917 25.776 54.131 25.8 ;
     RECT  53.237 10.944 54.173 10.968 ;
     RECT  54.065 16.224 54.205 18.792 ;
     RECT  53.989 32.352 54.205 33.096 ;
     RECT  53.845 20.352 54.317 23.4 ;
     RECT  54.229 41.568 54.353 41.592 ;
     RECT  54.317 20.352 54.421 22.056 ;
     RECT  53.489 26.928 54.421 26.952 ;
     RECT  53.417 28.992 54.421 29.784 ;
     RECT  53.489 30.816 54.421 30.84 ;
     RECT  54.205 15.84 54.467 18.792 ;
     RECT  54.421 26.208 54.505 26.952 ;
     RECT  54.421 19.776 54.508 22.056 ;
     RECT  53.593 9.504 54.62 9.528 ;
     RECT  54.421 28.992 54.637 30.84 ;
     RECT  54.205 32.352 54.637 33.432 ;
     RECT  53.557 39.888 54.661 39.912 ;
     RECT  54.62 9.504 54.707 10.296 ;
     RECT  54.661 39.504 54.707 39.912 ;
     RECT  54.565 12.24 54.709 12.552 ;
     RECT  54.505 26.928 54.709 26.952 ;
     RECT  54.709 26.928 54.745 27.336 ;
     RECT  54.637 28.992 54.748 33.432 ;
     RECT  53.557 13.92 54.749 14.664 ;
     RECT  54.709 11.328 54.796 12.552 ;
     RECT  52.769 6.048 54.853 6.072 ;
     RECT  54.707 9.504 54.853 9.528 ;
     RECT  54.853 9.36 54.893 9.528 ;
     RECT  54.853 6.048 54.937 6.888 ;
     RECT  54.035 34.464 54.961 35.928 ;
     RECT  54.085 42.96 54.997 43.08 ;
     RECT  54.961 34.464 55.069 36.264 ;
     RECT  54.457 37.584 55.069 37.608 ;
     RECT  54.997 42.144 55.081 43.08 ;
     RECT  54.467 15.84 55.093 18.264 ;
     RECT  54.748 28.992 55.105 29.112 ;
     RECT  55.105 28.944 55.109 29.112 ;
     RECT  54.745 26.928 55.285 27.912 ;
     RECT  55.109 28.944 55.285 29.064 ;
     RECT  54.796 12.048 55.321 12.552 ;
     RECT  54.749 13.92 55.321 14.472 ;
     RECT  54.613 0.096 55.393 0.12 ;
     RECT  54.748 30.096 55.393 33.432 ;
     RECT  55.069 34.464 55.393 37.608 ;
     RECT  54.508 20.304 55.465 22.056 ;
     RECT  54.317 23.136 55.465 23.4 ;
     RECT  55.093 15.456 55.501 18.264 ;
     RECT  54.893 9.36 55.609 9.384 ;
     RECT  55.429 40.992 55.781 41.016 ;
     RECT  55.465 20.304 55.789 23.4 ;
     RECT  55.081 43.056 56.077 43.08 ;
     RECT  55.609 9.12 56.108 9.384 ;
     RECT  55.321 10.896 56.108 10.92 ;
     RECT  55.501 15.456 56.293 18.504 ;
     RECT  54.937 6.048 56.408 6.648 ;
     RECT  56.108 9.12 56.408 10.92 ;
     RECT  55.321 12.048 56.408 14.472 ;
     RECT  56.293 15.456 56.408 18.744 ;
     RECT  55.789 20.16 56.408 23.4 ;
     RECT  55.105 24.624 56.408 24.648 ;
     RECT  55.285 26.928 56.408 29.064 ;
     RECT  55.393 30.096 56.408 37.608 ;
     RECT  54.707 39.504 56.408 39.528 ;
     RECT  55.781 40.896 56.408 41.016 ;
     RECT  56.408 2.148 56.512 41.052 ;
     RECT  56.077 42.192 56.545 43.08 ;
     RECT  55.393 0.096 56.675 0.552 ;
     RECT  56.545 41.856 56.675 43.08 ;
     RECT  56.512 2.418 56.704 40.782 ;
     RECT  56.675 0.096 56.828 0.312 ;
     RECT  56.704 14.736 56.963 39.72 ;
     RECT  56.704 5.664 56.981 7.944 ;
     RECT  56.963 15.84 57.011 39.72 ;
     RECT  56.675 42.144 57.061 43.08 ;
     RECT  56.981 5.664 57.197 7.656 ;
     RECT  56.828 0.048 57.299 0.312 ;
     RECT  57.011 23.904 57.299 39.72 ;
     RECT  57.197 5.664 57.413 6.12 ;
     RECT  56.963 14.736 57.449 14.808 ;
     RECT  57.011 15.84 57.485 22.776 ;
     RECT  57.485 16.128 57.587 22.776 ;
     RECT  57.299 23.904 57.593 37.608 ;
     RECT  57.593 23.904 57.629 31.752 ;
     RECT  57.587 20.16 57.648 22.776 ;
     RECT  57.449 14.784 57.701 14.808 ;
     RECT  57.587 16.128 57.809 18.792 ;
     RECT  56.704 9.36 57.845 13.704 ;
     RECT  57.797 41.568 57.881 41.592 ;
     RECT  57.299 0.096 57.917 0.312 ;
     RECT  57.809 17.136 57.971 18.792 ;
     RECT  57.197 7.104 58.093 7.656 ;
     RECT  57.648 20.544 58.093 22.776 ;
     RECT  57.629 23.904 58.093 26.808 ;
     RECT  58.093 7.104 58.133 7.896 ;
     RECT  57.593 32.976 58.133 37.608 ;
     RECT  57.413 5.664 58.345 5.832 ;
     RECT  57.917 0.096 58.357 0.264 ;
     RECT  58.345 5.088 58.381 5.832 ;
     RECT  58.093 20.544 58.385 26.808 ;
     RECT  58.357 0.048 58.403 0.264 ;
     RECT  58.133 7.2 58.421 7.896 ;
     RECT  57.061 42.96 58.489 43.08 ;
     RECT  58.385 21.168 58.493 26.808 ;
     RECT  57.629 28.176 58.529 31.752 ;
     RECT  58.381 4.704 58.673 5.832 ;
     RECT  58.489 1.728 58.691 1.752 ;
     RECT  58.489 42.192 58.691 43.08 ;
     RECT  58.493 21.168 58.709 23.064 ;
     RECT  58.261 40.752 58.709 40.776 ;
     RECT  57.845 10.032 58.745 13.704 ;
     RECT  58.421 7.776 58.777 7.896 ;
     RECT  58.745 10.704 58.885 13.704 ;
     RECT  58.885 10.704 58.925 13.992 ;
     RECT  57.971 17.136 58.961 17.64 ;
     RECT  58.493 24.864 58.993 26.808 ;
     RECT  58.529 28.176 58.993 31.56 ;
     RECT  57.809 16.128 59.101 16.152 ;
     RECT  58.993 24.864 59.249 31.56 ;
     RECT  58.673 5.088 59.372 5.832 ;
     RECT  58.403 0.048 59.389 0.216 ;
     RECT  58.777 7.776 59.413 7.992 ;
     RECT  59.101 15.216 59.429 16.152 ;
     RECT  59.372 5.088 59.459 6.744 ;
     RECT  59.249 24.864 59.459 26.472 ;
     RECT  57.971 18.768 59.509 18.792 ;
     RECT  58.925 10.704 59.555 12.984 ;
     RECT  59.249 27.552 59.564 31.56 ;
     RECT  58.925 13.968 59.569 13.992 ;
     RECT  59.429 15.84 59.605 16.152 ;
     RECT  58.961 17.136 59.605 17.544 ;
     RECT  59.564 27.552 59.605 31.896 ;
     RECT  58.133 32.976 59.605 37.32 ;
     RECT  59.461 41.568 59.609 41.592 ;
     RECT  59.605 27.552 59.651 37.32 ;
     RECT  57.299 38.688 59.701 38.712 ;
     RECT  59.651 32.832 59.747 37.32 ;
     RECT  59.509 18.576 59.749 18.792 ;
     RECT  59.708 19.968 59.749 19.992 ;
     RECT  59.413 7.776 59.785 8.04 ;
     RECT  59.425 9.072 59.785 9.096 ;
     RECT  59.555 10.704 59.785 11.688 ;
     RECT  58.709 21.168 59.785 22.056 ;
     RECT  58.709 23.04 59.785 23.064 ;
     RECT  59.389 0.048 59.813 0.6 ;
     RECT  59.785 7.776 59.821 9.096 ;
     RECT  59.749 40.464 59.843 40.488 ;
     RECT  59.821 7.344 59.845 9.096 ;
     RECT  59.749 18.576 59.857 19.992 ;
     RECT  59.785 21.168 59.857 23.064 ;
     RECT  59.555 12.816 59.891 12.984 ;
     RECT  59.845 7.344 59.893 9.192 ;
     RECT  59.785 10.416 59.893 11.688 ;
     RECT  59.813 0.048 59.897 1.176 ;
     RECT  59.459 5.088 59.897 5.976 ;
     RECT  59.857 18.576 60.109 23.064 ;
     RECT  60.109 18.576 60.217 23.112 ;
     RECT  58.691 42.96 60.217 43.08 ;
     RECT  60.217 18.576 60.301 23.352 ;
     RECT  59.747 32.832 60.329 37.032 ;
     RECT  59.701 38.4 60.361 38.712 ;
     RECT  59.605 15.84 60.397 17.544 ;
     RECT  60.301 18.576 60.397 23.112 ;
     RECT  59.651 27.552 60.437 31.416 ;
     RECT  60.329 34.464 60.467 37.032 ;
     RECT  59.569 13.968 60.469 14.76 ;
     RECT  60.397 15.84 60.469 23.112 ;
     RECT  59.897 0.048 60.611 0.216 ;
     RECT  60.611 0.048 60.617 0.168 ;
     RECT  60.437 28.32 60.62 31.416 ;
     RECT  60.329 32.832 60.62 33.48 ;
     RECT  59.459 24.864 60.685 26.136 ;
     RECT  60.467 36.912 60.689 37.032 ;
     RECT  60.361 38.4 60.707 39.624 ;
     RECT  60.62 28.32 60.725 33.48 ;
     RECT  59.893 7.344 60.865 11.688 ;
     RECT  60.865 7.152 60.937 11.688 ;
     RECT  60.217 42.192 61.045 43.08 ;
     RECT  61.045 42.144 61.129 43.08 ;
     RECT  60.685 24.864 61.189 27.096 ;
     RECT  59.897 5.136 61.225 5.976 ;
     RECT  60.937 7.008 61.225 11.688 ;
     RECT  60.469 13.968 61.34 23.112 ;
     RECT  60.707 39.6 61.477 39.624 ;
     RECT  61.225 5.136 61.513 11.688 ;
     RECT  59.891 12.816 61.513 12.888 ;
     RECT  61.34 13.968 61.621 23.352 ;
     RECT  61.189 24.528 61.649 27.096 ;
     RECT  60.725 28.32 61.649 30.36 ;
     RECT  60.245 1.728 61.808 1.752 ;
     RECT  61.513 5.136 61.808 12.888 ;
     RECT  61.621 13.92 61.808 23.352 ;
     RECT  61.649 24.528 61.808 30.36 ;
     RECT  60.725 31.392 61.808 33.48 ;
     RECT  60.467 34.464 61.808 35.448 ;
     RECT  60.689 36.912 61.808 36.936 ;
     RECT  60.707 38.4 61.808 38.424 ;
     RECT  61.477 39.6 61.808 40.584 ;
     RECT  61.808 1.728 61.907 41.052 ;
     RECT  61.907 2.148 61.912 41.052 ;
     RECT  61.912 2.418 62.104 40.782 ;
     RECT  62.104 5.76 62.165 23.352 ;
     RECT  60.617 0.048 62.243 0.072 ;
     RECT  62.104 24.528 62.291 30.12 ;
     RECT  62.291 24.528 62.309 28.968 ;
     RECT  62.252 0.096 62.339 0.552 ;
     RECT  62.165 9.888 62.381 23.352 ;
     RECT  62.381 13.92 62.453 23.352 ;
     RECT  62.453 13.92 62.525 15.672 ;
     RECT  62.309 24.528 62.741 27.192 ;
     RECT  62.104 31.392 62.771 35.448 ;
     RECT  61.129 42.192 62.773 43.08 ;
     RECT  62.309 28.416 62.777 28.968 ;
     RECT  62.165 5.76 62.849 8.376 ;
     RECT  62.771 31.872 62.885 35.448 ;
     RECT  62.849 5.808 62.908 8.376 ;
     RECT  62.908 5.808 62.921 8.28 ;
     RECT  62.773 42.144 62.957 43.08 ;
     RECT  62.921 6.192 63.065 8.28 ;
     RECT  62.381 9.888 63.101 12.84 ;
     RECT  63.065 6.192 63.173 8.136 ;
     RECT  62.885 34.128 63.196 35.448 ;
     RECT  62.104 38.4 63.205 39.096 ;
     RECT  62.453 16.656 63.253 23.352 ;
     RECT  62.741 24.528 63.253 24.984 ;
     RECT  62.957 42.96 63.281 43.08 ;
     RECT  63.173 8.112 63.317 8.136 ;
     RECT  63.253 16.656 63.34 24.984 ;
     RECT  63.196 34.656 63.425 35.448 ;
     RECT  63.34 16.656 63.641 23.4 ;
     RECT  63.173 6.192 63.683 6.888 ;
     RECT  63.101 9.888 63.709 10.296 ;
     RECT  63.34 24.672 63.709 24.984 ;
     RECT  62.741 26.4 63.709 27.192 ;
     RECT  63.493 41.568 63.713 41.592 ;
     RECT  63.101 12.528 63.745 12.84 ;
     RECT  62.525 14.112 63.745 15.672 ;
     RECT  63.709 9.648 63.749 10.296 ;
     RECT  63.205 38.208 63.781 39.096 ;
     RECT  63.601 40.464 63.781 40.488 ;
     RECT  63.745 12.528 63.809 15.672 ;
     RECT  63.641 16.656 63.809 20.04 ;
     RECT  62.885 31.872 63.821 33.048 ;
     RECT  63.781 38.208 63.827 40.488 ;
     RECT  62.104 36.48 63.853 36.936 ;
     RECT  63.709 24.672 63.889 25.272 ;
     RECT  63.709 26.4 63.889 27.336 ;
     RECT  62.104 3.936 63.916 3.96 ;
     RECT  63.683 6.864 64.001 6.888 ;
     RECT  63.821 31.92 64.001 33.048 ;
     RECT  63.853 36.48 64.001 37.08 ;
     RECT  64.001 32.448 64.033 33.048 ;
     RECT  63.101 11.472 64.069 11.544 ;
     RECT  63.809 12.528 64.069 20.04 ;
     RECT  64.033 32.448 64.145 33.096 ;
     RECT  63.827 38.208 64.145 39.912 ;
     RECT  64.069 11.472 64.253 20.04 ;
     RECT  63.889 24.672 64.289 27.336 ;
     RECT  63.281 43.056 64.309 43.08 ;
     RECT  64.001 37.056 64.433 37.08 ;
     RECT  64.253 12.096 64.753 20.04 ;
     RECT  63.641 21.12 64.753 23.4 ;
     RECT  63.877 40.992 64.765 41.016 ;
     RECT  64.753 12.096 64.789 23.4 ;
     RECT  64.289 24.912 64.789 27.336 ;
     RECT  64.789 12.096 64.865 23.928 ;
     RECT  64.789 24.912 64.883 27.912 ;
     RECT  64.865 12.096 64.901 19.896 ;
     RECT  64.865 20.976 65.045 21.96 ;
     RECT  62.339 0.096 65.113 0.504 ;
     RECT  64.309 42.96 65.113 43.08 ;
     RECT  63.749 9.648 65.149 9.672 ;
     RECT  64.145 38.208 65.257 38.424 ;
     RECT  64.145 32.448 65.315 32.472 ;
     RECT  64.901 12.096 65.329 14.376 ;
     RECT  65.269 31.296 65.365 31.32 ;
     RECT  64.901 15.744 65.477 19.896 ;
     RECT  65.113 0.096 65.513 0.552 ;
     RECT  65.516 7.344 65.557 7.368 ;
     RECT  65.329 12 65.585 14.376 ;
     RECT  65.113 42.144 65.593 43.08 ;
     RECT  65.557 7.344 65.603 7.992 ;
     RECT  65.149 9.12 65.621 9.672 ;
     RECT  65.585 12.528 65.693 14.376 ;
     RECT  65.593 42.192 65.939 43.08 ;
     RECT  64.865 22.944 66.049 23.928 ;
     RECT  63.529 29.088 66.085 29.112 ;
     RECT  62.291 30.096 66.085 30.12 ;
     RECT  65.045 20.976 66.133 21.864 ;
     RECT  66.049 22.944 66.133 24.456 ;
     RECT  65.621 9.12 66.161 9.144 ;
     RECT  66.085 5.52 66.265 5.544 ;
     RECT  65.513 0.528 66.371 0.552 ;
     RECT  65.477 15.744 66.421 19.848 ;
     RECT  63.425 34.656 66.445 34.776 ;
     RECT  65.365 31.296 66.481 31.368 ;
     RECT  66.133 20.976 66.517 24.456 ;
     RECT  66.481 31.296 66.553 31.848 ;
     RECT  65.603 7.968 66.661 7.992 ;
     RECT  66.517 20.976 66.697 24.648 ;
     RECT  64.883 25.824 66.697 27.912 ;
     RECT  66.445 34.368 66.709 34.776 ;
     RECT  66.265 5.52 66.733 5.736 ;
     RECT  65.939 42.96 66.796 43.08 ;
     RECT  66.709 35.952 66.877 35.976 ;
     RECT  66.085 29.04 66.949 30.12 ;
     RECT  66.553 31.296 66.949 31.896 ;
     RECT  66.908 0.048 66.995 0.12 ;
     RECT  66.985 3.408 67.052 3.432 ;
     RECT  65.693 12.816 67.057 14.376 ;
     RECT  66.421 15.6 67.057 19.848 ;
     RECT  67.057 12.816 67.093 19.848 ;
     RECT  67.093 12.48 67.129 19.848 ;
     RECT  67.052 3.408 67.208 3.96 ;
     RECT  66.733 5.472 67.208 5.736 ;
     RECT  66.661 7.872 67.208 7.992 ;
     RECT  66.913 11.424 67.208 11.448 ;
     RECT  67.129 12.48 67.208 19.896 ;
     RECT  66.697 20.976 67.208 27.912 ;
     RECT  66.949 28.944 67.208 31.896 ;
     RECT  66.709 34.368 67.208 34.92 ;
     RECT  66.877 35.952 67.208 36.264 ;
     RECT  65.257 37.584 67.208 38.424 ;
     RECT  67.129 41.184 67.208 41.208 ;
     RECT  67.208 2.148 67.213 41.208 ;
     RECT  67.213 2.148 67.312 41.16 ;
     RECT  67.312 2.418 67.504 41.16 ;
     RECT  66.995 0.096 67.561 0.12 ;
     RECT  67.504 12.528 67.601 32.472 ;
     RECT  67.504 37.632 67.609 41.16 ;
     RECT  67.601 24.48 67.619 32.472 ;
     RECT  67.504 36.24 67.673 36.504 ;
     RECT  67.504 3.408 67.709 5.592 ;
     RECT  67.601 12.528 67.709 23.4 ;
     RECT  67.709 16.56 67.745 23.304 ;
     RECT  67.504 6.816 67.889 10.632 ;
     RECT  67.609 37.632 67.897 41.016 ;
     RECT  67.745 16.56 67.961 21.96 ;
     RECT  67.889 6.816 68.141 10.2 ;
     RECT  66.796 43.056 68.209 43.08 ;
     RECT  67.709 3.408 68.285 5.496 ;
     RECT  67.619 28.944 68.285 32.472 ;
     RECT  68.209 42.192 68.387 43.08 ;
     RECT  67.961 16.56 68.429 21.768 ;
     RECT  67.619 24.48 68.435 27.96 ;
     RECT  68.429 18.432 68.501 21.768 ;
     RECT  68.435 24.48 68.537 26.76 ;
     RECT  68.501 21.216 68.573 21.768 ;
     RECT  67.897 37.632 68.645 38.568 ;
     RECT  67.745 23.28 68.717 23.304 ;
     RECT  67.504 34.368 68.749 34.92 ;
     RECT  67.709 12.528 68.773 15.336 ;
     RECT  68.429 16.56 68.773 17.4 ;
     RECT  68.285 4.176 68.785 5.496 ;
     RECT  67.673 36.48 68.821 36.504 ;
     RECT  68.645 37.632 68.821 38.424 ;
     RECT  68.773 12.528 68.825 17.4 ;
     RECT  68.825 14.256 68.861 17.4 ;
     RECT  68.435 27.888 68.861 27.96 ;
     RECT  68.749 33.504 68.869 34.92 ;
     RECT  68.141 6.816 68.897 6.84 ;
     RECT  68.141 8.112 68.929 10.2 ;
     RECT  68.785 4.176 68.969 5.592 ;
     RECT  68.285 30.096 68.969 32.472 ;
     RECT  68.869 33.456 69.001 34.92 ;
     RECT  68.537 25.008 69.005 26.76 ;
     RECT  68.861 14.256 69.041 14.904 ;
     RECT  68.861 16.128 69.149 17.4 ;
     RECT  69.001 32.832 69.185 34.92 ;
     RECT  68.969 4.992 69.221 5.544 ;
     RECT  68.501 18.432 69.221 20.088 ;
     RECT  68.285 28.944 69.253 29.016 ;
     RECT  68.969 30.096 69.253 31.752 ;
     RECT  69.221 5.472 69.257 5.544 ;
     RECT  68.929 8.112 69.289 10.776 ;
     RECT  68.573 21.504 69.289 21.768 ;
     RECT  69.289 21.504 69.301 22.152 ;
     RECT  68.825 12.528 69.325 13.032 ;
     RECT  67.897 40.128 69.325 41.016 ;
     RECT  69.289 8.112 69.361 10.92 ;
     RECT  69.301 21.504 69.469 22.2 ;
     RECT  69.361 8.064 69.493 10.92 ;
     RECT  68.387 42.96 69.625 43.08 ;
     RECT  69.005 25.104 69.644 26.76 ;
     RECT  69.361 3.936 69.649 3.96 ;
     RECT  69.469 21.504 69.692 22.68 ;
     RECT  69.644 25.104 69.731 26.808 ;
     RECT  69.493 8.064 69.757 11.016 ;
     RECT  69.325 12 69.757 13.032 ;
     RECT  69.731 25.104 69.761 26.28 ;
     RECT  69.692 21.312 69.779 22.68 ;
     RECT  68.821 36.48 69.905 38.424 ;
     RECT  69.325 39.84 69.941 41.016 ;
     RECT  69.757 8.064 69.977 13.032 ;
     RECT  69.761 25.104 69.977 25.992 ;
     RECT  69.905 36.624 70.121 38.424 ;
     RECT  69.253 28.944 70.213 31.752 ;
     RECT  69.185 32.832 70.213 33.096 ;
     RECT  69.185 34.32 70.213 34.92 ;
     RECT  68.861 27.936 70.225 27.96 ;
     RECT  70.213 28.944 70.225 34.92 ;
     RECT  69.257 5.52 70.297 5.544 ;
     RECT  69.041 14.256 70.373 14.28 ;
     RECT  69.221 20.064 70.513 20.088 ;
     RECT  67.561 0.096 70.549 0.264 ;
     RECT  69.361 6.528 70.621 6.552 ;
     RECT  70.549 0.048 70.657 0.264 ;
     RECT  69.149 16.656 70.657 17.4 ;
     RECT  69.221 18.432 70.657 18.504 ;
     RECT  69.941 40.992 70.657 41.016 ;
     RECT  69.977 8.112 70.697 13.032 ;
     RECT  70.225 27.936 70.697 34.92 ;
     RECT  69.977 25.104 70.733 25.704 ;
     RECT  70.297 5.136 70.801 5.544 ;
     RECT  70.621 6.528 70.801 6.84 ;
     RECT  70.697 27.936 70.837 32.952 ;
     RECT  70.837 27.504 70.841 32.952 ;
     RECT  69.779 22.032 70.873 22.2 ;
     RECT  70.081 23.904 70.873 23.928 ;
     RECT  70.657 15.408 70.909 15.432 ;
     RECT  70.657 16.656 70.909 18.504 ;
     RECT  70.873 22.032 70.909 23.928 ;
     RECT  69.649 3.312 70.931 3.96 ;
     RECT  70.841 27.504 70.945 27.528 ;
     RECT  70.945 27.36 70.981 27.528 ;
     RECT  70.909 15.408 70.988 18.504 ;
     RECT  70.981 26.64 71.057 27.528 ;
     RECT  70.697 34.32 71.057 34.92 ;
     RECT  70.697 8.112 71.125 12.792 ;
     RECT  70.801 5.136 71.197 6.84 ;
     RECT  71.125 7.968 71.197 12.792 ;
     RECT  70.931 3.312 71.201 3.432 ;
     RECT  70.657 0.048 71.219 1.128 ;
     RECT  70.657 40.992 71.219 41.64 ;
     RECT  70.909 21.072 71.221 23.928 ;
     RECT  70.513 19.824 71.269 20.088 ;
     RECT  71.221 21.072 71.269 24.12 ;
     RECT  71.219 40.992 71.273 41.592 ;
     RECT  71.197 5.136 71.315 12.792 ;
     RECT  70.733 25.104 71.345 25.512 ;
     RECT  71.219 0.048 71.363 0.552 ;
     RECT  71.315 5.136 71.413 5.64 ;
     RECT  71.269 19.824 71.413 24.12 ;
     RECT  71.345 25.104 71.413 25.464 ;
     RECT  70.988 15.408 71.485 18.792 ;
     RECT  71.413 19.824 71.485 25.464 ;
     RECT  71.057 26.64 71.489 27.384 ;
     RECT  69.625 43.056 71.549 43.08 ;
     RECT  71.485 15.408 71.597 25.464 ;
     RECT  69.941 39.84 71.597 39.864 ;
     RECT  71.363 0.144 71.633 0.552 ;
     RECT  71.315 6.816 71.665 12.792 ;
     RECT  70.837 14.112 71.665 14.136 ;
     RECT  71.633 0.528 71.987 0.552 ;
     RECT  70.841 28.512 71.989 32.952 ;
     RECT  71.413 5.04 72.025 5.64 ;
     RECT  71.489 27.312 72.025 27.384 ;
     RECT  71.989 28.464 72.025 32.952 ;
     RECT  72.025 27.312 72.053 32.952 ;
     RECT  71.665 6.816 72.085 14.136 ;
     RECT  72.085 6.816 72.349 14.184 ;
     RECT  71.597 15.408 72.349 15.576 ;
     RECT  72.025 4.656 72.36 5.64 ;
     RECT  72.349 6.816 72.36 15.576 ;
     RECT  72.341 0.576 72.425 0.6 ;
     RECT  71.273 41.568 72.457 41.592 ;
     RECT  71.549 42.96 72.457 43.08 ;
     RECT  70.121 37.872 72.469 38.424 ;
     RECT  72.457 41.568 72.533 43.08 ;
     RECT  71.201 3.408 72.608 3.432 ;
     RECT  72.36 4.416 72.608 15.576 ;
     RECT  71.597 16.656 72.608 25.464 ;
     RECT  72.053 27.312 72.608 33.096 ;
     RECT  71.057 34.32 72.608 34.344 ;
     RECT  70.121 36.624 72.608 36.648 ;
     RECT  72.469 37.872 72.608 38.52 ;
     RECT  72.025 39.792 72.608 39.816 ;
     RECT  72.608 2.148 72.712 41.052 ;
     RECT  72.712 2.148 72.745 40.782 ;
     RECT  72.745 1.728 72.904 40.782 ;
     RECT  72.904 9.504 72.929 10.104 ;
     RECT  72.904 28.464 72.965 33.288 ;
     RECT  72.904 19.824 73.043 25.464 ;
     RECT  72.904 6.048 73.073 6.072 ;
     RECT  72.904 3.408 73.109 5.064 ;
     RECT  72.904 11.136 73.109 18.792 ;
     RECT  72.904 26.64 73.181 27 ;
     RECT  72.965 29.232 73.181 33.288 ;
     RECT  73.181 32.352 73.235 33.288 ;
     RECT  73.109 4.848 73.253 5.064 ;
     RECT  72.904 39.792 73.253 39.912 ;
     RECT  72.533 42.144 73.261 43.08 ;
     RECT  73.181 29.232 73.289 31.368 ;
     RECT  73.043 19.824 73.325 23.4 ;
     RECT  73.109 11.136 73.361 15.48 ;
     RECT  73.181 26.64 73.541 26.664 ;
     RECT  73.361 11.136 73.649 15.048 ;
     RECT  72.904 1.728 73.657 1.752 ;
     RECT  73.325 19.824 73.708 21.528 ;
     RECT  73.043 24.48 74.153 25.464 ;
     RECT  72.904 38.4 74.185 38.52 ;
     RECT  73.289 29.616 74.188 31.368 ;
     RECT  74.188 31.2 74.189 31.368 ;
     RECT  74.156 28.368 74.243 28.488 ;
     RECT  74.243 28.464 74.261 28.488 ;
     RECT  73.253 39.888 74.297 39.912 ;
     RECT  73.649 13.968 74.329 15.048 ;
     RECT  72.929 9.504 74.369 9.528 ;
     RECT  72.904 7.344 74.437 7.992 ;
     RECT  74.389 0.096 74.513 0.12 ;
     RECT  74.188 29.616 74.617 30.12 ;
     RECT  74.189 31.248 74.621 31.368 ;
     RECT  74.437 7.344 74.629 8.232 ;
     RECT  73.649 11.136 74.653 12.792 ;
     RECT  74.329 13.968 74.653 15.384 ;
     RECT  73.109 16.512 74.653 18.792 ;
     RECT  73.325 22.656 74.657 23.4 ;
     RECT  73.708 21.168 74.761 21.528 ;
     RECT  73.261 42.96 74.761 43.08 ;
     RECT  74.621 31.248 74.801 31.272 ;
     RECT  74.761 42.144 74.845 43.08 ;
     RECT  73.109 3.408 74.876 3.432 ;
     RECT  74.876 3.168 74.905 3.432 ;
     RECT  74.905 2.832 74.909 3.432 ;
     RECT  74.341 5.904 74.917 5.928 ;
     RECT  74.909 2.832 74.963 3.192 ;
     RECT  74.917 5.904 74.977 6.072 ;
     RECT  73.253 4.848 75.017 4.872 ;
     RECT  74.653 16.512 75.061 18.84 ;
     RECT  73.708 19.824 75.061 20.088 ;
     RECT  75.061 16.512 75.148 20.088 ;
     RECT  75.049 35.328 75.205 35.352 ;
     RECT  72.904 36.72 75.205 36.744 ;
     RECT  75.205 35.328 75.251 36.744 ;
     RECT  74.185 38.4 75.253 38.808 ;
     RECT  75.193 40.992 75.277 41.016 ;
     RECT  74.761 21.168 75.305 21.624 ;
     RECT  74.653 10.8 75.373 15.384 ;
     RECT  75.148 16.512 75.373 18.792 ;
     RECT  75.253 38.4 75.373 39.384 ;
     RECT  74.963 2.832 75.445 2.856 ;
     RECT  75.373 10.8 75.481 18.792 ;
     RECT  74.657 23.376 75.5 23.4 ;
     RECT  74.629 7.344 75.553 9.048 ;
     RECT  75.5 23.376 75.587 24.312 ;
     RECT  75.445 2.736 75.697 2.856 ;
     RECT  75.697 2.64 75.737 2.856 ;
     RECT  75.737 2.64 75.809 2.76 ;
     RECT  75.587 23.376 75.869 23.928 ;
     RECT  75.788 0.048 75.875 0.072 ;
     RECT  75.305 21.216 75.884 21.624 ;
     RECT  75.869 22.752 75.884 23.928 ;
     RECT  75.884 21.216 75.923 23.928 ;
     RECT  75.923 21.216 75.953 22.776 ;
     RECT  75.953 21.216 75.971 22.44 ;
     RECT  75.809 2.64 75.985 2.664 ;
     RECT  74.977 5.856 76.021 6.072 ;
     RECT  75.553 7.344 76.021 9.096 ;
     RECT  75.373 38.4 76.021 39.912 ;
     RECT  76.021 5.856 76.057 9.096 ;
     RECT  74.617 29.232 76.061 30.12 ;
     RECT  76.021 38.016 76.061 39.912 ;
     RECT  76.057 5.184 76.067 9.384 ;
     RECT  75.913 3.84 76.163 3.96 ;
     RECT  76.067 6.864 76.165 9.384 ;
     RECT  75.481 10.56 76.165 18.792 ;
     RECT  76.163 3.936 76.309 3.96 ;
     RECT  76.067 5.184 76.309 5.88 ;
     RECT  75.148 19.824 76.417 20.088 ;
     RECT  76.309 3.936 76.421 5.88 ;
     RECT  76.417 19.824 76.453 20.184 ;
     RECT  75.971 21.216 76.453 21.672 ;
     RECT  76.165 6.864 76.457 18.792 ;
     RECT  76.061 38.016 76.565 39.336 ;
     RECT  76.421 3.936 76.601 5.208 ;
     RECT  76.453 19.824 76.601 21.672 ;
     RECT  76.457 6.864 76.745 8.568 ;
     RECT  74.845 42.96 76.789 43.08 ;
     RECT  76.745 7.968 76.835 8.568 ;
     RECT  76.601 21.6 76.993 21.672 ;
     RECT  75.923 23.904 77.036 23.928 ;
     RECT  74.153 25.44 77.077 25.464 ;
     RECT  76.565 38.016 77.101 38.76 ;
     RECT  76.457 9.552 77.173 18.792 ;
     RECT  76.601 19.824 77.173 20.184 ;
     RECT  75.985 2.256 77.281 2.664 ;
     RECT  76.601 3.936 77.281 4.776 ;
     RECT  77.209 41.568 77.293 41.592 ;
     RECT  75.251 36.192 77.557 36.216 ;
     RECT  77.281 2.256 77.605 4.776 ;
     RECT  76.789 42.864 77.605 43.08 ;
     RECT  77.125 22.704 77.641 22.728 ;
     RECT  77.173 9.552 77.653 20.184 ;
     RECT  77.036 23.904 77.66 24.312 ;
     RECT  77.077 25.44 77.66 26.04 ;
     RECT  77.101 37.584 77.701 38.76 ;
     RECT  76.835 7.968 77.797 7.992 ;
     RECT  77.653 9.552 77.797 20.568 ;
     RECT  76.745 6.864 77.893 6.936 ;
     RECT  77.797 7.968 77.893 20.568 ;
     RECT  77.641 22.704 77.965 22.824 ;
     RECT  77.66 23.904 77.965 26.04 ;
     RECT  77.605 2.256 78.008 5.16 ;
     RECT  77.893 6.144 78.008 20.568 ;
     RECT  76.993 21.6 78.008 21.72 ;
     RECT  77.965 22.704 78.008 26.04 ;
     RECT  76.061 29.232 78.008 29.832 ;
     RECT  77.605 31.296 78.008 31.32 ;
     RECT  77.557 36.192 78.008 36.504 ;
     RECT  77.701 37.584 78.008 39.24 ;
     RECT  77.101 0.528 78.035 0.552 ;
     RECT  78.008 2.148 78.112 41.052 ;
     RECT  78.112 2.418 78.304 41.052 ;
     RECT  78.304 29.232 78.419 29.832 ;
     RECT  78.304 35.904 78.445 39.24 ;
     RECT  77.605 42.144 78.509 43.08 ;
     RECT  78.304 16.512 78.761 18.84 ;
     RECT  78.304 40.992 78.805 41.052 ;
     RECT  78.761 16.56 78.833 18.84 ;
     RECT  78.304 2.592 78.869 3.432 ;
     RECT  78.304 11.136 78.905 15.192 ;
     RECT  78.445 36.24 78.905 39.24 ;
     RECT  78.304 4.656 78.941 9.768 ;
     RECT  78.905 36.24 79.013 36.648 ;
     RECT  78.941 4.656 79.043 6.84 ;
     RECT  78.941 7.872 79.084 9.768 ;
     RECT  78.304 24.336 79.085 26.04 ;
     RECT  78.905 11.136 79.265 14.232 ;
     RECT  79.084 7.968 79.301 9.768 ;
     RECT  78.805 40.992 79.301 41.592 ;
     RECT  79.043 4.656 79.369 6.12 ;
     RECT  78.304 19.968 79.405 20.088 ;
     RECT  78.304 21.072 79.405 23.304 ;
     RECT  78.419 29.232 79.441 29.496 ;
     RECT  79.369 4.56 79.445 6.12 ;
     RECT  79.405 19.968 79.58 23.304 ;
     RECT  79.301 41.568 79.621 41.592 ;
     RECT  78.509 43.056 79.621 43.08 ;
     RECT  78.833 16.56 79.625 18.792 ;
     RECT  79.445 4.56 79.697 5.16 ;
     RECT  79.621 41.568 79.805 43.08 ;
     RECT  79.441 29.232 79.811 30.264 ;
     RECT  79.805 41.568 80.057 41.592 ;
     RECT  79.301 7.968 80.125 8.712 ;
     RECT  78.905 38.4 80.156 39.24 ;
     RECT  79.265 11.136 80.161 13.992 ;
     RECT  79.697 4.56 80.201 5.064 ;
     RECT  79.58 19.776 80.233 23.304 ;
     RECT  80.125 7.44 80.309 8.712 ;
     RECT  80.309 7.44 80.341 7.464 ;
     RECT  80.161 10.8 80.341 13.992 ;
     RECT  80.156 38.4 80.381 39.288 ;
     RECT  80.341 6.672 80.387 7.464 ;
     RECT  79.625 17.136 80.413 18.792 ;
     RECT  80.233 19.776 80.413 23.352 ;
     RECT  79.013 36.624 80.444 36.648 ;
     RECT  80.381 38.4 80.444 39.24 ;
     RECT  80.444 36.624 80.531 39.24 ;
     RECT  79.981 0.528 80.588 0.552 ;
     RECT  80.309 8.688 80.629 8.712 ;
     RECT  80.588 0.048 80.675 0.552 ;
     RECT  79.801 16.08 80.693 16.104 ;
     RECT  80.413 17.136 80.693 23.352 ;
     RECT  80.341 10.272 80.725 13.992 ;
     RECT  80.197 40.416 80.801 40.44 ;
     RECT  80.693 16.08 80.813 23.352 ;
     RECT  80.801 40.416 80.885 41.016 ;
     RECT  79.085 24.48 80.917 26.04 ;
     RECT  78.304 27.072 80.917 27.096 ;
     RECT  80.813 19.92 80.921 23.352 ;
     RECT  80.201 5.04 80.953 5.064 ;
     RECT  80.953 5.04 80.989 5.304 ;
     RECT  80.917 24.48 81.059 27.096 ;
     RECT  80.989 5.04 81.133 5.592 ;
     RECT  80.387 6.672 81.133 7.08 ;
     RECT  80.813 16.08 81.209 18.792 ;
     RECT  80.921 21.888 81.209 23.352 ;
     RECT  81.059 24.48 81.349 24.936 ;
     RECT  78.869 2.592 81.457 3.384 ;
     RECT  80.885 40.416 81.497 40.44 ;
     RECT  80.629 8.688 81.537 8.808 ;
     RECT  80.725 9.936 81.537 13.992 ;
     RECT  81.133 5.04 81.589 7.08 ;
     RECT  81.537 8.688 81.589 13.992 ;
     RECT  79.805 42.96 81.637 43.08 ;
     RECT  80.675 0.192 81.683 0.552 ;
     RECT  81.589 5.04 81.749 13.992 ;
     RECT  79.811 29.232 81.781 29.496 ;
     RECT  81.457 2.592 81.829 4.008 ;
     RECT  80.531 36.624 81.889 36.648 ;
     RECT  81.683 0.192 81.893 0.216 ;
     RECT  81.829 2.592 81.921 4.392 ;
     RECT  81.749 5.472 81.929 13.992 ;
     RECT  81.889 36.24 81.929 36.648 ;
     RECT  81.921 2.688 81.965 4.392 ;
     RECT  81.929 6.816 81.971 13.704 ;
     RECT  81.965 3.312 82.001 4.392 ;
     RECT  81.209 16.128 82.033 18.792 ;
     RECT  80.921 19.92 82.033 20.856 ;
     RECT  82.033 16.128 82.061 20.856 ;
     RECT  81.209 21.888 82.061 23.16 ;
     RECT  81.781 29.232 82.069 29.64 ;
     RECT  81.971 10.32 82.073 13.704 ;
     RECT  82.001 3.696 82.109 4.392 ;
     RECT  81.971 6.816 82.181 9.144 ;
     RECT  81.059 26.016 82.213 26.04 ;
     RECT  81.059 27.072 82.213 27.096 ;
     RECT  81.929 5.472 82.253 5.784 ;
     RECT  82.069 29.232 82.321 30.84 ;
     RECT  81.349 24.432 82.357 24.936 ;
     RECT  81.637 42.912 82.505 43.08 ;
     RECT  82.069 32.16 82.573 32.184 ;
     RECT  82.501 33.168 82.573 33.192 ;
     RECT  82.061 16.128 82.645 23.16 ;
     RECT  82.357 24.384 82.645 24.936 ;
     RECT  82.213 26.016 82.645 27.096 ;
     RECT  82.321 28.512 82.717 30.84 ;
     RECT  82.573 32.16 82.717 33.192 ;
     RECT  82.021 40.992 82.837 41.016 ;
     RECT  82.021 0.096 82.937 0.168 ;
     RECT  80.531 38.4 83.041 39.24 ;
     RECT  82.717 28.512 83.077 33.192 ;
     RECT  82.837 40.992 83.153 41.592 ;
     RECT  82.645 16.128 83.173 27.096 ;
     RECT  82.073 10.32 83.221 10.344 ;
     RECT  82.073 11.76 83.221 13.704 ;
     RECT  81.929 36.24 83.221 36.264 ;
     RECT  83.077 28.272 83.257 33.192 ;
     RECT  83.221 35.328 83.329 36.264 ;
     RECT  82.181 6.816 83.365 6.84 ;
     RECT  83.041 38.208 83.365 39.24 ;
     RECT  83.269 1.728 83.408 1.752 ;
     RECT  82.109 3.696 83.408 3.96 ;
     RECT  82.253 5.568 83.408 5.784 ;
     RECT  83.365 6.816 83.408 7.368 ;
     RECT  82.181 8.544 83.408 9.144 ;
     RECT  83.221 10.32 83.408 13.704 ;
     RECT  82.537 14.784 83.408 14.808 ;
     RECT  83.173 15.984 83.408 27.096 ;
     RECT  83.257 28.176 83.408 33.192 ;
     RECT  83.329 34.368 83.408 36.264 ;
     RECT  83.365 37.68 83.408 39.24 ;
     RECT  83.153 40.992 83.408 41.052 ;
     RECT  83.408 1.728 83.512 41.052 ;
     RECT  82.505 42.96 83.653 43.08 ;
     RECT  83.512 1.728 83.704 41.016 ;
     RECT  83.704 28.224 83.729 35.064 ;
     RECT  83.704 1.728 83.765 1.752 ;
     RECT  83.704 8.496 83.801 8.856 ;
     RECT  83.704 15.696 84.017 23.4 ;
     RECT  82.937 0.144 84.085 0.168 ;
     RECT  84.017 15.696 84.161 17.496 ;
     RECT  83.704 36.24 84.161 37.704 ;
     RECT  83.729 28.272 84.197 35.064 ;
     RECT  83.704 40.992 84.269 41.016 ;
     RECT  84.161 15.696 84.305 17.256 ;
     RECT  84.017 18.48 84.305 23.4 ;
     RECT  83.704 13.584 84.413 14.664 ;
     RECT  83.653 42.912 84.469 43.08 ;
     RECT  84.161 36.24 84.665 36.936 ;
     RECT  83.704 3.84 84.697 7.368 ;
     RECT  84.697 3.84 84.757 7.512 ;
     RECT  83.801 8.496 84.757 8.52 ;
     RECT  84.469 42.144 84.773 43.08 ;
     RECT  84.665 36.816 84.809 36.936 ;
     RECT  83.704 24.384 84.841 27.24 ;
     RECT  84.197 29.088 84.841 35.064 ;
     RECT  84.841 29.088 84.917 35.544 ;
     RECT  84.757 3.84 84.947 8.52 ;
     RECT  84.413 13.584 84.947 14.28 ;
     RECT  83.704 10.32 84.949 12.6 ;
     RECT  84.947 13.584 84.949 13.944 ;
     RECT  84.841 24.384 84.953 28.008 ;
     RECT  84.949 10.32 85.025 13.944 ;
     RECT  84.917 29.088 85.025 30.792 ;
     RECT  84.917 31.776 85.025 35.544 ;
     RECT  84.085 0.096 85.093 0.168 ;
     RECT  85.025 10.848 85.097 13.944 ;
     RECT  84.947 8.304 85.129 8.52 ;
     RECT  85.129 8.304 85.165 9 ;
     RECT  84.305 21.648 85.201 23.4 ;
     RECT  84.953 24.384 85.201 27.912 ;
     RECT  84.305 15.696 85.281 17.16 ;
     RECT  85.265 40.992 85.349 41.016 ;
     RECT  84.947 3.84 85.421 6.888 ;
     RECT  85.281 15.456 85.475 17.16 ;
     RECT  84.305 18.48 85.489 20.616 ;
     RECT  85.201 21.648 85.489 27.912 ;
     RECT  85.345 2.736 85.493 2.856 ;
     RECT  85.493 2.736 85.529 2.76 ;
     RECT  85.489 18.48 85.571 27.912 ;
     RECT  85.165 8.304 85.601 9.336 ;
     RECT  85.571 18.48 85.601 23.16 ;
     RECT  85.421 3.84 85.637 6.744 ;
     RECT  85.601 18.48 85.669 23.112 ;
     RECT  85.669 41.568 85.753 41.592 ;
     RECT  84.809 36.912 85.817 36.936 ;
     RECT  85.669 18.192 85.907 23.112 ;
     RECT  85.907 20.544 85.948 23.112 ;
     RECT  85.025 29.088 85.957 29.496 ;
     RECT  85.025 32.064 85.961 35.544 ;
     RECT  85.571 24.384 85.993 27.912 ;
     RECT  85.957 28.944 85.993 29.496 ;
     RECT  85.961 32.064 85.997 35.352 ;
     RECT  84.773 42.96 86.101 43.08 ;
     RECT  85.097 10.848 86.137 13.032 ;
     RECT  86.137 10.128 86.141 13.032 ;
     RECT  83.704 38.736 86.245 39.24 ;
     RECT  86.245 38.688 86.389 39.24 ;
     RECT  85.601 8.304 86.501 9.144 ;
     RECT  85.993 24.384 86.533 29.496 ;
     RECT  85.025 30.768 86.533 30.792 ;
     RECT  85.997 32.064 86.537 34.104 ;
     RECT  85.093 0.096 86.573 0.552 ;
     RECT  86.537 32.064 86.573 33.24 ;
     RECT  86.141 13.008 86.609 13.032 ;
     RECT  85.948 21.408 86.609 23.112 ;
     RECT  86.605 14.784 86.629 14.808 ;
     RECT  85.475 16.224 86.629 17.16 ;
     RECT  86.389 38.688 86.629 40.2 ;
     RECT  85.907 18.192 86.645 19.368 ;
     RECT  86.533 24.384 86.645 30.792 ;
     RECT  86.573 0.144 86.681 0.552 ;
     RECT  86.629 14.784 86.716 17.16 ;
     RECT  86.629 37.2 86.716 40.2 ;
     RECT  85.637 3.84 86.789 6.072 ;
     RECT  86.681 0.192 86.861 0.552 ;
     RECT  86.861 0.24 86.915 0.552 ;
     RECT  86.716 14.784 86.933 14.808 ;
     RECT  86.645 24.384 86.965 24.408 ;
     RECT  86.789 3.936 87.001 6.072 ;
     RECT  86.965 24.096 87.005 24.408 ;
     RECT  86.915 0.24 87.041 0.504 ;
     RECT  86.716 37.2 87.137 37.224 ;
     RECT  87.137 36.432 87.221 37.224 ;
     RECT  86.501 8.976 87.253 9.144 ;
     RECT  86.141 10.128 87.253 11.928 ;
     RECT  85.997 35.328 87.289 35.352 ;
     RECT  87.253 8.976 87.293 11.928 ;
     RECT  86.609 21.408 87.329 22.776 ;
     RECT  87.289 34.752 87.329 35.352 ;
     RECT  87.041 0.48 87.347 0.504 ;
     RECT  87.329 21.408 87.505 21.72 ;
     RECT  87.329 22.752 87.545 22.776 ;
     RECT  87.293 10.944 87.577 11.928 ;
     RECT  86.716 16.08 87.577 17.16 ;
     RECT  86.645 19.008 87.649 19.368 ;
     RECT  86.573 32.064 87.649 33.048 ;
     RECT  87.577 16.08 87.721 17.352 ;
     RECT  86.101 42.192 87.731 43.08 ;
     RECT  87.289 14.208 87.937 14.232 ;
     RECT  87.649 31.824 87.973 33.048 ;
     RECT  87.973 31.824 88.045 33.096 ;
     RECT  88.045 31.824 88.081 33.144 ;
     RECT  86.716 38.688 88.109 40.2 ;
     RECT  86.645 25.584 88.117 30.792 ;
     RECT  88.081 31.824 88.117 33.24 ;
     RECT  87.937 14.208 88.153 14.856 ;
     RECT  87.721 15.984 88.153 17.352 ;
     RECT  87.649 18.384 88.153 19.368 ;
     RECT  88.117 25.584 88.261 33.24 ;
     RECT  87.329 34.752 88.261 34.92 ;
     RECT  88.268 0.048 88.355 0.072 ;
     RECT  87.001 3.936 88.357 6.216 ;
     RECT  88.153 14.208 88.369 17.352 ;
     RECT  88.153 18.384 88.369 19.8 ;
     RECT  88.261 25.584 88.441 33.384 ;
     RECT  88.261 34.368 88.441 34.92 ;
     RECT  88.357 3.936 88.549 7.608 ;
     RECT  87.293 8.976 88.549 9.816 ;
     RECT  88.369 14.208 88.645 19.8 ;
     RECT  87.505 21.072 88.645 21.72 ;
     RECT  88.645 14.208 88.657 21.72 ;
     RECT  87.613 22.8 88.657 23.112 ;
     RECT  88.549 3.936 88.693 9.816 ;
     RECT  87.577 10.944 88.693 11.976 ;
     RECT  88.657 14.208 88.729 23.112 ;
     RECT  87.005 24.096 88.729 24.12 ;
     RECT  88.693 3.936 88.765 11.976 ;
     RECT  88.765 3.936 88.808 12.792 ;
     RECT  88.729 14.208 88.808 24.12 ;
     RECT  88.441 25.584 88.808 34.92 ;
     RECT  87.221 37.2 88.808 37.224 ;
     RECT  88.109 38.688 88.808 41.016 ;
     RECT  88.808 2.148 88.885 41.052 ;
     RECT  88.885 2.148 88.912 41.208 ;
     RECT  88.693 0.096 88.931 0.12 ;
     RECT  88.912 2.418 88.985 41.208 ;
     RECT  88.985 2.418 89.104 40.782 ;
     RECT  89.104 23.088 89.165 25.8 ;
     RECT  89.104 33.024 89.165 34.632 ;
     RECT  89.104 9.792 89.201 13.704 ;
     RECT  89.104 6.816 89.219 8.472 ;
     RECT  89.104 3.936 89.273 4.92 ;
     RECT  89.104 15.024 89.309 22.056 ;
     RECT  87.731 43.056 89.317 43.08 ;
     RECT  89.104 27.072 89.525 31.416 ;
     RECT  89.165 33.648 89.561 34.632 ;
     RECT  89.219 6.816 89.597 7.944 ;
     RECT  89.165 23.136 89.597 25.8 ;
     RECT  89.525 27.072 89.597 29.88 ;
     RECT  89.273 4.896 89.633 4.92 ;
     RECT  89.597 7.392 89.741 7.944 ;
     RECT  89.525 31.296 89.777 31.416 ;
     RECT  89.201 9.792 89.885 13.128 ;
     RECT  89.885 10.128 89.957 13.128 ;
     RECT  89.741 7.92 89.993 7.944 ;
     RECT  89.957 10.224 90.029 13.128 ;
     RECT  89.597 24.096 90.097 25.8 ;
     RECT  89.597 27.072 90.097 29.688 ;
     RECT  90.097 24.096 90.101 29.688 ;
     RECT  90.029 11.28 90.169 13.128 ;
     RECT  89.309 15.84 90.169 22.056 ;
     RECT  90.169 15.84 90.181 22.776 ;
     RECT  90.181 18.144 90.245 22.776 ;
     RECT  90.181 15.84 90.313 17.16 ;
     RECT  90.169 11.28 90.349 13.224 ;
     RECT  89.777 31.296 90.353 31.32 ;
     RECT  90.101 24.096 90.461 29.496 ;
     RECT  90.476 40.464 90.563 40.488 ;
     RECT  90.313 14.928 90.569 17.16 ;
     RECT  89.104 37.008 90.637 37.032 ;
     RECT  90.029 10.272 90.677 10.296 ;
     RECT  90.245 21.648 90.677 22.776 ;
     RECT  90.677 21.744 90.785 22.776 ;
     RECT  89.104 38.784 90.889 39.24 ;
     RECT  90.637 36.48 90.901 37.032 ;
     RECT  90.349 11.28 90.929 13.464 ;
     RECT  90.517 0.096 91.073 0.12 ;
     RECT  90.461 24.096 91.177 27.432 ;
     RECT  90.901 36.48 91.181 37.608 ;
     RECT  90.929 11.856 91.249 13.464 ;
     RECT  91.181 37.584 91.249 37.608 ;
     RECT  90.889 38.688 91.249 39.24 ;
     RECT  90.569 15.024 91.333 17.16 ;
     RECT  90.245 18.144 91.333 20.232 ;
     RECT  91.249 37.584 91.361 39.24 ;
     RECT  89.317 42.144 91.405 43.08 ;
     RECT  91.333 15.024 91.613 20.232 ;
     RECT  91.613 15.168 91.645 20.232 ;
     RECT  89.561 34.608 91.649 34.632 ;
     RECT  91.361 37.584 91.793 39.048 ;
     RECT  91.393 30.72 91.825 30.744 ;
     RECT  90.461 28.416 91.897 28.44 ;
     RECT  90.461 29.472 91.897 29.496 ;
     RECT  91.897 28.416 91.937 29.496 ;
     RECT  91.681 33.6 91.937 33.624 ;
     RECT  91.825 30.72 92.077 31.128 ;
     RECT  91.937 28.512 92.113 29.496 ;
     RECT  92.113 28.512 92.147 29.64 ;
     RECT  91.645 15.168 92.197 20.328 ;
     RECT  92.149 0.096 92.221 0.12 ;
     RECT  91.717 35.232 92.221 35.352 ;
     RECT  91.181 36.48 92.221 36.504 ;
     RECT  92.147 28.56 92.252 29.64 ;
     RECT  92.077 30.72 92.252 31.416 ;
     RECT  92.252 28.56 92.257 31.416 ;
     RECT  92.197 15.168 92.284 20.52 ;
     RECT  92.284 15.168 92.297 18.984 ;
     RECT  92.284 20.064 92.321 20.52 ;
     RECT  90.785 21.744 92.321 22.248 ;
     RECT  92.257 28.56 92.333 32.328 ;
     RECT  91.717 40.992 92.369 41.016 ;
     RECT  91.249 11.856 92.405 13.848 ;
     RECT  92.321 20.064 92.405 22.248 ;
     RECT  92.405 21.648 92.473 22.248 ;
     RECT  92.221 35.232 92.473 36.504 ;
     RECT  91.793 38.208 92.473 39.048 ;
     RECT  92.473 21.648 92.509 22.776 ;
     RECT  92.473 38.208 92.533 39.912 ;
     RECT  92.509 21.648 92.545 22.872 ;
     RECT  91.177 23.952 92.545 27.432 ;
     RECT  92.221 0.096 92.579 0.552 ;
     RECT  92.405 11.856 92.579 13.656 ;
     RECT  90.421 8.496 92.773 8.52 ;
     RECT  92.773 7.92 92.819 8.52 ;
     RECT  92.819 7.92 92.86 7.944 ;
     RECT  91.405 42.192 92.905 43.08 ;
     RECT  92.509 33.552 93.157 33.576 ;
     RECT  92.533 38.208 93.349 40.44 ;
     RECT  92.333 28.752 93.373 32.328 ;
     RECT  93.157 33.456 93.373 33.576 ;
     RECT  92.473 35.232 93.397 36.84 ;
     RECT  93.349 38.208 93.397 41.016 ;
     RECT  93.373 28.752 93.481 33.576 ;
     RECT  92.405 20.064 93.517 20.568 ;
     RECT  92.545 21.648 93.517 27.432 ;
     RECT  93.481 28.752 93.517 33.96 ;
     RECT  93.517 20.064 93.733 27.432 ;
     RECT  93.397 35.232 93.805 41.016 ;
     RECT  92.905 42.144 93.817 43.08 ;
     RECT  92.579 11.952 93.836 13.656 ;
     RECT  92.297 15.168 93.877 18.264 ;
     RECT  93.733 19.632 93.877 27.432 ;
     RECT  93.517 28.752 93.949 34.152 ;
     RECT  93.805 35.184 93.949 41.016 ;
     RECT  93.553 9.36 94.069 9.384 ;
     RECT  93.949 28.752 94.069 41.016 ;
     RECT  94.069 28.512 94.129 41.016 ;
     RECT  94.129 28.416 94.165 41.016 ;
     RECT  92.101 3.936 94.208 3.96 ;
     RECT  93.661 6.816 94.208 6.84 ;
     RECT  94.069 8.448 94.208 9.384 ;
     RECT  93.836 11.328 94.208 13.656 ;
     RECT  93.877 15.168 94.208 27.432 ;
     RECT  94.165 28.416 94.208 41.592 ;
     RECT  94.208 2.148 94.312 41.592 ;
     RECT  94.312 2.418 94.385 41.592 ;
     RECT  94.385 2.418 94.504 41.16 ;
     RECT  92.579 0.096 94.549 0.12 ;
     RECT  94.504 26.784 94.565 37.032 ;
     RECT  94.504 20.832 94.601 23.352 ;
     RECT  94.504 17.136 94.665 19.656 ;
     RECT  94.665 18.384 94.684 19.656 ;
     RECT  94.504 40.032 94.691 41.16 ;
     RECT  94.565 27.072 94.709 37.032 ;
     RECT  94.684 18.768 94.745 19.656 ;
     RECT  94.691 40.032 94.781 41.016 ;
     RECT  93.817 43.056 94.933 43.08 ;
     RECT  94.549 0.096 94.997 0.168 ;
     RECT  94.709 28.272 95.033 37.032 ;
     RECT  94.781 40.272 95.213 41.016 ;
     RECT  95.033 28.272 95.249 33.96 ;
     RECT  94.601 20.832 95.257 21.864 ;
     RECT  94.504 5.856 95.285 13.656 ;
     RECT  95.285 5.856 95.429 9.096 ;
     RECT  94.601 23.328 95.557 23.352 ;
     RECT  94.504 24.48 95.557 25.464 ;
     RECT  95.257 21.12 95.641 21.864 ;
     RECT  95.557 23.328 95.641 25.464 ;
     RECT  95.429 5.856 95.645 8.472 ;
     RECT  95.249 29.04 95.717 33.96 ;
     RECT  94.745 18.768 95.753 19.512 ;
     RECT  94.997 0.144 95.795 0.168 ;
     RECT  94.665 17.136 95.893 17.256 ;
     RECT  94.709 27.072 95.893 27.24 ;
     RECT  95.285 10.272 95.897 13.656 ;
     RECT  95.893 27.072 95.965 27.912 ;
     RECT  95.641 21.12 96.001 25.464 ;
     RECT  95.965 26.64 96.001 27.912 ;
     RECT  95.897 12.912 96.037 13.656 ;
     RECT  94.504 14.928 96.037 14.952 ;
     RECT  94.504 38.832 96.077 38.952 ;
     RECT  96.001 21.12 96.149 27.912 ;
     RECT  96.037 12.912 96.221 14.952 ;
     RECT  96.221 13.632 96.253 14.952 ;
     RECT  95.717 29.472 96.253 33.96 ;
     RECT  95.033 34.944 96.253 37.032 ;
     RECT  96.253 13.632 96.293 15.432 ;
     RECT  96.077 38.928 96.361 38.952 ;
     RECT  95.213 40.272 96.361 40.296 ;
     RECT  96.149 21.12 96.437 25.704 ;
     RECT  96.253 29.472 96.437 37.032 ;
     RECT  95.753 19.344 96.505 19.512 ;
     RECT  94.933 42.96 96.533 43.08 ;
     RECT  96.361 38.928 96.563 40.296 ;
     RECT  96.533 42.144 96.617 43.08 ;
     RECT  95.897 10.272 96.653 11.88 ;
     RECT  96.437 31.296 96.689 37.032 ;
     RECT  96.653 10.368 96.761 11.88 ;
     RECT  96.505 19.344 96.793 20.568 ;
     RECT  96.689 37.008 96.793 37.032 ;
     RECT  96.793 37.008 96.833 37.464 ;
     RECT  96.793 19.296 96.865 20.568 ;
     RECT  96.437 29.472 96.865 30.264 ;
     RECT  96.149 27.072 96.901 27.912 ;
     RECT  96.865 29.376 96.901 30.264 ;
     RECT  96.901 27.072 96.941 30.264 ;
     RECT  96.689 31.296 96.941 35.928 ;
     RECT  96.181 0.096 96.949 0.12 ;
     RECT  96.563 40.272 96.949 40.296 ;
     RECT  96.941 31.296 97.013 31.512 ;
     RECT  96.617 42.96 97.013 43.08 ;
     RECT  95.645 5.856 97.045 8.376 ;
     RECT  96.437 21.648 97.117 25.704 ;
     RECT  96.941 27.072 97.117 29.592 ;
     RECT  96.833 37.44 97.117 37.464 ;
     RECT  96.563 38.928 97.117 39.24 ;
     RECT  95.893 17.136 97.153 17.4 ;
     RECT  96.865 18.816 97.157 20.568 ;
     RECT  96.941 32.496 97.157 35.928 ;
     RECT  97.117 21.648 97.193 29.592 ;
     RECT  96.949 40.272 97.337 41.016 ;
     RECT  96.949 0.096 97.441 0.168 ;
     RECT  97.153 17.136 97.441 17.496 ;
     RECT  97.157 18.816 97.441 19.368 ;
     RECT  97.157 34.656 97.481 35.928 ;
     RECT  97.337 40.272 97.481 40.968 ;
     RECT  96.293 15.408 97.513 15.432 ;
     RECT  97.441 16.608 97.513 19.368 ;
     RECT  97.513 15.408 97.553 19.368 ;
     RECT  97.045 5.856 97.589 9.288 ;
     RECT  96.761 11.664 97.621 11.88 ;
     RECT  97.117 37.44 97.669 39.24 ;
     RECT  96.761 10.368 97.765 10.392 ;
     RECT  97.621 11.664 97.765 12.552 ;
     RECT  97.765 10.368 97.837 12.552 ;
     RECT  96.293 13.632 97.837 13.992 ;
     RECT  97.657 36.048 97.949 36.072 ;
     RECT  97.013 31.296 98.053 31.32 ;
     RECT  97.669 37.44 98.053 39.288 ;
     RECT  97.553 15.84 98.125 19.368 ;
     RECT  97.013 43.056 98.125 43.08 ;
     RECT  98.053 31.296 98.161 31.416 ;
     RECT  97.157 32.496 98.161 33.672 ;
     RECT  97.157 20.448 98.197 20.568 ;
     RECT  98.125 15.84 98.209 19.464 ;
     RECT  97.193 21.648 98.237 23.16 ;
     RECT  97.441 0.096 98.243 0.552 ;
     RECT  98.161 31.296 98.269 33.672 ;
     RECT  97.481 34.656 98.269 34.92 ;
     RECT  98.209 15.84 98.309 18.504 ;
     RECT  97.193 24.528 98.341 29.592 ;
     RECT  98.341 24.528 98.425 30.216 ;
     RECT  98.237 21.648 98.453 22.824 ;
     RECT  98.309 15.84 98.489 18.264 ;
     RECT  98.425 24.528 98.557 29.592 ;
     RECT  97.837 10.368 98.593 13.992 ;
     RECT  98.489 15.84 98.593 18.216 ;
     RECT  97.481 40.272 98.593 40.296 ;
     RECT  98.243 0.096 98.627 0.504 ;
     RECT  98.593 40.272 98.633 40.392 ;
     RECT  97.589 6.048 98.737 9.288 ;
     RECT  98.269 31.296 98.737 34.92 ;
     RECT  98.627 0.144 98.777 0.504 ;
     RECT  98.197 20.448 98.845 20.616 ;
     RECT  98.053 36.48 98.845 39.288 ;
     RECT  98.737 30.576 98.881 34.92 ;
     RECT  98.737 5.568 98.953 9.288 ;
     RECT  98.953 1.728 99.037 1.752 ;
     RECT  98.125 42.144 99.037 43.08 ;
     RECT  98.453 21.84 99.205 22.824 ;
     RECT  98.557 24.192 99.205 29.592 ;
     RECT  98.845 36.48 99.241 39.384 ;
     RECT  98.633 40.368 99.397 40.392 ;
     RECT  98.881 30.576 99.493 35.016 ;
     RECT  99.241 36.048 99.493 39.384 ;
     RECT  98.953 5.04 99.565 9.288 ;
     RECT  99.565 5.04 99.608 9.336 ;
     RECT  98.593 10.368 99.608 18.216 ;
     RECT  98.845 20.304 99.608 20.616 ;
     RECT  99.205 21.84 99.608 29.592 ;
     RECT  99.493 30.576 99.608 39.384 ;
     RECT  99.397 40.368 99.608 40.968 ;
     RECT  99.608 2.148 99.712 41.052 ;
     RECT  99.712 2.148 99.713 40.968 ;
     RECT  98.777 0.24 99.74 0.504 ;
     RECT  99.74 0.24 99.827 0.552 ;
     RECT  99.713 2.148 99.904 40.782 ;
     RECT  99.904 30.576 99.965 37.608 ;
     RECT  99.965 30.576 100.001 31.416 ;
     RECT  99.904 16.656 100.019 19.224 ;
     RECT  100.001 30.768 100.019 31.416 ;
     RECT  99.904 5.04 100.289 9.336 ;
     RECT  99.904 23.856 100.307 25.128 ;
     RECT  99.827 0.24 100.309 0.504 ;
     RECT  100.019 30.768 100.361 30.84 ;
     RECT  100.307 23.856 100.54 24.504 ;
     RECT  99.037 42.192 100.565 43.08 ;
     RECT  99.965 32.448 100.613 37.608 ;
     RECT  100.565 42.144 100.649 43.08 ;
     RECT  100.573 1.728 100.657 1.752 ;
     RECT  100.613 32.448 100.721 34.728 ;
     RECT  99.904 20.496 100.829 22.824 ;
     RECT  99.904 26.544 100.829 28.44 ;
     RECT  100.829 20.592 100.865 22.824 ;
     RECT  100.019 16.656 100.885 17.592 ;
     RECT  100.829 28.272 100.901 28.44 ;
     RECT  100.289 5.568 100.94 9.336 ;
     RECT  99.904 10.32 100.94 15.48 ;
     RECT  100.885 16.512 100.973 17.592 ;
     RECT  100.829 26.544 100.973 26.76 ;
     RECT  100.613 36 100.973 37.608 ;
     RECT  100.94 5.568 101.027 15.48 ;
     RECT  101.027 10.08 101.045 15.48 ;
     RECT  100.721 32.448 101.045 33.816 ;
     RECT  100.973 36.048 101.045 37.608 ;
     RECT  101.027 5.568 101.075 8.76 ;
     RECT  101.045 36.48 101.117 37.608 ;
     RECT  100.973 17.328 101.149 17.592 ;
     RECT  100.019 18.672 101.149 19.224 ;
     RECT  101.149 17.328 101.189 19.224 ;
     RECT  101.045 10.08 101.225 12.312 ;
     RECT  101.225 11.472 101.261 12.312 ;
     RECT  100.865 20.592 101.333 20.664 ;
     RECT  100.865 21.648 101.405 22.392 ;
     RECT  100.973 26.736 101.405 26.76 ;
     RECT  101.045 13.92 101.437 15.48 ;
     RECT  101.075 5.904 101.441 8.76 ;
     RECT  100.649 42.192 101.459 43.08 ;
     RECT  101.333 20.592 101.477 20.616 ;
     RECT  101.045 32.448 101.509 33.144 ;
     RECT  101.441 8.112 101.549 8.76 ;
     RECT  101.437 13.92 101.585 16.152 ;
     RECT  99.904 29.568 101.653 29.592 ;
     RECT  100.361 30.816 101.653 30.84 ;
     RECT  101.549 8.112 101.729 8.136 ;
     RECT  101.653 29.568 101.765 30.84 ;
     RECT  101.689 34.224 101.773 34.248 ;
     RECT  101.459 42.912 101.909 43.08 ;
     RECT  101.189 17.328 102.017 18.024 ;
     RECT  100.901 28.416 102.049 28.44 ;
     RECT  100.54 24.48 102.085 24.504 ;
     RECT  102.085 24.48 102.125 25.512 ;
     RECT  101.765 29.568 102.125 30.312 ;
     RECT  101.189 19.2 102.157 19.224 ;
     RECT  102.013 34.656 102.193 34.68 ;
     RECT  100.309 0.144 102.229 0.504 ;
     RECT  102.193 34.656 102.233 34.776 ;
     RECT  101.225 10.08 102.265 10.248 ;
     RECT  99.904 40.368 102.305 40.392 ;
     RECT  102.229 0.144 102.313 1.176 ;
     RECT  102.125 24.768 102.337 25.512 ;
     RECT  102.233 34.704 102.337 34.776 ;
     RECT  101.117 36.48 102.337 36.792 ;
     RECT  102.337 34.704 102.377 36.792 ;
     RECT  101.441 5.904 102.409 7.128 ;
     RECT  101.585 14.304 102.445 16.152 ;
     RECT  101.905 31.296 102.445 31.32 ;
     RECT  101.509 32.304 102.445 33.144 ;
     RECT  102.265 9.696 102.449 10.248 ;
     RECT  102.157 19.2 102.481 20.568 ;
     RECT  101.261 12.144 102.517 12.312 ;
     RECT  102.481 19.2 102.611 21.144 ;
     RECT  102.589 10.848 102.625 10.872 ;
     RECT  102.517 12.144 102.625 13.08 ;
     RECT  101.405 22.224 102.625 22.392 ;
     RECT  102.193 23.376 102.625 23.4 ;
     RECT  102.449 9.696 102.653 9.816 ;
     RECT  102.313 0.144 102.659 0.552 ;
     RECT  102.625 10.848 102.697 13.08 ;
     RECT  102.611 19.2 102.697 20.712 ;
     RECT  102.017 17.616 102.701 18.024 ;
     RECT  102.049 27.6 102.701 28.44 ;
     RECT  102.409 5.136 102.733 7.128 ;
     RECT  102.653 9.072 102.737 9.816 ;
     RECT  102.697 10.848 102.773 13.128 ;
     RECT  102.659 0.144 102.812 0.168 ;
     RECT  102.773 10.944 102.845 13.128 ;
     RECT  102.625 22.224 102.845 23.4 ;
     RECT  102.733 5.136 102.881 7.224 ;
     RECT  102.812 0.048 102.899 0.168 ;
     RECT  102.845 11.184 102.917 13.128 ;
     RECT  102.845 22.848 102.917 23.4 ;
     RECT  102.337 24.768 102.917 26.424 ;
     RECT  99.904 38.64 102.949 38.664 ;
     RECT  102.701 17.616 102.953 17.64 ;
     RECT  102.445 14.304 102.989 16.296 ;
     RECT  102.125 30.192 102.989 30.312 ;
     RECT  102.917 12.144 103.021 13.128 ;
     RECT  102.989 14.304 103.021 15.048 ;
     RECT  102.881 6 103.025 7.224 ;
     RECT  102.949 38.544 103.036 39.912 ;
     RECT  102.949 8.448 103.091 8.568 ;
     RECT  103.036 39.264 103.187 39.912 ;
     RECT  102.697 19.056 103.189 20.712 ;
     RECT  103.187 39.264 103.228 39.288 ;
     RECT  102.989 16.272 103.237 16.296 ;
     RECT  102.737 9.696 103.313 9.816 ;
     RECT  103.021 12.144 103.313 15.048 ;
     RECT  103.313 12.144 103.385 13.08 ;
     RECT  103.189 18.672 103.385 20.712 ;
     RECT  102.377 34.704 103.385 35.784 ;
     RECT  103.091 8.448 103.421 8.472 ;
     RECT  103.237 16.272 103.421 16.776 ;
     RECT  102.377 36.768 103.436 36.792 ;
     RECT  102.917 25.104 103.453 26.424 ;
     RECT  102.701 27.6 103.453 27.96 ;
     RECT  102.445 31.296 103.477 33.144 ;
     RECT  103.477 31.296 103.489 33.624 ;
     RECT  103.385 34.704 103.489 35.112 ;
     RECT  103.436 36.48 103.493 36.792 ;
     RECT  103.409 40.992 103.493 41.016 ;
     RECT  103.493 36.48 103.523 36.504 ;
     RECT  103.093 23.424 103.529 23.448 ;
     RECT  103.421 16.272 103.601 16.584 ;
     RECT  103.489 31.296 103.637 35.112 ;
     RECT  103.025 6.672 103.669 7.224 ;
     RECT  103.637 31.392 103.745 35.112 ;
     RECT  103.669 6.672 103.756 8.424 ;
     RECT  103.313 14.208 103.756 15.048 ;
     RECT  103.745 31.392 103.763 32.568 ;
     RECT  102.989 30.192 103.781 30.216 ;
     RECT  103.756 6.672 103.961 7.608 ;
     RECT  103.745 33.6 103.961 35.112 ;
     RECT  103.763 31.392 103.997 32.472 ;
     RECT  103.961 34.176 103.997 35.112 ;
     RECT  103.385 12.144 104.06 12.552 ;
     RECT  102.899 0.144 104.209 0.168 ;
     RECT  103.385 18.816 104.245 20.712 ;
     RECT  103.921 17.616 104.569 17.64 ;
     RECT  104.245 18.816 104.569 21.144 ;
     RECT  101.909 42.96 104.597 43.08 ;
     RECT  103.601 16.56 104.605 16.584 ;
     RECT  104.569 17.616 104.605 21.144 ;
     RECT  103.453 25.104 104.605 27.96 ;
     RECT  104.209 0.144 104.675 0.552 ;
     RECT  104.597 42.144 104.681 43.08 ;
     RECT  104.605 16.56 104.684 21.144 ;
     RECT  103.961 6.672 105.008 6.696 ;
     RECT  103.313 9.696 105.008 9.72 ;
     RECT  104.06 11.376 105.008 12.552 ;
     RECT  104.569 13.584 105.008 13.608 ;
     RECT  103.756 14.64 105.008 15.048 ;
     RECT  104.684 16.416 105.008 21.144 ;
     RECT  104.605 24.912 105.008 27.96 ;
     RECT  103.997 31.392 105.008 31.416 ;
     RECT  103.997 32.448 105.008 32.472 ;
     RECT  103.997 35.088 105.008 35.112 ;
     RECT  105.008 2.148 105.112 41.052 ;
     RECT  105.112 2.418 105.304 40.782 ;
     RECT  104.675 0.144 106.013 0.168 ;
     RECT  104.681 43.056 106.013 43.08 ;
    LAYER M5 ;
     RECT  1.416 0.016 1.776 0.084 ;
     RECT  1.8 0.016 2.16 0.084 ;
     RECT  2.184 0.016 2.592 0.084 ;
     RECT  2.616 0.016 2.976 0.084 ;
     RECT  3 0.016 3.408 0.084 ;
     RECT  3.432 0.016 3.792 0.084 ;
     RECT  3.816 0.016 4.176 0.084 ;
     RECT  4.2 0.016 4.608 0.084 ;
     RECT  4.632 0.016 4.992 0.084 ;
     RECT  5.016 0.016 5.424 0.084 ;
     RECT  5.448 0.016 5.808 0.084 ;
     RECT  5.832 0.016 6.192 0.084 ;
     RECT  6.216 0.016 6.624 0.084 ;
     RECT  6.648 0.016 7.008 0.084 ;
     RECT  7.032 0.016 7.44 0.084 ;
     RECT  7.464 0.016 7.824 0.084 ;
     RECT  7.848 0.016 8.208 0.084 ;
     RECT  8.232 0.016 8.64 0.084 ;
     RECT  8.664 0.016 9.024 0.084 ;
     RECT  9.048 0.016 9.456 0.084 ;
     RECT  9.48 0.016 9.84 0.084 ;
     RECT  9.864 0.016 10.224 0.084 ;
     RECT  10.248 0.016 10.656 0.084 ;
     RECT  10.68 0.016 11.04 0.084 ;
     RECT  11.064 0.016 11.472 0.084 ;
     RECT  11.496 0.016 11.856 0.084 ;
     RECT  11.88 0.016 12.24 0.084 ;
     RECT  12.264 0.016 12.672 0.084 ;
     RECT  12.696 0.016 13.056 0.084 ;
     RECT  13.08 0.016 13.488 0.084 ;
     RECT  13.512 0.016 13.872 0.084 ;
     RECT  13.896 0.016 14.304 0.084 ;
     RECT  14.328 0.016 14.688 0.084 ;
     RECT  14.712 0.016 15.072 0.084 ;
     RECT  15.096 0.016 15.504 0.084 ;
     RECT  15.528 0.016 15.888 0.084 ;
     RECT  15.912 0.016 16.32 0.084 ;
     RECT  16.344 0.016 16.704 0.084 ;
     RECT  16.728 0.016 17.088 0.084 ;
     RECT  17.112 0.016 17.52 0.084 ;
     RECT  17.544 0.016 17.904 0.084 ;
     RECT  17.928 0.016 18.336 0.084 ;
     RECT  18.36 0.016 18.72 0.084 ;
     RECT  18.744 0.016 19.104 0.084 ;
     RECT  19.128 0.016 19.536 0.084 ;
     RECT  19.56 0.016 19.92 0.084 ;
     RECT  19.944 0.016 20.352 0.084 ;
     RECT  20.376 0.016 20.736 0.084 ;
     RECT  20.76 0.016 21.12 0.084 ;
     RECT  21.144 0.016 21.552 0.084 ;
     RECT  21.576 0.016 21.936 0.084 ;
     RECT  21.96 0.016 22.368 0.084 ;
     RECT  22.392 0.016 22.752 0.084 ;
     RECT  22.776 0.016 23.136 0.084 ;
     RECT  23.16 0.016 23.568 0.084 ;
     RECT  23.592 0.016 23.952 0.084 ;
     RECT  23.976 0.016 24.384 0.084 ;
     RECT  24.408 0.016 24.768 0.084 ;
     RECT  24.792 0.016 25.152 0.084 ;
     RECT  25.176 0.016 25.584 0.084 ;
     RECT  25.608 0.016 25.968 0.084 ;
     RECT  25.992 0.016 26.4 0.084 ;
     RECT  26.424 0.016 26.784 0.084 ;
     RECT  26.808 0.016 27.168 0.084 ;
     RECT  27.192 0.016 27.6 0.084 ;
     RECT  27.624 0.016 27.984 0.084 ;
     RECT  28.008 0.016 28.416 0.084 ;
     RECT  28.44 0.016 28.8 0.084 ;
     RECT  28.824 0.016 29.184 0.084 ;
     RECT  29.208 0.016 29.616 0.084 ;
     RECT  29.64 0.016 30 0.084 ;
     RECT  30.024 0.016 30.432 0.084 ;
     RECT  30.456 0.016 30.816 0.084 ;
     RECT  30.84 0.016 31.248 0.084 ;
     RECT  31.272 0.016 31.632 0.084 ;
     RECT  31.656 0.016 32.016 0.084 ;
     RECT  32.04 0.016 32.448 0.084 ;
     RECT  32.472 0.016 32.832 0.084 ;
     RECT  32.856 0.016 33.264 0.084 ;
     RECT  33.288 0.016 33.648 0.084 ;
     RECT  33.672 0.016 34.032 0.084 ;
     RECT  34.056 0.016 34.464 0.084 ;
     RECT  34.488 0.016 34.848 0.084 ;
     RECT  34.872 0.016 35.28 0.084 ;
     RECT  35.304 0.016 35.664 0.084 ;
     RECT  35.688 0.016 36.048 0.084 ;
     RECT  36.072 0.016 36.48 0.084 ;
     RECT  36.504 0.016 36.864 0.084 ;
     RECT  36.888 0.016 37.296 0.084 ;
     RECT  37.32 0.016 37.68 0.084 ;
     RECT  37.704 0.016 38.064 0.084 ;
     RECT  38.088 0.016 38.496 0.084 ;
     RECT  38.52 0.016 38.88 0.084 ;
     RECT  38.904 0.016 39.312 0.084 ;
     RECT  39.336 0.016 39.696 0.084 ;
     RECT  39.72 0.016 40.08 0.084 ;
     RECT  40.104 0.016 40.512 0.084 ;
     RECT  40.536 0.016 40.896 0.084 ;
     RECT  40.92 0.016 41.328 0.084 ;
     RECT  41.352 0.016 41.712 0.084 ;
     RECT  41.736 0.016 42.096 0.084 ;
     RECT  42.12 0.016 42.528 0.084 ;
     RECT  42.552 0.016 42.912 0.084 ;
     RECT  42.936 0.016 43.344 0.084 ;
     RECT  43.368 0.016 43.728 0.084 ;
     RECT  43.752 0.016 44.112 0.084 ;
     RECT  44.136 0.016 44.544 0.084 ;
     RECT  44.568 0.016 44.928 0.084 ;
     RECT  44.952 0.016 45.36 0.084 ;
     RECT  45.384 0.016 45.744 0.084 ;
     RECT  45.768 0.016 46.128 0.084 ;
     RECT  46.152 0.016 46.56 0.084 ;
     RECT  46.584 0.016 46.944 0.084 ;
     RECT  46.968 0.016 47.376 0.084 ;
     RECT  47.4 0.016 47.76 0.084 ;
     RECT  47.784 0.016 48.192 0.084 ;
     RECT  48.216 0.016 48.576 0.084 ;
     RECT  48.6 0.016 48.96 0.084 ;
     RECT  48.984 0.016 49.392 0.084 ;
     RECT  49.416 0.016 49.776 0.084 ;
     RECT  49.8 0.016 50.208 0.084 ;
     RECT  50.232 0.016 50.592 0.084 ;
     RECT  50.616 0.016 50.976 0.084 ;
     RECT  51 0.016 51.408 0.084 ;
     RECT  51.432 0.016 51.792 0.084 ;
     RECT  51.816 0.016 52.224 0.084 ;
     RECT  52.248 0.016 52.608 0.084 ;
     RECT  52.632 0.016 52.992 0.084 ;
     RECT  53.016 0.016 53.424 0.084 ;
     RECT  53.448 0.016 53.808 0.084 ;
     RECT  53.832 0.016 54.24 0.084 ;
     RECT  54.264 0.016 54.624 0.084 ;
     RECT  54.648 0.016 55.008 0.084 ;
     RECT  55.032 0.016 55.44 0.084 ;
     RECT  55.464 0.016 55.824 0.084 ;
     RECT  55.848 0.016 56.256 0.084 ;
     RECT  56.28 0.016 56.64 0.084 ;
     RECT  56.664 0.016 57.024 0.084 ;
     RECT  57.048 0.016 57.456 0.084 ;
     RECT  57.48 0.016 57.84 0.084 ;
     RECT  57.864 0.016 58.272 0.084 ;
     RECT  58.296 0.016 58.656 0.084 ;
     RECT  58.68 0.016 59.04 0.084 ;
     RECT  59.064 0.016 59.472 0.084 ;
     RECT  59.496 0.016 59.856 0.084 ;
     RECT  59.88 0.016 60.288 0.084 ;
     RECT  60.312 0.016 60.672 0.084 ;
     RECT  60.696 0.016 61.056 0.084 ;
     RECT  61.08 0.016 61.488 0.084 ;
     RECT  61.512 0.016 61.872 0.084 ;
     RECT  61.896 0.016 62.304 0.084 ;
     RECT  62.328 0.016 62.688 0.084 ;
     RECT  62.712 0.016 63.072 0.084 ;
     RECT  63.096 0.016 63.504 0.084 ;
     RECT  63.528 0.016 63.888 0.084 ;
     RECT  63.912 0.016 64.32 0.084 ;
     RECT  64.344 0.016 64.704 0.084 ;
     RECT  64.728 0.016 65.136 0.084 ;
     RECT  65.16 0.016 65.52 0.084 ;
     RECT  65.544 0.016 65.904 0.084 ;
     RECT  65.928 0.016 66.336 0.084 ;
     RECT  66.36 0.016 66.72 0.084 ;
     RECT  66.744 0.016 67.152 0.084 ;
     RECT  67.176 0.016 67.536 0.084 ;
     RECT  67.56 0.016 67.92 0.084 ;
     RECT  67.944 0.016 68.352 0.084 ;
     RECT  68.376 0.016 68.736 0.084 ;
     RECT  68.76 0.016 69.168 0.084 ;
     RECT  69.192 0.016 69.552 0.084 ;
     RECT  69.576 0.016 69.936 0.084 ;
     RECT  69.96 0.016 70.368 0.084 ;
     RECT  70.392 0.016 70.752 0.084 ;
     RECT  70.776 0.016 71.184 0.084 ;
     RECT  71.208 0.016 71.568 0.084 ;
     RECT  71.592 0.016 71.952 0.084 ;
     RECT  71.976 0.016 72.384 0.084 ;
     RECT  72.408 0.016 72.768 0.084 ;
     RECT  72.792 0.016 73.2 0.084 ;
     RECT  73.224 0.016 73.584 0.084 ;
     RECT  73.608 0.016 73.968 0.084 ;
     RECT  73.992 0.016 74.4 0.084 ;
     RECT  74.424 0.016 74.784 0.084 ;
     RECT  74.808 0.016 75.216 0.084 ;
     RECT  75.24 0.016 75.6 0.084 ;
     RECT  75.624 0.016 75.984 0.084 ;
     RECT  76.008 0.016 76.416 0.084 ;
     RECT  76.44 0.016 76.8 0.084 ;
     RECT  76.824 0.016 77.232 0.084 ;
     RECT  77.256 0.016 77.616 0.084 ;
     RECT  77.64 0.016 78 0.084 ;
     RECT  78.024 0.016 78.432 0.084 ;
     RECT  78.456 0.016 78.816 0.084 ;
     RECT  78.84 0.016 79.248 0.084 ;
     RECT  79.272 0.016 79.632 0.084 ;
     RECT  79.656 0.016 80.016 0.084 ;
     RECT  80.04 0.016 80.448 0.084 ;
     RECT  80.472 0.016 80.832 0.084 ;
     RECT  80.856 0.016 81.264 0.084 ;
     RECT  81.288 0.016 81.648 0.084 ;
     RECT  81.672 0.016 82.032 0.084 ;
     RECT  82.056 0.016 82.464 0.084 ;
     RECT  82.488 0.016 82.848 0.084 ;
     RECT  82.872 0.016 83.28 0.084 ;
     RECT  83.304 0.016 83.664 0.084 ;
     RECT  83.688 0.016 84.096 0.084 ;
     RECT  84.12 0.016 84.48 0.084 ;
     RECT  84.504 0.016 84.864 0.084 ;
     RECT  84.888 0.016 85.296 0.084 ;
     RECT  85.32 0.016 85.68 0.084 ;
     RECT  85.704 0.016 86.112 0.084 ;
     RECT  86.136 0.016 86.496 0.084 ;
     RECT  86.52 0.016 86.88 0.084 ;
     RECT  86.904 0.016 87.312 0.084 ;
     RECT  87.336 0.016 87.696 0.084 ;
     RECT  87.72 0.016 88.128 0.084 ;
     RECT  88.152 0.016 88.512 0.084 ;
     RECT  88.536 0.016 88.896 0.084 ;
     RECT  88.92 0.016 89.328 0.084 ;
     RECT  89.352 0.016 89.712 0.084 ;
     RECT  89.736 0.016 90.144 0.084 ;
     RECT  90.168 0.016 90.528 0.084 ;
     RECT  90.552 0.016 90.912 0.084 ;
     RECT  90.936 0.016 91.344 0.084 ;
     RECT  91.368 0.016 91.728 0.084 ;
     RECT  91.752 0.016 92.16 0.084 ;
     RECT  92.184 0.016 92.544 0.084 ;
     RECT  92.568 0.016 92.928 0.084 ;
     RECT  92.952 0.016 93.36 0.084 ;
     RECT  93.384 0.016 93.744 0.084 ;
     RECT  93.768 0.016 94.176 0.084 ;
     RECT  94.2 0.016 94.56 0.084 ;
     RECT  94.584 0.016 94.944 0.084 ;
     RECT  94.968 0.016 95.376 0.084 ;
     RECT  95.4 0.016 95.76 0.084 ;
     RECT  95.784 0.016 96.192 0.084 ;
     RECT  96.216 0.016 96.576 0.084 ;
     RECT  96.6 0.016 96.96 0.084 ;
     RECT  96.984 0.016 97.392 0.084 ;
     RECT  97.416 0.016 97.776 0.084 ;
     RECT  97.8 0.016 98.208 0.084 ;
     RECT  98.232 0.016 98.592 0.084 ;
     RECT  98.616 0.016 98.976 0.084 ;
     RECT  99 0.016 99.408 0.084 ;
     RECT  99.432 0.016 99.792 0.084 ;
     RECT  99.816 0.016 100.224 0.084 ;
     RECT  100.248 0.016 100.608 0.084 ;
     RECT  100.632 0.016 101.04 0.084 ;
     RECT  101.064 0.016 101.424 0.084 ;
     RECT  101.448 0.016 101.808 0.084 ;
     RECT  101.832 0.016 102.24 0.084 ;
     RECT  102.264 0.016 102.624 0.084 ;
     RECT  102.648 0.016 103.056 0.084 ;
     RECT  103.08 0.016 103.44 0.084 ;
     RECT  103.464 0.016 103.824 0.084 ;
     RECT  103.848 0.016 104.256 0.084 ;
     RECT  104.28 0.016 104.64 0.084 ;
     RECT  1.392 0.084 104.664 0.131 ;
     RECT  1.776 0.131 5.832 0.179 ;
     RECT  7.44 0.131 63.528 0.179 ;
     RECT  64.704 0.131 92.568 0.179 ;
     RECT  93.84 0.131 104.664 0.179 ;
     RECT  1.776 0.179 3 0.227 ;
     RECT  7.44 0.179 21.144 0.227 ;
     RECT  22.368 0.179 32.856 0.227 ;
     RECT  70.368 0.179 83.304 0.227 ;
     RECT  85.296 0.179 92.568 0.227 ;
     RECT  34.032 0.179 62.328 0.275 ;
     RECT  85.68 0.227 92.568 0.275 ;
     RECT  34.032 0.275 57.288 0.467 ;
     RECT  28.416 0.227 32.856 0.515 ;
     RECT  34.032 0.467 37.32 0.515 ;
     RECT  38.496 0.467 50.616 0.515 ;
     RECT  64.704 0.179 69.192 0.515 ;
     RECT  7.44 0.227 20.76 0.563 ;
     RECT  22.368 0.227 26.904 0.563 ;
     RECT  28.416 0.515 29.256 0.563 ;
     RECT  34.032 0.515 34.488 0.563 ;
     RECT  38.496 0.515 50.232 0.563 ;
     RECT  51.648 0.467 57.288 0.563 ;
     RECT  58.656 0.275 62.328 0.563 ;
     RECT  65.136 0.515 69.192 0.563 ;
     RECT  70.752 0.227 83.304 0.563 ;
     RECT  86.112 0.275 92.568 0.563 ;
     RECT  96.576 0.179 104.664 0.563 ;
     RECT  38.88 0.563 42.552 0.611 ;
     RECT  43.536 0.563 49.416 0.611 ;
     RECT  72.384 0.563 80.856 0.611 ;
     RECT  22.752 0.563 26.904 1.139 ;
     RECT  71.184 0.563 71.352 1.139 ;
     RECT  58.656 0.563 62.232 1.187 ;
     RECT  100.32 0.563 104.28 1.187 ;
     RECT  9.024 0.563 16.728 1.763 ;
     RECT  23.568 1.139 26.904 1.763 ;
     RECT  47.76 0.611 49.416 1.763 ;
     RECT  58.656 1.187 59.064 1.763 ;
     RECT  60.288 1.187 62.232 1.763 ;
     RECT  72.768 0.611 80.856 1.763 ;
     RECT  96.576 0.563 99 1.763 ;
     RECT  12.672 1.763 16.728 1.811 ;
     RECT  28.992 0.563 29.256 2.137 ;
     RECT  30.432 0.515 32.856 2.137 ;
     RECT  34.032 0.563 34.056 2.137 ;
     RECT  35.664 0.515 37.32 2.137 ;
     RECT  38.88 0.611 39.72 2.137 ;
     RECT  40.704 0.611 42.552 2.137 ;
     RECT  51.648 0.563 51.672 2.137 ;
     RECT  72.768 1.763 72.912 2.137 ;
     RECT  82.368 0.563 83.304 2.137 ;
     RECT  93.84 0.179 93.864 2.137 ;
     RECT  94.896 0.179 95.4 2.137 ;
     RECT  100.32 1.187 101.736 2.137 ;
     RECT  102.864 1.187 104.28 2.137 ;
     RECT  7.8 2.137 7.92 2.151 ;
     RECT  82.368 2.137 83.52 2.151 ;
     RECT  102.864 2.137 105.12 2.151 ;
     RECT  13.056 1.811 16.728 2.291 ;
     RECT  24 1.763 26.904 2.291 ;
     RECT  82.368 2.151 83.712 2.581 ;
     RECT  28.992 2.137 32.856 2.677 ;
     RECT  7.8 2.151 8.112 2.773 ;
     RECT  13.2 2.291 16.728 2.869 ;
     RECT  17.712 0.563 20.76 2.869 ;
     RECT  7.488 2.773 8.112 3.397 ;
     RECT  22.272 2.533 22.296 3.443 ;
     RECT  43.536 0.611 46.056 3.685 ;
     RECT  24 2.291 24.312 3.829 ;
     RECT  4.176 0.179 5.832 3.925 ;
     RECT  7.488 3.397 8.28 3.925 ;
     RECT  25.728 2.291 26.904 3.925 ;
     RECT  28.224 2.677 32.856 3.925 ;
     RECT  34.032 2.137 37.32 3.925 ;
     RECT  38.88 2.137 42.552 3.925 ;
     RECT  60.576 1.763 62.232 3.925 ;
     RECT  63.504 0.179 63.528 3.925 ;
     RECT  70.32 3.877 70.344 3.925 ;
     RECT  71.328 1.139 71.352 3.925 ;
     RECT  87.696 0.563 91.752 3.925 ;
     RECT  93.84 2.137 95.4 3.925 ;
     RECT  13.2 2.869 20.76 4.261 ;
     RECT  72.6 2.137 72.912 4.405 ;
     RECT  51 2.137 51.672 4.453 ;
     RECT  52.992 0.563 57.288 4.453 ;
     RECT  4.176 3.925 8.28 4.501 ;
     RECT  86.448 3.925 86.472 4.501 ;
     RECT  43.536 3.685 46.92 4.691 ;
     RECT  85.488 4.501 86.472 4.741 ;
     RECT  28.224 3.925 42.552 4.931 ;
     RECT  12.528 4.261 20.76 4.979 ;
     RECT  3.936 4.501 9.144 5.171 ;
     RECT  85.008 4.741 86.472 5.171 ;
     RECT  9.12 5.171 9.144 5.459 ;
     RECT  51 4.453 57.288 5.459 ;
     RECT  49.392 1.763 49.416 5.653 ;
     RECT  85.008 5.171 85.032 5.653 ;
     RECT  51 5.459 51.672 5.749 ;
     RECT  12.528 4.979 16.728 5.891 ;
     RECT  72.432 4.405 72.912 6.035 ;
     RECT  84.768 5.653 85.032 6.035 ;
     RECT  72.6 6.035 72.912 6.037 ;
     RECT  73.968 1.763 80.856 6.037 ;
     RECT  96.576 1.763 98.184 6.037 ;
     RECT  43.536 4.691 46.056 6.229 ;
     RECT  28.992 4.931 42.552 6.323 ;
     RECT  49.392 5.653 49.56 6.323 ;
     RECT  49.392 6.323 49.416 6.371 ;
     RECT  50.88 5.749 51.672 6.419 ;
     RECT  87.696 3.925 95.4 6.421 ;
     RECT  96.576 6.037 98.52 6.421 ;
     RECT  10.512 5.989 10.536 6.563 ;
     RECT  59.04 1.763 59.064 6.709 ;
     RECT  3.936 5.171 8.112 6.851 ;
     RECT  72.6 6.037 80.856 6.853 ;
     RECT  81.84 2.581 83.712 6.853 ;
     RECT  72.6 6.853 83.712 6.899 ;
     RECT  51 6.419 51.672 7.045 ;
     RECT  37.296 6.323 42.552 7.235 ;
     RECT  48.624 6.661 48.648 7.235 ;
     RECT  87.696 6.421 98.52 7.331 ;
     RECT  65.136 0.563 65.544 7.333 ;
     RECT  1.776 0.227 2.856 7.381 ;
     RECT  23.04 3.829 24.312 7.381 ;
     RECT  84.768 6.035 84.792 7.477 ;
     RECT  84.768 7.477 84.936 7.619 ;
     RECT  72.6 6.899 76.824 7.667 ;
     RECT  59.04 6.709 59.448 7.765 ;
     RECT  60.576 3.925 63.864 7.765 ;
     RECT  77.904 6.899 83.712 7.957 ;
     RECT  59.04 7.765 63.864 8.003 ;
     RECT  65.136 7.333 65.592 8.003 ;
     RECT  77.808 7.957 83.712 8.003 ;
     RECT  59.424 8.003 63.864 8.051 ;
     RECT  99.6 2.137 101.736 8.147 ;
     RECT  43.536 6.229 46.968 8.195 ;
     RECT  51 7.045 51.768 8.195 ;
     RECT  22.8 7.381 24.312 8.243 ;
     RECT  96.576 7.331 98.52 8.245 ;
     RECT  1.776 7.381 2.904 8.291 ;
     RECT  84.816 7.619 84.936 8.435 ;
     RECT  28.992 6.323 36.312 8.437 ;
     RECT  22.848 8.243 24.312 8.531 ;
     RECT  73.968 7.667 76.824 8.579 ;
     RECT  24 8.531 24.312 8.821 ;
     RECT  25.536 3.925 26.904 8.821 ;
     RECT  101.712 8.147 101.736 9.061 ;
     RECT  102.864 2.151 105.312 9.061 ;
     RECT  10.8 8.437 10.824 9.155 ;
     RECT  28.992 8.437 36.36 9.299 ;
     RECT  13.2 5.891 16.728 9.301 ;
     RECT  17.712 4.979 20.76 9.349 ;
     RECT  52.992 5.459 57.288 9.349 ;
     RECT  48.912 7.429 48.936 9.395 ;
     RECT  99.6 8.147 100.344 9.397 ;
     RECT  101.712 9.061 105.312 9.397 ;
     RECT  38.112 7.235 42.552 9.493 ;
     RECT  43.536 8.195 46.728 9.493 ;
     RECT  72.6 7.667 72.912 9.493 ;
     RECT  77.808 8.003 79.032 9.539 ;
     RECT  80.016 8.003 83.712 9.635 ;
     RECT  38.112 9.493 46.728 9.683 ;
     RECT  99.6 9.397 105.312 9.731 ;
     RECT  78 9.539 79.032 9.779 ;
     RECT  22.848 8.531 22.872 9.925 ;
     RECT  24 8.821 26.904 9.925 ;
     RECT  43.296 9.683 46.728 10.067 ;
     RECT  13.056 9.301 16.728 10.211 ;
     RECT  13.2 10.211 16.728 10.213 ;
     RECT  17.712 9.349 20.808 10.213 ;
     RECT  28.992 9.299 36.312 10.259 ;
     RECT  99.6 9.731 101.736 10.355 ;
     RECT  13.2 10.213 20.808 10.595 ;
     RECT  28.992 10.259 35.112 10.597 ;
     RECT  84.816 8.435 84.84 10.837 ;
     RECT  13.2 10.595 20.76 10.883 ;
     RECT  81.936 9.635 83.712 10.883 ;
     RECT  84.816 10.837 85.368 10.883 ;
     RECT  83.4 10.883 83.712 10.885 ;
     RECT  85.344 10.883 85.368 10.885 ;
     RECT  86.448 5.171 86.472 10.885 ;
     RECT  66.72 0.563 69.192 10.981 ;
     RECT  70.32 3.925 71.352 10.981 ;
     RECT  22.848 9.925 26.904 11.027 ;
     RECT  96.576 8.245 98.616 11.029 ;
     RECT  99.6 10.355 100.344 11.029 ;
     RECT  78 9.779 78.312 11.125 ;
     RECT  80.016 9.635 80.856 11.125 ;
     RECT  87.696 7.331 95.4 11.173 ;
     RECT  96.576 11.029 100.344 11.173 ;
     RECT  43.296 10.067 46.056 11.317 ;
     RECT  66.72 10.981 71.352 11.509 ;
     RECT  72.48 9.493 72.912 11.509 ;
     RECT  87.696 11.173 100.344 11.651 ;
     RECT  78 11.125 80.856 11.795 ;
     RECT  52.992 9.349 57.72 11.797 ;
     RECT  83.4 10.885 84.168 11.843 ;
     RECT  85.344 10.885 86.472 11.987 ;
     RECT  38.112 9.683 42.168 11.989 ;
     RECT  43.2 11.317 46.056 11.989 ;
     RECT  38.112 11.989 46.056 12.035 ;
     RECT  66.72 11.509 72.912 12.035 ;
     RECT  24 11.027 26.904 12.181 ;
     RECT  28.512 10.597 35.112 12.323 ;
     RECT  78 11.795 78.312 12.469 ;
     RECT  85.344 11.987 85.416 12.469 ;
     RECT  48 11.221 48.024 12.517 ;
     RECT  49.536 11.365 49.56 12.517 ;
     RECT  59.856 8.051 63.864 12.517 ;
     RECT  77.76 12.469 78.312 12.517 ;
     RECT  23.904 12.181 26.904 12.563 ;
     RECT  48 12.517 49.56 12.563 ;
     RECT  70.32 12.035 72.912 12.563 ;
     RECT  72.6 12.563 72.912 12.757 ;
     RECT  73.968 8.579 76.44 12.757 ;
     RECT  48.24 12.563 49.56 12.803 ;
     RECT  70.32 12.563 71.352 12.803 ;
     RECT  1.776 8.291 2.856 12.901 ;
     RECT  4.176 6.851 8.112 12.901 ;
     RECT  59.52 12.517 63.864 12.949 ;
     RECT  59.232 12.949 63.864 12.995 ;
     RECT  13.2 10.883 16.728 13.045 ;
     RECT  28.992 12.323 35.112 13.045 ;
     RECT  36.288 10.259 36.312 13.045 ;
     RECT  82.368 10.883 82.392 13.045 ;
     RECT  83.4 11.843 83.712 13.045 ;
     RECT  60.576 12.995 63.864 13.093 ;
     RECT  52.992 11.797 58.104 13.139 ;
     RECT  102.864 9.731 105.312 13.139 ;
     RECT  96.576 11.651 100.344 13.141 ;
     RECT  9.456 12.853 9.48 13.331 ;
     RECT  51 8.195 51.672 13.573 ;
     RECT  52.992 13.139 57.288 13.573 ;
     RECT  72.6 12.757 76.44 13.573 ;
     RECT  85.008 12.469 85.416 13.573 ;
     RECT  1.776 12.901 8.112 13.619 ;
     RECT  48.24 12.803 49.176 13.619 ;
     RECT  12.432 13.045 16.728 13.621 ;
     RECT  4.032 13.619 8.112 13.667 ;
     RECT  12 13.621 16.728 13.667 ;
     RECT  17.712 10.883 20.376 13.715 ;
     RECT  4.176 13.667 8.112 13.957 ;
     RECT  43.536 12.035 46.056 14.101 ;
     RECT  71.328 12.803 71.352 14.149 ;
     RECT  72.48 13.573 76.44 14.149 ;
     RECT  28.992 13.045 36.312 14.197 ;
     RECT  71.328 14.149 76.44 14.197 ;
     RECT  77.664 12.517 78.312 14.197 ;
     RECT  84.912 13.573 85.416 14.291 ;
     RECT  96.576 13.141 100.68 14.291 ;
     RECT  99.216 14.291 100.68 14.339 ;
     RECT  51 13.573 57.288 14.435 ;
     RECT  51 14.435 51.864 14.485 ;
     RECT  22.848 11.027 22.872 14.677 ;
     RECT  24 12.563 26.904 14.677 ;
     RECT  38.112 12.035 42.408 14.771 ;
     RECT  52.992 14.435 57.288 14.773 ;
     RECT  4.176 13.957 9.048 14.867 ;
     RECT  12 13.667 12.024 14.867 ;
     RECT  13.2 13.667 16.728 14.867 ;
     RECT  28.992 14.197 36.984 14.867 ;
     RECT  71.328 14.197 78.312 14.867 ;
     RECT  42.048 14.771 42.168 14.915 ;
     RECT  43.536 14.101 46.2 14.917 ;
     RECT  101.712 10.355 101.736 14.917 ;
     RECT  103.44 13.139 105.312 14.917 ;
     RECT  34.704 14.867 36.984 14.963 ;
     RECT  21.696 13.669 21.72 15.155 ;
     RECT  34.8 14.963 36.984 15.203 ;
     RECT  22.848 14.677 26.904 15.251 ;
     RECT  101.712 14.917 105.312 15.347 ;
     RECT  48.384 13.619 49.176 15.397 ;
     RECT  10.848 14.869 10.872 15.443 ;
     RECT  59.232 12.995 59.544 15.443 ;
     RECT  85.344 14.291 85.416 15.445 ;
     RECT  22.848 15.251 24.408 15.491 ;
     RECT  85.344 15.445 85.464 15.491 ;
     RECT  1.776 13.619 2.856 15.589 ;
     RECT  65.136 8.003 65.544 15.589 ;
     RECT  66.72 12.035 69.192 15.589 ;
     RECT  86.448 11.987 86.472 15.637 ;
     RECT  48.384 15.397 49.56 15.731 ;
     RECT  17.712 13.715 19.608 15.829 ;
     RECT  28.992 14.867 33.72 15.829 ;
     RECT  4.656 14.867 8.664 16.019 ;
     RECT  65.136 15.589 69.192 16.019 ;
     RECT  4.656 16.019 8.112 16.115 ;
     RECT  17.712 15.829 20.472 16.259 ;
     RECT  86.448 15.637 86.664 16.259 ;
     RECT  99.216 14.339 100.344 16.501 ;
     RECT  101.712 15.347 101.736 16.501 ;
     RECT  65.52 16.019 69.192 16.547 ;
     RECT  43.536 14.917 46.776 16.595 ;
     RECT  52.992 14.773 57.576 16.595 ;
     RECT  73.968 14.867 78.312 16.595 ;
     RECT  79.584 11.795 80.856 16.595 ;
     RECT  49.536 15.731 49.56 16.597 ;
     RECT  50.784 14.485 51.864 16.597 ;
     RECT  49.536 16.597 51.864 16.741 ;
     RECT  52.992 16.595 55.032 16.741 ;
     RECT  71.328 14.867 72.912 16.787 ;
     RECT  1.776 15.589 3.432 16.835 ;
     RECT  48.384 15.731 48.408 16.981 ;
     RECT  49.536 16.741 55.032 16.981 ;
     RECT  20.448 16.259 20.472 17.027 ;
     RECT  48.384 16.981 55.032 17.027 ;
     RECT  28.512 15.829 33.72 17.029 ;
     RECT  75.984 16.595 78.312 17.029 ;
     RECT  85.392 15.491 85.464 17.029 ;
     RECT  86.448 16.259 86.472 17.029 ;
     RECT  65.52 16.547 65.544 17.075 ;
     RECT  5.04 16.115 8.112 17.077 ;
     RECT  48.384 17.027 49.08 17.123 ;
     RECT  50.496 17.027 55.032 17.123 ;
     RECT  27.936 17.029 33.72 17.171 ;
     RECT  32.784 17.171 33.72 17.173 ;
     RECT  34.8 15.203 36.312 17.173 ;
     RECT  5.04 17.077 9.192 17.219 ;
     RECT  87.696 11.651 95.4 17.267 ;
     RECT  32.784 17.173 36.312 17.315 ;
     RECT  99.216 16.501 101.736 17.363 ;
     RECT  96.576 14.291 98.184 17.461 ;
     RECT  99.216 17.363 100.008 17.461 ;
     RECT  59.52 15.443 59.544 17.509 ;
     RECT  60.576 13.093 63.96 17.509 ;
     RECT  16.704 14.867 16.728 17.557 ;
     RECT  17.712 16.259 19.464 17.557 ;
     RECT  54 17.123 55.032 17.603 ;
     RECT  22.848 15.491 22.872 17.699 ;
     RECT  34.8 17.315 36.312 17.699 ;
     RECT  42.096 14.915 42.168 17.699 ;
     RECT  75.984 17.029 78.648 17.699 ;
     RECT  87.696 17.267 90.936 17.699 ;
     RECT  72.6 16.787 72.912 17.989 ;
     RECT  20.928 18.085 20.952 18.133 ;
     RECT  71.328 16.787 71.352 18.133 ;
     RECT  72.48 17.989 72.912 18.133 ;
     RECT  56.256 16.595 57.576 18.181 ;
     RECT  80.016 16.595 80.856 18.229 ;
     RECT  3.936 17.029 3.96 18.275 ;
     RECT  32.784 17.315 33.72 18.275 ;
     RECT  51 17.123 53.016 18.275 ;
     RECT  54.24 17.603 55.032 18.275 ;
     RECT  65.04 17.653 65.064 18.275 ;
     RECT  66.72 16.547 69.192 18.275 ;
     RECT  76.32 17.699 76.44 18.275 ;
     RECT  16.704 17.557 19.464 18.419 ;
     RECT  74.784 16.595 74.808 18.421 ;
     RECT  24 15.491 24.408 18.469 ;
     RECT  25.536 15.251 26.904 18.469 ;
     RECT  76.32 18.275 76.392 18.515 ;
     RECT  20.64 18.133 20.952 18.563 ;
     RECT  59.52 17.509 63.96 18.611 ;
     RECT  20.64 18.563 20.664 18.613 ;
     RECT  10.8 17.605 10.824 18.707 ;
     RECT  12 16.405 12.024 18.707 ;
     RECT  51 18.275 52.632 18.707 ;
     RECT  76.32 18.515 76.344 18.707 ;
     RECT  27.936 17.171 31.656 18.755 ;
     RECT  70.32 12.803 70.344 18.757 ;
     RECT  71.328 18.133 72.912 18.757 ;
     RECT  74.784 18.421 75.288 18.757 ;
     RECT  103.44 15.347 105.312 18.757 ;
     RECT  56.256 18.181 57.96 18.803 ;
     RECT  85.392 17.029 86.472 18.803 ;
     RECT  17.712 18.419 19.464 18.851 ;
     RECT  27.936 18.755 27.96 18.851 ;
     RECT  43.536 16.595 46.536 18.851 ;
     RECT  74.784 18.757 75.576 18.851 ;
     RECT  103.2 18.757 105.312 18.851 ;
     RECT  85.44 18.803 86.472 18.899 ;
     RECT  85.488 18.899 86.472 19.043 ;
     RECT  5.04 17.219 8.112 19.093 ;
     RECT  48.384 17.123 48.408 19.093 ;
     RECT  96.576 17.461 100.008 19.235 ;
     RECT  65.328 18.709 65.352 19.283 ;
     RECT  13.2 14.867 15.72 19.285 ;
     RECT  16.704 18.419 16.728 19.285 ;
     RECT  20.592 18.613 20.664 19.331 ;
     RECT  24 18.469 26.904 19.333 ;
     RECT  82.368 13.045 83.712 19.333 ;
     RECT  13.2 19.285 16.728 19.379 ;
     RECT  85.536 19.043 86.472 19.379 ;
     RECT  42.096 17.699 42.12 19.427 ;
     RECT  43.536 18.851 46.056 19.427 ;
     RECT  87.696 17.699 89.736 19.427 ;
     RECT  90.912 17.699 90.936 19.427 ;
     RECT  96.576 19.235 99.912 19.475 ;
     RECT  47.856 19.093 48.408 19.573 ;
     RECT  47.328 19.573 48.408 19.619 ;
     RECT  103.2 18.851 103.224 19.763 ;
     RECT  79.632 18.229 80.856 19.811 ;
     RECT  4.992 19.093 8.112 19.813 ;
     RECT  9.168 17.219 9.192 19.813 ;
     RECT  70.32 18.757 72.912 19.813 ;
     RECT  70.32 19.813 73.656 19.859 ;
     RECT  75.072 18.851 75.576 19.859 ;
     RECT  4.992 19.813 9.192 19.909 ;
     RECT  44.928 19.427 46.056 19.909 ;
     RECT  47.328 19.619 47.352 19.909 ;
     RECT  4.992 19.909 9.48 20.003 ;
     RECT  28.992 18.755 31.656 20.003 ;
     RECT  32.784 18.275 33.336 20.003 ;
     RECT  43.536 19.427 43.56 20.003 ;
     RECT  44.928 19.909 47.352 20.003 ;
     RECT  59.76 18.611 63.96 20.003 ;
     RECT  13.2 19.379 16.2 20.005 ;
     RECT  5.04 20.003 9.48 20.099 ;
     RECT  77.664 17.699 78.648 20.149 ;
     RECT  56.256 18.803 57.576 20.195 ;
     RECT  38.112 14.771 40.728 20.197 ;
     RECT  49.776 18.181 49.8 20.339 ;
     RECT  51 18.707 51.864 20.339 ;
     RECT  54.24 18.275 54.456 20.339 ;
     RECT  82.368 19.333 84.36 20.435 ;
     RECT  101.712 17.363 101.736 20.485 ;
     RECT  12.96 20.005 16.2 20.533 ;
     RECT  20.592 19.331 20.616 20.533 ;
     RECT  7.44 20.099 9.48 20.579 ;
     RECT  54.24 20.339 54.264 20.579 ;
     RECT  59.904 20.003 63.96 20.579 ;
     RECT  71.328 19.859 73.656 20.579 ;
     RECT  53.088 20.245 53.112 20.723 ;
     RECT  12.912 20.533 16.2 20.725 ;
     RECT  51 20.339 51.672 20.965 ;
     RECT  82.368 20.435 83.712 21.013 ;
     RECT  5.04 20.099 5.832 21.155 ;
     RECT  23.376 19.333 26.904 21.155 ;
     RECT  38.112 20.197 41.4 21.155 ;
     RECT  101.712 20.485 102.6 21.155 ;
     RECT  104.256 18.851 105.312 21.155 ;
     RECT  17.904 18.851 19.464 21.203 ;
     RECT  67.2 18.275 69.192 21.301 ;
     RECT  70.32 19.859 70.344 21.301 ;
     RECT  50.832 20.965 51.672 21.493 ;
     RECT  50.736 21.493 51.672 21.541 ;
     RECT  18.48 21.203 19.464 21.637 ;
     RECT  20.496 20.533 20.616 21.637 ;
     RECT  34.8 17.699 35.256 21.637 ;
     RECT  36.288 17.699 36.312 21.637 ;
     RECT  75.552 19.859 75.576 21.637 ;
     RECT  77.088 20.149 78.648 21.637 ;
     RECT  82.08 21.013 83.712 21.637 ;
     RECT  98.88 19.475 99.912 21.637 ;
     RECT  50.736 21.541 51.912 21.683 ;
     RECT  80.016 19.811 80.856 21.683 ;
     RECT  77.088 21.637 78.936 21.731 ;
     RECT  80.016 21.683 80.76 21.731 ;
     RECT  7.44 20.579 9.192 21.779 ;
     RECT  85.872 19.379 86.472 21.827 ;
     RECT  96.576 19.475 97.56 21.827 ;
     RECT  98.88 21.637 100.296 21.875 ;
     RECT  82.08 21.637 84.408 22.115 ;
     RECT  56.256 20.195 57.288 22.117 ;
     RECT  86.016 21.827 86.472 22.117 ;
     RECT  87.696 19.427 89.112 22.117 ;
     RECT  7.44 21.779 8.232 22.165 ;
     RECT  45.024 20.003 45.912 22.165 ;
     RECT  46.992 20.003 47.352 22.165 ;
     RECT  48.384 19.619 48.408 22.165 ;
     RECT  56.256 22.117 57.384 22.165 ;
     RECT  77.136 21.731 78.936 22.165 ;
     RECT  80.016 21.731 80.04 22.165 ;
     RECT  45.024 22.165 48.408 22.211 ;
     RECT  12.192 20.725 16.2 22.259 ;
     RECT  45.024 22.211 48.312 22.259 ;
     RECT  77.136 22.165 80.04 22.259 ;
     RECT  82.368 22.115 84.408 22.307 ;
     RECT  75.552 21.637 75.96 22.451 ;
     RECT  66.144 21.493 66.168 22.499 ;
     RECT  77.136 22.259 79.8 22.739 ;
     RECT  7.152 22.165 8.232 22.741 ;
     RECT  12.192 22.259 15.96 22.741 ;
     RECT  38.112 21.155 40.728 22.741 ;
     RECT  67.2 21.301 70.344 22.741 ;
     RECT  11.424 22.741 15.96 22.787 ;
     RECT  56.256 22.165 57.672 22.787 ;
     RECT  18.48 21.637 20.616 22.835 ;
     RECT  45.408 22.259 48.312 22.835 ;
     RECT  73.92 22.645 73.944 22.835 ;
     RECT  86.016 22.117 89.112 22.835 ;
     RECT  11.424 22.787 15.096 22.883 ;
     RECT  12.912 22.883 15.096 23.027 ;
     RECT  18.48 22.835 20.328 23.173 ;
     RECT  60.432 20.579 63.96 23.317 ;
     RECT  92.112 17.267 95.4 23.317 ;
     RECT  71.328 20.579 72.912 23.365 ;
     RECT  6.864 22.741 8.232 23.411 ;
     RECT  21.648 21.781 21.672 23.411 ;
     RECT  60.24 23.317 63.96 23.411 ;
     RECT  75.552 22.451 75.912 23.411 ;
     RECT  83.28 22.307 84.408 23.411 ;
     RECT  102.768 22.789 102.792 23.411 ;
     RECT  18.288 23.173 20.328 23.507 ;
     RECT  45.408 22.835 47.688 23.603 ;
     RECT  18.384 23.507 20.328 23.795 ;
     RECT  24 21.155 26.904 23.845 ;
     RECT  99.6 21.875 100.296 23.845 ;
     RECT  45.408 23.603 47.256 23.891 ;
     RECT  67.008 22.741 70.344 23.893 ;
     RECT  71.328 23.365 73.416 23.893 ;
     RECT  83.28 23.411 83.712 23.893 ;
     RECT  86.448 22.835 89.112 23.893 ;
     RECT  5.04 21.155 5.64 24.085 ;
     RECT  5.04 24.085 6.312 24.131 ;
     RECT  67.008 23.893 73.416 24.131 ;
     RECT  90.336 22.165 90.36 24.131 ;
     RECT  9.504 23.365 9.528 24.227 ;
     RECT  78 22.739 79.8 24.277 ;
     RECT  92.112 23.317 95.592 24.277 ;
     RECT  60.24 23.411 63.288 24.323 ;
     RECT  50.832 21.683 51.912 24.325 ;
     RECT  85.536 23.893 89.112 24.419 ;
     RECT  97.536 21.827 97.56 24.469 ;
     RECT  99.6 23.845 100.488 24.515 ;
     RECT  60.24 24.323 63.048 24.563 ;
     RECT  92.016 24.277 95.592 24.611 ;
     RECT  11.424 22.883 11.448 24.659 ;
     RECT  71.328 24.131 73.416 24.659 ;
     RECT  97.008 24.469 97.56 24.757 ;
     RECT  13.008 23.027 15.096 24.805 ;
     RECT  50.784 24.325 51.912 24.899 ;
     RECT  97.008 24.757 97.608 24.899 ;
     RECT  60.24 24.563 62.76 24.947 ;
     RECT  97.008 24.899 97.56 24.949 ;
     RECT  13.008 24.805 15.912 24.995 ;
     RECT  58.416 23.989 58.44 25.045 ;
     RECT  82.656 23.893 83.712 25.045 ;
     RECT  48.72 24.469 48.744 25.091 ;
     RECT  53.424 23.893 53.448 25.091 ;
     RECT  82.656 25.045 84.36 25.091 ;
     RECT  86.448 24.419 89.112 25.091 ;
     RECT  96.864 24.949 97.56 25.091 ;
     RECT  99.6 24.515 100.296 25.093 ;
     RECT  18.384 23.795 20.184 25.139 ;
     RECT  24 23.845 27.384 25.139 ;
     RECT  58.416 25.045 58.632 25.139 ;
     RECT  98.832 25.093 100.296 25.139 ;
     RECT  22.8 23.317 22.824 25.187 ;
     RECT  92.016 24.611 95.4 25.187 ;
     RECT  42.768 24.517 42.792 25.283 ;
     RECT  34.8 21.637 36.312 25.285 ;
     RECT  50.784 24.899 51.672 25.333 ;
     RECT  28.992 20.003 30.84 25.525 ;
     RECT  34.8 25.285 37.08 25.573 ;
     RECT  45.6 23.891 47.256 25.573 ;
     RECT  45.024 25.573 47.256 25.715 ;
     RECT  58.608 25.139 58.632 25.715 ;
     RECT  97.008 25.091 97.56 25.715 ;
     RECT  86.928 25.091 89.112 25.765 ;
     RECT  28.992 25.525 31.128 25.861 ;
     RECT  77.088 24.277 79.8 26.051 ;
     RECT  54.096 25.765 54.12 26.197 ;
     RECT  28.272 25.861 31.128 26.243 ;
     RECT  34.368 25.573 37.08 26.243 ;
     RECT  38.112 22.741 41.64 26.243 ;
     RECT  64.848 24.901 64.872 26.243 ;
     RECT  67.008 24.131 70.344 26.243 ;
     RECT  83.28 25.091 84.36 26.243 ;
     RECT  6.288 24.131 6.312 26.291 ;
     RECT  28.272 26.243 29.832 26.291 ;
     RECT  60.24 24.947 60.6 26.437 ;
     RECT  36.288 26.243 37.08 26.483 ;
     RECT  97.44 25.715 97.56 26.531 ;
     RECT  50.256 25.333 51.672 26.579 ;
     RECT  45.024 25.715 46.152 26.627 ;
     RECT  86.928 25.765 89.256 26.725 ;
     RECT  105 21.155 105.312 26.725 ;
     RECT  13.008 24.995 15.432 26.771 ;
     RECT  85.44 26.197 85.464 26.773 ;
     RECT  45.024 26.627 46.104 26.819 ;
     RECT  71.328 24.659 73.032 26.819 ;
     RECT  81.024 24.469 81.048 26.819 ;
     RECT  83.28 26.243 83.712 26.819 ;
     RECT  7.8 23.411 8.232 26.869 ;
     RECT  9.936 26.821 9.96 26.869 ;
     RECT  28.272 26.291 29.712 26.915 ;
     RECT  56.256 22.787 57.384 26.917 ;
     RECT  78 26.051 79.8 27.107 ;
     RECT  92.112 25.187 95.4 27.107 ;
     RECT  98.832 25.139 100.008 27.155 ;
     RECT  84.816 26.773 85.464 27.251 ;
     RECT  7.8 26.869 9.96 27.301 ;
     RECT  47.232 25.715 47.256 27.301 ;
     RECT  52.704 25.861 52.728 27.301 ;
     RECT  54.096 26.197 54.456 27.301 ;
     RECT  34.368 26.243 35.112 27.347 ;
     RECT  38.112 26.243 40.728 27.395 ;
     RECT  52.704 27.301 54.456 27.395 ;
     RECT  93.84 27.107 95.4 27.395 ;
     RECT  104.304 26.725 105.312 27.395 ;
     RECT  6.816 27.301 9.96 27.587 ;
     RECT  59.424 26.437 60.6 27.587 ;
     RECT  32.16 25.333 32.184 27.589 ;
     RECT  86.928 26.725 90.216 27.635 ;
     RECT  18.432 25.139 20.184 27.637 ;
     RECT  31.92 27.589 32.184 27.877 ;
     RECT  33.312 20.003 33.336 27.877 ;
     RECT  31.92 27.877 33.336 27.923 ;
     RECT  64.8 26.629 64.824 27.923 ;
     RECT  16.512 27.877 16.536 27.925 ;
     RECT  1.776 16.835 2.856 27.971 ;
     RECT  24 25.139 26.904 27.971 ;
     RECT  16.512 27.925 17.448 28.211 ;
     RECT  55.44 26.917 57.384 28.211 ;
     RECT  83.4 26.819 83.712 28.213 ;
     RECT  22.176 26.197 22.2 28.403 ;
     RECT  36.288 26.483 36.312 28.405 ;
     RECT  30.768 27.301 30.792 28.451 ;
     RECT  18.432 27.637 20.52 28.453 ;
     RECT  74.208 28.357 74.232 28.499 ;
     RECT  13.008 26.771 15.096 28.501 ;
     RECT  45.6 26.819 46.104 28.501 ;
     RECT  6.816 27.587 9.144 28.547 ;
     RECT  71.328 26.819 72.912 28.547 ;
     RECT  92.112 27.107 92.328 28.547 ;
     RECT  94.08 27.395 95.4 28.547 ;
     RECT  5.04 24.131 5.064 28.549 ;
     RECT  50.88 26.579 51.672 28.597 ;
     RECT  17.424 28.211 17.448 28.739 ;
     RECT  47.232 27.301 47.928 28.787 ;
     RECT  5.04 28.549 5.544 28.789 ;
     RECT  18.432 28.453 20.568 28.837 ;
     RECT  32.16 27.923 32.472 28.933 ;
     RECT  18.432 28.837 21.096 28.979 ;
     RECT  33.744 27.925 33.768 28.979 ;
     RECT  53.088 27.395 54.456 28.981 ;
     RECT  4.992 28.789 5.544 29.027 ;
     RECT  2.16 27.971 2.856 29.029 ;
     RECT  7.392 28.547 9.144 29.029 ;
     RECT  44.784 28.501 46.104 29.029 ;
     RECT  86.928 27.635 89.256 29.029 ;
     RECT  44.784 29.029 46.728 29.075 ;
     RECT  47.904 28.787 47.928 29.075 ;
     RECT  13.008 28.501 16.008 29.123 ;
     RECT  56.256 28.211 57.384 29.123 ;
     RECT  86.928 29.029 90.072 29.219 ;
     RECT  67.2 26.243 70.344 29.221 ;
     RECT  31.92 28.933 32.472 29.269 ;
     RECT  31.632 29.269 32.472 29.411 ;
     RECT  36.288 28.405 37.08 29.461 ;
     RECT  78 27.107 78.312 29.461 ;
     RECT  94.2 28.547 95.4 29.509 ;
     RECT  50.112 28.597 51.672 29.555 ;
     RECT  13.008 29.123 15.096 29.605 ;
     RECT  36.288 29.461 37.128 29.653 ;
     RECT  38.112 27.395 38.136 29.653 ;
     RECT  12.576 29.605 15.096 29.699 ;
     RECT  24 27.971 26.184 29.699 ;
     RECT  36.288 29.653 38.136 29.699 ;
     RECT  39.312 27.395 40.728 29.699 ;
     RECT  56.256 29.123 57.336 29.699 ;
     RECT  88.128 29.219 90.072 29.699 ;
     RECT  5.04 29.027 5.544 29.747 ;
     RECT  67.2 29.221 70.44 29.747 ;
     RECT  75.552 23.411 75.576 29.747 ;
     RECT  18.432 28.979 20.568 29.795 ;
     RECT  36.48 29.699 38.136 29.795 ;
     RECT  88.128 29.699 89.256 29.891 ;
     RECT  28.992 26.915 29.712 29.989 ;
     RECT  83.28 28.213 83.712 30.133 ;
     RECT  7.392 29.029 9.192 30.181 ;
     RECT  97.536 26.531 97.56 30.181 ;
     RECT  45.6 29.075 46.728 30.275 ;
     RECT  50.88 29.555 51.672 30.275 ;
     RECT  67.2 29.747 70.344 30.275 ;
     RECT  79.776 27.107 79.8 30.275 ;
     RECT  86.928 29.219 86.952 30.275 ;
     RECT  94.2 29.509 95.784 30.275 ;
     RECT  31.632 29.411 32.232 30.323 ;
     RECT  7.296 30.181 9.192 30.371 ;
     RECT  2.16 29.029 3.672 30.565 ;
     RECT  28.848 29.989 29.712 30.611 ;
     RECT  60.24 27.587 60.6 30.613 ;
     RECT  34.8 27.347 35.112 30.661 ;
     RECT  72.096 28.547 72.912 30.757 ;
     RECT  10.848 30.661 10.872 30.803 ;
     RECT  67.2 30.275 69.768 30.803 ;
     RECT  84.816 27.251 84.84 30.803 ;
     RECT  53.088 28.981 54.696 30.851 ;
     RECT  82.08 29.605 82.104 30.851 ;
     RECT  18.432 29.795 20.184 30.899 ;
     RECT  67.2 30.803 69 30.899 ;
     RECT  18.6 30.899 20.184 30.947 ;
     RECT  7.296 30.371 8.112 30.949 ;
     RECT  45.6 30.275 46.248 30.949 ;
     RECT  50.88 30.275 51.312 30.949 ;
     RECT  83.232 30.133 83.712 30.949 ;
     RECT  59.328 30.613 60.6 30.997 ;
     RECT  61.584 24.947 62.76 30.997 ;
     RECT  12.576 29.699 13.512 31.141 ;
     RECT  12.576 31.141 13.704 31.187 ;
     RECT  9.168 30.371 9.192 31.189 ;
     RECT  26.16 29.699 26.184 31.285 ;
     RECT  78 29.461 78.408 31.285 ;
     RECT  97.536 30.181 98.376 31.285 ;
     RECT  99.6 27.155 100.008 31.285 ;
     RECT  94.2 30.275 95.4 31.331 ;
     RECT  72.096 30.757 73.032 31.333 ;
     RECT  74.112 30.709 74.136 31.333 ;
     RECT  36.48 29.795 38.088 31.379 ;
     RECT  56.256 29.699 57.096 31.379 ;
     RECT  72.096 31.333 74.136 31.379 ;
     RECT  88.128 29.891 89.112 31.379 ;
     RECT  59.328 30.997 62.76 31.427 ;
     RECT  2.16 30.565 3.96 31.523 ;
     RECT  5.04 29.747 5.064 31.523 ;
     RECT  83.184 30.949 83.712 31.523 ;
     RECT  59.328 31.427 62.28 31.525 ;
     RECT  34.128 30.661 35.112 31.619 ;
     RECT  31.92 30.323 32.232 31.717 ;
     RECT  59.232 31.525 62.28 31.763 ;
     RECT  6.816 30.949 8.112 31.811 ;
     RECT  22.704 29.461 22.728 31.861 ;
     RECT  31.584 31.717 32.232 31.907 ;
     RECT  36.48 31.379 37.128 31.907 ;
     RECT  18.6 30.947 19.272 31.909 ;
     RECT  2.16 31.523 3.672 31.955 ;
     RECT  13.056 31.187 13.704 31.955 ;
     RECT  24 29.699 25.032 31.955 ;
     RECT  26.16 31.285 26.664 31.955 ;
     RECT  45.216 30.949 46.248 31.955 ;
     RECT  50.736 30.949 51.312 31.955 ;
     RECT  94.2 31.331 94.968 31.955 ;
     RECT  97.536 31.285 100.008 31.955 ;
     RECT  101.712 21.155 101.736 32.005 ;
     RECT  42.96 28.741 42.984 32.053 ;
     RECT  53.088 30.851 54.12 32.147 ;
     RECT  101.712 32.005 102.648 32.147 ;
     RECT  17.76 31.909 19.272 32.197 ;
     RECT  40.08 29.699 40.512 32.339 ;
     RECT  53.136 32.147 54.12 32.339 ;
     RECT  47.664 31.957 47.88 32.387 ;
     RECT  26.64 31.955 26.664 32.437 ;
     RECT  96.528 32.389 96.552 32.437 ;
     RECT  97.536 31.955 98.376 32.437 ;
     RECT  103.632 31.957 103.656 32.437 ;
     RECT  2.304 31.955 3.672 32.483 ;
     RECT  49.536 31.285 49.56 32.483 ;
     RECT  59.232 31.763 62.232 32.483 ;
     RECT  65.28 31.285 65.304 32.483 ;
     RECT  56.256 31.379 56.712 32.485 ;
     RECT  10.944 31.765 10.968 32.531 ;
     RECT  88.512 31.379 89.112 32.531 ;
     RECT  103.632 32.437 103.752 32.531 ;
     RECT  103.728 32.531 103.752 32.579 ;
     RECT  17.76 32.197 19.656 32.723 ;
     RECT  9.168 31.189 9.72 32.915 ;
     RECT  84.72 32.053 84.744 32.917 ;
     RECT  22.416 31.861 22.776 32.963 ;
     RECT  9.552 32.915 9.72 33.013 ;
     RECT  13.2 31.955 13.512 33.013 ;
     RECT  31.968 31.907 32.232 33.013 ;
     RECT  86.784 32.053 86.808 33.059 ;
     RECT  96.528 32.437 98.376 33.061 ;
     RECT  99.456 31.955 100.008 33.061 ;
     RECT  17.76 32.723 19.272 33.107 ;
     RECT  28.992 30.611 29.712 33.107 ;
     RECT  36.48 31.907 36.504 33.107 ;
     RECT  42.864 32.053 42.984 33.107 ;
     RECT  54 32.339 54.12 33.107 ;
     RECT  72.096 31.379 73.224 33.107 ;
     RECT  96.528 33.061 100.008 33.107 ;
     RECT  56.256 32.485 57.048 33.157 ;
     RECT  17.76 33.107 18.912 33.299 ;
     RECT  72.6 33.107 73.224 33.299 ;
     RECT  84.72 32.917 84.84 33.299 ;
     RECT  61.8 32.483 62.232 33.493 ;
     RECT  13.2 33.013 13.608 33.589 ;
     RECT  5.904 33.157 5.928 33.683 ;
     RECT  7.536 31.811 8.112 33.683 ;
     RECT  13.2 33.589 14.568 33.683 ;
     RECT  24 31.955 24.84 33.683 ;
     RECT  56.256 33.157 57.336 33.683 ;
     RECT  61.8 33.493 62.664 33.731 ;
     RECT  9.552 33.013 9.912 33.779 ;
     RECT  26.64 32.437 27.24 33.779 ;
     RECT  2.304 32.483 3.24 33.827 ;
     RECT  34.8 31.619 35.112 34.117 ;
     RECT  54.096 33.107 54.12 34.117 ;
     RECT  56.4 33.683 57.336 34.165 ;
     RECT  22.752 32.963 22.776 34.259 ;
     RECT  67.2 30.899 68.952 34.259 ;
     RECT  94.2 31.955 94.92 34.259 ;
     RECT  98.352 33.107 100.008 34.259 ;
     RECT  101.712 32.147 101.736 34.259 ;
     RECT  42.864 33.107 42.888 34.403 ;
     RECT  70.224 32.341 70.248 34.403 ;
     RECT  47.856 32.387 47.88 34.451 ;
     RECT  9.696 33.779 9.912 34.643 ;
     RECT  67.2 34.259 68.904 34.645 ;
     RECT  59.232 32.483 60.696 34.691 ;
     RECT  66.816 34.645 68.904 34.741 ;
     RECT  63.12 34.117 63.144 34.787 ;
     RECT  59.232 34.691 60.456 34.835 ;
     RECT  66.72 34.741 68.904 34.835 ;
     RECT  84.96 33.925 84.984 34.835 ;
     RECT  2.4 33.827 3.24 34.931 ;
     RECT  26.64 33.779 26.664 35.029 ;
     RECT  103.488 33.589 103.512 35.077 ;
     RECT  105 27.395 105.312 35.077 ;
     RECT  51 31.955 51.312 35.269 ;
     RECT  94.2 34.259 94.512 35.269 ;
     RECT  83.232 31.523 83.712 35.363 ;
     RECT  92.304 28.547 92.328 35.363 ;
     RECT  99.456 34.259 100.008 35.363 ;
     RECT  14.544 33.683 14.568 35.555 ;
     RECT  94.2 35.269 94.632 35.797 ;
     RECT  7.8 33.683 8.112 35.845 ;
     RECT  24 33.683 24.504 35.845 ;
     RECT  29.4 33.107 29.712 35.845 ;
     RECT  96.528 33.107 96.888 35.845 ;
     RECT  9.696 34.643 9.72 35.939 ;
     RECT  48.96 34.741 48.984 35.939 ;
     RECT  54 34.117 54.12 35.939 ;
     RECT  77.616 31.285 78.408 35.939 ;
     RECT  83.28 35.363 83.712 35.939 ;
     RECT  50.88 35.269 51.312 35.987 ;
     RECT  66.72 34.835 68.136 35.987 ;
     RECT  77.616 35.939 78.312 36.181 ;
     RECT  94.2 35.797 94.92 36.229 ;
     RECT  59.712 34.835 60.456 36.275 ;
     RECT  93.408 36.229 94.92 36.275 ;
     RECT  45.6 31.955 46.248 36.325 ;
     RECT  18.6 33.299 18.912 36.373 ;
     RECT  34.8 34.117 35.208 36.421 ;
     RECT  26.208 35.029 26.664 36.515 ;
     RECT  31.248 33.013 32.232 36.515 ;
     RECT  77.568 36.181 78.312 36.515 ;
     RECT  98.352 34.259 98.376 36.515 ;
     RECT  103.488 35.077 105.312 36.515 ;
     RECT  29.184 35.845 29.712 36.563 ;
     RECT  29.4 36.563 29.712 36.661 ;
     RECT  75.216 35.317 75.24 36.755 ;
     RECT  56.4 34.165 57.48 36.899 ;
     RECT  96.528 35.845 97.368 36.997 ;
     RECT  17.616 36.373 18.912 37.043 ;
     RECT  59.712 36.275 60.168 37.043 ;
     RECT  7.68 35.845 8.112 37.045 ;
     RECT  24 35.845 25.128 37.091 ;
     RECT  43.296 36.421 43.32 37.091 ;
     RECT  44.88 36.325 46.248 37.091 ;
     RECT  87.168 36.421 87.192 37.189 ;
     RECT  86.64 37.189 87.192 37.235 ;
     RECT  93.408 36.275 94.512 37.283 ;
     RECT  99.456 35.363 99.912 37.429 ;
     RECT  26.64 36.515 26.664 37.573 ;
     RECT  52.992 35.845 53.016 37.621 ;
     RECT  29.4 36.661 30.264 37.667 ;
     RECT  45.504 37.091 46.248 37.667 ;
     RECT  67.2 35.987 68.136 37.667 ;
     RECT  94.032 37.283 94.512 37.667 ;
     RECT  96.528 36.997 98.088 37.667 ;
     RECT  7.68 37.045 8.376 37.859 ;
     RECT  20.112 36.325 20.136 37.859 ;
     RECT  7.68 37.859 8.112 37.955 ;
     RECT  48.576 36.421 48.6 38.005 ;
     RECT  56.4 36.899 56.712 38.101 ;
     RECT  72.6 33.299 72.912 38.149 ;
     RECT  99.456 37.429 100.392 38.243 ;
     RECT  31.248 36.515 31.992 38.291 ;
     RECT  59.712 37.043 59.736 38.389 ;
     RECT  59.712 38.389 59.832 38.435 ;
     RECT  80.496 37.573 80.52 38.435 ;
     RECT  72.48 38.149 72.912 38.531 ;
     RECT  99.6 38.243 100.392 38.675 ;
     RECT  88.8 32.531 89.112 38.677 ;
     RECT  31.632 38.291 31.992 38.723 ;
     RECT  45.504 37.667 45.912 38.723 ;
     RECT  18.6 37.043 18.912 38.725 ;
     RECT  77.616 36.515 78.312 38.771 ;
     RECT  16.32 38.149 16.344 38.819 ;
     RECT  26.64 37.573 27.192 38.819 ;
     RECT  52.8 37.621 53.016 38.819 ;
     RECT  94.08 37.667 94.512 38.819 ;
     RECT  42 38.005 42.024 38.963 ;
     RECT  96.528 37.667 97.368 38.963 ;
     RECT  59.808 38.435 59.832 39.061 ;
     RECT  86.64 37.235 86.664 39.203 ;
     RECT  77.712 38.771 78.312 39.251 ;
     RECT  24 37.091 24.312 39.253 ;
     RECT  48.384 38.005 48.6 39.253 ;
     RECT  98.4 38.149 98.424 39.253 ;
     RECT  102.96 38.533 102.984 39.253 ;
     RECT  97.68 39.253 98.424 39.299 ;
     RECT  102.96 39.253 103.176 39.299 ;
     RECT  31.632 38.723 31.656 39.347 ;
     RECT  87.984 38.677 89.112 39.347 ;
     RECT  21.936 36.949 21.96 39.349 ;
     RECT  75.264 38.389 75.288 39.395 ;
     RECT  54.096 35.939 54.12 39.493 ;
     RECT  59.808 39.061 60.696 39.635 ;
     RECT  56.4 38.101 57.288 39.731 ;
     RECT  18.6 38.725 19.56 39.779 ;
     RECT  10.32 37.909 10.344 39.877 ;
     RECT  10.32 39.877 10.872 39.923 ;
     RECT  48.192 39.253 48.6 39.923 ;
     RECT  54.096 39.493 54.696 39.923 ;
     RECT  96.528 38.963 96.552 39.923 ;
     RECT  103.152 39.299 103.176 39.923 ;
     RECT  21.936 39.349 22.776 40.019 ;
     RECT  33.648 39.301 33.672 40.019 ;
     RECT  97.68 39.299 97.704 40.261 ;
     RECT  23.904 39.253 24.312 40.355 ;
     RECT  7.8 37.955 8.112 40.405 ;
     RECT  10.848 39.923 10.872 40.405 ;
     RECT  13.2 33.683 13.512 40.405 ;
     RECT  27.168 38.819 27.192 40.405 ;
     RECT  51 35.987 51.312 40.405 ;
     RECT  88.8 39.347 89.112 40.405 ;
     RECT  37.056 39.301 37.08 40.451 ;
     RECT  80.208 39.253 80.232 40.451 ;
     RECT  2.4 34.931 2.712 40.453 ;
     RECT  24 40.355 24.312 40.453 ;
     RECT  90.912 37.573 90.936 40.453 ;
     RECT  59.808 39.635 59.832 40.499 ;
     RECT  63.792 39.877 63.816 40.499 ;
     RECT  61.8 33.731 62.112 40.549 ;
     RECT  10.848 40.405 11.064 40.835 ;
     RECT  56.4 39.731 56.712 40.885 ;
     RECT  50.592 40.405 51.312 40.933 ;
     RECT  52.992 38.819 53.016 40.933 ;
     RECT  97.68 40.261 97.8 40.933 ;
     RECT  99.6 38.675 99.912 40.933 ;
     RECT  1.776 40.453 2.712 40.981 ;
     RECT  13.2 40.405 14.328 40.981 ;
     RECT  16.704 40.597 16.728 40.981 ;
     RECT  18.6 39.779 18.912 40.981 ;
     RECT  21.936 40.019 22.392 40.981 ;
     RECT  24 40.453 24.792 40.981 ;
     RECT  34.8 36.421 35.688 40.981 ;
     RECT  40.2 32.339 40.512 40.981 ;
     RECT  45.6 38.723 45.912 40.981 ;
     RECT  48.576 39.923 48.6 40.981 ;
     RECT  55.824 40.885 56.712 40.981 ;
     RECT  67.2 37.667 67.848 40.981 ;
     RECT  69.504 39.829 69.528 40.981 ;
     RECT  78 39.251 78.312 40.981 ;
     RECT  83.4 35.939 83.712 40.981 ;
     RECT  88.512 40.405 89.112 40.981 ;
     RECT  90.528 40.453 90.936 40.981 ;
     RECT  92.544 40.405 92.568 40.981 ;
     RECT  94.2 38.819 94.512 40.981 ;
     RECT  97.392 40.933 97.8 40.981 ;
     RECT  104.256 36.515 105.312 40.981 ;
     RECT  21.552 40.981 22.392 41.029 ;
     RECT  27.168 40.405 28.008 41.029 ;
     RECT  29.4 37.667 29.712 41.029 ;
     RECT  69.168 40.981 70.392 41.029 ;
     RECT  39.696 40.981 40.512 41.049 ;
     RECT  55.44 40.981 56.712 41.049 ;
     RECT  61.488 40.549 62.112 41.049 ;
     RECT  72.6 38.531 72.912 41.049 ;
     RECT  88.128 40.981 89.112 41.049 ;
     RECT  99.408 40.933 99.912 41.049 ;
     RECT  103.44 40.981 105.312 41.049 ;
     RECT  1.776 40.981 3.816 41.063 ;
     RECT  7.8 40.405 8.664 41.063 ;
     RECT  13.2 40.981 16.728 41.063 ;
     RECT  18.6 40.981 20.376 41.063 ;
     RECT  24 40.981 25.176 41.063 ;
     RECT  27.168 41.029 29.712 41.063 ;
     RECT  34.032 40.981 36.072 41.063 ;
     RECT  39.696 41.049 40.32 41.063 ;
     RECT  45.6 40.981 46.152 41.063 ;
     RECT  61.488 41.049 61.92 41.063 ;
     RECT  72.6 41.049 72.72 41.063 ;
     RECT  78 40.981 79.272 41.063 ;
     RECT  83.4 40.981 84.12 41.063 ;
     RECT  99.408 41.049 99.72 41.063 ;
     RECT  103.44 41.049 105.12 41.063 ;
     RECT  90.528 40.981 94.68 41.171 ;
     RECT  67.2 40.981 67.944 41.173 ;
     RECT  24.768 41.063 25.176 41.557 ;
     RECT  35.664 41.063 36.072 41.557 ;
     RECT  54.096 39.923 54.12 41.557 ;
     RECT  58.272 40.741 58.296 41.557 ;
     RECT  63.888 40.981 64.728 41.557 ;
     RECT  78.816 41.063 79.272 41.557 ;
     RECT  80.832 40.981 80.856 41.557 ;
     RECT  82.032 40.981 82.056 41.557 ;
     RECT  85.296 40.981 85.32 41.557 ;
     RECT  69.168 41.029 70.776 41.605 ;
     RECT  71.952 41.557 72.408 41.605 ;
     RECT  5.424 36.949 5.448 42.133 ;
     RECT  6.624 40.933 6.648 42.133 ;
     RECT  11.04 40.835 11.064 42.133 ;
     RECT  13.872 41.063 16.728 42.133 ;
     RECT  21.552 41.029 22.776 42.133 ;
     RECT  30 41.557 30.024 42.133 ;
     RECT  31.248 40.981 31.272 42.133 ;
     RECT  39.696 41.063 39.72 42.133 ;
     RECT  41.328 41.605 41.352 42.133 ;
     RECT  43.728 40.981 43.752 42.133 ;
     RECT  48.192 40.981 49.416 42.133 ;
     RECT  50.592 40.933 53.016 42.133 ;
     RECT  54.096 41.557 54.264 42.133 ;
     RECT  55.44 41.049 56.664 42.133 ;
     RECT  57.84 41.557 58.296 42.133 ;
     RECT  61.488 41.063 61.512 42.133 ;
     RECT  63.504 41.557 64.728 42.133 ;
     RECT  69.168 41.605 72.408 42.133 ;
     RECT  75.216 40.981 75.24 42.133 ;
     RECT  77.232 41.557 77.256 42.133 ;
     RECT  78.816 41.557 80.856 42.133 ;
     RECT  84.096 41.063 84.12 42.133 ;
     RECT  85.296 41.557 85.704 42.133 ;
     RECT  88.128 41.049 88.92 42.133 ;
     RECT  90.528 41.171 94.584 42.133 ;
     RECT  96.96 40.981 97.8 42.133 ;
     RECT  99.408 41.063 99.432 42.133 ;
     RECT  103.44 41.063 104.28 42.133 ;
     RECT  5.424 42.133 6.648 42.181 ;
     RECT  8.64 41.063 8.664 42.181 ;
     RECT  13.056 42.133 17.544 42.181 ;
     RECT  19.104 41.063 20.376 42.181 ;
     RECT  21.552 42.133 23.592 42.181 ;
     RECT  27.168 41.063 28.44 42.181 ;
     RECT  30 42.133 32.04 42.181 ;
     RECT  34.032 41.063 34.056 42.181 ;
     RECT  35.664 41.557 37.32 42.181 ;
     RECT  38.88 42.133 41.352 42.181 ;
     RECT  42.528 42.133 42.552 42.181 ;
     RECT  45.744 41.063 46.152 42.181 ;
     RECT  47.76 42.133 53.016 42.181 ;
     RECT  54.096 42.133 58.296 42.181 ;
     RECT  59.472 41.557 59.496 42.181 ;
     RECT  61.056 42.133 61.512 42.181 ;
     RECT  62.784 42.133 65.544 42.181 ;
     RECT  67.152 41.173 67.944 42.181 ;
     RECT  69.168 42.133 73.224 42.181 ;
     RECT  84.096 42.133 85.704 42.181 ;
     RECT  88.128 42.133 94.584 42.181 ;
     RECT  96.576 42.133 99.432 42.181 ;
     RECT  100.608 42.133 100.632 42.181 ;
     RECT  34.032 42.181 42.552 42.757 ;
     RECT  77.232 42.133 80.856 42.853 ;
     RECT  76.8 42.853 80.856 42.901 ;
     RECT  82.032 41.557 82.872 42.901 ;
     RECT  84.096 42.181 86.52 42.901 ;
     RECT  96.576 42.181 101.448 42.901 ;
     RECT  1.776 41.063 2.184 42.949 ;
     RECT  3.408 41.063 3.816 42.949 ;
     RECT  45.744 42.181 65.928 42.949 ;
     RECT  67.152 42.181 73.224 42.949 ;
     RECT  74.784 42.133 75.24 42.949 ;
     RECT  76.8 42.901 86.52 42.949 ;
     RECT  87.696 42.181 94.584 42.949 ;
     RECT  96.576 42.901 101.832 42.949 ;
     RECT  103.44 42.133 104.664 42.949 ;
     RECT  1.776 42.949 3.816 42.997 ;
     RECT  12.24 42.181 17.544 42.997 ;
     RECT  18.72 42.181 23.592 42.997 ;
     RECT  1.392 42.997 3.816 43.045 ;
     RECT  4.992 42.181 6.648 43.045 ;
     RECT  7.824 42.181 8.664 43.045 ;
     RECT  10.224 42.133 11.064 43.045 ;
     RECT  12.24 42.997 23.592 43.045 ;
     RECT  24.768 41.557 25.608 43.045 ;
     RECT  27.168 42.181 32.04 43.045 ;
     RECT  33.264 42.757 42.552 43.045 ;
     RECT  43.728 42.133 44.568 43.045 ;
     RECT  45.744 42.949 104.664 43.045 ;
     RECT  1.392 43.045 104.664 43.116 ;
     RECT  1.416 43.116 1.776 43.152 ;
     RECT  1.8 43.116 2.16 43.152 ;
     RECT  2.184 43.116 2.592 43.152 ;
     RECT  2.616 43.116 2.976 43.152 ;
     RECT  3 43.116 3.408 43.152 ;
     RECT  3.432 43.116 3.792 43.152 ;
     RECT  3.816 43.116 4.176 43.152 ;
     RECT  4.2 43.116 4.608 43.152 ;
     RECT  4.632 43.116 4.992 43.152 ;
     RECT  5.016 43.116 5.424 43.152 ;
     RECT  5.448 43.116 5.808 43.152 ;
     RECT  5.832 43.116 6.192 43.152 ;
     RECT  6.216 43.116 6.624 43.152 ;
     RECT  6.648 43.116 7.008 43.152 ;
     RECT  7.032 43.116 7.44 43.152 ;
     RECT  7.464 43.116 7.824 43.152 ;
     RECT  7.848 43.116 8.208 43.152 ;
     RECT  8.232 43.116 8.64 43.152 ;
     RECT  8.664 43.116 9.024 43.152 ;
     RECT  9.048 43.116 9.456 43.152 ;
     RECT  9.48 43.116 9.84 43.152 ;
     RECT  9.864 43.116 10.224 43.152 ;
     RECT  10.248 43.116 10.656 43.152 ;
     RECT  10.68 43.116 11.04 43.152 ;
     RECT  11.064 43.116 11.472 43.152 ;
     RECT  11.496 43.116 11.856 43.152 ;
     RECT  11.88 43.116 12.24 43.152 ;
     RECT  12.264 43.116 12.672 43.152 ;
     RECT  12.696 43.116 13.056 43.152 ;
     RECT  13.08 43.116 13.488 43.152 ;
     RECT  13.512 43.116 13.872 43.152 ;
     RECT  13.896 43.116 14.304 43.152 ;
     RECT  14.328 43.116 14.688 43.152 ;
     RECT  14.712 43.116 15.072 43.152 ;
     RECT  15.096 43.116 15.504 43.152 ;
     RECT  15.528 43.116 15.888 43.152 ;
     RECT  15.912 43.116 16.32 43.152 ;
     RECT  16.344 43.116 16.704 43.152 ;
     RECT  16.728 43.116 17.088 43.152 ;
     RECT  17.112 43.116 17.52 43.152 ;
     RECT  17.544 43.116 17.904 43.152 ;
     RECT  17.928 43.116 18.336 43.152 ;
     RECT  18.36 43.116 18.72 43.152 ;
     RECT  18.744 43.116 19.104 43.152 ;
     RECT  19.128 43.116 19.536 43.152 ;
     RECT  19.56 43.116 19.92 43.152 ;
     RECT  19.944 43.116 20.352 43.152 ;
     RECT  20.376 43.116 20.736 43.152 ;
     RECT  20.76 43.116 21.12 43.152 ;
     RECT  21.144 43.116 21.552 43.152 ;
     RECT  21.576 43.116 21.936 43.152 ;
     RECT  21.96 43.116 22.368 43.152 ;
     RECT  22.392 43.116 22.752 43.152 ;
     RECT  22.776 43.116 23.136 43.152 ;
     RECT  23.16 43.116 23.568 43.152 ;
     RECT  23.592 43.116 23.952 43.152 ;
     RECT  23.976 43.116 24.384 43.152 ;
     RECT  24.408 43.116 24.768 43.152 ;
     RECT  24.792 43.116 25.152 43.152 ;
     RECT  25.176 43.116 25.584 43.152 ;
     RECT  25.608 43.116 25.968 43.152 ;
     RECT  25.992 43.116 26.4 43.152 ;
     RECT  26.424 43.116 26.784 43.152 ;
     RECT  26.808 43.116 27.168 43.152 ;
     RECT  27.192 43.116 27.6 43.152 ;
     RECT  27.624 43.116 27.984 43.152 ;
     RECT  28.008 43.116 28.416 43.152 ;
     RECT  28.44 43.116 28.8 43.152 ;
     RECT  28.824 43.116 29.184 43.152 ;
     RECT  29.208 43.116 29.616 43.152 ;
     RECT  29.64 43.116 30 43.152 ;
     RECT  30.024 43.116 30.432 43.152 ;
     RECT  30.456 43.116 30.816 43.152 ;
     RECT  30.84 43.116 31.248 43.152 ;
     RECT  31.272 43.116 31.632 43.152 ;
     RECT  31.656 43.116 32.016 43.152 ;
     RECT  32.04 43.116 32.448 43.152 ;
     RECT  32.472 43.116 32.832 43.152 ;
     RECT  32.856 43.116 33.264 43.152 ;
     RECT  33.288 43.116 33.648 43.152 ;
     RECT  33.672 43.116 34.032 43.152 ;
     RECT  34.056 43.116 34.464 43.152 ;
     RECT  34.488 43.116 34.848 43.152 ;
     RECT  34.872 43.116 35.28 43.152 ;
     RECT  35.304 43.116 35.664 43.152 ;
     RECT  35.688 43.116 36.048 43.152 ;
     RECT  36.072 43.116 36.48 43.152 ;
     RECT  36.504 43.116 36.864 43.152 ;
     RECT  36.888 43.116 37.296 43.152 ;
     RECT  37.32 43.116 37.68 43.152 ;
     RECT  37.704 43.116 38.064 43.152 ;
     RECT  38.088 43.116 38.496 43.152 ;
     RECT  38.52 43.116 38.88 43.152 ;
     RECT  38.904 43.116 39.312 43.152 ;
     RECT  39.336 43.116 39.696 43.152 ;
     RECT  39.72 43.116 40.08 43.152 ;
     RECT  40.104 43.116 40.512 43.152 ;
     RECT  40.536 43.116 40.896 43.152 ;
     RECT  40.92 43.116 41.328 43.152 ;
     RECT  41.352 43.116 41.712 43.152 ;
     RECT  41.736 43.116 42.096 43.152 ;
     RECT  42.12 43.116 42.528 43.152 ;
     RECT  42.552 43.116 42.912 43.152 ;
     RECT  42.936 43.116 43.344 43.152 ;
     RECT  43.368 43.116 43.728 43.152 ;
     RECT  43.752 43.116 44.112 43.152 ;
     RECT  44.136 43.116 44.544 43.152 ;
     RECT  44.568 43.116 44.928 43.152 ;
     RECT  44.952 43.116 45.36 43.152 ;
     RECT  45.384 43.116 45.744 43.152 ;
     RECT  45.768 43.116 46.128 43.152 ;
     RECT  46.152 43.116 46.56 43.152 ;
     RECT  46.584 43.116 46.944 43.152 ;
     RECT  46.968 43.116 47.376 43.152 ;
     RECT  47.4 43.116 47.76 43.152 ;
     RECT  47.784 43.116 48.192 43.152 ;
     RECT  48.216 43.116 48.576 43.152 ;
     RECT  48.6 43.116 48.96 43.152 ;
     RECT  48.984 43.116 49.392 43.152 ;
     RECT  49.416 43.116 49.776 43.152 ;
     RECT  49.8 43.116 50.208 43.152 ;
     RECT  50.232 43.116 50.592 43.152 ;
     RECT  50.616 43.116 50.976 43.152 ;
     RECT  51 43.116 51.408 43.152 ;
     RECT  51.432 43.116 51.792 43.152 ;
     RECT  51.816 43.116 52.224 43.152 ;
     RECT  52.248 43.116 52.608 43.152 ;
     RECT  52.632 43.116 52.992 43.152 ;
     RECT  53.016 43.116 53.424 43.152 ;
     RECT  53.448 43.116 53.808 43.152 ;
     RECT  53.832 43.116 54.24 43.152 ;
     RECT  54.264 43.116 54.624 43.152 ;
     RECT  54.648 43.116 55.008 43.152 ;
     RECT  55.032 43.116 55.44 43.152 ;
     RECT  55.464 43.116 55.824 43.152 ;
     RECT  55.848 43.116 56.256 43.152 ;
     RECT  56.28 43.116 56.64 43.152 ;
     RECT  56.664 43.116 57.024 43.152 ;
     RECT  57.048 43.116 57.456 43.152 ;
     RECT  57.48 43.116 57.84 43.152 ;
     RECT  57.864 43.116 58.272 43.152 ;
     RECT  58.296 43.116 58.656 43.152 ;
     RECT  58.68 43.116 59.04 43.152 ;
     RECT  59.064 43.116 59.472 43.152 ;
     RECT  59.496 43.116 59.856 43.152 ;
     RECT  59.88 43.116 60.288 43.152 ;
     RECT  60.312 43.116 60.672 43.152 ;
     RECT  60.696 43.116 61.056 43.152 ;
     RECT  61.08 43.116 61.488 43.152 ;
     RECT  61.512 43.116 61.872 43.152 ;
     RECT  61.896 43.116 62.304 43.152 ;
     RECT  62.328 43.116 62.688 43.152 ;
     RECT  62.712 43.116 63.072 43.152 ;
     RECT  63.096 43.116 63.504 43.152 ;
     RECT  63.528 43.116 63.888 43.152 ;
     RECT  63.912 43.116 64.32 43.152 ;
     RECT  64.344 43.116 64.704 43.152 ;
     RECT  64.728 43.116 65.136 43.152 ;
     RECT  65.16 43.116 65.52 43.152 ;
     RECT  65.544 43.116 65.904 43.152 ;
     RECT  65.928 43.116 66.336 43.152 ;
     RECT  66.36 43.116 66.72 43.152 ;
     RECT  66.744 43.116 67.152 43.152 ;
     RECT  67.176 43.116 67.536 43.152 ;
     RECT  67.56 43.116 67.92 43.152 ;
     RECT  67.944 43.116 68.352 43.152 ;
     RECT  68.376 43.116 68.736 43.152 ;
     RECT  68.76 43.116 69.168 43.152 ;
     RECT  69.192 43.116 69.552 43.152 ;
     RECT  69.576 43.116 69.936 43.152 ;
     RECT  69.96 43.116 70.368 43.152 ;
     RECT  70.392 43.116 70.752 43.152 ;
     RECT  70.776 43.116 71.184 43.152 ;
     RECT  71.208 43.116 71.568 43.152 ;
     RECT  71.592 43.116 71.952 43.152 ;
     RECT  71.976 43.116 72.384 43.152 ;
     RECT  72.408 43.116 72.768 43.152 ;
     RECT  72.792 43.116 73.2 43.152 ;
     RECT  73.224 43.116 73.584 43.152 ;
     RECT  73.608 43.116 73.968 43.152 ;
     RECT  73.992 43.116 74.4 43.152 ;
     RECT  74.424 43.116 74.784 43.152 ;
     RECT  74.808 43.116 75.216 43.152 ;
     RECT  75.24 43.116 75.6 43.152 ;
     RECT  75.624 43.116 75.984 43.152 ;
     RECT  76.008 43.116 76.416 43.152 ;
     RECT  76.44 43.116 76.8 43.152 ;
     RECT  76.824 43.116 77.232 43.152 ;
     RECT  77.256 43.116 77.616 43.152 ;
     RECT  77.64 43.116 78 43.152 ;
     RECT  78.024 43.116 78.432 43.152 ;
     RECT  78.456 43.116 78.816 43.152 ;
     RECT  78.84 43.116 79.248 43.152 ;
     RECT  79.272 43.116 79.632 43.152 ;
     RECT  79.656 43.116 80.016 43.152 ;
     RECT  80.04 43.116 80.448 43.152 ;
     RECT  80.472 43.116 80.832 43.152 ;
     RECT  80.856 43.116 81.264 43.152 ;
     RECT  81.288 43.116 81.648 43.152 ;
     RECT  81.672 43.116 82.032 43.152 ;
     RECT  82.056 43.116 82.464 43.152 ;
     RECT  82.488 43.116 82.848 43.152 ;
     RECT  82.872 43.116 83.28 43.152 ;
     RECT  83.304 43.116 83.664 43.152 ;
     RECT  83.688 43.116 84.096 43.152 ;
     RECT  84.12 43.116 84.48 43.152 ;
     RECT  84.504 43.116 84.864 43.152 ;
     RECT  84.888 43.116 85.296 43.152 ;
     RECT  85.32 43.116 85.68 43.152 ;
     RECT  85.704 43.116 86.112 43.152 ;
     RECT  86.136 43.116 86.496 43.152 ;
     RECT  86.52 43.116 86.88 43.152 ;
     RECT  86.904 43.116 87.312 43.152 ;
     RECT  87.336 43.116 87.696 43.152 ;
     RECT  87.72 43.116 88.128 43.152 ;
     RECT  88.152 43.116 88.512 43.152 ;
     RECT  88.536 43.116 88.896 43.152 ;
     RECT  88.92 43.116 89.328 43.152 ;
     RECT  89.352 43.116 89.712 43.152 ;
     RECT  89.736 43.116 90.144 43.152 ;
     RECT  90.168 43.116 90.528 43.152 ;
     RECT  90.552 43.116 90.912 43.152 ;
     RECT  90.936 43.116 91.344 43.152 ;
     RECT  91.368 43.116 91.728 43.152 ;
     RECT  91.752 43.116 92.16 43.152 ;
     RECT  92.184 43.116 92.544 43.152 ;
     RECT  92.568 43.116 92.928 43.152 ;
     RECT  92.952 43.116 93.36 43.152 ;
     RECT  93.384 43.116 93.744 43.152 ;
     RECT  93.768 43.116 94.176 43.152 ;
     RECT  94.2 43.116 94.56 43.152 ;
     RECT  94.584 43.116 94.944 43.152 ;
     RECT  94.968 43.116 95.376 43.152 ;
     RECT  95.4 43.116 95.76 43.152 ;
     RECT  95.784 43.116 96.192 43.152 ;
     RECT  96.216 43.116 96.576 43.152 ;
     RECT  96.6 43.116 96.96 43.152 ;
     RECT  96.984 43.116 97.392 43.152 ;
     RECT  97.416 43.116 97.776 43.152 ;
     RECT  97.8 43.116 98.208 43.152 ;
     RECT  98.232 43.116 98.592 43.152 ;
     RECT  98.616 43.116 98.976 43.152 ;
     RECT  99 43.116 99.408 43.152 ;
     RECT  99.432 43.116 99.792 43.152 ;
     RECT  99.816 43.116 100.224 43.152 ;
     RECT  100.248 43.116 100.608 43.152 ;
     RECT  100.632 43.116 101.04 43.152 ;
     RECT  101.064 43.116 101.424 43.152 ;
     RECT  101.448 43.116 101.808 43.152 ;
     RECT  101.832 43.116 102.24 43.152 ;
     RECT  102.264 43.116 102.624 43.152 ;
     RECT  102.648 43.116 103.056 43.152 ;
     RECT  103.08 43.116 103.44 43.152 ;
     RECT  103.464 43.116 103.824 43.152 ;
     RECT  103.848 43.116 104.256 43.152 ;
     RECT  104.28 43.116 104.64 43.152 ;
     RECT  63.624 0.131 63.792 0.18 ;
     RECT  64.008 0.131 64.224 0.18 ;
     RECT  64.44 0.131 64.608 0.18 ;
     RECT  92.664 0.131 92.832 0.18 ;
     RECT  93.048 0.131 93.264 0.18 ;
     RECT  93.48 0.131 93.648 0.18 ;
     RECT  3.096 0.179 3.312 0.18 ;
     RECT  3.528 0.179 3.696 0.18 ;
     RECT  3.912 0.179 4.08 0.18 ;
     RECT  21.24 0.179 21.456 0.18 ;
     RECT  21.672 0.179 21.84 0.18 ;
     RECT  22.056 0.179 22.272 0.18 ;
     RECT  32.952 0.179 33.168 0.18 ;
     RECT  33.384 0.179 33.552 0.18 ;
     RECT  33.768 0.179 33.936 0.18 ;
     RECT  62.424 0.179 62.592 0.18 ;
     RECT  62.808 0.179 62.976 0.18 ;
     RECT  63.192 0.179 63.408 0.18 ;
     RECT  69.288 0.179 69.456 0.18 ;
     RECT  69.672 0.179 69.84 0.18 ;
     RECT  70.056 0.179 70.272 0.18 ;
     RECT  93.864 0.179 94.08 0.18 ;
     RECT  94.296 0.179 94.464 0.18 ;
     RECT  94.68 0.179 94.848 0.18 ;
     RECT  95.496 0.179 95.664 0.18 ;
     RECT  95.88 0.179 96.096 0.18 ;
     RECT  96.312 0.179 96.48 0.18 ;
     RECT  3 0.18 4.176 0.227 ;
     RECT  21.144 0.18 22.368 0.227 ;
     RECT  32.856 0.18 34.032 3.925 ;
     RECT  62.328 0.18 63.504 0.563 ;
     RECT  63.528 0.18 64.704 0.515 ;
     RECT  69.192 0.18 70.368 0.227 ;
     RECT  92.568 0.18 93.84 0.563 ;
     RECT  93.864 0.18 94.896 2.137 ;
     RECT  95.4 0.18 96.576 6.421 ;
     RECT  2.856 0.227 4.176 4.501 ;
     RECT  26.904 0.227 28.416 0.563 ;
     RECT  57.288 0.275 58.656 1.763 ;
     RECT  37.32 0.467 38.496 0.563 ;
     RECT  50.616 0.467 51.648 0.515 ;
     RECT  29.256 0.515 30.432 2.137 ;
     RECT  34.488 0.515 35.664 0.563 ;
     RECT  50.232 0.515 51.648 0.563 ;
     RECT  16.728 0.563 17.712 2.869 ;
     RECT  42.552 0.563 43.536 9.493 ;
     RECT  51.672 0.563 52.992 4.453 ;
     RECT  62.232 0.563 63.504 3.925 ;
     RECT  65.544 0.563 66.72 7.333 ;
     RECT  71.352 0.563 72.384 0.611 ;
     RECT  80.856 0.563 82.368 2.581 ;
     RECT  99 0.563 100.32 1.763 ;
     RECT  39.72 0.611 40.704 2.137 ;
     RECT  71.352 0.611 72.768 2.137 ;
     RECT  59.064 1.187 60.288 1.763 ;
     RECT  101.736 1.187 102.864 9.061 ;
     RECT  59.064 1.763 60.576 6.709 ;
     RECT  72.912 1.763 73.968 6.037 ;
     RECT  98.184 1.763 100.32 2.137 ;
     RECT  71.352 2.137 72.6 4.405 ;
     RECT  98.184 2.137 99.6 6.037 ;
     RECT  24.312 2.291 25.728 3.925 ;
     RECT  20.76 2.533 22.272 3.443 ;
     RECT  80.856 2.581 81.84 6.853 ;
     RECT  26.904 2.677 28.224 4.931 ;
     RECT  69.192 3.877 70.32 10.981 ;
     RECT  70.344 3.877 71.328 3.925 ;
     RECT  24.312 3.925 25.536 8.821 ;
     RECT  63.864 3.925 65.136 13.093 ;
     RECT  86.472 3.925 87.696 15.637 ;
     RECT  71.352 4.405 72.432 6.035 ;
     RECT  2.856 4.501 3.936 6.851 ;
     RECT  83.712 4.741 85.008 5.653 ;
     RECT  16.728 4.979 17.712 10.213 ;
     RECT  8.112 5.171 9.12 5.459 ;
     RECT  85.032 5.171 86.448 6.035 ;
     RECT  51.672 5.459 52.992 7.045 ;
     RECT  49.56 5.653 51 5.749 ;
     RECT  83.712 5.653 84.768 7.619 ;
     RECT  49.56 5.749 50.88 6.323 ;
     RECT  71.352 6.035 72.6 9.493 ;
     RECT  84.792 6.035 86.448 7.477 ;
     RECT  98.52 6.037 99.6 8.245 ;
     RECT  36.312 6.323 37.296 7.235 ;
     RECT  49.416 6.323 50.88 6.371 ;
     RECT  59.448 6.709 60.576 7.765 ;
     RECT  2.856 6.851 4.176 7.381 ;
     RECT  76.824 6.899 77.904 7.957 ;
     RECT  51.768 7.045 52.992 8.195 ;
     RECT  36.312 7.235 36.36 8.437 ;
     RECT  95.4 7.331 96.576 11.173 ;
     RECT  65.592 7.333 66.72 8.003 ;
     RECT  2.904 7.381 4.176 8.291 ;
     RECT  84.936 7.477 86.448 8.435 ;
     RECT  83.712 7.619 84.816 10.883 ;
     RECT  72.912 7.667 73.968 12.757 ;
     RECT  76.824 7.957 77.808 8.579 ;
     RECT  65.544 8.003 66.72 15.589 ;
     RECT  79.032 8.003 80.016 9.779 ;
     RECT  100.344 8.147 101.712 9.397 ;
     RECT  51.672 8.195 52.992 13.573 ;
     RECT  98.616 8.245 99.6 11.029 ;
     RECT  2.856 8.291 4.176 12.901 ;
     RECT  22.872 8.531 24 9.925 ;
     RECT  76.44 8.579 77.808 9.539 ;
     RECT  71.352 9.493 72.48 11.509 ;
     RECT  80.856 9.635 81.936 10.883 ;
     RECT  42.168 9.683 43.296 11.317 ;
     RECT  101.736 9.731 102.864 13.139 ;
     RECT  78.312 9.779 80.016 11.125 ;
     RECT  35.112 10.259 36.288 13.045 ;
     RECT  100.344 10.355 101.712 13.141 ;
     RECT  85.368 10.837 86.448 10.885 ;
     RECT  16.728 10.883 17.712 17.557 ;
     RECT  80.856 10.883 82.368 21.013 ;
     RECT  82.392 10.883 83.4 13.045 ;
     RECT  83.712 10.883 85.344 10.885 ;
     RECT  84.168 10.885 85.344 11.843 ;
     RECT  22.872 11.027 24 12.181 ;
     RECT  42.168 11.317 43.2 11.989 ;
     RECT  48.024 11.365 49.536 12.517 ;
     RECT  49.56 11.365 51 12.803 ;
     RECT  95.4 11.651 96.576 21.827 ;
     RECT  78.312 11.795 79.584 16.595 ;
     RECT  83.712 11.843 85.344 12.469 ;
     RECT  85.416 11.987 86.448 15.445 ;
     RECT  42.408 12.035 43.536 14.771 ;
     RECT  69.192 12.035 70.32 21.301 ;
     RECT  22.872 12.181 23.904 12.563 ;
     RECT  76.44 12.469 77.76 12.517 ;
     RECT  83.712 12.469 85.008 13.573 ;
     RECT  58.104 12.517 59.52 12.949 ;
     RECT  76.44 12.517 77.664 14.197 ;
     RECT  22.872 12.563 24 14.677 ;
     RECT  71.352 12.563 72.6 13.573 ;
     RECT  70.344 12.803 71.328 18.757 ;
     RECT  8.112 12.853 9.456 13.331 ;
     RECT  58.104 12.949 59.232 13.139 ;
     RECT  59.544 12.995 60.576 17.509 ;
     RECT  63.96 13.093 65.136 16.019 ;
     RECT  100.68 13.141 101.712 14.339 ;
     RECT  8.112 13.331 9.048 13.957 ;
     RECT  71.352 13.573 72.48 14.149 ;
     RECT  83.712 13.573 84.912 14.291 ;
     RECT  2.856 13.619 4.032 13.667 ;
     RECT  2.856 13.667 4.176 14.867 ;
     RECT  12.024 13.667 13.2 14.867 ;
     RECT  20.376 13.669 21.696 13.715 ;
     RECT  21.72 13.669 22.848 15.155 ;
     RECT  36.984 14.197 38.112 15.203 ;
     RECT  98.184 14.291 99.216 17.461 ;
     RECT  100.344 14.339 101.712 16.501 ;
     RECT  51.864 14.435 52.992 16.741 ;
     RECT  40.728 14.771 42.048 14.915 ;
     RECT  42.168 14.771 43.536 17.699 ;
     RECT  2.856 14.867 4.656 15.589 ;
     RECT  15.72 14.867 16.704 19.285 ;
     RECT  33.72 14.867 34.704 14.963 ;
     RECT  72.912 14.867 73.968 16.595 ;
     RECT  40.728 14.915 42.096 19.427 ;
     RECT  33.72 14.963 34.8 17.173 ;
     RECT  24.408 15.251 25.536 18.469 ;
     RECT  49.56 15.397 50.784 16.597 ;
     RECT  85.464 15.445 86.448 17.029 ;
     RECT  22.872 15.491 24 17.699 ;
     RECT  3.432 15.589 4.656 16.115 ;
     RECT  86.664 15.637 87.696 16.259 ;
     RECT  48.408 15.731 49.536 16.981 ;
     RECT  8.112 16.019 8.664 17.077 ;
     RECT  3.432 16.115 5.04 16.835 ;
     RECT  19.464 16.259 20.448 17.027 ;
     RECT  86.472 16.259 87.696 22.117 ;
     RECT  12.024 16.405 13.2 18.707 ;
     RECT  65.544 16.547 66.72 17.075 ;
     RECT  55.032 16.595 56.256 18.275 ;
     RECT  74.808 16.595 75.984 17.699 ;
     RECT  78.312 16.595 80.016 17.029 ;
     RECT  71.352 16.787 72.6 17.989 ;
     RECT  2.856 16.835 5.04 17.029 ;
     RECT  19.464 17.027 20.472 18.085 ;
     RECT  49.08 17.027 50.496 17.123 ;
     RECT  2.856 17.029 3.936 18.275 ;
     RECT  3.96 17.029 5.04 18.275 ;
     RECT  26.904 17.029 27.936 18.851 ;
     RECT  78.648 17.029 80.016 18.229 ;
     RECT  48.408 17.123 51 18.181 ;
     RECT  53.016 17.123 54 17.603 ;
     RECT  31.656 17.171 32.784 20.003 ;
     RECT  8.112 17.219 9.168 19.813 ;
     RECT  90.936 17.267 92.112 19.427 ;
     RECT  33.72 17.315 34.8 18.275 ;
     RECT  53.016 17.603 54.24 18.275 ;
     RECT  10.824 17.605 12 18.707 ;
     RECT  63.96 17.653 65.04 18.275 ;
     RECT  35.256 17.699 36.288 21.637 ;
     RECT  42.12 17.699 43.536 19.427 ;
     RECT  74.808 17.699 76.32 18.421 ;
     RECT  76.44 17.699 77.664 18.275 ;
     RECT  89.736 17.699 90.912 19.427 ;
     RECT  71.352 17.989 72.48 18.133 ;
     RECT  19.464 18.085 20.928 18.133 ;
     RECT  19.464 18.133 20.64 18.613 ;
     RECT  48.408 18.181 49.776 20.339 ;
     RECT  49.8 18.181 51 20.339 ;
     RECT  78.648 18.229 79.632 19.811 ;
     RECT  4.992 18.275 5.04 19.093 ;
     RECT  33.336 18.275 34.8 25.573 ;
     RECT  63.96 18.275 65.064 18.709 ;
     RECT  76.392 18.275 77.664 18.515 ;
     RECT  16.728 18.419 17.712 18.851 ;
     RECT  75.288 18.421 76.32 18.707 ;
     RECT  76.344 18.515 77.664 18.707 ;
     RECT  19.464 18.613 20.592 20.533 ;
     RECT  12.96 18.707 13.2 20.005 ;
     RECT  75.288 18.707 77.664 18.757 ;
     RECT  63.96 18.709 65.328 19.283 ;
     RECT  27.96 18.755 28.992 18.851 ;
     RECT  75.576 18.757 77.664 20.149 ;
     RECT  101.736 18.757 103.2 19.763 ;
     RECT  85.392 18.803 85.44 18.899 ;
     RECT  16.728 18.851 17.904 19.379 ;
     RECT  46.056 18.851 46.536 19.093 ;
     RECT  74.784 18.851 75.072 19.813 ;
     RECT  103.224 18.851 104.256 19.763 ;
     RECT  85.392 18.899 85.488 19.043 ;
     RECT  85.392 19.043 85.536 19.333 ;
     RECT  46.056 19.093 47.856 19.573 ;
     RECT  84.36 19.333 85.536 19.379 ;
     RECT  84.36 19.379 85.872 20.435 ;
     RECT  40.728 19.427 41.4 20.197 ;
     RECT  43.56 19.427 44.928 20.003 ;
     RECT  97.56 19.475 98.88 21.875 ;
     RECT  46.056 19.573 47.328 19.909 ;
     RECT  47.352 19.619 48.384 22.165 ;
     RECT  101.736 19.763 102.6 20.485 ;
     RECT  78.648 19.811 80.016 21.637 ;
     RECT  73.656 19.813 75.072 19.859 ;
     RECT  70.344 19.859 71.328 23.893 ;
     RECT  45.912 20.003 46.992 22.165 ;
     RECT  75.576 20.149 77.088 21.637 ;
     RECT  51.864 20.245 53.088 20.339 ;
     RECT  53.112 20.245 54.24 20.579 ;
     RECT  50.736 20.339 51 20.965 ;
     RECT  51.672 20.339 53.088 20.723 ;
     RECT  83.712 20.435 85.872 21.637 ;
     RECT  19.464 20.533 20.496 21.637 ;
     RECT  51.672 20.723 51.912 21.541 ;
     RECT  50.736 20.965 50.832 21.493 ;
     RECT  80.856 21.013 82.08 21.683 ;
     RECT  5.64 21.155 5.832 22.165 ;
     RECT  66.168 21.493 67.2 22.499 ;
     RECT  75.96 21.637 77.088 21.731 ;
     RECT  78.936 21.637 80.016 22.165 ;
     RECT  84.408 21.637 85.872 21.827 ;
     RECT  100.296 21.637 101.712 23.845 ;
     RECT  80.76 21.683 82.08 21.731 ;
     RECT  75.96 21.731 77.136 22.451 ;
     RECT  20.616 21.781 21.648 22.835 ;
     RECT  95.4 21.827 95.592 23.317 ;
     RECT  5.64 22.165 7.152 22.741 ;
     RECT  89.112 22.165 90.336 24.131 ;
     RECT  75.912 22.451 77.136 22.739 ;
     RECT  67.008 22.499 67.2 22.741 ;
     RECT  72.912 22.645 73.92 22.835 ;
     RECT  5.64 22.741 6.864 23.411 ;
     RECT  57.384 22.787 57.672 23.989 ;
     RECT  101.736 22.789 102.768 23.411 ;
     RECT  20.328 22.835 21.648 23.411 ;
     RECT  72.912 22.835 73.416 23.365 ;
     RECT  86.016 22.835 86.448 23.893 ;
     RECT  11.448 22.883 12.912 23.027 ;
     RECT  21.672 23.317 22.8 23.411 ;
     RECT  22.824 23.317 24 25.187 ;
     RECT  8.232 23.365 9.504 24.227 ;
     RECT  5.64 23.411 7.8 24.085 ;
     RECT  75.576 23.411 75.912 24.277 ;
     RECT  47.256 23.603 47.688 24.469 ;
     RECT  100.488 23.845 101.712 24.515 ;
     RECT  51.912 23.893 53.424 24.899 ;
     RECT  57.384 23.989 58.416 25.139 ;
     RECT  6.312 24.085 7.8 26.291 ;
     RECT  5.064 24.131 6.288 26.291 ;
     RECT  70.344 24.131 71.328 28.547 ;
     RECT  75.576 24.277 77.088 26.051 ;
     RECT  47.256 24.469 48.72 25.091 ;
     RECT  79.8 24.469 81.024 26.819 ;
     RECT  95.592 24.469 97.008 24.611 ;
     RECT  100.296 24.515 101.712 25.139 ;
     RECT  41.64 24.517 42.768 25.283 ;
     RECT  95.4 24.611 97.008 24.949 ;
     RECT  51.672 24.899 53.424 25.091 ;
     RECT  97.56 24.899 97.608 25.093 ;
     RECT  60.6 24.947 61.584 30.997 ;
     RECT  95.4 24.949 96.864 25.091 ;
     RECT  51.672 25.091 53.448 25.765 ;
     RECT  86.448 25.091 86.928 26.197 ;
     RECT  97.56 25.093 98.832 27.155 ;
     RECT  26.904 25.139 27.384 25.861 ;
     RECT  57.384 25.139 58.608 25.715 ;
     RECT  37.08 25.285 38.112 26.483 ;
     RECT  30.84 25.333 32.16 25.525 ;
     RECT  32.184 25.333 33.312 27.877 ;
     RECT  31.128 25.525 32.16 26.243 ;
     RECT  33.336 25.573 34.368 27.347 ;
     RECT  46.152 25.715 47.232 26.627 ;
     RECT  51.672 25.765 54.096 25.861 ;
     RECT  26.904 25.861 28.272 26.915 ;
     RECT  51.672 25.861 52.704 27.395 ;
     RECT  52.728 25.861 54.096 27.301 ;
     RECT  84.36 26.197 85.44 26.243 ;
     RECT  85.464 26.197 86.928 27.251 ;
     RECT  29.832 26.243 32.16 26.291 ;
     RECT  35.112 26.243 36.288 29.699 ;
     RECT  83.712 26.243 85.44 26.773 ;
     RECT  6.816 26.291 7.8 27.301 ;
     RECT  29.712 26.291 32.16 27.301 ;
     RECT  46.104 26.627 47.232 28.787 ;
     RECT  15.096 26.771 15.432 27.877 ;
     RECT  83.712 26.773 84.816 30.803 ;
     RECT  83.28 26.819 83.4 28.213 ;
     RECT  54.456 26.917 55.44 28.211 ;
     RECT  78.312 27.107 79.776 29.461 ;
     RECT  92.328 27.107 93.84 27.395 ;
     RECT  29.712 27.301 30.768 28.451 ;
     RECT  30.792 27.301 32.16 27.589 ;
     RECT  33.336 27.347 34.8 27.923 ;
     RECT  38.136 27.395 39.312 29.699 ;
     RECT  51.672 27.395 53.088 30.275 ;
     RECT  9.144 27.587 9.192 29.029 ;
     RECT  30.792 27.589 31.92 27.923 ;
     RECT  89.256 27.635 90.072 29.029 ;
     RECT  15.096 27.877 16.512 28.211 ;
     RECT  30.792 27.923 32.16 28.451 ;
     RECT  32.472 27.923 34.8 27.925 ;
     RECT  17.448 27.925 18.432 28.739 ;
     RECT  32.472 27.925 33.744 28.979 ;
     RECT  33.768 27.925 34.8 28.979 ;
     RECT  15.096 28.211 17.424 28.501 ;
     RECT  54.456 28.211 54.696 28.981 ;
     RECT  72.912 28.357 74.208 28.499 ;
     RECT  74.232 28.357 75.552 28.499 ;
     RECT  37.08 28.405 38.112 29.461 ;
     RECT  31.632 28.451 32.16 28.933 ;
     RECT  16.008 28.501 17.424 28.739 ;
     RECT  70.344 28.547 70.44 29.221 ;
     RECT  46.104 28.787 47.904 29.029 ;
     RECT  31.632 28.933 31.92 29.269 ;
     RECT  4.992 29.027 5.04 29.029 ;
     RECT  3.672 29.029 5.04 30.565 ;
     RECT  46.728 29.029 47.904 29.075 ;
     RECT  86.952 29.219 88.128 30.275 ;
     RECT  22.728 29.461 24 31.861 ;
     RECT  37.128 29.461 38.112 29.653 ;
     RECT  78.408 29.461 79.776 30.275 ;
     RECT  50.736 29.555 50.88 30.949 ;
     RECT  82.104 29.605 83.28 30.133 ;
     RECT  13.512 29.699 13.704 31.141 ;
     RECT  25.032 29.699 26.16 31.955 ;
     RECT  35.112 29.699 36.48 33.107 ;
     RECT  82.104 30.133 83.232 30.851 ;
     RECT  98.376 30.181 99.6 31.285 ;
     RECT  31.632 30.323 31.92 31.717 ;
     RECT  8.112 30.371 9.168 32.915 ;
     RECT  3.96 30.565 5.04 31.523 ;
     RECT  72.912 30.709 74.112 30.757 ;
     RECT  73.032 30.757 74.112 31.333 ;
     RECT  10.848 30.803 10.872 31.189 ;
     RECT  83.712 30.803 84.744 32.053 ;
     RECT  83.184 30.851 83.232 30.949 ;
     RECT  18.432 30.899 18.6 31.909 ;
     RECT  68.952 30.899 69 32.341 ;
     RECT  19.272 30.947 19.656 32.197 ;
     RECT  9.72 31.189 10.872 31.765 ;
     RECT  49.56 31.285 50.736 31.955 ;
     RECT  56.712 31.379 57.048 32.485 ;
     RECT  9.72 31.765 10.944 32.531 ;
     RECT  22.776 31.861 24 34.259 ;
     RECT  31.584 31.907 31.968 33.013 ;
     RECT  13.512 31.955 13.608 33.013 ;
     RECT  49.56 31.955 51 32.483 ;
     RECT  98.376 31.955 99.456 33.061 ;
     RECT  46.248 31.957 47.664 32.387 ;
     RECT  103.656 31.957 105 32.437 ;
     RECT  102.648 32.005 103.632 32.147 ;
     RECT  83.712 32.053 84.72 33.299 ;
     RECT  103.488 32.147 103.632 32.531 ;
     RECT  68.952 32.341 70.224 34.259 ;
     RECT  96.552 32.389 97.536 32.437 ;
     RECT  103.752 32.437 105 32.579 ;
     RECT  60.696 32.483 61.8 34.691 ;
     RECT  9.72 32.531 9.912 33.013 ;
     RECT  103.488 32.531 103.728 32.579 ;
     RECT  103.488 32.579 105 33.589 ;
     RECT  8.112 32.915 9.552 33.779 ;
     RECT  35.112 33.107 35.208 34.117 ;
     RECT  54 33.107 54.096 34.117 ;
     RECT  96.888 33.107 98.352 35.845 ;
     RECT  83.712 33.299 84.84 33.925 ;
     RECT  103.512 33.589 105 35.077 ;
     RECT  13.512 33.683 14.544 35.555 ;
     RECT  62.112 33.731 62.664 34.117 ;
     RECT  83.712 33.925 84.96 34.835 ;
     RECT  62.112 34.117 63.12 34.787 ;
     RECT  68.904 34.259 70.224 34.403 ;
     RECT  94.512 34.259 94.632 35.269 ;
     RECT  98.376 34.259 99.456 36.515 ;
     RECT  60.456 34.691 61.8 36.275 ;
     RECT  25.128 35.845 26.208 36.515 ;
     RECT  53.016 35.845 54 35.939 ;
     RECT  97.368 35.845 98.352 36.515 ;
     RECT  53.016 35.939 54.096 42.181 ;
     RECT  18.912 36.325 20.112 37.859 ;
     RECT  25.128 36.515 26.64 37.091 ;
     RECT  97.368 36.515 99.456 36.997 ;
     RECT  30.264 36.661 31.248 37.667 ;
     RECT  56.712 36.899 57.288 38.101 ;
     RECT  98.088 36.997 99.456 37.667 ;
     RECT  59.736 37.043 59.832 38.389 ;
     RECT  86.664 37.235 87.192 38.677 ;
     RECT  51.312 37.621 52.8 38.819 ;
     RECT  97.368 37.667 99.456 38.149 ;
     RECT  18.912 37.859 19.56 38.725 ;
     RECT  40.512 38.005 42 38.963 ;
     RECT  97.368 38.149 98.4 38.963 ;
     RECT  98.424 38.149 99.456 38.243 ;
     RECT  98.424 38.243 99.6 39.299 ;
     RECT  102.984 38.533 104.256 39.253 ;
     RECT  86.664 38.677 87.984 39.203 ;
     RECT  96.552 38.963 98.4 39.253 ;
     RECT  60.696 39.061 61.8 39.635 ;
     RECT  96.552 39.253 97.68 39.923 ;
     RECT  103.176 39.253 104.256 39.923 ;
     RECT  97.704 39.299 97.8 40.261 ;
     RECT  33.672 39.301 34.8 40.019 ;
     RECT  35.688 39.301 37.056 40.451 ;
     RECT  88.512 39.347 88.8 40.405 ;
     RECT  22.776 39.349 23.904 40.019 ;
     RECT  61.488 39.635 61.8 40.549 ;
     RECT  18.912 39.779 19.56 40.981 ;
     RECT  48.192 39.923 48.576 40.981 ;
     RECT  54.12 39.923 54.696 40.885 ;
     RECT  96.96 39.923 97.68 40.933 ;
     RECT  103.44 39.923 104.256 40.981 ;
     RECT  22.392 40.019 23.904 40.355 ;
     RECT  34.032 40.019 34.8 40.981 ;
     RECT  22.392 40.355 24 41.029 ;
     RECT  28.008 40.405 29.4 41.029 ;
     RECT  35.688 40.451 37.08 40.981 ;
     RECT  80.208 40.451 80.232 40.981 ;
     RECT  89.112 40.453 90.528 41.049 ;
     RECT  63.792 40.499 63.816 40.981 ;
     RECT  10.848 40.835 11.04 42.133 ;
     RECT  54.12 40.885 55.824 40.981 ;
     RECT  5.448 40.933 6.624 42.133 ;
     RECT  6.648 40.933 7.8 41.063 ;
     RECT  96.96 40.933 97.392 40.981 ;
     RECT  20.376 40.981 21.552 42.181 ;
     RECT  36.072 40.981 37.08 41.557 ;
     RECT  49.416 40.981 50.592 42.133 ;
     RECT  54.12 40.981 55.44 41.557 ;
     RECT  63.792 40.981 63.888 41.557 ;
     RECT  67.944 40.981 69.168 42.181 ;
     RECT  79.272 40.981 80.832 41.557 ;
     RECT  80.856 40.981 82.032 42.901 ;
     RECT  82.056 40.981 83.4 41.063 ;
     RECT  84.12 40.981 85.296 42.133 ;
     RECT  22.776 41.029 24 41.063 ;
     RECT  40.32 41.049 40.512 41.063 ;
     RECT  56.664 41.049 56.712 41.557 ;
     RECT  61.92 41.049 62.112 41.063 ;
     RECT  72.72 41.049 72.912 41.063 ;
     RECT  88.92 41.049 90.528 42.133 ;
     RECT  99.72 41.049 99.912 41.063 ;
     RECT  2.184 41.063 3.408 42.949 ;
     RECT  6.648 41.063 8.64 42.181 ;
     RECT  13.2 41.063 13.872 42.133 ;
     RECT  18.6 41.063 19.104 42.133 ;
     RECT  22.776 41.063 24.768 42.133 ;
     RECT  28.44 41.063 29.712 41.557 ;
     RECT  34.056 41.063 35.664 42.181 ;
     RECT  39.72 41.063 40.512 41.605 ;
     RECT  45.6 41.063 45.744 42.133 ;
     RECT  61.512 41.063 62.112 41.557 ;
     RECT  72.6 41.063 72.912 41.557 ;
     RECT  78 41.063 78.816 41.557 ;
     RECT  82.056 41.063 84.096 41.557 ;
     RECT  99.432 41.063 99.912 42.133 ;
     RECT  104.28 41.063 104.664 42.133 ;
     RECT  28.44 41.557 30 42.181 ;
     RECT  30.024 41.557 31.248 42.133 ;
     RECT  54.264 41.557 55.44 42.133 ;
     RECT  56.664 41.557 57.84 42.133 ;
     RECT  58.296 41.557 59.472 42.181 ;
     RECT  61.512 41.557 63.504 42.133 ;
     RECT  70.776 41.557 71.952 41.605 ;
     RECT  72.408 41.557 72.912 42.133 ;
     RECT  77.256 41.557 78.816 42.133 ;
     RECT  82.872 41.557 84.096 42.901 ;
     RECT  39.72 41.605 41.328 42.133 ;
     RECT  17.544 42.133 19.104 42.181 ;
     RECT  23.592 42.133 24.768 43.02 ;
     RECT  41.352 42.133 42.528 42.181 ;
     RECT  42.552 42.133 43.728 43.02 ;
     RECT  44.568 42.133 45.744 43.02 ;
     RECT  61.512 42.133 62.784 42.181 ;
     RECT  99.432 42.133 100.608 42.181 ;
     RECT  3.816 42.181 4.992 43.02 ;
     RECT  6.648 42.181 7.824 43.02 ;
     RECT  11.064 42.181 12.24 43.02 ;
     RECT  17.544 42.181 18.72 42.997 ;
     RECT  65.928 42.181 67.152 42.949 ;
     RECT  86.52 42.181 87.696 42.949 ;
     RECT  32.04 42.757 33.264 43.02 ;
     RECT  3.912 43.02 4.08 43.045 ;
     RECT  4.296 43.02 4.512 43.045 ;
     RECT  4.728 43.02 4.896 43.045 ;
     RECT  6.744 43.02 6.912 43.045 ;
     RECT  7.128 43.02 7.344 43.045 ;
     RECT  7.56 43.02 7.728 43.045 ;
     RECT  11.16 43.02 11.376 43.045 ;
     RECT  11.592 43.02 11.76 43.045 ;
     RECT  11.976 43.02 12.144 43.045 ;
     RECT  23.688 43.02 23.856 43.045 ;
     RECT  24.072 43.02 24.288 43.045 ;
     RECT  24.504 43.02 24.672 43.045 ;
     RECT  32.136 43.02 32.352 43.045 ;
     RECT  32.568 43.02 32.736 43.045 ;
     RECT  32.952 43.02 33.168 43.045 ;
     RECT  42.648 43.02 42.816 43.045 ;
     RECT  43.032 43.02 43.248 43.045 ;
     RECT  43.464 43.02 43.632 43.045 ;
     RECT  44.664 43.02 44.832 43.045 ;
     RECT  45.048 43.02 45.264 43.045 ;
     RECT  45.48 43.02 45.648 43.045 ;
  END
END qfd_c_ring514
END LIBRARY
